VERSION 5.8 ;
BUSBITCHARS "[]" ;
DIVIDERCHAR "/" ;
UNITS
    DATABASE MICRONS 1000 ;
END UNITS

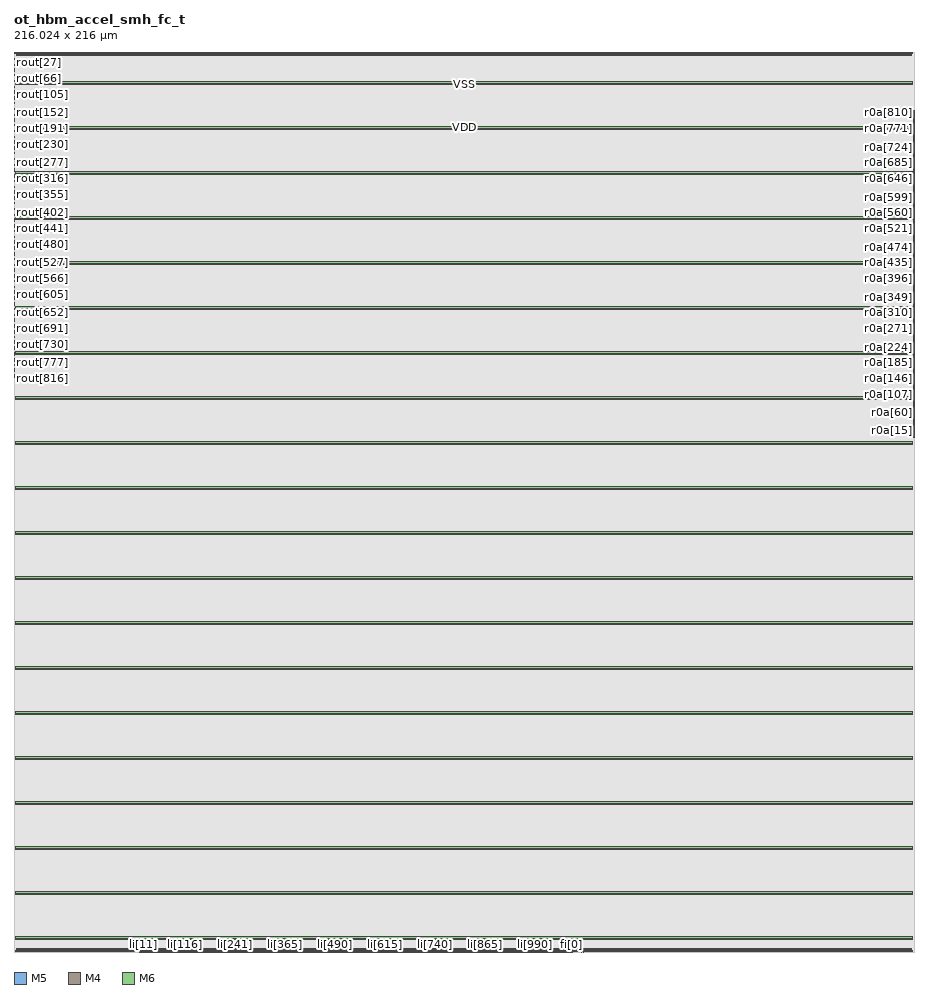
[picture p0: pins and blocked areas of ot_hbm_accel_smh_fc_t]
MACRO ot_hbm_accel_smh_fc_t
  FOREIGN ot_hbm_accel_smh_fc_t 0 0 ;
  CLASS BLOCK ;
  SIZE 216.024 BY 216 ;
  PIN clk
    DIRECTION INPUT ;
    USE SIGNAL ;
    PORT
      LAYER M5 ;
        RECT  136.128 0 136.152 0.192 ;
    END
  END clk
  PIN fi[0]
    DIRECTION INPUT ;
    USE SIGNAL ;
    PORT
      LAYER M5 ;
        RECT  133.872 0 133.896 0.192 ;
    END
  END fi[0]
  PIN fi[1]
    DIRECTION INPUT ;
    USE SIGNAL ;
    PORT
      LAYER M5 ;
        RECT  133.968 0 133.992 0.192 ;
    END
  END fi[1]
  PIN fi[2]
    DIRECTION INPUT ;
    USE SIGNAL ;
    PORT
      LAYER M5 ;
        RECT  134.064 0 134.088 0.192 ;
    END
  END fi[2]
  PIN li[0]
    DIRECTION INPUT ;
    USE SIGNAL ;
    PORT
      LAYER M5 ;
        RECT  30 0 30.024 0.192 ;
    END
  END li[0]
  PIN li[1000]
    DIRECTION INPUT ;
    USE SIGNAL ;
    PORT
      LAYER M5 ;
        RECT  126 0 126.024 0.192 ;
    END
  END li[1000]
  PIN li[1001]
    DIRECTION INPUT ;
    USE SIGNAL ;
    PORT
      LAYER M5 ;
        RECT  126.096 0 126.12 0.192 ;
    END
  END li[1001]
  PIN li[1002]
    DIRECTION INPUT ;
    USE SIGNAL ;
    PORT
      LAYER M5 ;
        RECT  126.192 0 126.216 0.192 ;
    END
  END li[1002]
  PIN li[1003]
    DIRECTION INPUT ;
    USE SIGNAL ;
    PORT
      LAYER M5 ;
        RECT  126.288 0 126.312 0.192 ;
    END
  END li[1003]
  PIN li[1004]
    DIRECTION INPUT ;
    USE SIGNAL ;
    PORT
      LAYER M5 ;
        RECT  126.384 0 126.408 0.192 ;
    END
  END li[1004]
  PIN li[1005]
    DIRECTION INPUT ;
    USE SIGNAL ;
    PORT
      LAYER M5 ;
        RECT  126.48 0 126.504 0.192 ;
    END
  END li[1005]
  PIN li[1006]
    DIRECTION INPUT ;
    USE SIGNAL ;
    PORT
      LAYER M5 ;
        RECT  126.576 0 126.6 0.192 ;
    END
  END li[1006]
  PIN li[1007]
    DIRECTION INPUT ;
    USE SIGNAL ;
    PORT
      LAYER M5 ;
        RECT  126.672 0 126.696 0.192 ;
    END
  END li[1007]
  PIN li[1008]
    DIRECTION INPUT ;
    USE SIGNAL ;
    PORT
      LAYER M5 ;
        RECT  126.768 0 126.792 0.192 ;
    END
  END li[1008]
  PIN li[1009]
    DIRECTION INPUT ;
    USE SIGNAL ;
    PORT
      LAYER M5 ;
        RECT  126.864 0 126.888 0.192 ;
    END
  END li[1009]
  PIN li[100]
    DIRECTION INPUT ;
    USE SIGNAL ;
    PORT
      LAYER M5 ;
        RECT  39.6 0 39.624 0.192 ;
    END
  END li[100]
  PIN li[1010]
    DIRECTION INPUT ;
    USE SIGNAL ;
    PORT
      LAYER M5 ;
        RECT  126.96 0 126.984 0.192 ;
    END
  END li[1010]
  PIN li[1011]
    DIRECTION INPUT ;
    USE SIGNAL ;
    PORT
      LAYER M5 ;
        RECT  127.056 0 127.08 0.192 ;
    END
  END li[1011]
  PIN li[1012]
    DIRECTION INPUT ;
    USE SIGNAL ;
    PORT
      LAYER M5 ;
        RECT  127.152 0 127.176 0.192 ;
    END
  END li[1012]
  PIN li[1013]
    DIRECTION INPUT ;
    USE SIGNAL ;
    PORT
      LAYER M5 ;
        RECT  127.248 0 127.272 0.192 ;
    END
  END li[1013]
  PIN li[1014]
    DIRECTION INPUT ;
    USE SIGNAL ;
    PORT
      LAYER M5 ;
        RECT  127.344 0 127.368 0.192 ;
    END
  END li[1014]
  PIN li[1015]
    DIRECTION INPUT ;
    USE SIGNAL ;
    PORT
      LAYER M5 ;
        RECT  127.44 0 127.464 0.192 ;
    END
  END li[1015]
  PIN li[1016]
    DIRECTION INPUT ;
    USE SIGNAL ;
    PORT
      LAYER M5 ;
        RECT  127.536 0 127.56 0.192 ;
    END
  END li[1016]
  PIN li[1017]
    DIRECTION INPUT ;
    USE SIGNAL ;
    PORT
      LAYER M5 ;
        RECT  127.632 0 127.656 0.192 ;
    END
  END li[1017]
  PIN li[1018]
    DIRECTION INPUT ;
    USE SIGNAL ;
    PORT
      LAYER M5 ;
        RECT  127.728 0 127.752 0.192 ;
    END
  END li[1018]
  PIN li[1019]
    DIRECTION INPUT ;
    USE SIGNAL ;
    PORT
      LAYER M5 ;
        RECT  127.824 0 127.848 0.192 ;
    END
  END li[1019]
  PIN li[101]
    DIRECTION INPUT ;
    USE SIGNAL ;
    PORT
      LAYER M5 ;
        RECT  39.696 0 39.72 0.192 ;
    END
  END li[101]
  PIN li[1020]
    DIRECTION INPUT ;
    USE SIGNAL ;
    PORT
      LAYER M5 ;
        RECT  127.92 0 127.944 0.192 ;
    END
  END li[1020]
  PIN li[1021]
    DIRECTION INPUT ;
    USE SIGNAL ;
    PORT
      LAYER M5 ;
        RECT  128.016 0 128.04 0.192 ;
    END
  END li[1021]
  PIN li[1022]
    DIRECTION INPUT ;
    USE SIGNAL ;
    PORT
      LAYER M5 ;
        RECT  128.112 0 128.136 0.192 ;
    END
  END li[1022]
  PIN li[1023]
    DIRECTION INPUT ;
    USE SIGNAL ;
    PORT
      LAYER M5 ;
        RECT  128.208 0 128.232 0.192 ;
    END
  END li[1023]
  PIN li[1024]
    DIRECTION INPUT ;
    USE SIGNAL ;
    PORT
      LAYER M5 ;
        RECT  128.304 0 128.328 0.192 ;
    END
  END li[1024]
  PIN li[1025]
    DIRECTION INPUT ;
    USE SIGNAL ;
    PORT
      LAYER M5 ;
        RECT  128.4 0 128.424 0.192 ;
    END
  END li[1025]
  PIN li[1026]
    DIRECTION INPUT ;
    USE SIGNAL ;
    PORT
      LAYER M5 ;
        RECT  128.496 0 128.52 0.192 ;
    END
  END li[1026]
  PIN li[1027]
    DIRECTION INPUT ;
    USE SIGNAL ;
    PORT
      LAYER M5 ;
        RECT  128.592 0 128.616 0.192 ;
    END
  END li[1027]
  PIN li[1028]
    DIRECTION INPUT ;
    USE SIGNAL ;
    PORT
      LAYER M5 ;
        RECT  128.688 0 128.712 0.192 ;
    END
  END li[1028]
  PIN li[1029]
    DIRECTION INPUT ;
    USE SIGNAL ;
    PORT
      LAYER M5 ;
        RECT  128.784 0 128.808 0.192 ;
    END
  END li[1029]
  PIN li[102]
    DIRECTION INPUT ;
    USE SIGNAL ;
    PORT
      LAYER M5 ;
        RECT  39.792 0 39.816 0.192 ;
    END
  END li[102]
  PIN li[1030]
    DIRECTION INPUT ;
    USE SIGNAL ;
    PORT
      LAYER M5 ;
        RECT  128.88 0 128.904 0.192 ;
    END
  END li[1030]
  PIN li[1031]
    DIRECTION INPUT ;
    USE SIGNAL ;
    PORT
      LAYER M5 ;
        RECT  128.976 0 129 0.192 ;
    END
  END li[1031]
  PIN li[1032]
    DIRECTION INPUT ;
    USE SIGNAL ;
    PORT
      LAYER M5 ;
        RECT  129.072 0 129.096 0.192 ;
    END
  END li[1032]
  PIN li[1033]
    DIRECTION INPUT ;
    USE SIGNAL ;
    PORT
      LAYER M5 ;
        RECT  129.168 0 129.192 0.192 ;
    END
  END li[1033]
  PIN li[1034]
    DIRECTION INPUT ;
    USE SIGNAL ;
    PORT
      LAYER M5 ;
        RECT  129.264 0 129.288 0.192 ;
    END
  END li[1034]
  PIN li[1035]
    DIRECTION INPUT ;
    USE SIGNAL ;
    PORT
      LAYER M5 ;
        RECT  129.36 0 129.384 0.192 ;
    END
  END li[1035]
  PIN li[1036]
    DIRECTION INPUT ;
    USE SIGNAL ;
    PORT
      LAYER M5 ;
        RECT  129.456 0 129.48 0.192 ;
    END
  END li[1036]
  PIN li[1037]
    DIRECTION INPUT ;
    USE SIGNAL ;
    PORT
      LAYER M5 ;
        RECT  129.552 0 129.576 0.192 ;
    END
  END li[1037]
  PIN li[1038]
    DIRECTION INPUT ;
    USE SIGNAL ;
    PORT
      LAYER M5 ;
        RECT  129.648 0 129.672 0.192 ;
    END
  END li[1038]
  PIN li[1039]
    DIRECTION INPUT ;
    USE SIGNAL ;
    PORT
      LAYER M5 ;
        RECT  129.744 0 129.768 0.192 ;
    END
  END li[1039]
  PIN li[103]
    DIRECTION INPUT ;
    USE SIGNAL ;
    PORT
      LAYER M5 ;
        RECT  39.888 0 39.912 0.192 ;
    END
  END li[103]
  PIN li[1040]
    DIRECTION INPUT ;
    USE SIGNAL ;
    PORT
      LAYER M5 ;
        RECT  129.84 0 129.864 0.192 ;
    END
  END li[1040]
  PIN li[1041]
    DIRECTION INPUT ;
    USE SIGNAL ;
    PORT
      LAYER M5 ;
        RECT  129.936 0 129.96 0.192 ;
    END
  END li[1041]
  PIN li[1042]
    DIRECTION INPUT ;
    USE SIGNAL ;
    PORT
      LAYER M5 ;
        RECT  130.032 0 130.056 0.192 ;
    END
  END li[1042]
  PIN li[1043]
    DIRECTION INPUT ;
    USE SIGNAL ;
    PORT
      LAYER M5 ;
        RECT  130.128 0 130.152 0.192 ;
    END
  END li[1043]
  PIN li[1044]
    DIRECTION INPUT ;
    USE SIGNAL ;
    PORT
      LAYER M5 ;
        RECT  130.224 0 130.248 0.192 ;
    END
  END li[1044]
  PIN li[1045]
    DIRECTION INPUT ;
    USE SIGNAL ;
    PORT
      LAYER M5 ;
        RECT  130.32 0 130.344 0.192 ;
    END
  END li[1045]
  PIN li[1046]
    DIRECTION INPUT ;
    USE SIGNAL ;
    PORT
      LAYER M5 ;
        RECT  130.416 0 130.44 0.192 ;
    END
  END li[1046]
  PIN li[1047]
    DIRECTION INPUT ;
    USE SIGNAL ;
    PORT
      LAYER M5 ;
        RECT  130.512 0 130.536 0.192 ;
    END
  END li[1047]
  PIN li[1048]
    DIRECTION INPUT ;
    USE SIGNAL ;
    PORT
      LAYER M5 ;
        RECT  130.608 0 130.632 0.192 ;
    END
  END li[1048]
  PIN li[1049]
    DIRECTION INPUT ;
    USE SIGNAL ;
    PORT
      LAYER M5 ;
        RECT  130.704 0 130.728 0.192 ;
    END
  END li[1049]
  PIN li[104]
    DIRECTION INPUT ;
    USE SIGNAL ;
    PORT
      LAYER M5 ;
        RECT  39.984 0 40.008 0.192 ;
    END
  END li[104]
  PIN li[1050]
    DIRECTION INPUT ;
    USE SIGNAL ;
    PORT
      LAYER M5 ;
        RECT  130.8 0 130.824 0.192 ;
    END
  END li[1050]
  PIN li[1051]
    DIRECTION INPUT ;
    USE SIGNAL ;
    PORT
      LAYER M5 ;
        RECT  130.896 0 130.92 0.192 ;
    END
  END li[1051]
  PIN li[1052]
    DIRECTION INPUT ;
    USE SIGNAL ;
    PORT
      LAYER M5 ;
        RECT  130.992 0 131.016 0.192 ;
    END
  END li[1052]
  PIN li[1053]
    DIRECTION INPUT ;
    USE SIGNAL ;
    PORT
      LAYER M5 ;
        RECT  131.088 0 131.112 0.192 ;
    END
  END li[1053]
  PIN li[1054]
    DIRECTION INPUT ;
    USE SIGNAL ;
    PORT
      LAYER M5 ;
        RECT  131.184 0 131.208 0.192 ;
    END
  END li[1054]
  PIN li[1055]
    DIRECTION INPUT ;
    USE SIGNAL ;
    PORT
      LAYER M5 ;
        RECT  131.28 0 131.304 0.192 ;
    END
  END li[1055]
  PIN li[1056]
    DIRECTION INPUT ;
    USE SIGNAL ;
    PORT
      LAYER M5 ;
        RECT  131.376 0 131.4 0.192 ;
    END
  END li[1056]
  PIN li[1057]
    DIRECTION INPUT ;
    USE SIGNAL ;
    PORT
      LAYER M5 ;
        RECT  131.472 0 131.496 0.192 ;
    END
  END li[1057]
  PIN li[1058]
    DIRECTION INPUT ;
    USE SIGNAL ;
    PORT
      LAYER M5 ;
        RECT  131.568 0 131.592 0.192 ;
    END
  END li[1058]
  PIN li[1059]
    DIRECTION INPUT ;
    USE SIGNAL ;
    PORT
      LAYER M5 ;
        RECT  131.664 0 131.688 0.192 ;
    END
  END li[1059]
  PIN li[105]
    DIRECTION INPUT ;
    USE SIGNAL ;
    PORT
      LAYER M5 ;
        RECT  40.08 0 40.104 0.192 ;
    END
  END li[105]
  PIN li[1060]
    DIRECTION INPUT ;
    USE SIGNAL ;
    PORT
      LAYER M5 ;
        RECT  131.76 0 131.784 0.192 ;
    END
  END li[1060]
  PIN li[1061]
    DIRECTION INPUT ;
    USE SIGNAL ;
    PORT
      LAYER M5 ;
        RECT  131.856 0 131.88 0.192 ;
    END
  END li[1061]
  PIN li[1062]
    DIRECTION INPUT ;
    USE SIGNAL ;
    PORT
      LAYER M5 ;
        RECT  131.952 0 131.976 0.192 ;
    END
  END li[1062]
  PIN li[1063]
    DIRECTION INPUT ;
    USE SIGNAL ;
    PORT
      LAYER M5 ;
        RECT  132.048 0 132.072 0.192 ;
    END
  END li[1063]
  PIN li[1064]
    DIRECTION INPUT ;
    USE SIGNAL ;
    PORT
      LAYER M5 ;
        RECT  132.144 0 132.168 0.192 ;
    END
  END li[1064]
  PIN li[1065]
    DIRECTION INPUT ;
    USE SIGNAL ;
    PORT
      LAYER M5 ;
        RECT  132.24 0 132.264 0.192 ;
    END
  END li[1065]
  PIN li[1066]
    DIRECTION INPUT ;
    USE SIGNAL ;
    PORT
      LAYER M5 ;
        RECT  132.336 0 132.36 0.192 ;
    END
  END li[1066]
  PIN li[1067]
    DIRECTION INPUT ;
    USE SIGNAL ;
    PORT
      LAYER M5 ;
        RECT  132.432 0 132.456 0.192 ;
    END
  END li[1067]
  PIN li[1068]
    DIRECTION INPUT ;
    USE SIGNAL ;
    PORT
      LAYER M5 ;
        RECT  132.528 0 132.552 0.192 ;
    END
  END li[1068]
  PIN li[1069]
    DIRECTION INPUT ;
    USE SIGNAL ;
    PORT
      LAYER M5 ;
        RECT  132.624 0 132.648 0.192 ;
    END
  END li[1069]
  PIN li[106]
    DIRECTION INPUT ;
    USE SIGNAL ;
    PORT
      LAYER M5 ;
        RECT  40.176 0 40.2 0.192 ;
    END
  END li[106]
  PIN li[1070]
    DIRECTION INPUT ;
    USE SIGNAL ;
    PORT
      LAYER M5 ;
        RECT  132.72 0 132.744 0.192 ;
    END
  END li[1070]
  PIN li[1071]
    DIRECTION INPUT ;
    USE SIGNAL ;
    PORT
      LAYER M5 ;
        RECT  132.816 0 132.84 0.192 ;
    END
  END li[1071]
  PIN li[1072]
    DIRECTION INPUT ;
    USE SIGNAL ;
    PORT
      LAYER M5 ;
        RECT  132.912 0 132.936 0.192 ;
    END
  END li[1072]
  PIN li[1073]
    DIRECTION INPUT ;
    USE SIGNAL ;
    PORT
      LAYER M5 ;
        RECT  133.008 0 133.032 0.192 ;
    END
  END li[1073]
  PIN li[1074]
    DIRECTION INPUT ;
    USE SIGNAL ;
    PORT
      LAYER M5 ;
        RECT  133.104 0 133.128 0.192 ;
    END
  END li[1074]
  PIN li[1075]
    DIRECTION INPUT ;
    USE SIGNAL ;
    PORT
      LAYER M5 ;
        RECT  133.2 0 133.224 0.192 ;
    END
  END li[1075]
  PIN li[1076]
    DIRECTION INPUT ;
    USE SIGNAL ;
    PORT
      LAYER M5 ;
        RECT  133.296 0 133.32 0.192 ;
    END
  END li[1076]
  PIN li[1077]
    DIRECTION INPUT ;
    USE SIGNAL ;
    PORT
      LAYER M5 ;
        RECT  133.392 0 133.416 0.192 ;
    END
  END li[1077]
  PIN li[1078]
    DIRECTION INPUT ;
    USE SIGNAL ;
    PORT
      LAYER M5 ;
        RECT  133.488 0 133.512 0.192 ;
    END
  END li[1078]
  PIN li[1079]
    DIRECTION INPUT ;
    USE SIGNAL ;
    PORT
      LAYER M5 ;
        RECT  133.584 0 133.608 0.192 ;
    END
  END li[1079]
  PIN li[107]
    DIRECTION INPUT ;
    USE SIGNAL ;
    PORT
      LAYER M5 ;
        RECT  40.272 0 40.296 0.192 ;
    END
  END li[107]
  PIN li[1080]
    DIRECTION INPUT ;
    USE SIGNAL ;
    PORT
      LAYER M5 ;
        RECT  133.68 0 133.704 0.192 ;
    END
  END li[1080]
  PIN li[1081]
    DIRECTION INPUT ;
    USE SIGNAL ;
    PORT
      LAYER M5 ;
        RECT  133.776 0 133.8 0.192 ;
    END
  END li[1081]
  PIN li[108]
    DIRECTION INPUT ;
    USE SIGNAL ;
    PORT
      LAYER M5 ;
        RECT  40.368 0 40.392 0.192 ;
    END
  END li[108]
  PIN li[109]
    DIRECTION INPUT ;
    USE SIGNAL ;
    PORT
      LAYER M5 ;
        RECT  40.464 0 40.488 0.192 ;
    END
  END li[109]
  PIN li[10]
    DIRECTION INPUT ;
    USE SIGNAL ;
    PORT
      LAYER M5 ;
        RECT  30.96 0 30.984 0.192 ;
    END
  END li[10]
  PIN li[110]
    DIRECTION INPUT ;
    USE SIGNAL ;
    PORT
      LAYER M5 ;
        RECT  40.56 0 40.584 0.192 ;
    END
  END li[110]
  PIN li[111]
    DIRECTION INPUT ;
    USE SIGNAL ;
    PORT
      LAYER M5 ;
        RECT  40.656 0 40.68 0.192 ;
    END
  END li[111]
  PIN li[112]
    DIRECTION INPUT ;
    USE SIGNAL ;
    PORT
      LAYER M5 ;
        RECT  40.752 0 40.776 0.192 ;
    END
  END li[112]
  PIN li[113]
    DIRECTION INPUT ;
    USE SIGNAL ;
    PORT
      LAYER M5 ;
        RECT  40.848 0 40.872 0.192 ;
    END
  END li[113]
  PIN li[114]
    DIRECTION INPUT ;
    USE SIGNAL ;
    PORT
      LAYER M5 ;
        RECT  40.944 0 40.968 0.192 ;
    END
  END li[114]
  PIN li[115]
    DIRECTION INPUT ;
    USE SIGNAL ;
    PORT
      LAYER M5 ;
        RECT  41.04 0 41.064 0.192 ;
    END
  END li[115]
  PIN li[116]
    DIRECTION INPUT ;
    USE SIGNAL ;
    PORT
      LAYER M5 ;
        RECT  41.136 0 41.16 0.192 ;
    END
  END li[116]
  PIN li[117]
    DIRECTION INPUT ;
    USE SIGNAL ;
    PORT
      LAYER M5 ;
        RECT  41.232 0 41.256 0.192 ;
    END
  END li[117]
  PIN li[118]
    DIRECTION INPUT ;
    USE SIGNAL ;
    PORT
      LAYER M5 ;
        RECT  41.328 0 41.352 0.192 ;
    END
  END li[118]
  PIN li[119]
    DIRECTION INPUT ;
    USE SIGNAL ;
    PORT
      LAYER M5 ;
        RECT  41.424 0 41.448 0.192 ;
    END
  END li[119]
  PIN li[11]
    DIRECTION INPUT ;
    USE SIGNAL ;
    PORT
      LAYER M5 ;
        RECT  31.056 0 31.08 0.192 ;
    END
  END li[11]
  PIN li[120]
    DIRECTION INPUT ;
    USE SIGNAL ;
    PORT
      LAYER M5 ;
        RECT  41.52 0 41.544 0.192 ;
    END
  END li[120]
  PIN li[121]
    DIRECTION INPUT ;
    USE SIGNAL ;
    PORT
      LAYER M5 ;
        RECT  41.616 0 41.64 0.192 ;
    END
  END li[121]
  PIN li[122]
    DIRECTION INPUT ;
    USE SIGNAL ;
    PORT
      LAYER M5 ;
        RECT  41.712 0 41.736 0.192 ;
    END
  END li[122]
  PIN li[123]
    DIRECTION INPUT ;
    USE SIGNAL ;
    PORT
      LAYER M5 ;
        RECT  41.808 0 41.832 0.192 ;
    END
  END li[123]
  PIN li[124]
    DIRECTION INPUT ;
    USE SIGNAL ;
    PORT
      LAYER M5 ;
        RECT  41.904 0 41.928 0.192 ;
    END
  END li[124]
  PIN li[125]
    DIRECTION INPUT ;
    USE SIGNAL ;
    PORT
      LAYER M5 ;
        RECT  42 0 42.024 0.192 ;
    END
  END li[125]
  PIN li[126]
    DIRECTION INPUT ;
    USE SIGNAL ;
    PORT
      LAYER M5 ;
        RECT  42.096 0 42.12 0.192 ;
    END
  END li[126]
  PIN li[127]
    DIRECTION INPUT ;
    USE SIGNAL ;
    PORT
      LAYER M5 ;
        RECT  42.192 0 42.216 0.192 ;
    END
  END li[127]
  PIN li[128]
    DIRECTION INPUT ;
    USE SIGNAL ;
    PORT
      LAYER M5 ;
        RECT  42.288 0 42.312 0.192 ;
    END
  END li[128]
  PIN li[129]
    DIRECTION INPUT ;
    USE SIGNAL ;
    PORT
      LAYER M5 ;
        RECT  42.384 0 42.408 0.192 ;
    END
  END li[129]
  PIN li[12]
    DIRECTION INPUT ;
    USE SIGNAL ;
    PORT
      LAYER M5 ;
        RECT  31.152 0 31.176 0.192 ;
    END
  END li[12]
  PIN li[130]
    DIRECTION INPUT ;
    USE SIGNAL ;
    PORT
      LAYER M5 ;
        RECT  42.48 0 42.504 0.192 ;
    END
  END li[130]
  PIN li[131]
    DIRECTION INPUT ;
    USE SIGNAL ;
    PORT
      LAYER M5 ;
        RECT  42.576 0 42.6 0.192 ;
    END
  END li[131]
  PIN li[132]
    DIRECTION INPUT ;
    USE SIGNAL ;
    PORT
      LAYER M5 ;
        RECT  42.672 0 42.696 0.192 ;
    END
  END li[132]
  PIN li[133]
    DIRECTION INPUT ;
    USE SIGNAL ;
    PORT
      LAYER M5 ;
        RECT  42.768 0 42.792 0.192 ;
    END
  END li[133]
  PIN li[134]
    DIRECTION INPUT ;
    USE SIGNAL ;
    PORT
      LAYER M5 ;
        RECT  42.864 0 42.888 0.192 ;
    END
  END li[134]
  PIN li[135]
    DIRECTION INPUT ;
    USE SIGNAL ;
    PORT
      LAYER M5 ;
        RECT  42.96 0 42.984 0.192 ;
    END
  END li[135]
  PIN li[136]
    DIRECTION INPUT ;
    USE SIGNAL ;
    PORT
      LAYER M5 ;
        RECT  43.056 0 43.08 0.192 ;
    END
  END li[136]
  PIN li[137]
    DIRECTION INPUT ;
    USE SIGNAL ;
    PORT
      LAYER M5 ;
        RECT  43.152 0 43.176 0.192 ;
    END
  END li[137]
  PIN li[138]
    DIRECTION INPUT ;
    USE SIGNAL ;
    PORT
      LAYER M5 ;
        RECT  43.248 0 43.272 0.192 ;
    END
  END li[138]
  PIN li[139]
    DIRECTION INPUT ;
    USE SIGNAL ;
    PORT
      LAYER M5 ;
        RECT  43.344 0 43.368 0.192 ;
    END
  END li[139]
  PIN li[13]
    DIRECTION INPUT ;
    USE SIGNAL ;
    PORT
      LAYER M5 ;
        RECT  31.248 0 31.272 0.192 ;
    END
  END li[13]
  PIN li[140]
    DIRECTION INPUT ;
    USE SIGNAL ;
    PORT
      LAYER M5 ;
        RECT  43.44 0 43.464 0.192 ;
    END
  END li[140]
  PIN li[141]
    DIRECTION INPUT ;
    USE SIGNAL ;
    PORT
      LAYER M5 ;
        RECT  43.536 0 43.56 0.192 ;
    END
  END li[141]
  PIN li[142]
    DIRECTION INPUT ;
    USE SIGNAL ;
    PORT
      LAYER M5 ;
        RECT  43.632 0 43.656 0.192 ;
    END
  END li[142]
  PIN li[143]
    DIRECTION INPUT ;
    USE SIGNAL ;
    PORT
      LAYER M5 ;
        RECT  43.728 0 43.752 0.192 ;
    END
  END li[143]
  PIN li[144]
    DIRECTION INPUT ;
    USE SIGNAL ;
    PORT
      LAYER M5 ;
        RECT  43.824 0 43.848 0.192 ;
    END
  END li[144]
  PIN li[145]
    DIRECTION INPUT ;
    USE SIGNAL ;
    PORT
      LAYER M5 ;
        RECT  43.92 0 43.944 0.192 ;
    END
  END li[145]
  PIN li[146]
    DIRECTION INPUT ;
    USE SIGNAL ;
    PORT
      LAYER M5 ;
        RECT  44.016 0 44.04 0.192 ;
    END
  END li[146]
  PIN li[147]
    DIRECTION INPUT ;
    USE SIGNAL ;
    PORT
      LAYER M5 ;
        RECT  44.112 0 44.136 0.192 ;
    END
  END li[147]
  PIN li[148]
    DIRECTION INPUT ;
    USE SIGNAL ;
    PORT
      LAYER M5 ;
        RECT  44.208 0 44.232 0.192 ;
    END
  END li[148]
  PIN li[149]
    DIRECTION INPUT ;
    USE SIGNAL ;
    PORT
      LAYER M5 ;
        RECT  44.304 0 44.328 0.192 ;
    END
  END li[149]
  PIN li[14]
    DIRECTION INPUT ;
    USE SIGNAL ;
    PORT
      LAYER M5 ;
        RECT  31.344 0 31.368 0.192 ;
    END
  END li[14]
  PIN li[150]
    DIRECTION INPUT ;
    USE SIGNAL ;
    PORT
      LAYER M5 ;
        RECT  44.4 0 44.424 0.192 ;
    END
  END li[150]
  PIN li[151]
    DIRECTION INPUT ;
    USE SIGNAL ;
    PORT
      LAYER M5 ;
        RECT  44.496 0 44.52 0.192 ;
    END
  END li[151]
  PIN li[152]
    DIRECTION INPUT ;
    USE SIGNAL ;
    PORT
      LAYER M5 ;
        RECT  44.592 0 44.616 0.192 ;
    END
  END li[152]
  PIN li[153]
    DIRECTION INPUT ;
    USE SIGNAL ;
    PORT
      LAYER M5 ;
        RECT  44.688 0 44.712 0.192 ;
    END
  END li[153]
  PIN li[154]
    DIRECTION INPUT ;
    USE SIGNAL ;
    PORT
      LAYER M5 ;
        RECT  44.784 0 44.808 0.192 ;
    END
  END li[154]
  PIN li[155]
    DIRECTION INPUT ;
    USE SIGNAL ;
    PORT
      LAYER M5 ;
        RECT  44.88 0 44.904 0.192 ;
    END
  END li[155]
  PIN li[156]
    DIRECTION INPUT ;
    USE SIGNAL ;
    PORT
      LAYER M5 ;
        RECT  44.976 0 45 0.192 ;
    END
  END li[156]
  PIN li[157]
    DIRECTION INPUT ;
    USE SIGNAL ;
    PORT
      LAYER M5 ;
        RECT  45.072 0 45.096 0.192 ;
    END
  END li[157]
  PIN li[158]
    DIRECTION INPUT ;
    USE SIGNAL ;
    PORT
      LAYER M5 ;
        RECT  45.168 0 45.192 0.192 ;
    END
  END li[158]
  PIN li[159]
    DIRECTION INPUT ;
    USE SIGNAL ;
    PORT
      LAYER M5 ;
        RECT  45.264 0 45.288 0.192 ;
    END
  END li[159]
  PIN li[15]
    DIRECTION INPUT ;
    USE SIGNAL ;
    PORT
      LAYER M5 ;
        RECT  31.44 0 31.464 0.192 ;
    END
  END li[15]
  PIN li[160]
    DIRECTION INPUT ;
    USE SIGNAL ;
    PORT
      LAYER M5 ;
        RECT  45.36 0 45.384 0.192 ;
    END
  END li[160]
  PIN li[161]
    DIRECTION INPUT ;
    USE SIGNAL ;
    PORT
      LAYER M5 ;
        RECT  45.456 0 45.48 0.192 ;
    END
  END li[161]
  PIN li[162]
    DIRECTION INPUT ;
    USE SIGNAL ;
    PORT
      LAYER M5 ;
        RECT  45.552 0 45.576 0.192 ;
    END
  END li[162]
  PIN li[163]
    DIRECTION INPUT ;
    USE SIGNAL ;
    PORT
      LAYER M5 ;
        RECT  45.648 0 45.672 0.192 ;
    END
  END li[163]
  PIN li[164]
    DIRECTION INPUT ;
    USE SIGNAL ;
    PORT
      LAYER M5 ;
        RECT  45.744 0 45.768 0.192 ;
    END
  END li[164]
  PIN li[165]
    DIRECTION INPUT ;
    USE SIGNAL ;
    PORT
      LAYER M5 ;
        RECT  45.84 0 45.864 0.192 ;
    END
  END li[165]
  PIN li[166]
    DIRECTION INPUT ;
    USE SIGNAL ;
    PORT
      LAYER M5 ;
        RECT  45.936 0 45.96 0.192 ;
    END
  END li[166]
  PIN li[167]
    DIRECTION INPUT ;
    USE SIGNAL ;
    PORT
      LAYER M5 ;
        RECT  46.032 0 46.056 0.192 ;
    END
  END li[167]
  PIN li[168]
    DIRECTION INPUT ;
    USE SIGNAL ;
    PORT
      LAYER M5 ;
        RECT  46.128 0 46.152 0.192 ;
    END
  END li[168]
  PIN li[169]
    DIRECTION INPUT ;
    USE SIGNAL ;
    PORT
      LAYER M5 ;
        RECT  46.224 0 46.248 0.192 ;
    END
  END li[169]
  PIN li[16]
    DIRECTION INPUT ;
    USE SIGNAL ;
    PORT
      LAYER M5 ;
        RECT  31.536 0 31.56 0.192 ;
    END
  END li[16]
  PIN li[170]
    DIRECTION INPUT ;
    USE SIGNAL ;
    PORT
      LAYER M5 ;
        RECT  46.32 0 46.344 0.192 ;
    END
  END li[170]
  PIN li[171]
    DIRECTION INPUT ;
    USE SIGNAL ;
    PORT
      LAYER M5 ;
        RECT  46.416 0 46.44 0.192 ;
    END
  END li[171]
  PIN li[172]
    DIRECTION INPUT ;
    USE SIGNAL ;
    PORT
      LAYER M5 ;
        RECT  46.512 0 46.536 0.192 ;
    END
  END li[172]
  PIN li[173]
    DIRECTION INPUT ;
    USE SIGNAL ;
    PORT
      LAYER M5 ;
        RECT  46.608 0 46.632 0.192 ;
    END
  END li[173]
  PIN li[174]
    DIRECTION INPUT ;
    USE SIGNAL ;
    PORT
      LAYER M5 ;
        RECT  46.704 0 46.728 0.192 ;
    END
  END li[174]
  PIN li[175]
    DIRECTION INPUT ;
    USE SIGNAL ;
    PORT
      LAYER M5 ;
        RECT  46.8 0 46.824 0.192 ;
    END
  END li[175]
  PIN li[176]
    DIRECTION INPUT ;
    USE SIGNAL ;
    PORT
      LAYER M5 ;
        RECT  46.896 0 46.92 0.192 ;
    END
  END li[176]
  PIN li[177]
    DIRECTION INPUT ;
    USE SIGNAL ;
    PORT
      LAYER M5 ;
        RECT  46.992 0 47.016 0.192 ;
    END
  END li[177]
  PIN li[178]
    DIRECTION INPUT ;
    USE SIGNAL ;
    PORT
      LAYER M5 ;
        RECT  47.088 0 47.112 0.192 ;
    END
  END li[178]
  PIN li[179]
    DIRECTION INPUT ;
    USE SIGNAL ;
    PORT
      LAYER M5 ;
        RECT  47.184 0 47.208 0.192 ;
    END
  END li[179]
  PIN li[17]
    DIRECTION INPUT ;
    USE SIGNAL ;
    PORT
      LAYER M5 ;
        RECT  31.632 0 31.656 0.192 ;
    END
  END li[17]
  PIN li[180]
    DIRECTION INPUT ;
    USE SIGNAL ;
    PORT
      LAYER M5 ;
        RECT  47.28 0 47.304 0.192 ;
    END
  END li[180]
  PIN li[181]
    DIRECTION INPUT ;
    USE SIGNAL ;
    PORT
      LAYER M5 ;
        RECT  47.376 0 47.4 0.192 ;
    END
  END li[181]
  PIN li[182]
    DIRECTION INPUT ;
    USE SIGNAL ;
    PORT
      LAYER M5 ;
        RECT  47.472 0 47.496 0.192 ;
    END
  END li[182]
  PIN li[183]
    DIRECTION INPUT ;
    USE SIGNAL ;
    PORT
      LAYER M5 ;
        RECT  47.568 0 47.592 0.192 ;
    END
  END li[183]
  PIN li[184]
    DIRECTION INPUT ;
    USE SIGNAL ;
    PORT
      LAYER M5 ;
        RECT  47.664 0 47.688 0.192 ;
    END
  END li[184]
  PIN li[185]
    DIRECTION INPUT ;
    USE SIGNAL ;
    PORT
      LAYER M5 ;
        RECT  47.76 0 47.784 0.192 ;
    END
  END li[185]
  PIN li[186]
    DIRECTION INPUT ;
    USE SIGNAL ;
    PORT
      LAYER M5 ;
        RECT  47.856 0 47.88 0.192 ;
    END
  END li[186]
  PIN li[187]
    DIRECTION INPUT ;
    USE SIGNAL ;
    PORT
      LAYER M5 ;
        RECT  47.952 0 47.976 0.192 ;
    END
  END li[187]
  PIN li[188]
    DIRECTION INPUT ;
    USE SIGNAL ;
    PORT
      LAYER M5 ;
        RECT  48.048 0 48.072 0.192 ;
    END
  END li[188]
  PIN li[189]
    DIRECTION INPUT ;
    USE SIGNAL ;
    PORT
      LAYER M5 ;
        RECT  48.144 0 48.168 0.192 ;
    END
  END li[189]
  PIN li[18]
    DIRECTION INPUT ;
    USE SIGNAL ;
    PORT
      LAYER M5 ;
        RECT  31.728 0 31.752 0.192 ;
    END
  END li[18]
  PIN li[190]
    DIRECTION INPUT ;
    USE SIGNAL ;
    PORT
      LAYER M5 ;
        RECT  48.24 0 48.264 0.192 ;
    END
  END li[190]
  PIN li[191]
    DIRECTION INPUT ;
    USE SIGNAL ;
    PORT
      LAYER M5 ;
        RECT  48.336 0 48.36 0.192 ;
    END
  END li[191]
  PIN li[192]
    DIRECTION INPUT ;
    USE SIGNAL ;
    PORT
      LAYER M5 ;
        RECT  48.432 0 48.456 0.192 ;
    END
  END li[192]
  PIN li[193]
    DIRECTION INPUT ;
    USE SIGNAL ;
    PORT
      LAYER M5 ;
        RECT  48.528 0 48.552 0.192 ;
    END
  END li[193]
  PIN li[194]
    DIRECTION INPUT ;
    USE SIGNAL ;
    PORT
      LAYER M5 ;
        RECT  48.624 0 48.648 0.192 ;
    END
  END li[194]
  PIN li[195]
    DIRECTION INPUT ;
    USE SIGNAL ;
    PORT
      LAYER M5 ;
        RECT  48.72 0 48.744 0.192 ;
    END
  END li[195]
  PIN li[196]
    DIRECTION INPUT ;
    USE SIGNAL ;
    PORT
      LAYER M5 ;
        RECT  48.816 0 48.84 0.192 ;
    END
  END li[196]
  PIN li[197]
    DIRECTION INPUT ;
    USE SIGNAL ;
    PORT
      LAYER M5 ;
        RECT  48.912 0 48.936 0.192 ;
    END
  END li[197]
  PIN li[198]
    DIRECTION INPUT ;
    USE SIGNAL ;
    PORT
      LAYER M5 ;
        RECT  49.008 0 49.032 0.192 ;
    END
  END li[198]
  PIN li[199]
    DIRECTION INPUT ;
    USE SIGNAL ;
    PORT
      LAYER M5 ;
        RECT  49.104 0 49.128 0.192 ;
    END
  END li[199]
  PIN li[19]
    DIRECTION INPUT ;
    USE SIGNAL ;
    PORT
      LAYER M5 ;
        RECT  31.824 0 31.848 0.192 ;
    END
  END li[19]
  PIN li[1]
    DIRECTION INPUT ;
    USE SIGNAL ;
    PORT
      LAYER M5 ;
        RECT  30.096 0 30.12 0.192 ;
    END
  END li[1]
  PIN li[200]
    DIRECTION INPUT ;
    USE SIGNAL ;
    PORT
      LAYER M5 ;
        RECT  49.2 0 49.224 0.192 ;
    END
  END li[200]
  PIN li[201]
    DIRECTION INPUT ;
    USE SIGNAL ;
    PORT
      LAYER M5 ;
        RECT  49.296 0 49.32 0.192 ;
    END
  END li[201]
  PIN li[202]
    DIRECTION INPUT ;
    USE SIGNAL ;
    PORT
      LAYER M5 ;
        RECT  49.392 0 49.416 0.192 ;
    END
  END li[202]
  PIN li[203]
    DIRECTION INPUT ;
    USE SIGNAL ;
    PORT
      LAYER M5 ;
        RECT  49.488 0 49.512 0.192 ;
    END
  END li[203]
  PIN li[204]
    DIRECTION INPUT ;
    USE SIGNAL ;
    PORT
      LAYER M5 ;
        RECT  49.584 0 49.608 0.192 ;
    END
  END li[204]
  PIN li[205]
    DIRECTION INPUT ;
    USE SIGNAL ;
    PORT
      LAYER M5 ;
        RECT  49.68 0 49.704 0.192 ;
    END
  END li[205]
  PIN li[206]
    DIRECTION INPUT ;
    USE SIGNAL ;
    PORT
      LAYER M5 ;
        RECT  49.776 0 49.8 0.192 ;
    END
  END li[206]
  PIN li[207]
    DIRECTION INPUT ;
    USE SIGNAL ;
    PORT
      LAYER M5 ;
        RECT  49.872 0 49.896 0.192 ;
    END
  END li[207]
  PIN li[208]
    DIRECTION INPUT ;
    USE SIGNAL ;
    PORT
      LAYER M5 ;
        RECT  49.968 0 49.992 0.192 ;
    END
  END li[208]
  PIN li[209]
    DIRECTION INPUT ;
    USE SIGNAL ;
    PORT
      LAYER M5 ;
        RECT  50.064 0 50.088 0.192 ;
    END
  END li[209]
  PIN li[20]
    DIRECTION INPUT ;
    USE SIGNAL ;
    PORT
      LAYER M5 ;
        RECT  31.92 0 31.944 0.192 ;
    END
  END li[20]
  PIN li[210]
    DIRECTION INPUT ;
    USE SIGNAL ;
    PORT
      LAYER M5 ;
        RECT  50.16 0 50.184 0.192 ;
    END
  END li[210]
  PIN li[211]
    DIRECTION INPUT ;
    USE SIGNAL ;
    PORT
      LAYER M5 ;
        RECT  50.256 0 50.28 0.192 ;
    END
  END li[211]
  PIN li[212]
    DIRECTION INPUT ;
    USE SIGNAL ;
    PORT
      LAYER M5 ;
        RECT  50.352 0 50.376 0.192 ;
    END
  END li[212]
  PIN li[213]
    DIRECTION INPUT ;
    USE SIGNAL ;
    PORT
      LAYER M5 ;
        RECT  50.448 0 50.472 0.192 ;
    END
  END li[213]
  PIN li[214]
    DIRECTION INPUT ;
    USE SIGNAL ;
    PORT
      LAYER M5 ;
        RECT  50.544 0 50.568 0.192 ;
    END
  END li[214]
  PIN li[215]
    DIRECTION INPUT ;
    USE SIGNAL ;
    PORT
      LAYER M5 ;
        RECT  50.64 0 50.664 0.192 ;
    END
  END li[215]
  PIN li[216]
    DIRECTION INPUT ;
    USE SIGNAL ;
    PORT
      LAYER M5 ;
        RECT  50.736 0 50.76 0.192 ;
    END
  END li[216]
  PIN li[217]
    DIRECTION INPUT ;
    USE SIGNAL ;
    PORT
      LAYER M5 ;
        RECT  50.832 0 50.856 0.192 ;
    END
  END li[217]
  PIN li[218]
    DIRECTION INPUT ;
    USE SIGNAL ;
    PORT
      LAYER M5 ;
        RECT  50.928 0 50.952 0.192 ;
    END
  END li[218]
  PIN li[219]
    DIRECTION INPUT ;
    USE SIGNAL ;
    PORT
      LAYER M5 ;
        RECT  51.024 0 51.048 0.192 ;
    END
  END li[219]
  PIN li[21]
    DIRECTION INPUT ;
    USE SIGNAL ;
    PORT
      LAYER M5 ;
        RECT  32.016 0 32.04 0.192 ;
    END
  END li[21]
  PIN li[220]
    DIRECTION INPUT ;
    USE SIGNAL ;
    PORT
      LAYER M5 ;
        RECT  51.12 0 51.144 0.192 ;
    END
  END li[220]
  PIN li[221]
    DIRECTION INPUT ;
    USE SIGNAL ;
    PORT
      LAYER M5 ;
        RECT  51.216 0 51.24 0.192 ;
    END
  END li[221]
  PIN li[222]
    DIRECTION INPUT ;
    USE SIGNAL ;
    PORT
      LAYER M5 ;
        RECT  51.312 0 51.336 0.192 ;
    END
  END li[222]
  PIN li[223]
    DIRECTION INPUT ;
    USE SIGNAL ;
    PORT
      LAYER M5 ;
        RECT  51.408 0 51.432 0.192 ;
    END
  END li[223]
  PIN li[224]
    DIRECTION INPUT ;
    USE SIGNAL ;
    PORT
      LAYER M5 ;
        RECT  51.504 0 51.528 0.192 ;
    END
  END li[224]
  PIN li[225]
    DIRECTION INPUT ;
    USE SIGNAL ;
    PORT
      LAYER M5 ;
        RECT  51.6 0 51.624 0.192 ;
    END
  END li[225]
  PIN li[226]
    DIRECTION INPUT ;
    USE SIGNAL ;
    PORT
      LAYER M5 ;
        RECT  51.696 0 51.72 0.192 ;
    END
  END li[226]
  PIN li[227]
    DIRECTION INPUT ;
    USE SIGNAL ;
    PORT
      LAYER M5 ;
        RECT  51.792 0 51.816 0.192 ;
    END
  END li[227]
  PIN li[228]
    DIRECTION INPUT ;
    USE SIGNAL ;
    PORT
      LAYER M5 ;
        RECT  51.888 0 51.912 0.192 ;
    END
  END li[228]
  PIN li[229]
    DIRECTION INPUT ;
    USE SIGNAL ;
    PORT
      LAYER M5 ;
        RECT  51.984 0 52.008 0.192 ;
    END
  END li[229]
  PIN li[22]
    DIRECTION INPUT ;
    USE SIGNAL ;
    PORT
      LAYER M5 ;
        RECT  32.112 0 32.136 0.192 ;
    END
  END li[22]
  PIN li[230]
    DIRECTION INPUT ;
    USE SIGNAL ;
    PORT
      LAYER M5 ;
        RECT  52.08 0 52.104 0.192 ;
    END
  END li[230]
  PIN li[231]
    DIRECTION INPUT ;
    USE SIGNAL ;
    PORT
      LAYER M5 ;
        RECT  52.176 0 52.2 0.192 ;
    END
  END li[231]
  PIN li[232]
    DIRECTION INPUT ;
    USE SIGNAL ;
    PORT
      LAYER M5 ;
        RECT  52.272 0 52.296 0.192 ;
    END
  END li[232]
  PIN li[233]
    DIRECTION INPUT ;
    USE SIGNAL ;
    PORT
      LAYER M5 ;
        RECT  52.368 0 52.392 0.192 ;
    END
  END li[233]
  PIN li[234]
    DIRECTION INPUT ;
    USE SIGNAL ;
    PORT
      LAYER M5 ;
        RECT  52.464 0 52.488 0.192 ;
    END
  END li[234]
  PIN li[235]
    DIRECTION INPUT ;
    USE SIGNAL ;
    PORT
      LAYER M5 ;
        RECT  52.56 0 52.584 0.192 ;
    END
  END li[235]
  PIN li[236]
    DIRECTION INPUT ;
    USE SIGNAL ;
    PORT
      LAYER M5 ;
        RECT  52.656 0 52.68 0.192 ;
    END
  END li[236]
  PIN li[237]
    DIRECTION INPUT ;
    USE SIGNAL ;
    PORT
      LAYER M5 ;
        RECT  52.752 0 52.776 0.192 ;
    END
  END li[237]
  PIN li[238]
    DIRECTION INPUT ;
    USE SIGNAL ;
    PORT
      LAYER M5 ;
        RECT  52.848 0 52.872 0.192 ;
    END
  END li[238]
  PIN li[239]
    DIRECTION INPUT ;
    USE SIGNAL ;
    PORT
      LAYER M5 ;
        RECT  52.944 0 52.968 0.192 ;
    END
  END li[239]
  PIN li[23]
    DIRECTION INPUT ;
    USE SIGNAL ;
    PORT
      LAYER M5 ;
        RECT  32.208 0 32.232 0.192 ;
    END
  END li[23]
  PIN li[240]
    DIRECTION INPUT ;
    USE SIGNAL ;
    PORT
      LAYER M5 ;
        RECT  53.04 0 53.064 0.192 ;
    END
  END li[240]
  PIN li[241]
    DIRECTION INPUT ;
    USE SIGNAL ;
    PORT
      LAYER M5 ;
        RECT  53.136 0 53.16 0.192 ;
    END
  END li[241]
  PIN li[242]
    DIRECTION INPUT ;
    USE SIGNAL ;
    PORT
      LAYER M5 ;
        RECT  53.232 0 53.256 0.192 ;
    END
  END li[242]
  PIN li[243]
    DIRECTION INPUT ;
    USE SIGNAL ;
    PORT
      LAYER M5 ;
        RECT  53.328 0 53.352 0.192 ;
    END
  END li[243]
  PIN li[244]
    DIRECTION INPUT ;
    USE SIGNAL ;
    PORT
      LAYER M5 ;
        RECT  53.424 0 53.448 0.192 ;
    END
  END li[244]
  PIN li[245]
    DIRECTION INPUT ;
    USE SIGNAL ;
    PORT
      LAYER M5 ;
        RECT  53.52 0 53.544 0.192 ;
    END
  END li[245]
  PIN li[246]
    DIRECTION INPUT ;
    USE SIGNAL ;
    PORT
      LAYER M5 ;
        RECT  53.616 0 53.64 0.192 ;
    END
  END li[246]
  PIN li[247]
    DIRECTION INPUT ;
    USE SIGNAL ;
    PORT
      LAYER M5 ;
        RECT  53.712 0 53.736 0.192 ;
    END
  END li[247]
  PIN li[248]
    DIRECTION INPUT ;
    USE SIGNAL ;
    PORT
      LAYER M5 ;
        RECT  53.808 0 53.832 0.192 ;
    END
  END li[248]
  PIN li[249]
    DIRECTION INPUT ;
    USE SIGNAL ;
    PORT
      LAYER M5 ;
        RECT  53.904 0 53.928 0.192 ;
    END
  END li[249]
  PIN li[24]
    DIRECTION INPUT ;
    USE SIGNAL ;
    PORT
      LAYER M5 ;
        RECT  32.304 0 32.328 0.192 ;
    END
  END li[24]
  PIN li[250]
    DIRECTION INPUT ;
    USE SIGNAL ;
    PORT
      LAYER M5 ;
        RECT  54 0 54.024 0.192 ;
    END
  END li[250]
  PIN li[251]
    DIRECTION INPUT ;
    USE SIGNAL ;
    PORT
      LAYER M5 ;
        RECT  54.096 0 54.12 0.192 ;
    END
  END li[251]
  PIN li[252]
    DIRECTION INPUT ;
    USE SIGNAL ;
    PORT
      LAYER M5 ;
        RECT  54.192 0 54.216 0.192 ;
    END
  END li[252]
  PIN li[253]
    DIRECTION INPUT ;
    USE SIGNAL ;
    PORT
      LAYER M5 ;
        RECT  54.288 0 54.312 0.192 ;
    END
  END li[253]
  PIN li[254]
    DIRECTION INPUT ;
    USE SIGNAL ;
    PORT
      LAYER M5 ;
        RECT  54.384 0 54.408 0.192 ;
    END
  END li[254]
  PIN li[255]
    DIRECTION INPUT ;
    USE SIGNAL ;
    PORT
      LAYER M5 ;
        RECT  54.48 0 54.504 0.192 ;
    END
  END li[255]
  PIN li[256]
    DIRECTION INPUT ;
    USE SIGNAL ;
    PORT
      LAYER M5 ;
        RECT  54.576 0 54.6 0.192 ;
    END
  END li[256]
  PIN li[257]
    DIRECTION INPUT ;
    USE SIGNAL ;
    PORT
      LAYER M5 ;
        RECT  54.672 0 54.696 0.192 ;
    END
  END li[257]
  PIN li[258]
    DIRECTION INPUT ;
    USE SIGNAL ;
    PORT
      LAYER M5 ;
        RECT  54.768 0 54.792 0.192 ;
    END
  END li[258]
  PIN li[259]
    DIRECTION INPUT ;
    USE SIGNAL ;
    PORT
      LAYER M5 ;
        RECT  54.864 0 54.888 0.192 ;
    END
  END li[259]
  PIN li[25]
    DIRECTION INPUT ;
    USE SIGNAL ;
    PORT
      LAYER M5 ;
        RECT  32.4 0 32.424 0.192 ;
    END
  END li[25]
  PIN li[260]
    DIRECTION INPUT ;
    USE SIGNAL ;
    PORT
      LAYER M5 ;
        RECT  54.96 0 54.984 0.192 ;
    END
  END li[260]
  PIN li[261]
    DIRECTION INPUT ;
    USE SIGNAL ;
    PORT
      LAYER M5 ;
        RECT  55.056 0 55.08 0.192 ;
    END
  END li[261]
  PIN li[262]
    DIRECTION INPUT ;
    USE SIGNAL ;
    PORT
      LAYER M5 ;
        RECT  55.152 0 55.176 0.192 ;
    END
  END li[262]
  PIN li[263]
    DIRECTION INPUT ;
    USE SIGNAL ;
    PORT
      LAYER M5 ;
        RECT  55.248 0 55.272 0.192 ;
    END
  END li[263]
  PIN li[264]
    DIRECTION INPUT ;
    USE SIGNAL ;
    PORT
      LAYER M5 ;
        RECT  55.344 0 55.368 0.192 ;
    END
  END li[264]
  PIN li[265]
    DIRECTION INPUT ;
    USE SIGNAL ;
    PORT
      LAYER M5 ;
        RECT  55.44 0 55.464 0.192 ;
    END
  END li[265]
  PIN li[266]
    DIRECTION INPUT ;
    USE SIGNAL ;
    PORT
      LAYER M5 ;
        RECT  55.536 0 55.56 0.192 ;
    END
  END li[266]
  PIN li[267]
    DIRECTION INPUT ;
    USE SIGNAL ;
    PORT
      LAYER M5 ;
        RECT  55.632 0 55.656 0.192 ;
    END
  END li[267]
  PIN li[268]
    DIRECTION INPUT ;
    USE SIGNAL ;
    PORT
      LAYER M5 ;
        RECT  55.728 0 55.752 0.192 ;
    END
  END li[268]
  PIN li[269]
    DIRECTION INPUT ;
    USE SIGNAL ;
    PORT
      LAYER M5 ;
        RECT  55.824 0 55.848 0.192 ;
    END
  END li[269]
  PIN li[26]
    DIRECTION INPUT ;
    USE SIGNAL ;
    PORT
      LAYER M5 ;
        RECT  32.496 0 32.52 0.192 ;
    END
  END li[26]
  PIN li[270]
    DIRECTION INPUT ;
    USE SIGNAL ;
    PORT
      LAYER M5 ;
        RECT  55.92 0 55.944 0.192 ;
    END
  END li[270]
  PIN li[271]
    DIRECTION INPUT ;
    USE SIGNAL ;
    PORT
      LAYER M5 ;
        RECT  56.016 0 56.04 0.192 ;
    END
  END li[271]
  PIN li[272]
    DIRECTION INPUT ;
    USE SIGNAL ;
    PORT
      LAYER M5 ;
        RECT  56.112 0 56.136 0.192 ;
    END
  END li[272]
  PIN li[273]
    DIRECTION INPUT ;
    USE SIGNAL ;
    PORT
      LAYER M5 ;
        RECT  56.208 0 56.232 0.192 ;
    END
  END li[273]
  PIN li[274]
    DIRECTION INPUT ;
    USE SIGNAL ;
    PORT
      LAYER M5 ;
        RECT  56.304 0 56.328 0.192 ;
    END
  END li[274]
  PIN li[275]
    DIRECTION INPUT ;
    USE SIGNAL ;
    PORT
      LAYER M5 ;
        RECT  56.4 0 56.424 0.192 ;
    END
  END li[275]
  PIN li[276]
    DIRECTION INPUT ;
    USE SIGNAL ;
    PORT
      LAYER M5 ;
        RECT  56.496 0 56.52 0.192 ;
    END
  END li[276]
  PIN li[277]
    DIRECTION INPUT ;
    USE SIGNAL ;
    PORT
      LAYER M5 ;
        RECT  56.592 0 56.616 0.192 ;
    END
  END li[277]
  PIN li[278]
    DIRECTION INPUT ;
    USE SIGNAL ;
    PORT
      LAYER M5 ;
        RECT  56.688 0 56.712 0.192 ;
    END
  END li[278]
  PIN li[279]
    DIRECTION INPUT ;
    USE SIGNAL ;
    PORT
      LAYER M5 ;
        RECT  56.784 0 56.808 0.192 ;
    END
  END li[279]
  PIN li[27]
    DIRECTION INPUT ;
    USE SIGNAL ;
    PORT
      LAYER M5 ;
        RECT  32.592 0 32.616 0.192 ;
    END
  END li[27]
  PIN li[280]
    DIRECTION INPUT ;
    USE SIGNAL ;
    PORT
      LAYER M5 ;
        RECT  56.88 0 56.904 0.192 ;
    END
  END li[280]
  PIN li[281]
    DIRECTION INPUT ;
    USE SIGNAL ;
    PORT
      LAYER M5 ;
        RECT  56.976 0 57 0.192 ;
    END
  END li[281]
  PIN li[282]
    DIRECTION INPUT ;
    USE SIGNAL ;
    PORT
      LAYER M5 ;
        RECT  57.072 0 57.096 0.192 ;
    END
  END li[282]
  PIN li[283]
    DIRECTION INPUT ;
    USE SIGNAL ;
    PORT
      LAYER M5 ;
        RECT  57.168 0 57.192 0.192 ;
    END
  END li[283]
  PIN li[284]
    DIRECTION INPUT ;
    USE SIGNAL ;
    PORT
      LAYER M5 ;
        RECT  57.264 0 57.288 0.192 ;
    END
  END li[284]
  PIN li[285]
    DIRECTION INPUT ;
    USE SIGNAL ;
    PORT
      LAYER M5 ;
        RECT  57.36 0 57.384 0.192 ;
    END
  END li[285]
  PIN li[286]
    DIRECTION INPUT ;
    USE SIGNAL ;
    PORT
      LAYER M5 ;
        RECT  57.456 0 57.48 0.192 ;
    END
  END li[286]
  PIN li[287]
    DIRECTION INPUT ;
    USE SIGNAL ;
    PORT
      LAYER M5 ;
        RECT  57.552 0 57.576 0.192 ;
    END
  END li[287]
  PIN li[288]
    DIRECTION INPUT ;
    USE SIGNAL ;
    PORT
      LAYER M5 ;
        RECT  57.648 0 57.672 0.192 ;
    END
  END li[288]
  PIN li[289]
    DIRECTION INPUT ;
    USE SIGNAL ;
    PORT
      LAYER M5 ;
        RECT  57.744 0 57.768 0.192 ;
    END
  END li[289]
  PIN li[28]
    DIRECTION INPUT ;
    USE SIGNAL ;
    PORT
      LAYER M5 ;
        RECT  32.688 0 32.712 0.192 ;
    END
  END li[28]
  PIN li[290]
    DIRECTION INPUT ;
    USE SIGNAL ;
    PORT
      LAYER M5 ;
        RECT  57.84 0 57.864 0.192 ;
    END
  END li[290]
  PIN li[291]
    DIRECTION INPUT ;
    USE SIGNAL ;
    PORT
      LAYER M5 ;
        RECT  57.936 0 57.96 0.192 ;
    END
  END li[291]
  PIN li[292]
    DIRECTION INPUT ;
    USE SIGNAL ;
    PORT
      LAYER M5 ;
        RECT  58.032 0 58.056 0.192 ;
    END
  END li[292]
  PIN li[293]
    DIRECTION INPUT ;
    USE SIGNAL ;
    PORT
      LAYER M5 ;
        RECT  58.128 0 58.152 0.192 ;
    END
  END li[293]
  PIN li[294]
    DIRECTION INPUT ;
    USE SIGNAL ;
    PORT
      LAYER M5 ;
        RECT  58.224 0 58.248 0.192 ;
    END
  END li[294]
  PIN li[295]
    DIRECTION INPUT ;
    USE SIGNAL ;
    PORT
      LAYER M5 ;
        RECT  58.32 0 58.344 0.192 ;
    END
  END li[295]
  PIN li[296]
    DIRECTION INPUT ;
    USE SIGNAL ;
    PORT
      LAYER M5 ;
        RECT  58.416 0 58.44 0.192 ;
    END
  END li[296]
  PIN li[297]
    DIRECTION INPUT ;
    USE SIGNAL ;
    PORT
      LAYER M5 ;
        RECT  58.512 0 58.536 0.192 ;
    END
  END li[297]
  PIN li[298]
    DIRECTION INPUT ;
    USE SIGNAL ;
    PORT
      LAYER M5 ;
        RECT  58.608 0 58.632 0.192 ;
    END
  END li[298]
  PIN li[299]
    DIRECTION INPUT ;
    USE SIGNAL ;
    PORT
      LAYER M5 ;
        RECT  58.704 0 58.728 0.192 ;
    END
  END li[299]
  PIN li[29]
    DIRECTION INPUT ;
    USE SIGNAL ;
    PORT
      LAYER M5 ;
        RECT  32.784 0 32.808 0.192 ;
    END
  END li[29]
  PIN li[2]
    DIRECTION INPUT ;
    USE SIGNAL ;
    PORT
      LAYER M5 ;
        RECT  30.192 0 30.216 0.192 ;
    END
  END li[2]
  PIN li[300]
    DIRECTION INPUT ;
    USE SIGNAL ;
    PORT
      LAYER M5 ;
        RECT  58.8 0 58.824 0.192 ;
    END
  END li[300]
  PIN li[301]
    DIRECTION INPUT ;
    USE SIGNAL ;
    PORT
      LAYER M5 ;
        RECT  58.896 0 58.92 0.192 ;
    END
  END li[301]
  PIN li[302]
    DIRECTION INPUT ;
    USE SIGNAL ;
    PORT
      LAYER M5 ;
        RECT  58.992 0 59.016 0.192 ;
    END
  END li[302]
  PIN li[303]
    DIRECTION INPUT ;
    USE SIGNAL ;
    PORT
      LAYER M5 ;
        RECT  59.088 0 59.112 0.192 ;
    END
  END li[303]
  PIN li[304]
    DIRECTION INPUT ;
    USE SIGNAL ;
    PORT
      LAYER M5 ;
        RECT  59.184 0 59.208 0.192 ;
    END
  END li[304]
  PIN li[305]
    DIRECTION INPUT ;
    USE SIGNAL ;
    PORT
      LAYER M5 ;
        RECT  59.28 0 59.304 0.192 ;
    END
  END li[305]
  PIN li[306]
    DIRECTION INPUT ;
    USE SIGNAL ;
    PORT
      LAYER M5 ;
        RECT  59.376 0 59.4 0.192 ;
    END
  END li[306]
  PIN li[307]
    DIRECTION INPUT ;
    USE SIGNAL ;
    PORT
      LAYER M5 ;
        RECT  59.472 0 59.496 0.192 ;
    END
  END li[307]
  PIN li[308]
    DIRECTION INPUT ;
    USE SIGNAL ;
    PORT
      LAYER M5 ;
        RECT  59.568 0 59.592 0.192 ;
    END
  END li[308]
  PIN li[309]
    DIRECTION INPUT ;
    USE SIGNAL ;
    PORT
      LAYER M5 ;
        RECT  59.664 0 59.688 0.192 ;
    END
  END li[309]
  PIN li[30]
    DIRECTION INPUT ;
    USE SIGNAL ;
    PORT
      LAYER M5 ;
        RECT  32.88 0 32.904 0.192 ;
    END
  END li[30]
  PIN li[310]
    DIRECTION INPUT ;
    USE SIGNAL ;
    PORT
      LAYER M5 ;
        RECT  59.76 0 59.784 0.192 ;
    END
  END li[310]
  PIN li[311]
    DIRECTION INPUT ;
    USE SIGNAL ;
    PORT
      LAYER M5 ;
        RECT  59.856 0 59.88 0.192 ;
    END
  END li[311]
  PIN li[312]
    DIRECTION INPUT ;
    USE SIGNAL ;
    PORT
      LAYER M5 ;
        RECT  59.952 0 59.976 0.192 ;
    END
  END li[312]
  PIN li[313]
    DIRECTION INPUT ;
    USE SIGNAL ;
    PORT
      LAYER M5 ;
        RECT  60.048 0 60.072 0.192 ;
    END
  END li[313]
  PIN li[314]
    DIRECTION INPUT ;
    USE SIGNAL ;
    PORT
      LAYER M5 ;
        RECT  60.144 0 60.168 0.192 ;
    END
  END li[314]
  PIN li[315]
    DIRECTION INPUT ;
    USE SIGNAL ;
    PORT
      LAYER M5 ;
        RECT  60.24 0 60.264 0.192 ;
    END
  END li[315]
  PIN li[316]
    DIRECTION INPUT ;
    USE SIGNAL ;
    PORT
      LAYER M5 ;
        RECT  60.336 0 60.36 0.192 ;
    END
  END li[316]
  PIN li[317]
    DIRECTION INPUT ;
    USE SIGNAL ;
    PORT
      LAYER M5 ;
        RECT  60.432 0 60.456 0.192 ;
    END
  END li[317]
  PIN li[318]
    DIRECTION INPUT ;
    USE SIGNAL ;
    PORT
      LAYER M5 ;
        RECT  60.528 0 60.552 0.192 ;
    END
  END li[318]
  PIN li[319]
    DIRECTION INPUT ;
    USE SIGNAL ;
    PORT
      LAYER M5 ;
        RECT  60.624 0 60.648 0.192 ;
    END
  END li[319]
  PIN li[31]
    DIRECTION INPUT ;
    USE SIGNAL ;
    PORT
      LAYER M5 ;
        RECT  32.976 0 33 0.192 ;
    END
  END li[31]
  PIN li[320]
    DIRECTION INPUT ;
    USE SIGNAL ;
    PORT
      LAYER M5 ;
        RECT  60.72 0 60.744 0.192 ;
    END
  END li[320]
  PIN li[321]
    DIRECTION INPUT ;
    USE SIGNAL ;
    PORT
      LAYER M5 ;
        RECT  60.816 0 60.84 0.192 ;
    END
  END li[321]
  PIN li[322]
    DIRECTION INPUT ;
    USE SIGNAL ;
    PORT
      LAYER M5 ;
        RECT  60.912 0 60.936 0.192 ;
    END
  END li[322]
  PIN li[323]
    DIRECTION INPUT ;
    USE SIGNAL ;
    PORT
      LAYER M5 ;
        RECT  61.008 0 61.032 0.192 ;
    END
  END li[323]
  PIN li[324]
    DIRECTION INPUT ;
    USE SIGNAL ;
    PORT
      LAYER M5 ;
        RECT  61.104 0 61.128 0.192 ;
    END
  END li[324]
  PIN li[325]
    DIRECTION INPUT ;
    USE SIGNAL ;
    PORT
      LAYER M5 ;
        RECT  61.2 0 61.224 0.192 ;
    END
  END li[325]
  PIN li[326]
    DIRECTION INPUT ;
    USE SIGNAL ;
    PORT
      LAYER M5 ;
        RECT  61.296 0 61.32 0.192 ;
    END
  END li[326]
  PIN li[327]
    DIRECTION INPUT ;
    USE SIGNAL ;
    PORT
      LAYER M5 ;
        RECT  61.392 0 61.416 0.192 ;
    END
  END li[327]
  PIN li[328]
    DIRECTION INPUT ;
    USE SIGNAL ;
    PORT
      LAYER M5 ;
        RECT  61.488 0 61.512 0.192 ;
    END
  END li[328]
  PIN li[329]
    DIRECTION INPUT ;
    USE SIGNAL ;
    PORT
      LAYER M5 ;
        RECT  61.584 0 61.608 0.192 ;
    END
  END li[329]
  PIN li[32]
    DIRECTION INPUT ;
    USE SIGNAL ;
    PORT
      LAYER M5 ;
        RECT  33.072 0 33.096 0.192 ;
    END
  END li[32]
  PIN li[330]
    DIRECTION INPUT ;
    USE SIGNAL ;
    PORT
      LAYER M5 ;
        RECT  61.68 0 61.704 0.192 ;
    END
  END li[330]
  PIN li[331]
    DIRECTION INPUT ;
    USE SIGNAL ;
    PORT
      LAYER M5 ;
        RECT  61.776 0 61.8 0.192 ;
    END
  END li[331]
  PIN li[332]
    DIRECTION INPUT ;
    USE SIGNAL ;
    PORT
      LAYER M5 ;
        RECT  61.872 0 61.896 0.192 ;
    END
  END li[332]
  PIN li[333]
    DIRECTION INPUT ;
    USE SIGNAL ;
    PORT
      LAYER M5 ;
        RECT  61.968 0 61.992 0.192 ;
    END
  END li[333]
  PIN li[334]
    DIRECTION INPUT ;
    USE SIGNAL ;
    PORT
      LAYER M5 ;
        RECT  62.064 0 62.088 0.192 ;
    END
  END li[334]
  PIN li[335]
    DIRECTION INPUT ;
    USE SIGNAL ;
    PORT
      LAYER M5 ;
        RECT  62.16 0 62.184 0.192 ;
    END
  END li[335]
  PIN li[336]
    DIRECTION INPUT ;
    USE SIGNAL ;
    PORT
      LAYER M5 ;
        RECT  62.256 0 62.28 0.192 ;
    END
  END li[336]
  PIN li[337]
    DIRECTION INPUT ;
    USE SIGNAL ;
    PORT
      LAYER M5 ;
        RECT  62.352 0 62.376 0.192 ;
    END
  END li[337]
  PIN li[338]
    DIRECTION INPUT ;
    USE SIGNAL ;
    PORT
      LAYER M5 ;
        RECT  62.448 0 62.472 0.192 ;
    END
  END li[338]
  PIN li[339]
    DIRECTION INPUT ;
    USE SIGNAL ;
    PORT
      LAYER M5 ;
        RECT  62.544 0 62.568 0.192 ;
    END
  END li[339]
  PIN li[33]
    DIRECTION INPUT ;
    USE SIGNAL ;
    PORT
      LAYER M5 ;
        RECT  33.168 0 33.192 0.192 ;
    END
  END li[33]
  PIN li[340]
    DIRECTION INPUT ;
    USE SIGNAL ;
    PORT
      LAYER M5 ;
        RECT  62.64 0 62.664 0.192 ;
    END
  END li[340]
  PIN li[341]
    DIRECTION INPUT ;
    USE SIGNAL ;
    PORT
      LAYER M5 ;
        RECT  62.736 0 62.76 0.192 ;
    END
  END li[341]
  PIN li[342]
    DIRECTION INPUT ;
    USE SIGNAL ;
    PORT
      LAYER M5 ;
        RECT  62.832 0 62.856 0.192 ;
    END
  END li[342]
  PIN li[343]
    DIRECTION INPUT ;
    USE SIGNAL ;
    PORT
      LAYER M5 ;
        RECT  62.928 0 62.952 0.192 ;
    END
  END li[343]
  PIN li[344]
    DIRECTION INPUT ;
    USE SIGNAL ;
    PORT
      LAYER M5 ;
        RECT  63.024 0 63.048 0.192 ;
    END
  END li[344]
  PIN li[345]
    DIRECTION INPUT ;
    USE SIGNAL ;
    PORT
      LAYER M5 ;
        RECT  63.12 0 63.144 0.192 ;
    END
  END li[345]
  PIN li[346]
    DIRECTION INPUT ;
    USE SIGNAL ;
    PORT
      LAYER M5 ;
        RECT  63.216 0 63.24 0.192 ;
    END
  END li[346]
  PIN li[347]
    DIRECTION INPUT ;
    USE SIGNAL ;
    PORT
      LAYER M5 ;
        RECT  63.312 0 63.336 0.192 ;
    END
  END li[347]
  PIN li[348]
    DIRECTION INPUT ;
    USE SIGNAL ;
    PORT
      LAYER M5 ;
        RECT  63.408 0 63.432 0.192 ;
    END
  END li[348]
  PIN li[349]
    DIRECTION INPUT ;
    USE SIGNAL ;
    PORT
      LAYER M5 ;
        RECT  63.504 0 63.528 0.192 ;
    END
  END li[349]
  PIN li[34]
    DIRECTION INPUT ;
    USE SIGNAL ;
    PORT
      LAYER M5 ;
        RECT  33.264 0 33.288 0.192 ;
    END
  END li[34]
  PIN li[350]
    DIRECTION INPUT ;
    USE SIGNAL ;
    PORT
      LAYER M5 ;
        RECT  63.6 0 63.624 0.192 ;
    END
  END li[350]
  PIN li[351]
    DIRECTION INPUT ;
    USE SIGNAL ;
    PORT
      LAYER M5 ;
        RECT  63.696 0 63.72 0.192 ;
    END
  END li[351]
  PIN li[352]
    DIRECTION INPUT ;
    USE SIGNAL ;
    PORT
      LAYER M5 ;
        RECT  63.792 0 63.816 0.192 ;
    END
  END li[352]
  PIN li[353]
    DIRECTION INPUT ;
    USE SIGNAL ;
    PORT
      LAYER M5 ;
        RECT  63.888 0 63.912 0.192 ;
    END
  END li[353]
  PIN li[354]
    DIRECTION INPUT ;
    USE SIGNAL ;
    PORT
      LAYER M5 ;
        RECT  63.984 0 64.008 0.192 ;
    END
  END li[354]
  PIN li[355]
    DIRECTION INPUT ;
    USE SIGNAL ;
    PORT
      LAYER M5 ;
        RECT  64.08 0 64.104 0.192 ;
    END
  END li[355]
  PIN li[356]
    DIRECTION INPUT ;
    USE SIGNAL ;
    PORT
      LAYER M5 ;
        RECT  64.176 0 64.2 0.192 ;
    END
  END li[356]
  PIN li[357]
    DIRECTION INPUT ;
    USE SIGNAL ;
    PORT
      LAYER M5 ;
        RECT  64.272 0 64.296 0.192 ;
    END
  END li[357]
  PIN li[358]
    DIRECTION INPUT ;
    USE SIGNAL ;
    PORT
      LAYER M5 ;
        RECT  64.368 0 64.392 0.192 ;
    END
  END li[358]
  PIN li[359]
    DIRECTION INPUT ;
    USE SIGNAL ;
    PORT
      LAYER M5 ;
        RECT  64.464 0 64.488 0.192 ;
    END
  END li[359]
  PIN li[35]
    DIRECTION INPUT ;
    USE SIGNAL ;
    PORT
      LAYER M5 ;
        RECT  33.36 0 33.384 0.192 ;
    END
  END li[35]
  PIN li[360]
    DIRECTION INPUT ;
    USE SIGNAL ;
    PORT
      LAYER M5 ;
        RECT  64.56 0 64.584 0.192 ;
    END
  END li[360]
  PIN li[361]
    DIRECTION INPUT ;
    USE SIGNAL ;
    PORT
      LAYER M5 ;
        RECT  64.656 0 64.68 0.192 ;
    END
  END li[361]
  PIN li[362]
    DIRECTION INPUT ;
    USE SIGNAL ;
    PORT
      LAYER M5 ;
        RECT  64.752 0 64.776 0.192 ;
    END
  END li[362]
  PIN li[363]
    DIRECTION INPUT ;
    USE SIGNAL ;
    PORT
      LAYER M5 ;
        RECT  64.848 0 64.872 0.192 ;
    END
  END li[363]
  PIN li[364]
    DIRECTION INPUT ;
    USE SIGNAL ;
    PORT
      LAYER M5 ;
        RECT  64.944 0 64.968 0.192 ;
    END
  END li[364]
  PIN li[365]
    DIRECTION INPUT ;
    USE SIGNAL ;
    PORT
      LAYER M5 ;
        RECT  65.04 0 65.064 0.192 ;
    END
  END li[365]
  PIN li[366]
    DIRECTION INPUT ;
    USE SIGNAL ;
    PORT
      LAYER M5 ;
        RECT  65.136 0 65.16 0.192 ;
    END
  END li[366]
  PIN li[367]
    DIRECTION INPUT ;
    USE SIGNAL ;
    PORT
      LAYER M5 ;
        RECT  65.232 0 65.256 0.192 ;
    END
  END li[367]
  PIN li[368]
    DIRECTION INPUT ;
    USE SIGNAL ;
    PORT
      LAYER M5 ;
        RECT  65.328 0 65.352 0.192 ;
    END
  END li[368]
  PIN li[369]
    DIRECTION INPUT ;
    USE SIGNAL ;
    PORT
      LAYER M5 ;
        RECT  65.424 0 65.448 0.192 ;
    END
  END li[369]
  PIN li[36]
    DIRECTION INPUT ;
    USE SIGNAL ;
    PORT
      LAYER M5 ;
        RECT  33.456 0 33.48 0.192 ;
    END
  END li[36]
  PIN li[370]
    DIRECTION INPUT ;
    USE SIGNAL ;
    PORT
      LAYER M5 ;
        RECT  65.52 0 65.544 0.192 ;
    END
  END li[370]
  PIN li[371]
    DIRECTION INPUT ;
    USE SIGNAL ;
    PORT
      LAYER M5 ;
        RECT  65.616 0 65.64 0.192 ;
    END
  END li[371]
  PIN li[372]
    DIRECTION INPUT ;
    USE SIGNAL ;
    PORT
      LAYER M5 ;
        RECT  65.712 0 65.736 0.192 ;
    END
  END li[372]
  PIN li[373]
    DIRECTION INPUT ;
    USE SIGNAL ;
    PORT
      LAYER M5 ;
        RECT  65.808 0 65.832 0.192 ;
    END
  END li[373]
  PIN li[374]
    DIRECTION INPUT ;
    USE SIGNAL ;
    PORT
      LAYER M5 ;
        RECT  65.904 0 65.928 0.192 ;
    END
  END li[374]
  PIN li[375]
    DIRECTION INPUT ;
    USE SIGNAL ;
    PORT
      LAYER M5 ;
        RECT  66 0 66.024 0.192 ;
    END
  END li[375]
  PIN li[376]
    DIRECTION INPUT ;
    USE SIGNAL ;
    PORT
      LAYER M5 ;
        RECT  66.096 0 66.12 0.192 ;
    END
  END li[376]
  PIN li[377]
    DIRECTION INPUT ;
    USE SIGNAL ;
    PORT
      LAYER M5 ;
        RECT  66.192 0 66.216 0.192 ;
    END
  END li[377]
  PIN li[378]
    DIRECTION INPUT ;
    USE SIGNAL ;
    PORT
      LAYER M5 ;
        RECT  66.288 0 66.312 0.192 ;
    END
  END li[378]
  PIN li[379]
    DIRECTION INPUT ;
    USE SIGNAL ;
    PORT
      LAYER M5 ;
        RECT  66.384 0 66.408 0.192 ;
    END
  END li[379]
  PIN li[37]
    DIRECTION INPUT ;
    USE SIGNAL ;
    PORT
      LAYER M5 ;
        RECT  33.552 0 33.576 0.192 ;
    END
  END li[37]
  PIN li[380]
    DIRECTION INPUT ;
    USE SIGNAL ;
    PORT
      LAYER M5 ;
        RECT  66.48 0 66.504 0.192 ;
    END
  END li[380]
  PIN li[381]
    DIRECTION INPUT ;
    USE SIGNAL ;
    PORT
      LAYER M5 ;
        RECT  66.576 0 66.6 0.192 ;
    END
  END li[381]
  PIN li[382]
    DIRECTION INPUT ;
    USE SIGNAL ;
    PORT
      LAYER M5 ;
        RECT  66.672 0 66.696 0.192 ;
    END
  END li[382]
  PIN li[383]
    DIRECTION INPUT ;
    USE SIGNAL ;
    PORT
      LAYER M5 ;
        RECT  66.768 0 66.792 0.192 ;
    END
  END li[383]
  PIN li[384]
    DIRECTION INPUT ;
    USE SIGNAL ;
    PORT
      LAYER M5 ;
        RECT  66.864 0 66.888 0.192 ;
    END
  END li[384]
  PIN li[385]
    DIRECTION INPUT ;
    USE SIGNAL ;
    PORT
      LAYER M5 ;
        RECT  66.96 0 66.984 0.192 ;
    END
  END li[385]
  PIN li[386]
    DIRECTION INPUT ;
    USE SIGNAL ;
    PORT
      LAYER M5 ;
        RECT  67.056 0 67.08 0.192 ;
    END
  END li[386]
  PIN li[387]
    DIRECTION INPUT ;
    USE SIGNAL ;
    PORT
      LAYER M5 ;
        RECT  67.152 0 67.176 0.192 ;
    END
  END li[387]
  PIN li[388]
    DIRECTION INPUT ;
    USE SIGNAL ;
    PORT
      LAYER M5 ;
        RECT  67.248 0 67.272 0.192 ;
    END
  END li[388]
  PIN li[389]
    DIRECTION INPUT ;
    USE SIGNAL ;
    PORT
      LAYER M5 ;
        RECT  67.344 0 67.368 0.192 ;
    END
  END li[389]
  PIN li[38]
    DIRECTION INPUT ;
    USE SIGNAL ;
    PORT
      LAYER M5 ;
        RECT  33.648 0 33.672 0.192 ;
    END
  END li[38]
  PIN li[390]
    DIRECTION INPUT ;
    USE SIGNAL ;
    PORT
      LAYER M5 ;
        RECT  67.44 0 67.464 0.192 ;
    END
  END li[390]
  PIN li[391]
    DIRECTION INPUT ;
    USE SIGNAL ;
    PORT
      LAYER M5 ;
        RECT  67.536 0 67.56 0.192 ;
    END
  END li[391]
  PIN li[392]
    DIRECTION INPUT ;
    USE SIGNAL ;
    PORT
      LAYER M5 ;
        RECT  67.632 0 67.656 0.192 ;
    END
  END li[392]
  PIN li[393]
    DIRECTION INPUT ;
    USE SIGNAL ;
    PORT
      LAYER M5 ;
        RECT  67.728 0 67.752 0.192 ;
    END
  END li[393]
  PIN li[394]
    DIRECTION INPUT ;
    USE SIGNAL ;
    PORT
      LAYER M5 ;
        RECT  67.824 0 67.848 0.192 ;
    END
  END li[394]
  PIN li[395]
    DIRECTION INPUT ;
    USE SIGNAL ;
    PORT
      LAYER M5 ;
        RECT  67.92 0 67.944 0.192 ;
    END
  END li[395]
  PIN li[396]
    DIRECTION INPUT ;
    USE SIGNAL ;
    PORT
      LAYER M5 ;
        RECT  68.016 0 68.04 0.192 ;
    END
  END li[396]
  PIN li[397]
    DIRECTION INPUT ;
    USE SIGNAL ;
    PORT
      LAYER M5 ;
        RECT  68.112 0 68.136 0.192 ;
    END
  END li[397]
  PIN li[398]
    DIRECTION INPUT ;
    USE SIGNAL ;
    PORT
      LAYER M5 ;
        RECT  68.208 0 68.232 0.192 ;
    END
  END li[398]
  PIN li[399]
    DIRECTION INPUT ;
    USE SIGNAL ;
    PORT
      LAYER M5 ;
        RECT  68.304 0 68.328 0.192 ;
    END
  END li[399]
  PIN li[39]
    DIRECTION INPUT ;
    USE SIGNAL ;
    PORT
      LAYER M5 ;
        RECT  33.744 0 33.768 0.192 ;
    END
  END li[39]
  PIN li[3]
    DIRECTION INPUT ;
    USE SIGNAL ;
    PORT
      LAYER M5 ;
        RECT  30.288 0 30.312 0.192 ;
    END
  END li[3]
  PIN li[400]
    DIRECTION INPUT ;
    USE SIGNAL ;
    PORT
      LAYER M5 ;
        RECT  68.4 0 68.424 0.192 ;
    END
  END li[400]
  PIN li[401]
    DIRECTION INPUT ;
    USE SIGNAL ;
    PORT
      LAYER M5 ;
        RECT  68.496 0 68.52 0.192 ;
    END
  END li[401]
  PIN li[402]
    DIRECTION INPUT ;
    USE SIGNAL ;
    PORT
      LAYER M5 ;
        RECT  68.592 0 68.616 0.192 ;
    END
  END li[402]
  PIN li[403]
    DIRECTION INPUT ;
    USE SIGNAL ;
    PORT
      LAYER M5 ;
        RECT  68.688 0 68.712 0.192 ;
    END
  END li[403]
  PIN li[404]
    DIRECTION INPUT ;
    USE SIGNAL ;
    PORT
      LAYER M5 ;
        RECT  68.784 0 68.808 0.192 ;
    END
  END li[404]
  PIN li[405]
    DIRECTION INPUT ;
    USE SIGNAL ;
    PORT
      LAYER M5 ;
        RECT  68.88 0 68.904 0.192 ;
    END
  END li[405]
  PIN li[406]
    DIRECTION INPUT ;
    USE SIGNAL ;
    PORT
      LAYER M5 ;
        RECT  68.976 0 69 0.192 ;
    END
  END li[406]
  PIN li[407]
    DIRECTION INPUT ;
    USE SIGNAL ;
    PORT
      LAYER M5 ;
        RECT  69.072 0 69.096 0.192 ;
    END
  END li[407]
  PIN li[408]
    DIRECTION INPUT ;
    USE SIGNAL ;
    PORT
      LAYER M5 ;
        RECT  69.168 0 69.192 0.192 ;
    END
  END li[408]
  PIN li[409]
    DIRECTION INPUT ;
    USE SIGNAL ;
    PORT
      LAYER M5 ;
        RECT  69.264 0 69.288 0.192 ;
    END
  END li[409]
  PIN li[40]
    DIRECTION INPUT ;
    USE SIGNAL ;
    PORT
      LAYER M5 ;
        RECT  33.84 0 33.864 0.192 ;
    END
  END li[40]
  PIN li[410]
    DIRECTION INPUT ;
    USE SIGNAL ;
    PORT
      LAYER M5 ;
        RECT  69.36 0 69.384 0.192 ;
    END
  END li[410]
  PIN li[411]
    DIRECTION INPUT ;
    USE SIGNAL ;
    PORT
      LAYER M5 ;
        RECT  69.456 0 69.48 0.192 ;
    END
  END li[411]
  PIN li[412]
    DIRECTION INPUT ;
    USE SIGNAL ;
    PORT
      LAYER M5 ;
        RECT  69.552 0 69.576 0.192 ;
    END
  END li[412]
  PIN li[413]
    DIRECTION INPUT ;
    USE SIGNAL ;
    PORT
      LAYER M5 ;
        RECT  69.648 0 69.672 0.192 ;
    END
  END li[413]
  PIN li[414]
    DIRECTION INPUT ;
    USE SIGNAL ;
    PORT
      LAYER M5 ;
        RECT  69.744 0 69.768 0.192 ;
    END
  END li[414]
  PIN li[415]
    DIRECTION INPUT ;
    USE SIGNAL ;
    PORT
      LAYER M5 ;
        RECT  69.84 0 69.864 0.192 ;
    END
  END li[415]
  PIN li[416]
    DIRECTION INPUT ;
    USE SIGNAL ;
    PORT
      LAYER M5 ;
        RECT  69.936 0 69.96 0.192 ;
    END
  END li[416]
  PIN li[417]
    DIRECTION INPUT ;
    USE SIGNAL ;
    PORT
      LAYER M5 ;
        RECT  70.032 0 70.056 0.192 ;
    END
  END li[417]
  PIN li[418]
    DIRECTION INPUT ;
    USE SIGNAL ;
    PORT
      LAYER M5 ;
        RECT  70.128 0 70.152 0.192 ;
    END
  END li[418]
  PIN li[419]
    DIRECTION INPUT ;
    USE SIGNAL ;
    PORT
      LAYER M5 ;
        RECT  70.224 0 70.248 0.192 ;
    END
  END li[419]
  PIN li[41]
    DIRECTION INPUT ;
    USE SIGNAL ;
    PORT
      LAYER M5 ;
        RECT  33.936 0 33.96 0.192 ;
    END
  END li[41]
  PIN li[420]
    DIRECTION INPUT ;
    USE SIGNAL ;
    PORT
      LAYER M5 ;
        RECT  70.32 0 70.344 0.192 ;
    END
  END li[420]
  PIN li[421]
    DIRECTION INPUT ;
    USE SIGNAL ;
    PORT
      LAYER M5 ;
        RECT  70.416 0 70.44 0.192 ;
    END
  END li[421]
  PIN li[422]
    DIRECTION INPUT ;
    USE SIGNAL ;
    PORT
      LAYER M5 ;
        RECT  70.512 0 70.536 0.192 ;
    END
  END li[422]
  PIN li[423]
    DIRECTION INPUT ;
    USE SIGNAL ;
    PORT
      LAYER M5 ;
        RECT  70.608 0 70.632 0.192 ;
    END
  END li[423]
  PIN li[424]
    DIRECTION INPUT ;
    USE SIGNAL ;
    PORT
      LAYER M5 ;
        RECT  70.704 0 70.728 0.192 ;
    END
  END li[424]
  PIN li[425]
    DIRECTION INPUT ;
    USE SIGNAL ;
    PORT
      LAYER M5 ;
        RECT  70.8 0 70.824 0.192 ;
    END
  END li[425]
  PIN li[426]
    DIRECTION INPUT ;
    USE SIGNAL ;
    PORT
      LAYER M5 ;
        RECT  70.896 0 70.92 0.192 ;
    END
  END li[426]
  PIN li[427]
    DIRECTION INPUT ;
    USE SIGNAL ;
    PORT
      LAYER M5 ;
        RECT  70.992 0 71.016 0.192 ;
    END
  END li[427]
  PIN li[428]
    DIRECTION INPUT ;
    USE SIGNAL ;
    PORT
      LAYER M5 ;
        RECT  71.088 0 71.112 0.192 ;
    END
  END li[428]
  PIN li[429]
    DIRECTION INPUT ;
    USE SIGNAL ;
    PORT
      LAYER M5 ;
        RECT  71.184 0 71.208 0.192 ;
    END
  END li[429]
  PIN li[42]
    DIRECTION INPUT ;
    USE SIGNAL ;
    PORT
      LAYER M5 ;
        RECT  34.032 0 34.056 0.192 ;
    END
  END li[42]
  PIN li[430]
    DIRECTION INPUT ;
    USE SIGNAL ;
    PORT
      LAYER M5 ;
        RECT  71.28 0 71.304 0.192 ;
    END
  END li[430]
  PIN li[431]
    DIRECTION INPUT ;
    USE SIGNAL ;
    PORT
      LAYER M5 ;
        RECT  71.376 0 71.4 0.192 ;
    END
  END li[431]
  PIN li[432]
    DIRECTION INPUT ;
    USE SIGNAL ;
    PORT
      LAYER M5 ;
        RECT  71.472 0 71.496 0.192 ;
    END
  END li[432]
  PIN li[433]
    DIRECTION INPUT ;
    USE SIGNAL ;
    PORT
      LAYER M5 ;
        RECT  71.568 0 71.592 0.192 ;
    END
  END li[433]
  PIN li[434]
    DIRECTION INPUT ;
    USE SIGNAL ;
    PORT
      LAYER M5 ;
        RECT  71.664 0 71.688 0.192 ;
    END
  END li[434]
  PIN li[435]
    DIRECTION INPUT ;
    USE SIGNAL ;
    PORT
      LAYER M5 ;
        RECT  71.76 0 71.784 0.192 ;
    END
  END li[435]
  PIN li[436]
    DIRECTION INPUT ;
    USE SIGNAL ;
    PORT
      LAYER M5 ;
        RECT  71.856 0 71.88 0.192 ;
    END
  END li[436]
  PIN li[437]
    DIRECTION INPUT ;
    USE SIGNAL ;
    PORT
      LAYER M5 ;
        RECT  71.952 0 71.976 0.192 ;
    END
  END li[437]
  PIN li[438]
    DIRECTION INPUT ;
    USE SIGNAL ;
    PORT
      LAYER M5 ;
        RECT  72.048 0 72.072 0.192 ;
    END
  END li[438]
  PIN li[439]
    DIRECTION INPUT ;
    USE SIGNAL ;
    PORT
      LAYER M5 ;
        RECT  72.144 0 72.168 0.192 ;
    END
  END li[439]
  PIN li[43]
    DIRECTION INPUT ;
    USE SIGNAL ;
    PORT
      LAYER M5 ;
        RECT  34.128 0 34.152 0.192 ;
    END
  END li[43]
  PIN li[440]
    DIRECTION INPUT ;
    USE SIGNAL ;
    PORT
      LAYER M5 ;
        RECT  72.24 0 72.264 0.192 ;
    END
  END li[440]
  PIN li[441]
    DIRECTION INPUT ;
    USE SIGNAL ;
    PORT
      LAYER M5 ;
        RECT  72.336 0 72.36 0.192 ;
    END
  END li[441]
  PIN li[442]
    DIRECTION INPUT ;
    USE SIGNAL ;
    PORT
      LAYER M5 ;
        RECT  72.432 0 72.456 0.192 ;
    END
  END li[442]
  PIN li[443]
    DIRECTION INPUT ;
    USE SIGNAL ;
    PORT
      LAYER M5 ;
        RECT  72.528 0 72.552 0.192 ;
    END
  END li[443]
  PIN li[444]
    DIRECTION INPUT ;
    USE SIGNAL ;
    PORT
      LAYER M5 ;
        RECT  72.624 0 72.648 0.192 ;
    END
  END li[444]
  PIN li[445]
    DIRECTION INPUT ;
    USE SIGNAL ;
    PORT
      LAYER M5 ;
        RECT  72.72 0 72.744 0.192 ;
    END
  END li[445]
  PIN li[446]
    DIRECTION INPUT ;
    USE SIGNAL ;
    PORT
      LAYER M5 ;
        RECT  72.816 0 72.84 0.192 ;
    END
  END li[446]
  PIN li[447]
    DIRECTION INPUT ;
    USE SIGNAL ;
    PORT
      LAYER M5 ;
        RECT  72.912 0 72.936 0.192 ;
    END
  END li[447]
  PIN li[448]
    DIRECTION INPUT ;
    USE SIGNAL ;
    PORT
      LAYER M5 ;
        RECT  73.008 0 73.032 0.192 ;
    END
  END li[448]
  PIN li[449]
    DIRECTION INPUT ;
    USE SIGNAL ;
    PORT
      LAYER M5 ;
        RECT  73.104 0 73.128 0.192 ;
    END
  END li[449]
  PIN li[44]
    DIRECTION INPUT ;
    USE SIGNAL ;
    PORT
      LAYER M5 ;
        RECT  34.224 0 34.248 0.192 ;
    END
  END li[44]
  PIN li[450]
    DIRECTION INPUT ;
    USE SIGNAL ;
    PORT
      LAYER M5 ;
        RECT  73.2 0 73.224 0.192 ;
    END
  END li[450]
  PIN li[451]
    DIRECTION INPUT ;
    USE SIGNAL ;
    PORT
      LAYER M5 ;
        RECT  73.296 0 73.32 0.192 ;
    END
  END li[451]
  PIN li[452]
    DIRECTION INPUT ;
    USE SIGNAL ;
    PORT
      LAYER M5 ;
        RECT  73.392 0 73.416 0.192 ;
    END
  END li[452]
  PIN li[453]
    DIRECTION INPUT ;
    USE SIGNAL ;
    PORT
      LAYER M5 ;
        RECT  73.488 0 73.512 0.192 ;
    END
  END li[453]
  PIN li[454]
    DIRECTION INPUT ;
    USE SIGNAL ;
    PORT
      LAYER M5 ;
        RECT  73.584 0 73.608 0.192 ;
    END
  END li[454]
  PIN li[455]
    DIRECTION INPUT ;
    USE SIGNAL ;
    PORT
      LAYER M5 ;
        RECT  73.68 0 73.704 0.192 ;
    END
  END li[455]
  PIN li[456]
    DIRECTION INPUT ;
    USE SIGNAL ;
    PORT
      LAYER M5 ;
        RECT  73.776 0 73.8 0.192 ;
    END
  END li[456]
  PIN li[457]
    DIRECTION INPUT ;
    USE SIGNAL ;
    PORT
      LAYER M5 ;
        RECT  73.872 0 73.896 0.192 ;
    END
  END li[457]
  PIN li[458]
    DIRECTION INPUT ;
    USE SIGNAL ;
    PORT
      LAYER M5 ;
        RECT  73.968 0 73.992 0.192 ;
    END
  END li[458]
  PIN li[459]
    DIRECTION INPUT ;
    USE SIGNAL ;
    PORT
      LAYER M5 ;
        RECT  74.064 0 74.088 0.192 ;
    END
  END li[459]
  PIN li[45]
    DIRECTION INPUT ;
    USE SIGNAL ;
    PORT
      LAYER M5 ;
        RECT  34.32 0 34.344 0.192 ;
    END
  END li[45]
  PIN li[460]
    DIRECTION INPUT ;
    USE SIGNAL ;
    PORT
      LAYER M5 ;
        RECT  74.16 0 74.184 0.192 ;
    END
  END li[460]
  PIN li[461]
    DIRECTION INPUT ;
    USE SIGNAL ;
    PORT
      LAYER M5 ;
        RECT  74.256 0 74.28 0.192 ;
    END
  END li[461]
  PIN li[462]
    DIRECTION INPUT ;
    USE SIGNAL ;
    PORT
      LAYER M5 ;
        RECT  74.352 0 74.376 0.192 ;
    END
  END li[462]
  PIN li[463]
    DIRECTION INPUT ;
    USE SIGNAL ;
    PORT
      LAYER M5 ;
        RECT  74.448 0 74.472 0.192 ;
    END
  END li[463]
  PIN li[464]
    DIRECTION INPUT ;
    USE SIGNAL ;
    PORT
      LAYER M5 ;
        RECT  74.544 0 74.568 0.192 ;
    END
  END li[464]
  PIN li[465]
    DIRECTION INPUT ;
    USE SIGNAL ;
    PORT
      LAYER M5 ;
        RECT  74.64 0 74.664 0.192 ;
    END
  END li[465]
  PIN li[466]
    DIRECTION INPUT ;
    USE SIGNAL ;
    PORT
      LAYER M5 ;
        RECT  74.736 0 74.76 0.192 ;
    END
  END li[466]
  PIN li[467]
    DIRECTION INPUT ;
    USE SIGNAL ;
    PORT
      LAYER M5 ;
        RECT  74.832 0 74.856 0.192 ;
    END
  END li[467]
  PIN li[468]
    DIRECTION INPUT ;
    USE SIGNAL ;
    PORT
      LAYER M5 ;
        RECT  74.928 0 74.952 0.192 ;
    END
  END li[468]
  PIN li[469]
    DIRECTION INPUT ;
    USE SIGNAL ;
    PORT
      LAYER M5 ;
        RECT  75.024 0 75.048 0.192 ;
    END
  END li[469]
  PIN li[46]
    DIRECTION INPUT ;
    USE SIGNAL ;
    PORT
      LAYER M5 ;
        RECT  34.416 0 34.44 0.192 ;
    END
  END li[46]
  PIN li[470]
    DIRECTION INPUT ;
    USE SIGNAL ;
    PORT
      LAYER M5 ;
        RECT  75.12 0 75.144 0.192 ;
    END
  END li[470]
  PIN li[471]
    DIRECTION INPUT ;
    USE SIGNAL ;
    PORT
      LAYER M5 ;
        RECT  75.216 0 75.24 0.192 ;
    END
  END li[471]
  PIN li[472]
    DIRECTION INPUT ;
    USE SIGNAL ;
    PORT
      LAYER M5 ;
        RECT  75.312 0 75.336 0.192 ;
    END
  END li[472]
  PIN li[473]
    DIRECTION INPUT ;
    USE SIGNAL ;
    PORT
      LAYER M5 ;
        RECT  75.408 0 75.432 0.192 ;
    END
  END li[473]
  PIN li[474]
    DIRECTION INPUT ;
    USE SIGNAL ;
    PORT
      LAYER M5 ;
        RECT  75.504 0 75.528 0.192 ;
    END
  END li[474]
  PIN li[475]
    DIRECTION INPUT ;
    USE SIGNAL ;
    PORT
      LAYER M5 ;
        RECT  75.6 0 75.624 0.192 ;
    END
  END li[475]
  PIN li[476]
    DIRECTION INPUT ;
    USE SIGNAL ;
    PORT
      LAYER M5 ;
        RECT  75.696 0 75.72 0.192 ;
    END
  END li[476]
  PIN li[477]
    DIRECTION INPUT ;
    USE SIGNAL ;
    PORT
      LAYER M5 ;
        RECT  75.792 0 75.816 0.192 ;
    END
  END li[477]
  PIN li[478]
    DIRECTION INPUT ;
    USE SIGNAL ;
    PORT
      LAYER M5 ;
        RECT  75.888 0 75.912 0.192 ;
    END
  END li[478]
  PIN li[479]
    DIRECTION INPUT ;
    USE SIGNAL ;
    PORT
      LAYER M5 ;
        RECT  75.984 0 76.008 0.192 ;
    END
  END li[479]
  PIN li[47]
    DIRECTION INPUT ;
    USE SIGNAL ;
    PORT
      LAYER M5 ;
        RECT  34.512 0 34.536 0.192 ;
    END
  END li[47]
  PIN li[480]
    DIRECTION INPUT ;
    USE SIGNAL ;
    PORT
      LAYER M5 ;
        RECT  76.08 0 76.104 0.192 ;
    END
  END li[480]
  PIN li[481]
    DIRECTION INPUT ;
    USE SIGNAL ;
    PORT
      LAYER M5 ;
        RECT  76.176 0 76.2 0.192 ;
    END
  END li[481]
  PIN li[482]
    DIRECTION INPUT ;
    USE SIGNAL ;
    PORT
      LAYER M5 ;
        RECT  76.272 0 76.296 0.192 ;
    END
  END li[482]
  PIN li[483]
    DIRECTION INPUT ;
    USE SIGNAL ;
    PORT
      LAYER M5 ;
        RECT  76.368 0 76.392 0.192 ;
    END
  END li[483]
  PIN li[484]
    DIRECTION INPUT ;
    USE SIGNAL ;
    PORT
      LAYER M5 ;
        RECT  76.464 0 76.488 0.192 ;
    END
  END li[484]
  PIN li[485]
    DIRECTION INPUT ;
    USE SIGNAL ;
    PORT
      LAYER M5 ;
        RECT  76.56 0 76.584 0.192 ;
    END
  END li[485]
  PIN li[486]
    DIRECTION INPUT ;
    USE SIGNAL ;
    PORT
      LAYER M5 ;
        RECT  76.656 0 76.68 0.192 ;
    END
  END li[486]
  PIN li[487]
    DIRECTION INPUT ;
    USE SIGNAL ;
    PORT
      LAYER M5 ;
        RECT  76.752 0 76.776 0.192 ;
    END
  END li[487]
  PIN li[488]
    DIRECTION INPUT ;
    USE SIGNAL ;
    PORT
      LAYER M5 ;
        RECT  76.848 0 76.872 0.192 ;
    END
  END li[488]
  PIN li[489]
    DIRECTION INPUT ;
    USE SIGNAL ;
    PORT
      LAYER M5 ;
        RECT  76.944 0 76.968 0.192 ;
    END
  END li[489]
  PIN li[48]
    DIRECTION INPUT ;
    USE SIGNAL ;
    PORT
      LAYER M5 ;
        RECT  34.608 0 34.632 0.192 ;
    END
  END li[48]
  PIN li[490]
    DIRECTION INPUT ;
    USE SIGNAL ;
    PORT
      LAYER M5 ;
        RECT  77.04 0 77.064 0.192 ;
    END
  END li[490]
  PIN li[491]
    DIRECTION INPUT ;
    USE SIGNAL ;
    PORT
      LAYER M5 ;
        RECT  77.136 0 77.16 0.192 ;
    END
  END li[491]
  PIN li[492]
    DIRECTION INPUT ;
    USE SIGNAL ;
    PORT
      LAYER M5 ;
        RECT  77.232 0 77.256 0.192 ;
    END
  END li[492]
  PIN li[493]
    DIRECTION INPUT ;
    USE SIGNAL ;
    PORT
      LAYER M5 ;
        RECT  77.328 0 77.352 0.192 ;
    END
  END li[493]
  PIN li[494]
    DIRECTION INPUT ;
    USE SIGNAL ;
    PORT
      LAYER M5 ;
        RECT  77.424 0 77.448 0.192 ;
    END
  END li[494]
  PIN li[495]
    DIRECTION INPUT ;
    USE SIGNAL ;
    PORT
      LAYER M5 ;
        RECT  77.52 0 77.544 0.192 ;
    END
  END li[495]
  PIN li[496]
    DIRECTION INPUT ;
    USE SIGNAL ;
    PORT
      LAYER M5 ;
        RECT  77.616 0 77.64 0.192 ;
    END
  END li[496]
  PIN li[497]
    DIRECTION INPUT ;
    USE SIGNAL ;
    PORT
      LAYER M5 ;
        RECT  77.712 0 77.736 0.192 ;
    END
  END li[497]
  PIN li[498]
    DIRECTION INPUT ;
    USE SIGNAL ;
    PORT
      LAYER M5 ;
        RECT  77.808 0 77.832 0.192 ;
    END
  END li[498]
  PIN li[499]
    DIRECTION INPUT ;
    USE SIGNAL ;
    PORT
      LAYER M5 ;
        RECT  77.904 0 77.928 0.192 ;
    END
  END li[499]
  PIN li[49]
    DIRECTION INPUT ;
    USE SIGNAL ;
    PORT
      LAYER M5 ;
        RECT  34.704 0 34.728 0.192 ;
    END
  END li[49]
  PIN li[4]
    DIRECTION INPUT ;
    USE SIGNAL ;
    PORT
      LAYER M5 ;
        RECT  30.384 0 30.408 0.192 ;
    END
  END li[4]
  PIN li[500]
    DIRECTION INPUT ;
    USE SIGNAL ;
    PORT
      LAYER M5 ;
        RECT  78 0 78.024 0.192 ;
    END
  END li[500]
  PIN li[501]
    DIRECTION INPUT ;
    USE SIGNAL ;
    PORT
      LAYER M5 ;
        RECT  78.096 0 78.12 0.192 ;
    END
  END li[501]
  PIN li[502]
    DIRECTION INPUT ;
    USE SIGNAL ;
    PORT
      LAYER M5 ;
        RECT  78.192 0 78.216 0.192 ;
    END
  END li[502]
  PIN li[503]
    DIRECTION INPUT ;
    USE SIGNAL ;
    PORT
      LAYER M5 ;
        RECT  78.288 0 78.312 0.192 ;
    END
  END li[503]
  PIN li[504]
    DIRECTION INPUT ;
    USE SIGNAL ;
    PORT
      LAYER M5 ;
        RECT  78.384 0 78.408 0.192 ;
    END
  END li[504]
  PIN li[505]
    DIRECTION INPUT ;
    USE SIGNAL ;
    PORT
      LAYER M5 ;
        RECT  78.48 0 78.504 0.192 ;
    END
  END li[505]
  PIN li[506]
    DIRECTION INPUT ;
    USE SIGNAL ;
    PORT
      LAYER M5 ;
        RECT  78.576 0 78.6 0.192 ;
    END
  END li[506]
  PIN li[507]
    DIRECTION INPUT ;
    USE SIGNAL ;
    PORT
      LAYER M5 ;
        RECT  78.672 0 78.696 0.192 ;
    END
  END li[507]
  PIN li[508]
    DIRECTION INPUT ;
    USE SIGNAL ;
    PORT
      LAYER M5 ;
        RECT  78.768 0 78.792 0.192 ;
    END
  END li[508]
  PIN li[509]
    DIRECTION INPUT ;
    USE SIGNAL ;
    PORT
      LAYER M5 ;
        RECT  78.864 0 78.888 0.192 ;
    END
  END li[509]
  PIN li[50]
    DIRECTION INPUT ;
    USE SIGNAL ;
    PORT
      LAYER M5 ;
        RECT  34.8 0 34.824 0.192 ;
    END
  END li[50]
  PIN li[510]
    DIRECTION INPUT ;
    USE SIGNAL ;
    PORT
      LAYER M5 ;
        RECT  78.96 0 78.984 0.192 ;
    END
  END li[510]
  PIN li[511]
    DIRECTION INPUT ;
    USE SIGNAL ;
    PORT
      LAYER M5 ;
        RECT  79.056 0 79.08 0.192 ;
    END
  END li[511]
  PIN li[512]
    DIRECTION INPUT ;
    USE SIGNAL ;
    PORT
      LAYER M5 ;
        RECT  79.152 0 79.176 0.192 ;
    END
  END li[512]
  PIN li[513]
    DIRECTION INPUT ;
    USE SIGNAL ;
    PORT
      LAYER M5 ;
        RECT  79.248 0 79.272 0.192 ;
    END
  END li[513]
  PIN li[514]
    DIRECTION INPUT ;
    USE SIGNAL ;
    PORT
      LAYER M5 ;
        RECT  79.344 0 79.368 0.192 ;
    END
  END li[514]
  PIN li[515]
    DIRECTION INPUT ;
    USE SIGNAL ;
    PORT
      LAYER M5 ;
        RECT  79.44 0 79.464 0.192 ;
    END
  END li[515]
  PIN li[516]
    DIRECTION INPUT ;
    USE SIGNAL ;
    PORT
      LAYER M5 ;
        RECT  79.536 0 79.56 0.192 ;
    END
  END li[516]
  PIN li[517]
    DIRECTION INPUT ;
    USE SIGNAL ;
    PORT
      LAYER M5 ;
        RECT  79.632 0 79.656 0.192 ;
    END
  END li[517]
  PIN li[518]
    DIRECTION INPUT ;
    USE SIGNAL ;
    PORT
      LAYER M5 ;
        RECT  79.728 0 79.752 0.192 ;
    END
  END li[518]
  PIN li[519]
    DIRECTION INPUT ;
    USE SIGNAL ;
    PORT
      LAYER M5 ;
        RECT  79.824 0 79.848 0.192 ;
    END
  END li[519]
  PIN li[51]
    DIRECTION INPUT ;
    USE SIGNAL ;
    PORT
      LAYER M5 ;
        RECT  34.896 0 34.92 0.192 ;
    END
  END li[51]
  PIN li[520]
    DIRECTION INPUT ;
    USE SIGNAL ;
    PORT
      LAYER M5 ;
        RECT  79.92 0 79.944 0.192 ;
    END
  END li[520]
  PIN li[521]
    DIRECTION INPUT ;
    USE SIGNAL ;
    PORT
      LAYER M5 ;
        RECT  80.016 0 80.04 0.192 ;
    END
  END li[521]
  PIN li[522]
    DIRECTION INPUT ;
    USE SIGNAL ;
    PORT
      LAYER M5 ;
        RECT  80.112 0 80.136 0.192 ;
    END
  END li[522]
  PIN li[523]
    DIRECTION INPUT ;
    USE SIGNAL ;
    PORT
      LAYER M5 ;
        RECT  80.208 0 80.232 0.192 ;
    END
  END li[523]
  PIN li[524]
    DIRECTION INPUT ;
    USE SIGNAL ;
    PORT
      LAYER M5 ;
        RECT  80.304 0 80.328 0.192 ;
    END
  END li[524]
  PIN li[525]
    DIRECTION INPUT ;
    USE SIGNAL ;
    PORT
      LAYER M5 ;
        RECT  80.4 0 80.424 0.192 ;
    END
  END li[525]
  PIN li[526]
    DIRECTION INPUT ;
    USE SIGNAL ;
    PORT
      LAYER M5 ;
        RECT  80.496 0 80.52 0.192 ;
    END
  END li[526]
  PIN li[527]
    DIRECTION INPUT ;
    USE SIGNAL ;
    PORT
      LAYER M5 ;
        RECT  80.592 0 80.616 0.192 ;
    END
  END li[527]
  PIN li[528]
    DIRECTION INPUT ;
    USE SIGNAL ;
    PORT
      LAYER M5 ;
        RECT  80.688 0 80.712 0.192 ;
    END
  END li[528]
  PIN li[529]
    DIRECTION INPUT ;
    USE SIGNAL ;
    PORT
      LAYER M5 ;
        RECT  80.784 0 80.808 0.192 ;
    END
  END li[529]
  PIN li[52]
    DIRECTION INPUT ;
    USE SIGNAL ;
    PORT
      LAYER M5 ;
        RECT  34.992 0 35.016 0.192 ;
    END
  END li[52]
  PIN li[530]
    DIRECTION INPUT ;
    USE SIGNAL ;
    PORT
      LAYER M5 ;
        RECT  80.88 0 80.904 0.192 ;
    END
  END li[530]
  PIN li[531]
    DIRECTION INPUT ;
    USE SIGNAL ;
    PORT
      LAYER M5 ;
        RECT  80.976 0 81 0.192 ;
    END
  END li[531]
  PIN li[532]
    DIRECTION INPUT ;
    USE SIGNAL ;
    PORT
      LAYER M5 ;
        RECT  81.072 0 81.096 0.192 ;
    END
  END li[532]
  PIN li[533]
    DIRECTION INPUT ;
    USE SIGNAL ;
    PORT
      LAYER M5 ;
        RECT  81.168 0 81.192 0.192 ;
    END
  END li[533]
  PIN li[534]
    DIRECTION INPUT ;
    USE SIGNAL ;
    PORT
      LAYER M5 ;
        RECT  81.264 0 81.288 0.192 ;
    END
  END li[534]
  PIN li[535]
    DIRECTION INPUT ;
    USE SIGNAL ;
    PORT
      LAYER M5 ;
        RECT  81.36 0 81.384 0.192 ;
    END
  END li[535]
  PIN li[536]
    DIRECTION INPUT ;
    USE SIGNAL ;
    PORT
      LAYER M5 ;
        RECT  81.456 0 81.48 0.192 ;
    END
  END li[536]
  PIN li[537]
    DIRECTION INPUT ;
    USE SIGNAL ;
    PORT
      LAYER M5 ;
        RECT  81.552 0 81.576 0.192 ;
    END
  END li[537]
  PIN li[538]
    DIRECTION INPUT ;
    USE SIGNAL ;
    PORT
      LAYER M5 ;
        RECT  81.648 0 81.672 0.192 ;
    END
  END li[538]
  PIN li[539]
    DIRECTION INPUT ;
    USE SIGNAL ;
    PORT
      LAYER M5 ;
        RECT  81.744 0 81.768 0.192 ;
    END
  END li[539]
  PIN li[53]
    DIRECTION INPUT ;
    USE SIGNAL ;
    PORT
      LAYER M5 ;
        RECT  35.088 0 35.112 0.192 ;
    END
  END li[53]
  PIN li[540]
    DIRECTION INPUT ;
    USE SIGNAL ;
    PORT
      LAYER M5 ;
        RECT  81.84 0 81.864 0.192 ;
    END
  END li[540]
  PIN li[541]
    DIRECTION INPUT ;
    USE SIGNAL ;
    PORT
      LAYER M5 ;
        RECT  81.936 0 81.96 0.192 ;
    END
  END li[541]
  PIN li[542]
    DIRECTION INPUT ;
    USE SIGNAL ;
    PORT
      LAYER M5 ;
        RECT  82.032 0 82.056 0.192 ;
    END
  END li[542]
  PIN li[543]
    DIRECTION INPUT ;
    USE SIGNAL ;
    PORT
      LAYER M5 ;
        RECT  82.128 0 82.152 0.192 ;
    END
  END li[543]
  PIN li[544]
    DIRECTION INPUT ;
    USE SIGNAL ;
    PORT
      LAYER M5 ;
        RECT  82.224 0 82.248 0.192 ;
    END
  END li[544]
  PIN li[545]
    DIRECTION INPUT ;
    USE SIGNAL ;
    PORT
      LAYER M5 ;
        RECT  82.32 0 82.344 0.192 ;
    END
  END li[545]
  PIN li[546]
    DIRECTION INPUT ;
    USE SIGNAL ;
    PORT
      LAYER M5 ;
        RECT  82.416 0 82.44 0.192 ;
    END
  END li[546]
  PIN li[547]
    DIRECTION INPUT ;
    USE SIGNAL ;
    PORT
      LAYER M5 ;
        RECT  82.512 0 82.536 0.192 ;
    END
  END li[547]
  PIN li[548]
    DIRECTION INPUT ;
    USE SIGNAL ;
    PORT
      LAYER M5 ;
        RECT  82.608 0 82.632 0.192 ;
    END
  END li[548]
  PIN li[549]
    DIRECTION INPUT ;
    USE SIGNAL ;
    PORT
      LAYER M5 ;
        RECT  82.704 0 82.728 0.192 ;
    END
  END li[549]
  PIN li[54]
    DIRECTION INPUT ;
    USE SIGNAL ;
    PORT
      LAYER M5 ;
        RECT  35.184 0 35.208 0.192 ;
    END
  END li[54]
  PIN li[550]
    DIRECTION INPUT ;
    USE SIGNAL ;
    PORT
      LAYER M5 ;
        RECT  82.8 0 82.824 0.192 ;
    END
  END li[550]
  PIN li[551]
    DIRECTION INPUT ;
    USE SIGNAL ;
    PORT
      LAYER M5 ;
        RECT  82.896 0 82.92 0.192 ;
    END
  END li[551]
  PIN li[552]
    DIRECTION INPUT ;
    USE SIGNAL ;
    PORT
      LAYER M5 ;
        RECT  82.992 0 83.016 0.192 ;
    END
  END li[552]
  PIN li[553]
    DIRECTION INPUT ;
    USE SIGNAL ;
    PORT
      LAYER M5 ;
        RECT  83.088 0 83.112 0.192 ;
    END
  END li[553]
  PIN li[554]
    DIRECTION INPUT ;
    USE SIGNAL ;
    PORT
      LAYER M5 ;
        RECT  83.184 0 83.208 0.192 ;
    END
  END li[554]
  PIN li[555]
    DIRECTION INPUT ;
    USE SIGNAL ;
    PORT
      LAYER M5 ;
        RECT  83.28 0 83.304 0.192 ;
    END
  END li[555]
  PIN li[556]
    DIRECTION INPUT ;
    USE SIGNAL ;
    PORT
      LAYER M5 ;
        RECT  83.376 0 83.4 0.192 ;
    END
  END li[556]
  PIN li[557]
    DIRECTION INPUT ;
    USE SIGNAL ;
    PORT
      LAYER M5 ;
        RECT  83.472 0 83.496 0.192 ;
    END
  END li[557]
  PIN li[558]
    DIRECTION INPUT ;
    USE SIGNAL ;
    PORT
      LAYER M5 ;
        RECT  83.568 0 83.592 0.192 ;
    END
  END li[558]
  PIN li[559]
    DIRECTION INPUT ;
    USE SIGNAL ;
    PORT
      LAYER M5 ;
        RECT  83.664 0 83.688 0.192 ;
    END
  END li[559]
  PIN li[55]
    DIRECTION INPUT ;
    USE SIGNAL ;
    PORT
      LAYER M5 ;
        RECT  35.28 0 35.304 0.192 ;
    END
  END li[55]
  PIN li[560]
    DIRECTION INPUT ;
    USE SIGNAL ;
    PORT
      LAYER M5 ;
        RECT  83.76 0 83.784 0.192 ;
    END
  END li[560]
  PIN li[561]
    DIRECTION INPUT ;
    USE SIGNAL ;
    PORT
      LAYER M5 ;
        RECT  83.856 0 83.88 0.192 ;
    END
  END li[561]
  PIN li[562]
    DIRECTION INPUT ;
    USE SIGNAL ;
    PORT
      LAYER M5 ;
        RECT  83.952 0 83.976 0.192 ;
    END
  END li[562]
  PIN li[563]
    DIRECTION INPUT ;
    USE SIGNAL ;
    PORT
      LAYER M5 ;
        RECT  84.048 0 84.072 0.192 ;
    END
  END li[563]
  PIN li[564]
    DIRECTION INPUT ;
    USE SIGNAL ;
    PORT
      LAYER M5 ;
        RECT  84.144 0 84.168 0.192 ;
    END
  END li[564]
  PIN li[565]
    DIRECTION INPUT ;
    USE SIGNAL ;
    PORT
      LAYER M5 ;
        RECT  84.24 0 84.264 0.192 ;
    END
  END li[565]
  PIN li[566]
    DIRECTION INPUT ;
    USE SIGNAL ;
    PORT
      LAYER M5 ;
        RECT  84.336 0 84.36 0.192 ;
    END
  END li[566]
  PIN li[567]
    DIRECTION INPUT ;
    USE SIGNAL ;
    PORT
      LAYER M5 ;
        RECT  84.432 0 84.456 0.192 ;
    END
  END li[567]
  PIN li[568]
    DIRECTION INPUT ;
    USE SIGNAL ;
    PORT
      LAYER M5 ;
        RECT  84.528 0 84.552 0.192 ;
    END
  END li[568]
  PIN li[569]
    DIRECTION INPUT ;
    USE SIGNAL ;
    PORT
      LAYER M5 ;
        RECT  84.624 0 84.648 0.192 ;
    END
  END li[569]
  PIN li[56]
    DIRECTION INPUT ;
    USE SIGNAL ;
    PORT
      LAYER M5 ;
        RECT  35.376 0 35.4 0.192 ;
    END
  END li[56]
  PIN li[570]
    DIRECTION INPUT ;
    USE SIGNAL ;
    PORT
      LAYER M5 ;
        RECT  84.72 0 84.744 0.192 ;
    END
  END li[570]
  PIN li[571]
    DIRECTION INPUT ;
    USE SIGNAL ;
    PORT
      LAYER M5 ;
        RECT  84.816 0 84.84 0.192 ;
    END
  END li[571]
  PIN li[572]
    DIRECTION INPUT ;
    USE SIGNAL ;
    PORT
      LAYER M5 ;
        RECT  84.912 0 84.936 0.192 ;
    END
  END li[572]
  PIN li[573]
    DIRECTION INPUT ;
    USE SIGNAL ;
    PORT
      LAYER M5 ;
        RECT  85.008 0 85.032 0.192 ;
    END
  END li[573]
  PIN li[574]
    DIRECTION INPUT ;
    USE SIGNAL ;
    PORT
      LAYER M5 ;
        RECT  85.104 0 85.128 0.192 ;
    END
  END li[574]
  PIN li[575]
    DIRECTION INPUT ;
    USE SIGNAL ;
    PORT
      LAYER M5 ;
        RECT  85.2 0 85.224 0.192 ;
    END
  END li[575]
  PIN li[576]
    DIRECTION INPUT ;
    USE SIGNAL ;
    PORT
      LAYER M5 ;
        RECT  85.296 0 85.32 0.192 ;
    END
  END li[576]
  PIN li[577]
    DIRECTION INPUT ;
    USE SIGNAL ;
    PORT
      LAYER M5 ;
        RECT  85.392 0 85.416 0.192 ;
    END
  END li[577]
  PIN li[578]
    DIRECTION INPUT ;
    USE SIGNAL ;
    PORT
      LAYER M5 ;
        RECT  85.488 0 85.512 0.192 ;
    END
  END li[578]
  PIN li[579]
    DIRECTION INPUT ;
    USE SIGNAL ;
    PORT
      LAYER M5 ;
        RECT  85.584 0 85.608 0.192 ;
    END
  END li[579]
  PIN li[57]
    DIRECTION INPUT ;
    USE SIGNAL ;
    PORT
      LAYER M5 ;
        RECT  35.472 0 35.496 0.192 ;
    END
  END li[57]
  PIN li[580]
    DIRECTION INPUT ;
    USE SIGNAL ;
    PORT
      LAYER M5 ;
        RECT  85.68 0 85.704 0.192 ;
    END
  END li[580]
  PIN li[581]
    DIRECTION INPUT ;
    USE SIGNAL ;
    PORT
      LAYER M5 ;
        RECT  85.776 0 85.8 0.192 ;
    END
  END li[581]
  PIN li[582]
    DIRECTION INPUT ;
    USE SIGNAL ;
    PORT
      LAYER M5 ;
        RECT  85.872 0 85.896 0.192 ;
    END
  END li[582]
  PIN li[583]
    DIRECTION INPUT ;
    USE SIGNAL ;
    PORT
      LAYER M5 ;
        RECT  85.968 0 85.992 0.192 ;
    END
  END li[583]
  PIN li[584]
    DIRECTION INPUT ;
    USE SIGNAL ;
    PORT
      LAYER M5 ;
        RECT  86.064 0 86.088 0.192 ;
    END
  END li[584]
  PIN li[585]
    DIRECTION INPUT ;
    USE SIGNAL ;
    PORT
      LAYER M5 ;
        RECT  86.16 0 86.184 0.192 ;
    END
  END li[585]
  PIN li[586]
    DIRECTION INPUT ;
    USE SIGNAL ;
    PORT
      LAYER M5 ;
        RECT  86.256 0 86.28 0.192 ;
    END
  END li[586]
  PIN li[587]
    DIRECTION INPUT ;
    USE SIGNAL ;
    PORT
      LAYER M5 ;
        RECT  86.352 0 86.376 0.192 ;
    END
  END li[587]
  PIN li[588]
    DIRECTION INPUT ;
    USE SIGNAL ;
    PORT
      LAYER M5 ;
        RECT  86.448 0 86.472 0.192 ;
    END
  END li[588]
  PIN li[589]
    DIRECTION INPUT ;
    USE SIGNAL ;
    PORT
      LAYER M5 ;
        RECT  86.544 0 86.568 0.192 ;
    END
  END li[589]
  PIN li[58]
    DIRECTION INPUT ;
    USE SIGNAL ;
    PORT
      LAYER M5 ;
        RECT  35.568 0 35.592 0.192 ;
    END
  END li[58]
  PIN li[590]
    DIRECTION INPUT ;
    USE SIGNAL ;
    PORT
      LAYER M5 ;
        RECT  86.64 0 86.664 0.192 ;
    END
  END li[590]
  PIN li[591]
    DIRECTION INPUT ;
    USE SIGNAL ;
    PORT
      LAYER M5 ;
        RECT  86.736 0 86.76 0.192 ;
    END
  END li[591]
  PIN li[592]
    DIRECTION INPUT ;
    USE SIGNAL ;
    PORT
      LAYER M5 ;
        RECT  86.832 0 86.856 0.192 ;
    END
  END li[592]
  PIN li[593]
    DIRECTION INPUT ;
    USE SIGNAL ;
    PORT
      LAYER M5 ;
        RECT  86.928 0 86.952 0.192 ;
    END
  END li[593]
  PIN li[594]
    DIRECTION INPUT ;
    USE SIGNAL ;
    PORT
      LAYER M5 ;
        RECT  87.024 0 87.048 0.192 ;
    END
  END li[594]
  PIN li[595]
    DIRECTION INPUT ;
    USE SIGNAL ;
    PORT
      LAYER M5 ;
        RECT  87.12 0 87.144 0.192 ;
    END
  END li[595]
  PIN li[596]
    DIRECTION INPUT ;
    USE SIGNAL ;
    PORT
      LAYER M5 ;
        RECT  87.216 0 87.24 0.192 ;
    END
  END li[596]
  PIN li[597]
    DIRECTION INPUT ;
    USE SIGNAL ;
    PORT
      LAYER M5 ;
        RECT  87.312 0 87.336 0.192 ;
    END
  END li[597]
  PIN li[598]
    DIRECTION INPUT ;
    USE SIGNAL ;
    PORT
      LAYER M5 ;
        RECT  87.408 0 87.432 0.192 ;
    END
  END li[598]
  PIN li[599]
    DIRECTION INPUT ;
    USE SIGNAL ;
    PORT
      LAYER M5 ;
        RECT  87.504 0 87.528 0.192 ;
    END
  END li[599]
  PIN li[59]
    DIRECTION INPUT ;
    USE SIGNAL ;
    PORT
      LAYER M5 ;
        RECT  35.664 0 35.688 0.192 ;
    END
  END li[59]
  PIN li[5]
    DIRECTION INPUT ;
    USE SIGNAL ;
    PORT
      LAYER M5 ;
        RECT  30.48 0 30.504 0.192 ;
    END
  END li[5]
  PIN li[600]
    DIRECTION INPUT ;
    USE SIGNAL ;
    PORT
      LAYER M5 ;
        RECT  87.6 0 87.624 0.192 ;
    END
  END li[600]
  PIN li[601]
    DIRECTION INPUT ;
    USE SIGNAL ;
    PORT
      LAYER M5 ;
        RECT  87.696 0 87.72 0.192 ;
    END
  END li[601]
  PIN li[602]
    DIRECTION INPUT ;
    USE SIGNAL ;
    PORT
      LAYER M5 ;
        RECT  87.792 0 87.816 0.192 ;
    END
  END li[602]
  PIN li[603]
    DIRECTION INPUT ;
    USE SIGNAL ;
    PORT
      LAYER M5 ;
        RECT  87.888 0 87.912 0.192 ;
    END
  END li[603]
  PIN li[604]
    DIRECTION INPUT ;
    USE SIGNAL ;
    PORT
      LAYER M5 ;
        RECT  87.984 0 88.008 0.192 ;
    END
  END li[604]
  PIN li[605]
    DIRECTION INPUT ;
    USE SIGNAL ;
    PORT
      LAYER M5 ;
        RECT  88.08 0 88.104 0.192 ;
    END
  END li[605]
  PIN li[606]
    DIRECTION INPUT ;
    USE SIGNAL ;
    PORT
      LAYER M5 ;
        RECT  88.176 0 88.2 0.192 ;
    END
  END li[606]
  PIN li[607]
    DIRECTION INPUT ;
    USE SIGNAL ;
    PORT
      LAYER M5 ;
        RECT  88.272 0 88.296 0.192 ;
    END
  END li[607]
  PIN li[608]
    DIRECTION INPUT ;
    USE SIGNAL ;
    PORT
      LAYER M5 ;
        RECT  88.368 0 88.392 0.192 ;
    END
  END li[608]
  PIN li[609]
    DIRECTION INPUT ;
    USE SIGNAL ;
    PORT
      LAYER M5 ;
        RECT  88.464 0 88.488 0.192 ;
    END
  END li[609]
  PIN li[60]
    DIRECTION INPUT ;
    USE SIGNAL ;
    PORT
      LAYER M5 ;
        RECT  35.76 0 35.784 0.192 ;
    END
  END li[60]
  PIN li[610]
    DIRECTION INPUT ;
    USE SIGNAL ;
    PORT
      LAYER M5 ;
        RECT  88.56 0 88.584 0.192 ;
    END
  END li[610]
  PIN li[611]
    DIRECTION INPUT ;
    USE SIGNAL ;
    PORT
      LAYER M5 ;
        RECT  88.656 0 88.68 0.192 ;
    END
  END li[611]
  PIN li[612]
    DIRECTION INPUT ;
    USE SIGNAL ;
    PORT
      LAYER M5 ;
        RECT  88.752 0 88.776 0.192 ;
    END
  END li[612]
  PIN li[613]
    DIRECTION INPUT ;
    USE SIGNAL ;
    PORT
      LAYER M5 ;
        RECT  88.848 0 88.872 0.192 ;
    END
  END li[613]
  PIN li[614]
    DIRECTION INPUT ;
    USE SIGNAL ;
    PORT
      LAYER M5 ;
        RECT  88.944 0 88.968 0.192 ;
    END
  END li[614]
  PIN li[615]
    DIRECTION INPUT ;
    USE SIGNAL ;
    PORT
      LAYER M5 ;
        RECT  89.04 0 89.064 0.192 ;
    END
  END li[615]
  PIN li[616]
    DIRECTION INPUT ;
    USE SIGNAL ;
    PORT
      LAYER M5 ;
        RECT  89.136 0 89.16 0.192 ;
    END
  END li[616]
  PIN li[617]
    DIRECTION INPUT ;
    USE SIGNAL ;
    PORT
      LAYER M5 ;
        RECT  89.232 0 89.256 0.192 ;
    END
  END li[617]
  PIN li[618]
    DIRECTION INPUT ;
    USE SIGNAL ;
    PORT
      LAYER M5 ;
        RECT  89.328 0 89.352 0.192 ;
    END
  END li[618]
  PIN li[619]
    DIRECTION INPUT ;
    USE SIGNAL ;
    PORT
      LAYER M5 ;
        RECT  89.424 0 89.448 0.192 ;
    END
  END li[619]
  PIN li[61]
    DIRECTION INPUT ;
    USE SIGNAL ;
    PORT
      LAYER M5 ;
        RECT  35.856 0 35.88 0.192 ;
    END
  END li[61]
  PIN li[620]
    DIRECTION INPUT ;
    USE SIGNAL ;
    PORT
      LAYER M5 ;
        RECT  89.52 0 89.544 0.192 ;
    END
  END li[620]
  PIN li[621]
    DIRECTION INPUT ;
    USE SIGNAL ;
    PORT
      LAYER M5 ;
        RECT  89.616 0 89.64 0.192 ;
    END
  END li[621]
  PIN li[622]
    DIRECTION INPUT ;
    USE SIGNAL ;
    PORT
      LAYER M5 ;
        RECT  89.712 0 89.736 0.192 ;
    END
  END li[622]
  PIN li[623]
    DIRECTION INPUT ;
    USE SIGNAL ;
    PORT
      LAYER M5 ;
        RECT  89.808 0 89.832 0.192 ;
    END
  END li[623]
  PIN li[624]
    DIRECTION INPUT ;
    USE SIGNAL ;
    PORT
      LAYER M5 ;
        RECT  89.904 0 89.928 0.192 ;
    END
  END li[624]
  PIN li[625]
    DIRECTION INPUT ;
    USE SIGNAL ;
    PORT
      LAYER M5 ;
        RECT  90 0 90.024 0.192 ;
    END
  END li[625]
  PIN li[626]
    DIRECTION INPUT ;
    USE SIGNAL ;
    PORT
      LAYER M5 ;
        RECT  90.096 0 90.12 0.192 ;
    END
  END li[626]
  PIN li[627]
    DIRECTION INPUT ;
    USE SIGNAL ;
    PORT
      LAYER M5 ;
        RECT  90.192 0 90.216 0.192 ;
    END
  END li[627]
  PIN li[628]
    DIRECTION INPUT ;
    USE SIGNAL ;
    PORT
      LAYER M5 ;
        RECT  90.288 0 90.312 0.192 ;
    END
  END li[628]
  PIN li[629]
    DIRECTION INPUT ;
    USE SIGNAL ;
    PORT
      LAYER M5 ;
        RECT  90.384 0 90.408 0.192 ;
    END
  END li[629]
  PIN li[62]
    DIRECTION INPUT ;
    USE SIGNAL ;
    PORT
      LAYER M5 ;
        RECT  35.952 0 35.976 0.192 ;
    END
  END li[62]
  PIN li[630]
    DIRECTION INPUT ;
    USE SIGNAL ;
    PORT
      LAYER M5 ;
        RECT  90.48 0 90.504 0.192 ;
    END
  END li[630]
  PIN li[631]
    DIRECTION INPUT ;
    USE SIGNAL ;
    PORT
      LAYER M5 ;
        RECT  90.576 0 90.6 0.192 ;
    END
  END li[631]
  PIN li[632]
    DIRECTION INPUT ;
    USE SIGNAL ;
    PORT
      LAYER M5 ;
        RECT  90.672 0 90.696 0.192 ;
    END
  END li[632]
  PIN li[633]
    DIRECTION INPUT ;
    USE SIGNAL ;
    PORT
      LAYER M5 ;
        RECT  90.768 0 90.792 0.192 ;
    END
  END li[633]
  PIN li[634]
    DIRECTION INPUT ;
    USE SIGNAL ;
    PORT
      LAYER M5 ;
        RECT  90.864 0 90.888 0.192 ;
    END
  END li[634]
  PIN li[635]
    DIRECTION INPUT ;
    USE SIGNAL ;
    PORT
      LAYER M5 ;
        RECT  90.96 0 90.984 0.192 ;
    END
  END li[635]
  PIN li[636]
    DIRECTION INPUT ;
    USE SIGNAL ;
    PORT
      LAYER M5 ;
        RECT  91.056 0 91.08 0.192 ;
    END
  END li[636]
  PIN li[637]
    DIRECTION INPUT ;
    USE SIGNAL ;
    PORT
      LAYER M5 ;
        RECT  91.152 0 91.176 0.192 ;
    END
  END li[637]
  PIN li[638]
    DIRECTION INPUT ;
    USE SIGNAL ;
    PORT
      LAYER M5 ;
        RECT  91.248 0 91.272 0.192 ;
    END
  END li[638]
  PIN li[639]
    DIRECTION INPUT ;
    USE SIGNAL ;
    PORT
      LAYER M5 ;
        RECT  91.344 0 91.368 0.192 ;
    END
  END li[639]
  PIN li[63]
    DIRECTION INPUT ;
    USE SIGNAL ;
    PORT
      LAYER M5 ;
        RECT  36.048 0 36.072 0.192 ;
    END
  END li[63]
  PIN li[640]
    DIRECTION INPUT ;
    USE SIGNAL ;
    PORT
      LAYER M5 ;
        RECT  91.44 0 91.464 0.192 ;
    END
  END li[640]
  PIN li[641]
    DIRECTION INPUT ;
    USE SIGNAL ;
    PORT
      LAYER M5 ;
        RECT  91.536 0 91.56 0.192 ;
    END
  END li[641]
  PIN li[642]
    DIRECTION INPUT ;
    USE SIGNAL ;
    PORT
      LAYER M5 ;
        RECT  91.632 0 91.656 0.192 ;
    END
  END li[642]
  PIN li[643]
    DIRECTION INPUT ;
    USE SIGNAL ;
    PORT
      LAYER M5 ;
        RECT  91.728 0 91.752 0.192 ;
    END
  END li[643]
  PIN li[644]
    DIRECTION INPUT ;
    USE SIGNAL ;
    PORT
      LAYER M5 ;
        RECT  91.824 0 91.848 0.192 ;
    END
  END li[644]
  PIN li[645]
    DIRECTION INPUT ;
    USE SIGNAL ;
    PORT
      LAYER M5 ;
        RECT  91.92 0 91.944 0.192 ;
    END
  END li[645]
  PIN li[646]
    DIRECTION INPUT ;
    USE SIGNAL ;
    PORT
      LAYER M5 ;
        RECT  92.016 0 92.04 0.192 ;
    END
  END li[646]
  PIN li[647]
    DIRECTION INPUT ;
    USE SIGNAL ;
    PORT
      LAYER M5 ;
        RECT  92.112 0 92.136 0.192 ;
    END
  END li[647]
  PIN li[648]
    DIRECTION INPUT ;
    USE SIGNAL ;
    PORT
      LAYER M5 ;
        RECT  92.208 0 92.232 0.192 ;
    END
  END li[648]
  PIN li[649]
    DIRECTION INPUT ;
    USE SIGNAL ;
    PORT
      LAYER M5 ;
        RECT  92.304 0 92.328 0.192 ;
    END
  END li[649]
  PIN li[64]
    DIRECTION INPUT ;
    USE SIGNAL ;
    PORT
      LAYER M5 ;
        RECT  36.144 0 36.168 0.192 ;
    END
  END li[64]
  PIN li[650]
    DIRECTION INPUT ;
    USE SIGNAL ;
    PORT
      LAYER M5 ;
        RECT  92.4 0 92.424 0.192 ;
    END
  END li[650]
  PIN li[651]
    DIRECTION INPUT ;
    USE SIGNAL ;
    PORT
      LAYER M5 ;
        RECT  92.496 0 92.52 0.192 ;
    END
  END li[651]
  PIN li[652]
    DIRECTION INPUT ;
    USE SIGNAL ;
    PORT
      LAYER M5 ;
        RECT  92.592 0 92.616 0.192 ;
    END
  END li[652]
  PIN li[653]
    DIRECTION INPUT ;
    USE SIGNAL ;
    PORT
      LAYER M5 ;
        RECT  92.688 0 92.712 0.192 ;
    END
  END li[653]
  PIN li[654]
    DIRECTION INPUT ;
    USE SIGNAL ;
    PORT
      LAYER M5 ;
        RECT  92.784 0 92.808 0.192 ;
    END
  END li[654]
  PIN li[655]
    DIRECTION INPUT ;
    USE SIGNAL ;
    PORT
      LAYER M5 ;
        RECT  92.88 0 92.904 0.192 ;
    END
  END li[655]
  PIN li[656]
    DIRECTION INPUT ;
    USE SIGNAL ;
    PORT
      LAYER M5 ;
        RECT  92.976 0 93 0.192 ;
    END
  END li[656]
  PIN li[657]
    DIRECTION INPUT ;
    USE SIGNAL ;
    PORT
      LAYER M5 ;
        RECT  93.072 0 93.096 0.192 ;
    END
  END li[657]
  PIN li[658]
    DIRECTION INPUT ;
    USE SIGNAL ;
    PORT
      LAYER M5 ;
        RECT  93.168 0 93.192 0.192 ;
    END
  END li[658]
  PIN li[659]
    DIRECTION INPUT ;
    USE SIGNAL ;
    PORT
      LAYER M5 ;
        RECT  93.264 0 93.288 0.192 ;
    END
  END li[659]
  PIN li[65]
    DIRECTION INPUT ;
    USE SIGNAL ;
    PORT
      LAYER M5 ;
        RECT  36.24 0 36.264 0.192 ;
    END
  END li[65]
  PIN li[660]
    DIRECTION INPUT ;
    USE SIGNAL ;
    PORT
      LAYER M5 ;
        RECT  93.36 0 93.384 0.192 ;
    END
  END li[660]
  PIN li[661]
    DIRECTION INPUT ;
    USE SIGNAL ;
    PORT
      LAYER M5 ;
        RECT  93.456 0 93.48 0.192 ;
    END
  END li[661]
  PIN li[662]
    DIRECTION INPUT ;
    USE SIGNAL ;
    PORT
      LAYER M5 ;
        RECT  93.552 0 93.576 0.192 ;
    END
  END li[662]
  PIN li[663]
    DIRECTION INPUT ;
    USE SIGNAL ;
    PORT
      LAYER M5 ;
        RECT  93.648 0 93.672 0.192 ;
    END
  END li[663]
  PIN li[664]
    DIRECTION INPUT ;
    USE SIGNAL ;
    PORT
      LAYER M5 ;
        RECT  93.744 0 93.768 0.192 ;
    END
  END li[664]
  PIN li[665]
    DIRECTION INPUT ;
    USE SIGNAL ;
    PORT
      LAYER M5 ;
        RECT  93.84 0 93.864 0.192 ;
    END
  END li[665]
  PIN li[666]
    DIRECTION INPUT ;
    USE SIGNAL ;
    PORT
      LAYER M5 ;
        RECT  93.936 0 93.96 0.192 ;
    END
  END li[666]
  PIN li[667]
    DIRECTION INPUT ;
    USE SIGNAL ;
    PORT
      LAYER M5 ;
        RECT  94.032 0 94.056 0.192 ;
    END
  END li[667]
  PIN li[668]
    DIRECTION INPUT ;
    USE SIGNAL ;
    PORT
      LAYER M5 ;
        RECT  94.128 0 94.152 0.192 ;
    END
  END li[668]
  PIN li[669]
    DIRECTION INPUT ;
    USE SIGNAL ;
    PORT
      LAYER M5 ;
        RECT  94.224 0 94.248 0.192 ;
    END
  END li[669]
  PIN li[66]
    DIRECTION INPUT ;
    USE SIGNAL ;
    PORT
      LAYER M5 ;
        RECT  36.336 0 36.36 0.192 ;
    END
  END li[66]
  PIN li[670]
    DIRECTION INPUT ;
    USE SIGNAL ;
    PORT
      LAYER M5 ;
        RECT  94.32 0 94.344 0.192 ;
    END
  END li[670]
  PIN li[671]
    DIRECTION INPUT ;
    USE SIGNAL ;
    PORT
      LAYER M5 ;
        RECT  94.416 0 94.44 0.192 ;
    END
  END li[671]
  PIN li[672]
    DIRECTION INPUT ;
    USE SIGNAL ;
    PORT
      LAYER M5 ;
        RECT  94.512 0 94.536 0.192 ;
    END
  END li[672]
  PIN li[673]
    DIRECTION INPUT ;
    USE SIGNAL ;
    PORT
      LAYER M5 ;
        RECT  94.608 0 94.632 0.192 ;
    END
  END li[673]
  PIN li[674]
    DIRECTION INPUT ;
    USE SIGNAL ;
    PORT
      LAYER M5 ;
        RECT  94.704 0 94.728 0.192 ;
    END
  END li[674]
  PIN li[675]
    DIRECTION INPUT ;
    USE SIGNAL ;
    PORT
      LAYER M5 ;
        RECT  94.8 0 94.824 0.192 ;
    END
  END li[675]
  PIN li[676]
    DIRECTION INPUT ;
    USE SIGNAL ;
    PORT
      LAYER M5 ;
        RECT  94.896 0 94.92 0.192 ;
    END
  END li[676]
  PIN li[677]
    DIRECTION INPUT ;
    USE SIGNAL ;
    PORT
      LAYER M5 ;
        RECT  94.992 0 95.016 0.192 ;
    END
  END li[677]
  PIN li[678]
    DIRECTION INPUT ;
    USE SIGNAL ;
    PORT
      LAYER M5 ;
        RECT  95.088 0 95.112 0.192 ;
    END
  END li[678]
  PIN li[679]
    DIRECTION INPUT ;
    USE SIGNAL ;
    PORT
      LAYER M5 ;
        RECT  95.184 0 95.208 0.192 ;
    END
  END li[679]
  PIN li[67]
    DIRECTION INPUT ;
    USE SIGNAL ;
    PORT
      LAYER M5 ;
        RECT  36.432 0 36.456 0.192 ;
    END
  END li[67]
  PIN li[680]
    DIRECTION INPUT ;
    USE SIGNAL ;
    PORT
      LAYER M5 ;
        RECT  95.28 0 95.304 0.192 ;
    END
  END li[680]
  PIN li[681]
    DIRECTION INPUT ;
    USE SIGNAL ;
    PORT
      LAYER M5 ;
        RECT  95.376 0 95.4 0.192 ;
    END
  END li[681]
  PIN li[682]
    DIRECTION INPUT ;
    USE SIGNAL ;
    PORT
      LAYER M5 ;
        RECT  95.472 0 95.496 0.192 ;
    END
  END li[682]
  PIN li[683]
    DIRECTION INPUT ;
    USE SIGNAL ;
    PORT
      LAYER M5 ;
        RECT  95.568 0 95.592 0.192 ;
    END
  END li[683]
  PIN li[684]
    DIRECTION INPUT ;
    USE SIGNAL ;
    PORT
      LAYER M5 ;
        RECT  95.664 0 95.688 0.192 ;
    END
  END li[684]
  PIN li[685]
    DIRECTION INPUT ;
    USE SIGNAL ;
    PORT
      LAYER M5 ;
        RECT  95.76 0 95.784 0.192 ;
    END
  END li[685]
  PIN li[686]
    DIRECTION INPUT ;
    USE SIGNAL ;
    PORT
      LAYER M5 ;
        RECT  95.856 0 95.88 0.192 ;
    END
  END li[686]
  PIN li[687]
    DIRECTION INPUT ;
    USE SIGNAL ;
    PORT
      LAYER M5 ;
        RECT  95.952 0 95.976 0.192 ;
    END
  END li[687]
  PIN li[688]
    DIRECTION INPUT ;
    USE SIGNAL ;
    PORT
      LAYER M5 ;
        RECT  96.048 0 96.072 0.192 ;
    END
  END li[688]
  PIN li[689]
    DIRECTION INPUT ;
    USE SIGNAL ;
    PORT
      LAYER M5 ;
        RECT  96.144 0 96.168 0.192 ;
    END
  END li[689]
  PIN li[68]
    DIRECTION INPUT ;
    USE SIGNAL ;
    PORT
      LAYER M5 ;
        RECT  36.528 0 36.552 0.192 ;
    END
  END li[68]
  PIN li[690]
    DIRECTION INPUT ;
    USE SIGNAL ;
    PORT
      LAYER M5 ;
        RECT  96.24 0 96.264 0.192 ;
    END
  END li[690]
  PIN li[691]
    DIRECTION INPUT ;
    USE SIGNAL ;
    PORT
      LAYER M5 ;
        RECT  96.336 0 96.36 0.192 ;
    END
  END li[691]
  PIN li[692]
    DIRECTION INPUT ;
    USE SIGNAL ;
    PORT
      LAYER M5 ;
        RECT  96.432 0 96.456 0.192 ;
    END
  END li[692]
  PIN li[693]
    DIRECTION INPUT ;
    USE SIGNAL ;
    PORT
      LAYER M5 ;
        RECT  96.528 0 96.552 0.192 ;
    END
  END li[693]
  PIN li[694]
    DIRECTION INPUT ;
    USE SIGNAL ;
    PORT
      LAYER M5 ;
        RECT  96.624 0 96.648 0.192 ;
    END
  END li[694]
  PIN li[695]
    DIRECTION INPUT ;
    USE SIGNAL ;
    PORT
      LAYER M5 ;
        RECT  96.72 0 96.744 0.192 ;
    END
  END li[695]
  PIN li[696]
    DIRECTION INPUT ;
    USE SIGNAL ;
    PORT
      LAYER M5 ;
        RECT  96.816 0 96.84 0.192 ;
    END
  END li[696]
  PIN li[697]
    DIRECTION INPUT ;
    USE SIGNAL ;
    PORT
      LAYER M5 ;
        RECT  96.912 0 96.936 0.192 ;
    END
  END li[697]
  PIN li[698]
    DIRECTION INPUT ;
    USE SIGNAL ;
    PORT
      LAYER M5 ;
        RECT  97.008 0 97.032 0.192 ;
    END
  END li[698]
  PIN li[699]
    DIRECTION INPUT ;
    USE SIGNAL ;
    PORT
      LAYER M5 ;
        RECT  97.104 0 97.128 0.192 ;
    END
  END li[699]
  PIN li[69]
    DIRECTION INPUT ;
    USE SIGNAL ;
    PORT
      LAYER M5 ;
        RECT  36.624 0 36.648 0.192 ;
    END
  END li[69]
  PIN li[6]
    DIRECTION INPUT ;
    USE SIGNAL ;
    PORT
      LAYER M5 ;
        RECT  30.576 0 30.6 0.192 ;
    END
  END li[6]
  PIN li[700]
    DIRECTION INPUT ;
    USE SIGNAL ;
    PORT
      LAYER M5 ;
        RECT  97.2 0 97.224 0.192 ;
    END
  END li[700]
  PIN li[701]
    DIRECTION INPUT ;
    USE SIGNAL ;
    PORT
      LAYER M5 ;
        RECT  97.296 0 97.32 0.192 ;
    END
  END li[701]
  PIN li[702]
    DIRECTION INPUT ;
    USE SIGNAL ;
    PORT
      LAYER M5 ;
        RECT  97.392 0 97.416 0.192 ;
    END
  END li[702]
  PIN li[703]
    DIRECTION INPUT ;
    USE SIGNAL ;
    PORT
      LAYER M5 ;
        RECT  97.488 0 97.512 0.192 ;
    END
  END li[703]
  PIN li[704]
    DIRECTION INPUT ;
    USE SIGNAL ;
    PORT
      LAYER M5 ;
        RECT  97.584 0 97.608 0.192 ;
    END
  END li[704]
  PIN li[705]
    DIRECTION INPUT ;
    USE SIGNAL ;
    PORT
      LAYER M5 ;
        RECT  97.68 0 97.704 0.192 ;
    END
  END li[705]
  PIN li[706]
    DIRECTION INPUT ;
    USE SIGNAL ;
    PORT
      LAYER M5 ;
        RECT  97.776 0 97.8 0.192 ;
    END
  END li[706]
  PIN li[707]
    DIRECTION INPUT ;
    USE SIGNAL ;
    PORT
      LAYER M5 ;
        RECT  97.872 0 97.896 0.192 ;
    END
  END li[707]
  PIN li[708]
    DIRECTION INPUT ;
    USE SIGNAL ;
    PORT
      LAYER M5 ;
        RECT  97.968 0 97.992 0.192 ;
    END
  END li[708]
  PIN li[709]
    DIRECTION INPUT ;
    USE SIGNAL ;
    PORT
      LAYER M5 ;
        RECT  98.064 0 98.088 0.192 ;
    END
  END li[709]
  PIN li[70]
    DIRECTION INPUT ;
    USE SIGNAL ;
    PORT
      LAYER M5 ;
        RECT  36.72 0 36.744 0.192 ;
    END
  END li[70]
  PIN li[710]
    DIRECTION INPUT ;
    USE SIGNAL ;
    PORT
      LAYER M5 ;
        RECT  98.16 0 98.184 0.192 ;
    END
  END li[710]
  PIN li[711]
    DIRECTION INPUT ;
    USE SIGNAL ;
    PORT
      LAYER M5 ;
        RECT  98.256 0 98.28 0.192 ;
    END
  END li[711]
  PIN li[712]
    DIRECTION INPUT ;
    USE SIGNAL ;
    PORT
      LAYER M5 ;
        RECT  98.352 0 98.376 0.192 ;
    END
  END li[712]
  PIN li[713]
    DIRECTION INPUT ;
    USE SIGNAL ;
    PORT
      LAYER M5 ;
        RECT  98.448 0 98.472 0.192 ;
    END
  END li[713]
  PIN li[714]
    DIRECTION INPUT ;
    USE SIGNAL ;
    PORT
      LAYER M5 ;
        RECT  98.544 0 98.568 0.192 ;
    END
  END li[714]
  PIN li[715]
    DIRECTION INPUT ;
    USE SIGNAL ;
    PORT
      LAYER M5 ;
        RECT  98.64 0 98.664 0.192 ;
    END
  END li[715]
  PIN li[716]
    DIRECTION INPUT ;
    USE SIGNAL ;
    PORT
      LAYER M5 ;
        RECT  98.736 0 98.76 0.192 ;
    END
  END li[716]
  PIN li[717]
    DIRECTION INPUT ;
    USE SIGNAL ;
    PORT
      LAYER M5 ;
        RECT  98.832 0 98.856 0.192 ;
    END
  END li[717]
  PIN li[718]
    DIRECTION INPUT ;
    USE SIGNAL ;
    PORT
      LAYER M5 ;
        RECT  98.928 0 98.952 0.192 ;
    END
  END li[718]
  PIN li[719]
    DIRECTION INPUT ;
    USE SIGNAL ;
    PORT
      LAYER M5 ;
        RECT  99.024 0 99.048 0.192 ;
    END
  END li[719]
  PIN li[71]
    DIRECTION INPUT ;
    USE SIGNAL ;
    PORT
      LAYER M5 ;
        RECT  36.816 0 36.84 0.192 ;
    END
  END li[71]
  PIN li[720]
    DIRECTION INPUT ;
    USE SIGNAL ;
    PORT
      LAYER M5 ;
        RECT  99.12 0 99.144 0.192 ;
    END
  END li[720]
  PIN li[721]
    DIRECTION INPUT ;
    USE SIGNAL ;
    PORT
      LAYER M5 ;
        RECT  99.216 0 99.24 0.192 ;
    END
  END li[721]
  PIN li[722]
    DIRECTION INPUT ;
    USE SIGNAL ;
    PORT
      LAYER M5 ;
        RECT  99.312 0 99.336 0.192 ;
    END
  END li[722]
  PIN li[723]
    DIRECTION INPUT ;
    USE SIGNAL ;
    PORT
      LAYER M5 ;
        RECT  99.408 0 99.432 0.192 ;
    END
  END li[723]
  PIN li[724]
    DIRECTION INPUT ;
    USE SIGNAL ;
    PORT
      LAYER M5 ;
        RECT  99.504 0 99.528 0.192 ;
    END
  END li[724]
  PIN li[725]
    DIRECTION INPUT ;
    USE SIGNAL ;
    PORT
      LAYER M5 ;
        RECT  99.6 0 99.624 0.192 ;
    END
  END li[725]
  PIN li[726]
    DIRECTION INPUT ;
    USE SIGNAL ;
    PORT
      LAYER M5 ;
        RECT  99.696 0 99.72 0.192 ;
    END
  END li[726]
  PIN li[727]
    DIRECTION INPUT ;
    USE SIGNAL ;
    PORT
      LAYER M5 ;
        RECT  99.792 0 99.816 0.192 ;
    END
  END li[727]
  PIN li[728]
    DIRECTION INPUT ;
    USE SIGNAL ;
    PORT
      LAYER M5 ;
        RECT  99.888 0 99.912 0.192 ;
    END
  END li[728]
  PIN li[729]
    DIRECTION INPUT ;
    USE SIGNAL ;
    PORT
      LAYER M5 ;
        RECT  99.984 0 100.008 0.192 ;
    END
  END li[729]
  PIN li[72]
    DIRECTION INPUT ;
    USE SIGNAL ;
    PORT
      LAYER M5 ;
        RECT  36.912 0 36.936 0.192 ;
    END
  END li[72]
  PIN li[730]
    DIRECTION INPUT ;
    USE SIGNAL ;
    PORT
      LAYER M5 ;
        RECT  100.08 0 100.104 0.192 ;
    END
  END li[730]
  PIN li[731]
    DIRECTION INPUT ;
    USE SIGNAL ;
    PORT
      LAYER M5 ;
        RECT  100.176 0 100.2 0.192 ;
    END
  END li[731]
  PIN li[732]
    DIRECTION INPUT ;
    USE SIGNAL ;
    PORT
      LAYER M5 ;
        RECT  100.272 0 100.296 0.192 ;
    END
  END li[732]
  PIN li[733]
    DIRECTION INPUT ;
    USE SIGNAL ;
    PORT
      LAYER M5 ;
        RECT  100.368 0 100.392 0.192 ;
    END
  END li[733]
  PIN li[734]
    DIRECTION INPUT ;
    USE SIGNAL ;
    PORT
      LAYER M5 ;
        RECT  100.464 0 100.488 0.192 ;
    END
  END li[734]
  PIN li[735]
    DIRECTION INPUT ;
    USE SIGNAL ;
    PORT
      LAYER M5 ;
        RECT  100.56 0 100.584 0.192 ;
    END
  END li[735]
  PIN li[736]
    DIRECTION INPUT ;
    USE SIGNAL ;
    PORT
      LAYER M5 ;
        RECT  100.656 0 100.68 0.192 ;
    END
  END li[736]
  PIN li[737]
    DIRECTION INPUT ;
    USE SIGNAL ;
    PORT
      LAYER M5 ;
        RECT  100.752 0 100.776 0.192 ;
    END
  END li[737]
  PIN li[738]
    DIRECTION INPUT ;
    USE SIGNAL ;
    PORT
      LAYER M5 ;
        RECT  100.848 0 100.872 0.192 ;
    END
  END li[738]
  PIN li[739]
    DIRECTION INPUT ;
    USE SIGNAL ;
    PORT
      LAYER M5 ;
        RECT  100.944 0 100.968 0.192 ;
    END
  END li[739]
  PIN li[73]
    DIRECTION INPUT ;
    USE SIGNAL ;
    PORT
      LAYER M5 ;
        RECT  37.008 0 37.032 0.192 ;
    END
  END li[73]
  PIN li[740]
    DIRECTION INPUT ;
    USE SIGNAL ;
    PORT
      LAYER M5 ;
        RECT  101.04 0 101.064 0.192 ;
    END
  END li[740]
  PIN li[741]
    DIRECTION INPUT ;
    USE SIGNAL ;
    PORT
      LAYER M5 ;
        RECT  101.136 0 101.16 0.192 ;
    END
  END li[741]
  PIN li[742]
    DIRECTION INPUT ;
    USE SIGNAL ;
    PORT
      LAYER M5 ;
        RECT  101.232 0 101.256 0.192 ;
    END
  END li[742]
  PIN li[743]
    DIRECTION INPUT ;
    USE SIGNAL ;
    PORT
      LAYER M5 ;
        RECT  101.328 0 101.352 0.192 ;
    END
  END li[743]
  PIN li[744]
    DIRECTION INPUT ;
    USE SIGNAL ;
    PORT
      LAYER M5 ;
        RECT  101.424 0 101.448 0.192 ;
    END
  END li[744]
  PIN li[745]
    DIRECTION INPUT ;
    USE SIGNAL ;
    PORT
      LAYER M5 ;
        RECT  101.52 0 101.544 0.192 ;
    END
  END li[745]
  PIN li[746]
    DIRECTION INPUT ;
    USE SIGNAL ;
    PORT
      LAYER M5 ;
        RECT  101.616 0 101.64 0.192 ;
    END
  END li[746]
  PIN li[747]
    DIRECTION INPUT ;
    USE SIGNAL ;
    PORT
      LAYER M5 ;
        RECT  101.712 0 101.736 0.192 ;
    END
  END li[747]
  PIN li[748]
    DIRECTION INPUT ;
    USE SIGNAL ;
    PORT
      LAYER M5 ;
        RECT  101.808 0 101.832 0.192 ;
    END
  END li[748]
  PIN li[749]
    DIRECTION INPUT ;
    USE SIGNAL ;
    PORT
      LAYER M5 ;
        RECT  101.904 0 101.928 0.192 ;
    END
  END li[749]
  PIN li[74]
    DIRECTION INPUT ;
    USE SIGNAL ;
    PORT
      LAYER M5 ;
        RECT  37.104 0 37.128 0.192 ;
    END
  END li[74]
  PIN li[750]
    DIRECTION INPUT ;
    USE SIGNAL ;
    PORT
      LAYER M5 ;
        RECT  102 0 102.024 0.192 ;
    END
  END li[750]
  PIN li[751]
    DIRECTION INPUT ;
    USE SIGNAL ;
    PORT
      LAYER M5 ;
        RECT  102.096 0 102.12 0.192 ;
    END
  END li[751]
  PIN li[752]
    DIRECTION INPUT ;
    USE SIGNAL ;
    PORT
      LAYER M5 ;
        RECT  102.192 0 102.216 0.192 ;
    END
  END li[752]
  PIN li[753]
    DIRECTION INPUT ;
    USE SIGNAL ;
    PORT
      LAYER M5 ;
        RECT  102.288 0 102.312 0.192 ;
    END
  END li[753]
  PIN li[754]
    DIRECTION INPUT ;
    USE SIGNAL ;
    PORT
      LAYER M5 ;
        RECT  102.384 0 102.408 0.192 ;
    END
  END li[754]
  PIN li[755]
    DIRECTION INPUT ;
    USE SIGNAL ;
    PORT
      LAYER M5 ;
        RECT  102.48 0 102.504 0.192 ;
    END
  END li[755]
  PIN li[756]
    DIRECTION INPUT ;
    USE SIGNAL ;
    PORT
      LAYER M5 ;
        RECT  102.576 0 102.6 0.192 ;
    END
  END li[756]
  PIN li[757]
    DIRECTION INPUT ;
    USE SIGNAL ;
    PORT
      LAYER M5 ;
        RECT  102.672 0 102.696 0.192 ;
    END
  END li[757]
  PIN li[758]
    DIRECTION INPUT ;
    USE SIGNAL ;
    PORT
      LAYER M5 ;
        RECT  102.768 0 102.792 0.192 ;
    END
  END li[758]
  PIN li[759]
    DIRECTION INPUT ;
    USE SIGNAL ;
    PORT
      LAYER M5 ;
        RECT  102.864 0 102.888 0.192 ;
    END
  END li[759]
  PIN li[75]
    DIRECTION INPUT ;
    USE SIGNAL ;
    PORT
      LAYER M5 ;
        RECT  37.2 0 37.224 0.192 ;
    END
  END li[75]
  PIN li[760]
    DIRECTION INPUT ;
    USE SIGNAL ;
    PORT
      LAYER M5 ;
        RECT  102.96 0 102.984 0.192 ;
    END
  END li[760]
  PIN li[761]
    DIRECTION INPUT ;
    USE SIGNAL ;
    PORT
      LAYER M5 ;
        RECT  103.056 0 103.08 0.192 ;
    END
  END li[761]
  PIN li[762]
    DIRECTION INPUT ;
    USE SIGNAL ;
    PORT
      LAYER M5 ;
        RECT  103.152 0 103.176 0.192 ;
    END
  END li[762]
  PIN li[763]
    DIRECTION INPUT ;
    USE SIGNAL ;
    PORT
      LAYER M5 ;
        RECT  103.248 0 103.272 0.192 ;
    END
  END li[763]
  PIN li[764]
    DIRECTION INPUT ;
    USE SIGNAL ;
    PORT
      LAYER M5 ;
        RECT  103.344 0 103.368 0.192 ;
    END
  END li[764]
  PIN li[765]
    DIRECTION INPUT ;
    USE SIGNAL ;
    PORT
      LAYER M5 ;
        RECT  103.44 0 103.464 0.192 ;
    END
  END li[765]
  PIN li[766]
    DIRECTION INPUT ;
    USE SIGNAL ;
    PORT
      LAYER M5 ;
        RECT  103.536 0 103.56 0.192 ;
    END
  END li[766]
  PIN li[767]
    DIRECTION INPUT ;
    USE SIGNAL ;
    PORT
      LAYER M5 ;
        RECT  103.632 0 103.656 0.192 ;
    END
  END li[767]
  PIN li[768]
    DIRECTION INPUT ;
    USE SIGNAL ;
    PORT
      LAYER M5 ;
        RECT  103.728 0 103.752 0.192 ;
    END
  END li[768]
  PIN li[769]
    DIRECTION INPUT ;
    USE SIGNAL ;
    PORT
      LAYER M5 ;
        RECT  103.824 0 103.848 0.192 ;
    END
  END li[769]
  PIN li[76]
    DIRECTION INPUT ;
    USE SIGNAL ;
    PORT
      LAYER M5 ;
        RECT  37.296 0 37.32 0.192 ;
    END
  END li[76]
  PIN li[770]
    DIRECTION INPUT ;
    USE SIGNAL ;
    PORT
      LAYER M5 ;
        RECT  103.92 0 103.944 0.192 ;
    END
  END li[770]
  PIN li[771]
    DIRECTION INPUT ;
    USE SIGNAL ;
    PORT
      LAYER M5 ;
        RECT  104.016 0 104.04 0.192 ;
    END
  END li[771]
  PIN li[772]
    DIRECTION INPUT ;
    USE SIGNAL ;
    PORT
      LAYER M5 ;
        RECT  104.112 0 104.136 0.192 ;
    END
  END li[772]
  PIN li[773]
    DIRECTION INPUT ;
    USE SIGNAL ;
    PORT
      LAYER M5 ;
        RECT  104.208 0 104.232 0.192 ;
    END
  END li[773]
  PIN li[774]
    DIRECTION INPUT ;
    USE SIGNAL ;
    PORT
      LAYER M5 ;
        RECT  104.304 0 104.328 0.192 ;
    END
  END li[774]
  PIN li[775]
    DIRECTION INPUT ;
    USE SIGNAL ;
    PORT
      LAYER M5 ;
        RECT  104.4 0 104.424 0.192 ;
    END
  END li[775]
  PIN li[776]
    DIRECTION INPUT ;
    USE SIGNAL ;
    PORT
      LAYER M5 ;
        RECT  104.496 0 104.52 0.192 ;
    END
  END li[776]
  PIN li[777]
    DIRECTION INPUT ;
    USE SIGNAL ;
    PORT
      LAYER M5 ;
        RECT  104.592 0 104.616 0.192 ;
    END
  END li[777]
  PIN li[778]
    DIRECTION INPUT ;
    USE SIGNAL ;
    PORT
      LAYER M5 ;
        RECT  104.688 0 104.712 0.192 ;
    END
  END li[778]
  PIN li[779]
    DIRECTION INPUT ;
    USE SIGNAL ;
    PORT
      LAYER M5 ;
        RECT  104.784 0 104.808 0.192 ;
    END
  END li[779]
  PIN li[77]
    DIRECTION INPUT ;
    USE SIGNAL ;
    PORT
      LAYER M5 ;
        RECT  37.392 0 37.416 0.192 ;
    END
  END li[77]
  PIN li[780]
    DIRECTION INPUT ;
    USE SIGNAL ;
    PORT
      LAYER M5 ;
        RECT  104.88 0 104.904 0.192 ;
    END
  END li[780]
  PIN li[781]
    DIRECTION INPUT ;
    USE SIGNAL ;
    PORT
      LAYER M5 ;
        RECT  104.976 0 105 0.192 ;
    END
  END li[781]
  PIN li[782]
    DIRECTION INPUT ;
    USE SIGNAL ;
    PORT
      LAYER M5 ;
        RECT  105.072 0 105.096 0.192 ;
    END
  END li[782]
  PIN li[783]
    DIRECTION INPUT ;
    USE SIGNAL ;
    PORT
      LAYER M5 ;
        RECT  105.168 0 105.192 0.192 ;
    END
  END li[783]
  PIN li[784]
    DIRECTION INPUT ;
    USE SIGNAL ;
    PORT
      LAYER M5 ;
        RECT  105.264 0 105.288 0.192 ;
    END
  END li[784]
  PIN li[785]
    DIRECTION INPUT ;
    USE SIGNAL ;
    PORT
      LAYER M5 ;
        RECT  105.36 0 105.384 0.192 ;
    END
  END li[785]
  PIN li[786]
    DIRECTION INPUT ;
    USE SIGNAL ;
    PORT
      LAYER M5 ;
        RECT  105.456 0 105.48 0.192 ;
    END
  END li[786]
  PIN li[787]
    DIRECTION INPUT ;
    USE SIGNAL ;
    PORT
      LAYER M5 ;
        RECT  105.552 0 105.576 0.192 ;
    END
  END li[787]
  PIN li[788]
    DIRECTION INPUT ;
    USE SIGNAL ;
    PORT
      LAYER M5 ;
        RECT  105.648 0 105.672 0.192 ;
    END
  END li[788]
  PIN li[789]
    DIRECTION INPUT ;
    USE SIGNAL ;
    PORT
      LAYER M5 ;
        RECT  105.744 0 105.768 0.192 ;
    END
  END li[789]
  PIN li[78]
    DIRECTION INPUT ;
    USE SIGNAL ;
    PORT
      LAYER M5 ;
        RECT  37.488 0 37.512 0.192 ;
    END
  END li[78]
  PIN li[790]
    DIRECTION INPUT ;
    USE SIGNAL ;
    PORT
      LAYER M5 ;
        RECT  105.84 0 105.864 0.192 ;
    END
  END li[790]
  PIN li[791]
    DIRECTION INPUT ;
    USE SIGNAL ;
    PORT
      LAYER M5 ;
        RECT  105.936 0 105.96 0.192 ;
    END
  END li[791]
  PIN li[792]
    DIRECTION INPUT ;
    USE SIGNAL ;
    PORT
      LAYER M5 ;
        RECT  106.032 0 106.056 0.192 ;
    END
  END li[792]
  PIN li[793]
    DIRECTION INPUT ;
    USE SIGNAL ;
    PORT
      LAYER M5 ;
        RECT  106.128 0 106.152 0.192 ;
    END
  END li[793]
  PIN li[794]
    DIRECTION INPUT ;
    USE SIGNAL ;
    PORT
      LAYER M5 ;
        RECT  106.224 0 106.248 0.192 ;
    END
  END li[794]
  PIN li[795]
    DIRECTION INPUT ;
    USE SIGNAL ;
    PORT
      LAYER M5 ;
        RECT  106.32 0 106.344 0.192 ;
    END
  END li[795]
  PIN li[796]
    DIRECTION INPUT ;
    USE SIGNAL ;
    PORT
      LAYER M5 ;
        RECT  106.416 0 106.44 0.192 ;
    END
  END li[796]
  PIN li[797]
    DIRECTION INPUT ;
    USE SIGNAL ;
    PORT
      LAYER M5 ;
        RECT  106.512 0 106.536 0.192 ;
    END
  END li[797]
  PIN li[798]
    DIRECTION INPUT ;
    USE SIGNAL ;
    PORT
      LAYER M5 ;
        RECT  106.608 0 106.632 0.192 ;
    END
  END li[798]
  PIN li[799]
    DIRECTION INPUT ;
    USE SIGNAL ;
    PORT
      LAYER M5 ;
        RECT  106.704 0 106.728 0.192 ;
    END
  END li[799]
  PIN li[79]
    DIRECTION INPUT ;
    USE SIGNAL ;
    PORT
      LAYER M5 ;
        RECT  37.584 0 37.608 0.192 ;
    END
  END li[79]
  PIN li[7]
    DIRECTION INPUT ;
    USE SIGNAL ;
    PORT
      LAYER M5 ;
        RECT  30.672 0 30.696 0.192 ;
    END
  END li[7]
  PIN li[800]
    DIRECTION INPUT ;
    USE SIGNAL ;
    PORT
      LAYER M5 ;
        RECT  106.8 0 106.824 0.192 ;
    END
  END li[800]
  PIN li[801]
    DIRECTION INPUT ;
    USE SIGNAL ;
    PORT
      LAYER M5 ;
        RECT  106.896 0 106.92 0.192 ;
    END
  END li[801]
  PIN li[802]
    DIRECTION INPUT ;
    USE SIGNAL ;
    PORT
      LAYER M5 ;
        RECT  106.992 0 107.016 0.192 ;
    END
  END li[802]
  PIN li[803]
    DIRECTION INPUT ;
    USE SIGNAL ;
    PORT
      LAYER M5 ;
        RECT  107.088 0 107.112 0.192 ;
    END
  END li[803]
  PIN li[804]
    DIRECTION INPUT ;
    USE SIGNAL ;
    PORT
      LAYER M5 ;
        RECT  107.184 0 107.208 0.192 ;
    END
  END li[804]
  PIN li[805]
    DIRECTION INPUT ;
    USE SIGNAL ;
    PORT
      LAYER M5 ;
        RECT  107.28 0 107.304 0.192 ;
    END
  END li[805]
  PIN li[806]
    DIRECTION INPUT ;
    USE SIGNAL ;
    PORT
      LAYER M5 ;
        RECT  107.376 0 107.4 0.192 ;
    END
  END li[806]
  PIN li[807]
    DIRECTION INPUT ;
    USE SIGNAL ;
    PORT
      LAYER M5 ;
        RECT  107.472 0 107.496 0.192 ;
    END
  END li[807]
  PIN li[808]
    DIRECTION INPUT ;
    USE SIGNAL ;
    PORT
      LAYER M5 ;
        RECT  107.568 0 107.592 0.192 ;
    END
  END li[808]
  PIN li[809]
    DIRECTION INPUT ;
    USE SIGNAL ;
    PORT
      LAYER M5 ;
        RECT  107.664 0 107.688 0.192 ;
    END
  END li[809]
  PIN li[80]
    DIRECTION INPUT ;
    USE SIGNAL ;
    PORT
      LAYER M5 ;
        RECT  37.68 0 37.704 0.192 ;
    END
  END li[80]
  PIN li[810]
    DIRECTION INPUT ;
    USE SIGNAL ;
    PORT
      LAYER M5 ;
        RECT  107.76 0 107.784 0.192 ;
    END
  END li[810]
  PIN li[811]
    DIRECTION INPUT ;
    USE SIGNAL ;
    PORT
      LAYER M5 ;
        RECT  107.856 0 107.88 0.192 ;
    END
  END li[811]
  PIN li[812]
    DIRECTION INPUT ;
    USE SIGNAL ;
    PORT
      LAYER M5 ;
        RECT  107.952 0 107.976 0.192 ;
    END
  END li[812]
  PIN li[813]
    DIRECTION INPUT ;
    USE SIGNAL ;
    PORT
      LAYER M5 ;
        RECT  108.048 0 108.072 0.192 ;
    END
  END li[813]
  PIN li[814]
    DIRECTION INPUT ;
    USE SIGNAL ;
    PORT
      LAYER M5 ;
        RECT  108.144 0 108.168 0.192 ;
    END
  END li[814]
  PIN li[815]
    DIRECTION INPUT ;
    USE SIGNAL ;
    PORT
      LAYER M5 ;
        RECT  108.24 0 108.264 0.192 ;
    END
  END li[815]
  PIN li[816]
    DIRECTION INPUT ;
    USE SIGNAL ;
    PORT
      LAYER M5 ;
        RECT  108.336 0 108.36 0.192 ;
    END
  END li[816]
  PIN li[817]
    DIRECTION INPUT ;
    USE SIGNAL ;
    PORT
      LAYER M5 ;
        RECT  108.432 0 108.456 0.192 ;
    END
  END li[817]
  PIN li[818]
    DIRECTION INPUT ;
    USE SIGNAL ;
    PORT
      LAYER M5 ;
        RECT  108.528 0 108.552 0.192 ;
    END
  END li[818]
  PIN li[819]
    DIRECTION INPUT ;
    USE SIGNAL ;
    PORT
      LAYER M5 ;
        RECT  108.624 0 108.648 0.192 ;
    END
  END li[819]
  PIN li[81]
    DIRECTION INPUT ;
    USE SIGNAL ;
    PORT
      LAYER M5 ;
        RECT  37.776 0 37.8 0.192 ;
    END
  END li[81]
  PIN li[820]
    DIRECTION INPUT ;
    USE SIGNAL ;
    PORT
      LAYER M5 ;
        RECT  108.72 0 108.744 0.192 ;
    END
  END li[820]
  PIN li[821]
    DIRECTION INPUT ;
    USE SIGNAL ;
    PORT
      LAYER M5 ;
        RECT  108.816 0 108.84 0.192 ;
    END
  END li[821]
  PIN li[822]
    DIRECTION INPUT ;
    USE SIGNAL ;
    PORT
      LAYER M5 ;
        RECT  108.912 0 108.936 0.192 ;
    END
  END li[822]
  PIN li[823]
    DIRECTION INPUT ;
    USE SIGNAL ;
    PORT
      LAYER M5 ;
        RECT  109.008 0 109.032 0.192 ;
    END
  END li[823]
  PIN li[824]
    DIRECTION INPUT ;
    USE SIGNAL ;
    PORT
      LAYER M5 ;
        RECT  109.104 0 109.128 0.192 ;
    END
  END li[824]
  PIN li[825]
    DIRECTION INPUT ;
    USE SIGNAL ;
    PORT
      LAYER M5 ;
        RECT  109.2 0 109.224 0.192 ;
    END
  END li[825]
  PIN li[826]
    DIRECTION INPUT ;
    USE SIGNAL ;
    PORT
      LAYER M5 ;
        RECT  109.296 0 109.32 0.192 ;
    END
  END li[826]
  PIN li[827]
    DIRECTION INPUT ;
    USE SIGNAL ;
    PORT
      LAYER M5 ;
        RECT  109.392 0 109.416 0.192 ;
    END
  END li[827]
  PIN li[828]
    DIRECTION INPUT ;
    USE SIGNAL ;
    PORT
      LAYER M5 ;
        RECT  109.488 0 109.512 0.192 ;
    END
  END li[828]
  PIN li[829]
    DIRECTION INPUT ;
    USE SIGNAL ;
    PORT
      LAYER M5 ;
        RECT  109.584 0 109.608 0.192 ;
    END
  END li[829]
  PIN li[82]
    DIRECTION INPUT ;
    USE SIGNAL ;
    PORT
      LAYER M5 ;
        RECT  37.872 0 37.896 0.192 ;
    END
  END li[82]
  PIN li[830]
    DIRECTION INPUT ;
    USE SIGNAL ;
    PORT
      LAYER M5 ;
        RECT  109.68 0 109.704 0.192 ;
    END
  END li[830]
  PIN li[831]
    DIRECTION INPUT ;
    USE SIGNAL ;
    PORT
      LAYER M5 ;
        RECT  109.776 0 109.8 0.192 ;
    END
  END li[831]
  PIN li[832]
    DIRECTION INPUT ;
    USE SIGNAL ;
    PORT
      LAYER M5 ;
        RECT  109.872 0 109.896 0.192 ;
    END
  END li[832]
  PIN li[833]
    DIRECTION INPUT ;
    USE SIGNAL ;
    PORT
      LAYER M5 ;
        RECT  109.968 0 109.992 0.192 ;
    END
  END li[833]
  PIN li[834]
    DIRECTION INPUT ;
    USE SIGNAL ;
    PORT
      LAYER M5 ;
        RECT  110.064 0 110.088 0.192 ;
    END
  END li[834]
  PIN li[835]
    DIRECTION INPUT ;
    USE SIGNAL ;
    PORT
      LAYER M5 ;
        RECT  110.16 0 110.184 0.192 ;
    END
  END li[835]
  PIN li[836]
    DIRECTION INPUT ;
    USE SIGNAL ;
    PORT
      LAYER M5 ;
        RECT  110.256 0 110.28 0.192 ;
    END
  END li[836]
  PIN li[837]
    DIRECTION INPUT ;
    USE SIGNAL ;
    PORT
      LAYER M5 ;
        RECT  110.352 0 110.376 0.192 ;
    END
  END li[837]
  PIN li[838]
    DIRECTION INPUT ;
    USE SIGNAL ;
    PORT
      LAYER M5 ;
        RECT  110.448 0 110.472 0.192 ;
    END
  END li[838]
  PIN li[839]
    DIRECTION INPUT ;
    USE SIGNAL ;
    PORT
      LAYER M5 ;
        RECT  110.544 0 110.568 0.192 ;
    END
  END li[839]
  PIN li[83]
    DIRECTION INPUT ;
    USE SIGNAL ;
    PORT
      LAYER M5 ;
        RECT  37.968 0 37.992 0.192 ;
    END
  END li[83]
  PIN li[840]
    DIRECTION INPUT ;
    USE SIGNAL ;
    PORT
      LAYER M5 ;
        RECT  110.64 0 110.664 0.192 ;
    END
  END li[840]
  PIN li[841]
    DIRECTION INPUT ;
    USE SIGNAL ;
    PORT
      LAYER M5 ;
        RECT  110.736 0 110.76 0.192 ;
    END
  END li[841]
  PIN li[842]
    DIRECTION INPUT ;
    USE SIGNAL ;
    PORT
      LAYER M5 ;
        RECT  110.832 0 110.856 0.192 ;
    END
  END li[842]
  PIN li[843]
    DIRECTION INPUT ;
    USE SIGNAL ;
    PORT
      LAYER M5 ;
        RECT  110.928 0 110.952 0.192 ;
    END
  END li[843]
  PIN li[844]
    DIRECTION INPUT ;
    USE SIGNAL ;
    PORT
      LAYER M5 ;
        RECT  111.024 0 111.048 0.192 ;
    END
  END li[844]
  PIN li[845]
    DIRECTION INPUT ;
    USE SIGNAL ;
    PORT
      LAYER M5 ;
        RECT  111.12 0 111.144 0.192 ;
    END
  END li[845]
  PIN li[846]
    DIRECTION INPUT ;
    USE SIGNAL ;
    PORT
      LAYER M5 ;
        RECT  111.216 0 111.24 0.192 ;
    END
  END li[846]
  PIN li[847]
    DIRECTION INPUT ;
    USE SIGNAL ;
    PORT
      LAYER M5 ;
        RECT  111.312 0 111.336 0.192 ;
    END
  END li[847]
  PIN li[848]
    DIRECTION INPUT ;
    USE SIGNAL ;
    PORT
      LAYER M5 ;
        RECT  111.408 0 111.432 0.192 ;
    END
  END li[848]
  PIN li[849]
    DIRECTION INPUT ;
    USE SIGNAL ;
    PORT
      LAYER M5 ;
        RECT  111.504 0 111.528 0.192 ;
    END
  END li[849]
  PIN li[84]
    DIRECTION INPUT ;
    USE SIGNAL ;
    PORT
      LAYER M5 ;
        RECT  38.064 0 38.088 0.192 ;
    END
  END li[84]
  PIN li[850]
    DIRECTION INPUT ;
    USE SIGNAL ;
    PORT
      LAYER M5 ;
        RECT  111.6 0 111.624 0.192 ;
    END
  END li[850]
  PIN li[851]
    DIRECTION INPUT ;
    USE SIGNAL ;
    PORT
      LAYER M5 ;
        RECT  111.696 0 111.72 0.192 ;
    END
  END li[851]
  PIN li[852]
    DIRECTION INPUT ;
    USE SIGNAL ;
    PORT
      LAYER M5 ;
        RECT  111.792 0 111.816 0.192 ;
    END
  END li[852]
  PIN li[853]
    DIRECTION INPUT ;
    USE SIGNAL ;
    PORT
      LAYER M5 ;
        RECT  111.888 0 111.912 0.192 ;
    END
  END li[853]
  PIN li[854]
    DIRECTION INPUT ;
    USE SIGNAL ;
    PORT
      LAYER M5 ;
        RECT  111.984 0 112.008 0.192 ;
    END
  END li[854]
  PIN li[855]
    DIRECTION INPUT ;
    USE SIGNAL ;
    PORT
      LAYER M5 ;
        RECT  112.08 0 112.104 0.192 ;
    END
  END li[855]
  PIN li[856]
    DIRECTION INPUT ;
    USE SIGNAL ;
    PORT
      LAYER M5 ;
        RECT  112.176 0 112.2 0.192 ;
    END
  END li[856]
  PIN li[857]
    DIRECTION INPUT ;
    USE SIGNAL ;
    PORT
      LAYER M5 ;
        RECT  112.272 0 112.296 0.192 ;
    END
  END li[857]
  PIN li[858]
    DIRECTION INPUT ;
    USE SIGNAL ;
    PORT
      LAYER M5 ;
        RECT  112.368 0 112.392 0.192 ;
    END
  END li[858]
  PIN li[859]
    DIRECTION INPUT ;
    USE SIGNAL ;
    PORT
      LAYER M5 ;
        RECT  112.464 0 112.488 0.192 ;
    END
  END li[859]
  PIN li[85]
    DIRECTION INPUT ;
    USE SIGNAL ;
    PORT
      LAYER M5 ;
        RECT  38.16 0 38.184 0.192 ;
    END
  END li[85]
  PIN li[860]
    DIRECTION INPUT ;
    USE SIGNAL ;
    PORT
      LAYER M5 ;
        RECT  112.56 0 112.584 0.192 ;
    END
  END li[860]
  PIN li[861]
    DIRECTION INPUT ;
    USE SIGNAL ;
    PORT
      LAYER M5 ;
        RECT  112.656 0 112.68 0.192 ;
    END
  END li[861]
  PIN li[862]
    DIRECTION INPUT ;
    USE SIGNAL ;
    PORT
      LAYER M5 ;
        RECT  112.752 0 112.776 0.192 ;
    END
  END li[862]
  PIN li[863]
    DIRECTION INPUT ;
    USE SIGNAL ;
    PORT
      LAYER M5 ;
        RECT  112.848 0 112.872 0.192 ;
    END
  END li[863]
  PIN li[864]
    DIRECTION INPUT ;
    USE SIGNAL ;
    PORT
      LAYER M5 ;
        RECT  112.944 0 112.968 0.192 ;
    END
  END li[864]
  PIN li[865]
    DIRECTION INPUT ;
    USE SIGNAL ;
    PORT
      LAYER M5 ;
        RECT  113.04 0 113.064 0.192 ;
    END
  END li[865]
  PIN li[866]
    DIRECTION INPUT ;
    USE SIGNAL ;
    PORT
      LAYER M5 ;
        RECT  113.136 0 113.16 0.192 ;
    END
  END li[866]
  PIN li[867]
    DIRECTION INPUT ;
    USE SIGNAL ;
    PORT
      LAYER M5 ;
        RECT  113.232 0 113.256 0.192 ;
    END
  END li[867]
  PIN li[868]
    DIRECTION INPUT ;
    USE SIGNAL ;
    PORT
      LAYER M5 ;
        RECT  113.328 0 113.352 0.192 ;
    END
  END li[868]
  PIN li[869]
    DIRECTION INPUT ;
    USE SIGNAL ;
    PORT
      LAYER M5 ;
        RECT  113.424 0 113.448 0.192 ;
    END
  END li[869]
  PIN li[86]
    DIRECTION INPUT ;
    USE SIGNAL ;
    PORT
      LAYER M5 ;
        RECT  38.256 0 38.28 0.192 ;
    END
  END li[86]
  PIN li[870]
    DIRECTION INPUT ;
    USE SIGNAL ;
    PORT
      LAYER M5 ;
        RECT  113.52 0 113.544 0.192 ;
    END
  END li[870]
  PIN li[871]
    DIRECTION INPUT ;
    USE SIGNAL ;
    PORT
      LAYER M5 ;
        RECT  113.616 0 113.64 0.192 ;
    END
  END li[871]
  PIN li[872]
    DIRECTION INPUT ;
    USE SIGNAL ;
    PORT
      LAYER M5 ;
        RECT  113.712 0 113.736 0.192 ;
    END
  END li[872]
  PIN li[873]
    DIRECTION INPUT ;
    USE SIGNAL ;
    PORT
      LAYER M5 ;
        RECT  113.808 0 113.832 0.192 ;
    END
  END li[873]
  PIN li[874]
    DIRECTION INPUT ;
    USE SIGNAL ;
    PORT
      LAYER M5 ;
        RECT  113.904 0 113.928 0.192 ;
    END
  END li[874]
  PIN li[875]
    DIRECTION INPUT ;
    USE SIGNAL ;
    PORT
      LAYER M5 ;
        RECT  114 0 114.024 0.192 ;
    END
  END li[875]
  PIN li[876]
    DIRECTION INPUT ;
    USE SIGNAL ;
    PORT
      LAYER M5 ;
        RECT  114.096 0 114.12 0.192 ;
    END
  END li[876]
  PIN li[877]
    DIRECTION INPUT ;
    USE SIGNAL ;
    PORT
      LAYER M5 ;
        RECT  114.192 0 114.216 0.192 ;
    END
  END li[877]
  PIN li[878]
    DIRECTION INPUT ;
    USE SIGNAL ;
    PORT
      LAYER M5 ;
        RECT  114.288 0 114.312 0.192 ;
    END
  END li[878]
  PIN li[879]
    DIRECTION INPUT ;
    USE SIGNAL ;
    PORT
      LAYER M5 ;
        RECT  114.384 0 114.408 0.192 ;
    END
  END li[879]
  PIN li[87]
    DIRECTION INPUT ;
    USE SIGNAL ;
    PORT
      LAYER M5 ;
        RECT  38.352 0 38.376 0.192 ;
    END
  END li[87]
  PIN li[880]
    DIRECTION INPUT ;
    USE SIGNAL ;
    PORT
      LAYER M5 ;
        RECT  114.48 0 114.504 0.192 ;
    END
  END li[880]
  PIN li[881]
    DIRECTION INPUT ;
    USE SIGNAL ;
    PORT
      LAYER M5 ;
        RECT  114.576 0 114.6 0.192 ;
    END
  END li[881]
  PIN li[882]
    DIRECTION INPUT ;
    USE SIGNAL ;
    PORT
      LAYER M5 ;
        RECT  114.672 0 114.696 0.192 ;
    END
  END li[882]
  PIN li[883]
    DIRECTION INPUT ;
    USE SIGNAL ;
    PORT
      LAYER M5 ;
        RECT  114.768 0 114.792 0.192 ;
    END
  END li[883]
  PIN li[884]
    DIRECTION INPUT ;
    USE SIGNAL ;
    PORT
      LAYER M5 ;
        RECT  114.864 0 114.888 0.192 ;
    END
  END li[884]
  PIN li[885]
    DIRECTION INPUT ;
    USE SIGNAL ;
    PORT
      LAYER M5 ;
        RECT  114.96 0 114.984 0.192 ;
    END
  END li[885]
  PIN li[886]
    DIRECTION INPUT ;
    USE SIGNAL ;
    PORT
      LAYER M5 ;
        RECT  115.056 0 115.08 0.192 ;
    END
  END li[886]
  PIN li[887]
    DIRECTION INPUT ;
    USE SIGNAL ;
    PORT
      LAYER M5 ;
        RECT  115.152 0 115.176 0.192 ;
    END
  END li[887]
  PIN li[888]
    DIRECTION INPUT ;
    USE SIGNAL ;
    PORT
      LAYER M5 ;
        RECT  115.248 0 115.272 0.192 ;
    END
  END li[888]
  PIN li[889]
    DIRECTION INPUT ;
    USE SIGNAL ;
    PORT
      LAYER M5 ;
        RECT  115.344 0 115.368 0.192 ;
    END
  END li[889]
  PIN li[88]
    DIRECTION INPUT ;
    USE SIGNAL ;
    PORT
      LAYER M5 ;
        RECT  38.448 0 38.472 0.192 ;
    END
  END li[88]
  PIN li[890]
    DIRECTION INPUT ;
    USE SIGNAL ;
    PORT
      LAYER M5 ;
        RECT  115.44 0 115.464 0.192 ;
    END
  END li[890]
  PIN li[891]
    DIRECTION INPUT ;
    USE SIGNAL ;
    PORT
      LAYER M5 ;
        RECT  115.536 0 115.56 0.192 ;
    END
  END li[891]
  PIN li[892]
    DIRECTION INPUT ;
    USE SIGNAL ;
    PORT
      LAYER M5 ;
        RECT  115.632 0 115.656 0.192 ;
    END
  END li[892]
  PIN li[893]
    DIRECTION INPUT ;
    USE SIGNAL ;
    PORT
      LAYER M5 ;
        RECT  115.728 0 115.752 0.192 ;
    END
  END li[893]
  PIN li[894]
    DIRECTION INPUT ;
    USE SIGNAL ;
    PORT
      LAYER M5 ;
        RECT  115.824 0 115.848 0.192 ;
    END
  END li[894]
  PIN li[895]
    DIRECTION INPUT ;
    USE SIGNAL ;
    PORT
      LAYER M5 ;
        RECT  115.92 0 115.944 0.192 ;
    END
  END li[895]
  PIN li[896]
    DIRECTION INPUT ;
    USE SIGNAL ;
    PORT
      LAYER M5 ;
        RECT  116.016 0 116.04 0.192 ;
    END
  END li[896]
  PIN li[897]
    DIRECTION INPUT ;
    USE SIGNAL ;
    PORT
      LAYER M5 ;
        RECT  116.112 0 116.136 0.192 ;
    END
  END li[897]
  PIN li[898]
    DIRECTION INPUT ;
    USE SIGNAL ;
    PORT
      LAYER M5 ;
        RECT  116.208 0 116.232 0.192 ;
    END
  END li[898]
  PIN li[899]
    DIRECTION INPUT ;
    USE SIGNAL ;
    PORT
      LAYER M5 ;
        RECT  116.304 0 116.328 0.192 ;
    END
  END li[899]
  PIN li[89]
    DIRECTION INPUT ;
    USE SIGNAL ;
    PORT
      LAYER M5 ;
        RECT  38.544 0 38.568 0.192 ;
    END
  END li[89]
  PIN li[8]
    DIRECTION INPUT ;
    USE SIGNAL ;
    PORT
      LAYER M5 ;
        RECT  30.768 0 30.792 0.192 ;
    END
  END li[8]
  PIN li[900]
    DIRECTION INPUT ;
    USE SIGNAL ;
    PORT
      LAYER M5 ;
        RECT  116.4 0 116.424 0.192 ;
    END
  END li[900]
  PIN li[901]
    DIRECTION INPUT ;
    USE SIGNAL ;
    PORT
      LAYER M5 ;
        RECT  116.496 0 116.52 0.192 ;
    END
  END li[901]
  PIN li[902]
    DIRECTION INPUT ;
    USE SIGNAL ;
    PORT
      LAYER M5 ;
        RECT  116.592 0 116.616 0.192 ;
    END
  END li[902]
  PIN li[903]
    DIRECTION INPUT ;
    USE SIGNAL ;
    PORT
      LAYER M5 ;
        RECT  116.688 0 116.712 0.192 ;
    END
  END li[903]
  PIN li[904]
    DIRECTION INPUT ;
    USE SIGNAL ;
    PORT
      LAYER M5 ;
        RECT  116.784 0 116.808 0.192 ;
    END
  END li[904]
  PIN li[905]
    DIRECTION INPUT ;
    USE SIGNAL ;
    PORT
      LAYER M5 ;
        RECT  116.88 0 116.904 0.192 ;
    END
  END li[905]
  PIN li[906]
    DIRECTION INPUT ;
    USE SIGNAL ;
    PORT
      LAYER M5 ;
        RECT  116.976 0 117 0.192 ;
    END
  END li[906]
  PIN li[907]
    DIRECTION INPUT ;
    USE SIGNAL ;
    PORT
      LAYER M5 ;
        RECT  117.072 0 117.096 0.192 ;
    END
  END li[907]
  PIN li[908]
    DIRECTION INPUT ;
    USE SIGNAL ;
    PORT
      LAYER M5 ;
        RECT  117.168 0 117.192 0.192 ;
    END
  END li[908]
  PIN li[909]
    DIRECTION INPUT ;
    USE SIGNAL ;
    PORT
      LAYER M5 ;
        RECT  117.264 0 117.288 0.192 ;
    END
  END li[909]
  PIN li[90]
    DIRECTION INPUT ;
    USE SIGNAL ;
    PORT
      LAYER M5 ;
        RECT  38.64 0 38.664 0.192 ;
    END
  END li[90]
  PIN li[910]
    DIRECTION INPUT ;
    USE SIGNAL ;
    PORT
      LAYER M5 ;
        RECT  117.36 0 117.384 0.192 ;
    END
  END li[910]
  PIN li[911]
    DIRECTION INPUT ;
    USE SIGNAL ;
    PORT
      LAYER M5 ;
        RECT  117.456 0 117.48 0.192 ;
    END
  END li[911]
  PIN li[912]
    DIRECTION INPUT ;
    USE SIGNAL ;
    PORT
      LAYER M5 ;
        RECT  117.552 0 117.576 0.192 ;
    END
  END li[912]
  PIN li[913]
    DIRECTION INPUT ;
    USE SIGNAL ;
    PORT
      LAYER M5 ;
        RECT  117.648 0 117.672 0.192 ;
    END
  END li[913]
  PIN li[914]
    DIRECTION INPUT ;
    USE SIGNAL ;
    PORT
      LAYER M5 ;
        RECT  117.744 0 117.768 0.192 ;
    END
  END li[914]
  PIN li[915]
    DIRECTION INPUT ;
    USE SIGNAL ;
    PORT
      LAYER M5 ;
        RECT  117.84 0 117.864 0.192 ;
    END
  END li[915]
  PIN li[916]
    DIRECTION INPUT ;
    USE SIGNAL ;
    PORT
      LAYER M5 ;
        RECT  117.936 0 117.96 0.192 ;
    END
  END li[916]
  PIN li[917]
    DIRECTION INPUT ;
    USE SIGNAL ;
    PORT
      LAYER M5 ;
        RECT  118.032 0 118.056 0.192 ;
    END
  END li[917]
  PIN li[918]
    DIRECTION INPUT ;
    USE SIGNAL ;
    PORT
      LAYER M5 ;
        RECT  118.128 0 118.152 0.192 ;
    END
  END li[918]
  PIN li[919]
    DIRECTION INPUT ;
    USE SIGNAL ;
    PORT
      LAYER M5 ;
        RECT  118.224 0 118.248 0.192 ;
    END
  END li[919]
  PIN li[91]
    DIRECTION INPUT ;
    USE SIGNAL ;
    PORT
      LAYER M5 ;
        RECT  38.736 0 38.76 0.192 ;
    END
  END li[91]
  PIN li[920]
    DIRECTION INPUT ;
    USE SIGNAL ;
    PORT
      LAYER M5 ;
        RECT  118.32 0 118.344 0.192 ;
    END
  END li[920]
  PIN li[921]
    DIRECTION INPUT ;
    USE SIGNAL ;
    PORT
      LAYER M5 ;
        RECT  118.416 0 118.44 0.192 ;
    END
  END li[921]
  PIN li[922]
    DIRECTION INPUT ;
    USE SIGNAL ;
    PORT
      LAYER M5 ;
        RECT  118.512 0 118.536 0.192 ;
    END
  END li[922]
  PIN li[923]
    DIRECTION INPUT ;
    USE SIGNAL ;
    PORT
      LAYER M5 ;
        RECT  118.608 0 118.632 0.192 ;
    END
  END li[923]
  PIN li[924]
    DIRECTION INPUT ;
    USE SIGNAL ;
    PORT
      LAYER M5 ;
        RECT  118.704 0 118.728 0.192 ;
    END
  END li[924]
  PIN li[925]
    DIRECTION INPUT ;
    USE SIGNAL ;
    PORT
      LAYER M5 ;
        RECT  118.8 0 118.824 0.192 ;
    END
  END li[925]
  PIN li[926]
    DIRECTION INPUT ;
    USE SIGNAL ;
    PORT
      LAYER M5 ;
        RECT  118.896 0 118.92 0.192 ;
    END
  END li[926]
  PIN li[927]
    DIRECTION INPUT ;
    USE SIGNAL ;
    PORT
      LAYER M5 ;
        RECT  118.992 0 119.016 0.192 ;
    END
  END li[927]
  PIN li[928]
    DIRECTION INPUT ;
    USE SIGNAL ;
    PORT
      LAYER M5 ;
        RECT  119.088 0 119.112 0.192 ;
    END
  END li[928]
  PIN li[929]
    DIRECTION INPUT ;
    USE SIGNAL ;
    PORT
      LAYER M5 ;
        RECT  119.184 0 119.208 0.192 ;
    END
  END li[929]
  PIN li[92]
    DIRECTION INPUT ;
    USE SIGNAL ;
    PORT
      LAYER M5 ;
        RECT  38.832 0 38.856 0.192 ;
    END
  END li[92]
  PIN li[930]
    DIRECTION INPUT ;
    USE SIGNAL ;
    PORT
      LAYER M5 ;
        RECT  119.28 0 119.304 0.192 ;
    END
  END li[930]
  PIN li[931]
    DIRECTION INPUT ;
    USE SIGNAL ;
    PORT
      LAYER M5 ;
        RECT  119.376 0 119.4 0.192 ;
    END
  END li[931]
  PIN li[932]
    DIRECTION INPUT ;
    USE SIGNAL ;
    PORT
      LAYER M5 ;
        RECT  119.472 0 119.496 0.192 ;
    END
  END li[932]
  PIN li[933]
    DIRECTION INPUT ;
    USE SIGNAL ;
    PORT
      LAYER M5 ;
        RECT  119.568 0 119.592 0.192 ;
    END
  END li[933]
  PIN li[934]
    DIRECTION INPUT ;
    USE SIGNAL ;
    PORT
      LAYER M5 ;
        RECT  119.664 0 119.688 0.192 ;
    END
  END li[934]
  PIN li[935]
    DIRECTION INPUT ;
    USE SIGNAL ;
    PORT
      LAYER M5 ;
        RECT  119.76 0 119.784 0.192 ;
    END
  END li[935]
  PIN li[936]
    DIRECTION INPUT ;
    USE SIGNAL ;
    PORT
      LAYER M5 ;
        RECT  119.856 0 119.88 0.192 ;
    END
  END li[936]
  PIN li[937]
    DIRECTION INPUT ;
    USE SIGNAL ;
    PORT
      LAYER M5 ;
        RECT  119.952 0 119.976 0.192 ;
    END
  END li[937]
  PIN li[938]
    DIRECTION INPUT ;
    USE SIGNAL ;
    PORT
      LAYER M5 ;
        RECT  120.048 0 120.072 0.192 ;
    END
  END li[938]
  PIN li[939]
    DIRECTION INPUT ;
    USE SIGNAL ;
    PORT
      LAYER M5 ;
        RECT  120.144 0 120.168 0.192 ;
    END
  END li[939]
  PIN li[93]
    DIRECTION INPUT ;
    USE SIGNAL ;
    PORT
      LAYER M5 ;
        RECT  38.928 0 38.952 0.192 ;
    END
  END li[93]
  PIN li[940]
    DIRECTION INPUT ;
    USE SIGNAL ;
    PORT
      LAYER M5 ;
        RECT  120.24 0 120.264 0.192 ;
    END
  END li[940]
  PIN li[941]
    DIRECTION INPUT ;
    USE SIGNAL ;
    PORT
      LAYER M5 ;
        RECT  120.336 0 120.36 0.192 ;
    END
  END li[941]
  PIN li[942]
    DIRECTION INPUT ;
    USE SIGNAL ;
    PORT
      LAYER M5 ;
        RECT  120.432 0 120.456 0.192 ;
    END
  END li[942]
  PIN li[943]
    DIRECTION INPUT ;
    USE SIGNAL ;
    PORT
      LAYER M5 ;
        RECT  120.528 0 120.552 0.192 ;
    END
  END li[943]
  PIN li[944]
    DIRECTION INPUT ;
    USE SIGNAL ;
    PORT
      LAYER M5 ;
        RECT  120.624 0 120.648 0.192 ;
    END
  END li[944]
  PIN li[945]
    DIRECTION INPUT ;
    USE SIGNAL ;
    PORT
      LAYER M5 ;
        RECT  120.72 0 120.744 0.192 ;
    END
  END li[945]
  PIN li[946]
    DIRECTION INPUT ;
    USE SIGNAL ;
    PORT
      LAYER M5 ;
        RECT  120.816 0 120.84 0.192 ;
    END
  END li[946]
  PIN li[947]
    DIRECTION INPUT ;
    USE SIGNAL ;
    PORT
      LAYER M5 ;
        RECT  120.912 0 120.936 0.192 ;
    END
  END li[947]
  PIN li[948]
    DIRECTION INPUT ;
    USE SIGNAL ;
    PORT
      LAYER M5 ;
        RECT  121.008 0 121.032 0.192 ;
    END
  END li[948]
  PIN li[949]
    DIRECTION INPUT ;
    USE SIGNAL ;
    PORT
      LAYER M5 ;
        RECT  121.104 0 121.128 0.192 ;
    END
  END li[949]
  PIN li[94]
    DIRECTION INPUT ;
    USE SIGNAL ;
    PORT
      LAYER M5 ;
        RECT  39.024 0 39.048 0.192 ;
    END
  END li[94]
  PIN li[950]
    DIRECTION INPUT ;
    USE SIGNAL ;
    PORT
      LAYER M5 ;
        RECT  121.2 0 121.224 0.192 ;
    END
  END li[950]
  PIN li[951]
    DIRECTION INPUT ;
    USE SIGNAL ;
    PORT
      LAYER M5 ;
        RECT  121.296 0 121.32 0.192 ;
    END
  END li[951]
  PIN li[952]
    DIRECTION INPUT ;
    USE SIGNAL ;
    PORT
      LAYER M5 ;
        RECT  121.392 0 121.416 0.192 ;
    END
  END li[952]
  PIN li[953]
    DIRECTION INPUT ;
    USE SIGNAL ;
    PORT
      LAYER M5 ;
        RECT  121.488 0 121.512 0.192 ;
    END
  END li[953]
  PIN li[954]
    DIRECTION INPUT ;
    USE SIGNAL ;
    PORT
      LAYER M5 ;
        RECT  121.584 0 121.608 0.192 ;
    END
  END li[954]
  PIN li[955]
    DIRECTION INPUT ;
    USE SIGNAL ;
    PORT
      LAYER M5 ;
        RECT  121.68 0 121.704 0.192 ;
    END
  END li[955]
  PIN li[956]
    DIRECTION INPUT ;
    USE SIGNAL ;
    PORT
      LAYER M5 ;
        RECT  121.776 0 121.8 0.192 ;
    END
  END li[956]
  PIN li[957]
    DIRECTION INPUT ;
    USE SIGNAL ;
    PORT
      LAYER M5 ;
        RECT  121.872 0 121.896 0.192 ;
    END
  END li[957]
  PIN li[958]
    DIRECTION INPUT ;
    USE SIGNAL ;
    PORT
      LAYER M5 ;
        RECT  121.968 0 121.992 0.192 ;
    END
  END li[958]
  PIN li[959]
    DIRECTION INPUT ;
    USE SIGNAL ;
    PORT
      LAYER M5 ;
        RECT  122.064 0 122.088 0.192 ;
    END
  END li[959]
  PIN li[95]
    DIRECTION INPUT ;
    USE SIGNAL ;
    PORT
      LAYER M5 ;
        RECT  39.12 0 39.144 0.192 ;
    END
  END li[95]
  PIN li[960]
    DIRECTION INPUT ;
    USE SIGNAL ;
    PORT
      LAYER M5 ;
        RECT  122.16 0 122.184 0.192 ;
    END
  END li[960]
  PIN li[961]
    DIRECTION INPUT ;
    USE SIGNAL ;
    PORT
      LAYER M5 ;
        RECT  122.256 0 122.28 0.192 ;
    END
  END li[961]
  PIN li[962]
    DIRECTION INPUT ;
    USE SIGNAL ;
    PORT
      LAYER M5 ;
        RECT  122.352 0 122.376 0.192 ;
    END
  END li[962]
  PIN li[963]
    DIRECTION INPUT ;
    USE SIGNAL ;
    PORT
      LAYER M5 ;
        RECT  122.448 0 122.472 0.192 ;
    END
  END li[963]
  PIN li[964]
    DIRECTION INPUT ;
    USE SIGNAL ;
    PORT
      LAYER M5 ;
        RECT  122.544 0 122.568 0.192 ;
    END
  END li[964]
  PIN li[965]
    DIRECTION INPUT ;
    USE SIGNAL ;
    PORT
      LAYER M5 ;
        RECT  122.64 0 122.664 0.192 ;
    END
  END li[965]
  PIN li[966]
    DIRECTION INPUT ;
    USE SIGNAL ;
    PORT
      LAYER M5 ;
        RECT  122.736 0 122.76 0.192 ;
    END
  END li[966]
  PIN li[967]
    DIRECTION INPUT ;
    USE SIGNAL ;
    PORT
      LAYER M5 ;
        RECT  122.832 0 122.856 0.192 ;
    END
  END li[967]
  PIN li[968]
    DIRECTION INPUT ;
    USE SIGNAL ;
    PORT
      LAYER M5 ;
        RECT  122.928 0 122.952 0.192 ;
    END
  END li[968]
  PIN li[969]
    DIRECTION INPUT ;
    USE SIGNAL ;
    PORT
      LAYER M5 ;
        RECT  123.024 0 123.048 0.192 ;
    END
  END li[969]
  PIN li[96]
    DIRECTION INPUT ;
    USE SIGNAL ;
    PORT
      LAYER M5 ;
        RECT  39.216 0 39.24 0.192 ;
    END
  END li[96]
  PIN li[970]
    DIRECTION INPUT ;
    USE SIGNAL ;
    PORT
      LAYER M5 ;
        RECT  123.12 0 123.144 0.192 ;
    END
  END li[970]
  PIN li[971]
    DIRECTION INPUT ;
    USE SIGNAL ;
    PORT
      LAYER M5 ;
        RECT  123.216 0 123.24 0.192 ;
    END
  END li[971]
  PIN li[972]
    DIRECTION INPUT ;
    USE SIGNAL ;
    PORT
      LAYER M5 ;
        RECT  123.312 0 123.336 0.192 ;
    END
  END li[972]
  PIN li[973]
    DIRECTION INPUT ;
    USE SIGNAL ;
    PORT
      LAYER M5 ;
        RECT  123.408 0 123.432 0.192 ;
    END
  END li[973]
  PIN li[974]
    DIRECTION INPUT ;
    USE SIGNAL ;
    PORT
      LAYER M5 ;
        RECT  123.504 0 123.528 0.192 ;
    END
  END li[974]
  PIN li[975]
    DIRECTION INPUT ;
    USE SIGNAL ;
    PORT
      LAYER M5 ;
        RECT  123.6 0 123.624 0.192 ;
    END
  END li[975]
  PIN li[976]
    DIRECTION INPUT ;
    USE SIGNAL ;
    PORT
      LAYER M5 ;
        RECT  123.696 0 123.72 0.192 ;
    END
  END li[976]
  PIN li[977]
    DIRECTION INPUT ;
    USE SIGNAL ;
    PORT
      LAYER M5 ;
        RECT  123.792 0 123.816 0.192 ;
    END
  END li[977]
  PIN li[978]
    DIRECTION INPUT ;
    USE SIGNAL ;
    PORT
      LAYER M5 ;
        RECT  123.888 0 123.912 0.192 ;
    END
  END li[978]
  PIN li[979]
    DIRECTION INPUT ;
    USE SIGNAL ;
    PORT
      LAYER M5 ;
        RECT  123.984 0 124.008 0.192 ;
    END
  END li[979]
  PIN li[97]
    DIRECTION INPUT ;
    USE SIGNAL ;
    PORT
      LAYER M5 ;
        RECT  39.312 0 39.336 0.192 ;
    END
  END li[97]
  PIN li[980]
    DIRECTION INPUT ;
    USE SIGNAL ;
    PORT
      LAYER M5 ;
        RECT  124.08 0 124.104 0.192 ;
    END
  END li[980]
  PIN li[981]
    DIRECTION INPUT ;
    USE SIGNAL ;
    PORT
      LAYER M5 ;
        RECT  124.176 0 124.2 0.192 ;
    END
  END li[981]
  PIN li[982]
    DIRECTION INPUT ;
    USE SIGNAL ;
    PORT
      LAYER M5 ;
        RECT  124.272 0 124.296 0.192 ;
    END
  END li[982]
  PIN li[983]
    DIRECTION INPUT ;
    USE SIGNAL ;
    PORT
      LAYER M5 ;
        RECT  124.368 0 124.392 0.192 ;
    END
  END li[983]
  PIN li[984]
    DIRECTION INPUT ;
    USE SIGNAL ;
    PORT
      LAYER M5 ;
        RECT  124.464 0 124.488 0.192 ;
    END
  END li[984]
  PIN li[985]
    DIRECTION INPUT ;
    USE SIGNAL ;
    PORT
      LAYER M5 ;
        RECT  124.56 0 124.584 0.192 ;
    END
  END li[985]
  PIN li[986]
    DIRECTION INPUT ;
    USE SIGNAL ;
    PORT
      LAYER M5 ;
        RECT  124.656 0 124.68 0.192 ;
    END
  END li[986]
  PIN li[987]
    DIRECTION INPUT ;
    USE SIGNAL ;
    PORT
      LAYER M5 ;
        RECT  124.752 0 124.776 0.192 ;
    END
  END li[987]
  PIN li[988]
    DIRECTION INPUT ;
    USE SIGNAL ;
    PORT
      LAYER M5 ;
        RECT  124.848 0 124.872 0.192 ;
    END
  END li[988]
  PIN li[989]
    DIRECTION INPUT ;
    USE SIGNAL ;
    PORT
      LAYER M5 ;
        RECT  124.944 0 124.968 0.192 ;
    END
  END li[989]
  PIN li[98]
    DIRECTION INPUT ;
    USE SIGNAL ;
    PORT
      LAYER M5 ;
        RECT  39.408 0 39.432 0.192 ;
    END
  END li[98]
  PIN li[990]
    DIRECTION INPUT ;
    USE SIGNAL ;
    PORT
      LAYER M5 ;
        RECT  125.04 0 125.064 0.192 ;
    END
  END li[990]
  PIN li[991]
    DIRECTION INPUT ;
    USE SIGNAL ;
    PORT
      LAYER M5 ;
        RECT  125.136 0 125.16 0.192 ;
    END
  END li[991]
  PIN li[992]
    DIRECTION INPUT ;
    USE SIGNAL ;
    PORT
      LAYER M5 ;
        RECT  125.232 0 125.256 0.192 ;
    END
  END li[992]
  PIN li[993]
    DIRECTION INPUT ;
    USE SIGNAL ;
    PORT
      LAYER M5 ;
        RECT  125.328 0 125.352 0.192 ;
    END
  END li[993]
  PIN li[994]
    DIRECTION INPUT ;
    USE SIGNAL ;
    PORT
      LAYER M5 ;
        RECT  125.424 0 125.448 0.192 ;
    END
  END li[994]
  PIN li[995]
    DIRECTION INPUT ;
    USE SIGNAL ;
    PORT
      LAYER M5 ;
        RECT  125.52 0 125.544 0.192 ;
    END
  END li[995]
  PIN li[996]
    DIRECTION INPUT ;
    USE SIGNAL ;
    PORT
      LAYER M5 ;
        RECT  125.616 0 125.64 0.192 ;
    END
  END li[996]
  PIN li[997]
    DIRECTION INPUT ;
    USE SIGNAL ;
    PORT
      LAYER M5 ;
        RECT  125.712 0 125.736 0.192 ;
    END
  END li[997]
  PIN li[998]
    DIRECTION INPUT ;
    USE SIGNAL ;
    PORT
      LAYER M5 ;
        RECT  125.808 0 125.832 0.192 ;
    END
  END li[998]
  PIN li[999]
    DIRECTION INPUT ;
    USE SIGNAL ;
    PORT
      LAYER M5 ;
        RECT  125.904 0 125.928 0.192 ;
    END
  END li[999]
  PIN li[99]
    DIRECTION INPUT ;
    USE SIGNAL ;
    PORT
      LAYER M5 ;
        RECT  39.504 0 39.528 0.192 ;
    END
  END li[99]
  PIN li[9]
    DIRECTION INPUT ;
    USE SIGNAL ;
    PORT
      LAYER M5 ;
        RECT  30.864 0 30.888 0.192 ;
    END
  END li[9]
  PIN r0a[0]
    DIRECTION OUTPUT ;
    USE SIGNAL ;
    PORT
      LAYER M4 ;
        RECT  215.832 123.6 216.024 123.624 ;
    END
  END r0a[0]
  PIN r0a[100]
    DIRECTION OUTPUT ;
    USE SIGNAL ;
    PORT
      LAYER M4 ;
        RECT  215.832 133.2 216.024 133.224 ;
    END
  END r0a[100]
  PIN r0a[101]
    DIRECTION OUTPUT ;
    USE SIGNAL ;
    PORT
      LAYER M4 ;
        RECT  215.832 133.296 216.024 133.32 ;
    END
  END r0a[101]
  PIN r0a[102]
    DIRECTION OUTPUT ;
    USE SIGNAL ;
    PORT
      LAYER M4 ;
        RECT  215.832 133.392 216.024 133.416 ;
    END
  END r0a[102]
  PIN r0a[103]
    DIRECTION OUTPUT ;
    USE SIGNAL ;
    PORT
      LAYER M4 ;
        RECT  215.832 133.488 216.024 133.512 ;
    END
  END r0a[103]
  PIN r0a[104]
    DIRECTION OUTPUT ;
    USE SIGNAL ;
    PORT
      LAYER M4 ;
        RECT  215.832 133.584 216.024 133.608 ;
    END
  END r0a[104]
  PIN r0a[105]
    DIRECTION OUTPUT ;
    USE SIGNAL ;
    PORT
      LAYER M4 ;
        RECT  215.832 133.68 216.024 133.704 ;
    END
  END r0a[105]
  PIN r0a[106]
    DIRECTION OUTPUT ;
    USE SIGNAL ;
    PORT
      LAYER M4 ;
        RECT  215.832 133.776 216.024 133.8 ;
    END
  END r0a[106]
  PIN r0a[107]
    DIRECTION OUTPUT ;
    USE SIGNAL ;
    PORT
      LAYER M4 ;
        RECT  215.832 133.872 216.024 133.896 ;
    END
  END r0a[107]
  PIN r0a[108]
    DIRECTION OUTPUT ;
    USE SIGNAL ;
    PORT
      LAYER M4 ;
        RECT  215.832 133.968 216.024 133.992 ;
    END
  END r0a[108]
  PIN r0a[109]
    DIRECTION OUTPUT ;
    USE SIGNAL ;
    PORT
      LAYER M4 ;
        RECT  215.832 134.064 216.024 134.088 ;
    END
  END r0a[109]
  PIN r0a[10]
    DIRECTION OUTPUT ;
    USE SIGNAL ;
    PORT
      LAYER M4 ;
        RECT  215.832 124.56 216.024 124.584 ;
    END
  END r0a[10]
  PIN r0a[110]
    DIRECTION OUTPUT ;
    USE SIGNAL ;
    PORT
      LAYER M4 ;
        RECT  215.832 134.16 216.024 134.184 ;
    END
  END r0a[110]
  PIN r0a[111]
    DIRECTION OUTPUT ;
    USE SIGNAL ;
    PORT
      LAYER M4 ;
        RECT  215.832 134.256 216.024 134.28 ;
    END
  END r0a[111]
  PIN r0a[112]
    DIRECTION OUTPUT ;
    USE SIGNAL ;
    PORT
      LAYER M4 ;
        RECT  215.832 134.352 216.024 134.376 ;
    END
  END r0a[112]
  PIN r0a[113]
    DIRECTION OUTPUT ;
    USE SIGNAL ;
    PORT
      LAYER M4 ;
        RECT  215.832 134.448 216.024 134.472 ;
    END
  END r0a[113]
  PIN r0a[114]
    DIRECTION OUTPUT ;
    USE SIGNAL ;
    PORT
      LAYER M4 ;
        RECT  215.832 134.544 216.024 134.568 ;
    END
  END r0a[114]
  PIN r0a[115]
    DIRECTION OUTPUT ;
    USE SIGNAL ;
    PORT
      LAYER M4 ;
        RECT  215.832 134.64 216.024 134.664 ;
    END
  END r0a[115]
  PIN r0a[116]
    DIRECTION OUTPUT ;
    USE SIGNAL ;
    PORT
      LAYER M4 ;
        RECT  215.832 134.736 216.024 134.76 ;
    END
  END r0a[116]
  PIN r0a[117]
    DIRECTION OUTPUT ;
    USE SIGNAL ;
    PORT
      LAYER M4 ;
        RECT  215.832 134.832 216.024 134.856 ;
    END
  END r0a[117]
  PIN r0a[118]
    DIRECTION OUTPUT ;
    USE SIGNAL ;
    PORT
      LAYER M4 ;
        RECT  215.832 134.928 216.024 134.952 ;
    END
  END r0a[118]
  PIN r0a[119]
    DIRECTION OUTPUT ;
    USE SIGNAL ;
    PORT
      LAYER M4 ;
        RECT  215.832 135.024 216.024 135.048 ;
    END
  END r0a[119]
  PIN r0a[11]
    DIRECTION OUTPUT ;
    USE SIGNAL ;
    PORT
      LAYER M4 ;
        RECT  215.832 124.656 216.024 124.68 ;
    END
  END r0a[11]
  PIN r0a[120]
    DIRECTION OUTPUT ;
    USE SIGNAL ;
    PORT
      LAYER M4 ;
        RECT  215.832 135.12 216.024 135.144 ;
    END
  END r0a[120]
  PIN r0a[121]
    DIRECTION OUTPUT ;
    USE SIGNAL ;
    PORT
      LAYER M4 ;
        RECT  215.832 135.216 216.024 135.24 ;
    END
  END r0a[121]
  PIN r0a[122]
    DIRECTION OUTPUT ;
    USE SIGNAL ;
    PORT
      LAYER M4 ;
        RECT  215.832 135.312 216.024 135.336 ;
    END
  END r0a[122]
  PIN r0a[123]
    DIRECTION OUTPUT ;
    USE SIGNAL ;
    PORT
      LAYER M4 ;
        RECT  215.832 135.408 216.024 135.432 ;
    END
  END r0a[123]
  PIN r0a[124]
    DIRECTION OUTPUT ;
    USE SIGNAL ;
    PORT
      LAYER M4 ;
        RECT  215.832 135.504 216.024 135.528 ;
    END
  END r0a[124]
  PIN r0a[125]
    DIRECTION OUTPUT ;
    USE SIGNAL ;
    PORT
      LAYER M4 ;
        RECT  215.832 135.6 216.024 135.624 ;
    END
  END r0a[125]
  PIN r0a[126]
    DIRECTION OUTPUT ;
    USE SIGNAL ;
    PORT
      LAYER M4 ;
        RECT  215.832 135.696 216.024 135.72 ;
    END
  END r0a[126]
  PIN r0a[127]
    DIRECTION OUTPUT ;
    USE SIGNAL ;
    PORT
      LAYER M4 ;
        RECT  215.832 135.792 216.024 135.816 ;
    END
  END r0a[127]
  PIN r0a[128]
    DIRECTION OUTPUT ;
    USE SIGNAL ;
    PORT
      LAYER M4 ;
        RECT  215.832 135.888 216.024 135.912 ;
    END
  END r0a[128]
  PIN r0a[129]
    DIRECTION OUTPUT ;
    USE SIGNAL ;
    PORT
      LAYER M4 ;
        RECT  215.832 135.984 216.024 136.008 ;
    END
  END r0a[129]
  PIN r0a[12]
    DIRECTION OUTPUT ;
    USE SIGNAL ;
    PORT
      LAYER M4 ;
        RECT  215.832 124.752 216.024 124.776 ;
    END
  END r0a[12]
  PIN r0a[130]
    DIRECTION OUTPUT ;
    USE SIGNAL ;
    PORT
      LAYER M4 ;
        RECT  215.832 136.08 216.024 136.104 ;
    END
  END r0a[130]
  PIN r0a[131]
    DIRECTION OUTPUT ;
    USE SIGNAL ;
    PORT
      LAYER M4 ;
        RECT  215.832 136.176 216.024 136.2 ;
    END
  END r0a[131]
  PIN r0a[132]
    DIRECTION OUTPUT ;
    USE SIGNAL ;
    PORT
      LAYER M4 ;
        RECT  215.832 136.272 216.024 136.296 ;
    END
  END r0a[132]
  PIN r0a[133]
    DIRECTION OUTPUT ;
    USE SIGNAL ;
    PORT
      LAYER M4 ;
        RECT  215.832 136.368 216.024 136.392 ;
    END
  END r0a[133]
  PIN r0a[134]
    DIRECTION OUTPUT ;
    USE SIGNAL ;
    PORT
      LAYER M4 ;
        RECT  215.832 136.464 216.024 136.488 ;
    END
  END r0a[134]
  PIN r0a[135]
    DIRECTION OUTPUT ;
    USE SIGNAL ;
    PORT
      LAYER M4 ;
        RECT  215.832 136.56 216.024 136.584 ;
    END
  END r0a[135]
  PIN r0a[136]
    DIRECTION OUTPUT ;
    USE SIGNAL ;
    PORT
      LAYER M4 ;
        RECT  215.832 136.656 216.024 136.68 ;
    END
  END r0a[136]
  PIN r0a[137]
    DIRECTION OUTPUT ;
    USE SIGNAL ;
    PORT
      LAYER M4 ;
        RECT  215.832 136.752 216.024 136.776 ;
    END
  END r0a[137]
  PIN r0a[138]
    DIRECTION OUTPUT ;
    USE SIGNAL ;
    PORT
      LAYER M4 ;
        RECT  215.832 136.848 216.024 136.872 ;
    END
  END r0a[138]
  PIN r0a[139]
    DIRECTION OUTPUT ;
    USE SIGNAL ;
    PORT
      LAYER M4 ;
        RECT  215.832 136.944 216.024 136.968 ;
    END
  END r0a[139]
  PIN r0a[13]
    DIRECTION OUTPUT ;
    USE SIGNAL ;
    PORT
      LAYER M4 ;
        RECT  215.832 124.848 216.024 124.872 ;
    END
  END r0a[13]
  PIN r0a[140]
    DIRECTION OUTPUT ;
    USE SIGNAL ;
    PORT
      LAYER M4 ;
        RECT  215.832 137.04 216.024 137.064 ;
    END
  END r0a[140]
  PIN r0a[141]
    DIRECTION OUTPUT ;
    USE SIGNAL ;
    PORT
      LAYER M4 ;
        RECT  215.832 137.136 216.024 137.16 ;
    END
  END r0a[141]
  PIN r0a[142]
    DIRECTION OUTPUT ;
    USE SIGNAL ;
    PORT
      LAYER M4 ;
        RECT  215.832 137.232 216.024 137.256 ;
    END
  END r0a[142]
  PIN r0a[143]
    DIRECTION OUTPUT ;
    USE SIGNAL ;
    PORT
      LAYER M4 ;
        RECT  215.832 137.328 216.024 137.352 ;
    END
  END r0a[143]
  PIN r0a[144]
    DIRECTION OUTPUT ;
    USE SIGNAL ;
    PORT
      LAYER M4 ;
        RECT  215.832 137.424 216.024 137.448 ;
    END
  END r0a[144]
  PIN r0a[145]
    DIRECTION OUTPUT ;
    USE SIGNAL ;
    PORT
      LAYER M4 ;
        RECT  215.832 137.52 216.024 137.544 ;
    END
  END r0a[145]
  PIN r0a[146]
    DIRECTION OUTPUT ;
    USE SIGNAL ;
    PORT
      LAYER M4 ;
        RECT  215.832 137.616 216.024 137.64 ;
    END
  END r0a[146]
  PIN r0a[147]
    DIRECTION OUTPUT ;
    USE SIGNAL ;
    PORT
      LAYER M4 ;
        RECT  215.832 137.712 216.024 137.736 ;
    END
  END r0a[147]
  PIN r0a[148]
    DIRECTION OUTPUT ;
    USE SIGNAL ;
    PORT
      LAYER M4 ;
        RECT  215.832 137.808 216.024 137.832 ;
    END
  END r0a[148]
  PIN r0a[149]
    DIRECTION OUTPUT ;
    USE SIGNAL ;
    PORT
      LAYER M4 ;
        RECT  215.832 137.904 216.024 137.928 ;
    END
  END r0a[149]
  PIN r0a[14]
    DIRECTION OUTPUT ;
    USE SIGNAL ;
    PORT
      LAYER M4 ;
        RECT  215.832 124.944 216.024 124.968 ;
    END
  END r0a[14]
  PIN r0a[150]
    DIRECTION OUTPUT ;
    USE SIGNAL ;
    PORT
      LAYER M4 ;
        RECT  215.832 138 216.024 138.024 ;
    END
  END r0a[150]
  PIN r0a[151]
    DIRECTION OUTPUT ;
    USE SIGNAL ;
    PORT
      LAYER M4 ;
        RECT  215.832 138.096 216.024 138.12 ;
    END
  END r0a[151]
  PIN r0a[152]
    DIRECTION OUTPUT ;
    USE SIGNAL ;
    PORT
      LAYER M4 ;
        RECT  215.832 138.192 216.024 138.216 ;
    END
  END r0a[152]
  PIN r0a[153]
    DIRECTION OUTPUT ;
    USE SIGNAL ;
    PORT
      LAYER M4 ;
        RECT  215.832 138.288 216.024 138.312 ;
    END
  END r0a[153]
  PIN r0a[154]
    DIRECTION OUTPUT ;
    USE SIGNAL ;
    PORT
      LAYER M4 ;
        RECT  215.832 138.384 216.024 138.408 ;
    END
  END r0a[154]
  PIN r0a[155]
    DIRECTION OUTPUT ;
    USE SIGNAL ;
    PORT
      LAYER M4 ;
        RECT  215.832 138.48 216.024 138.504 ;
    END
  END r0a[155]
  PIN r0a[156]
    DIRECTION OUTPUT ;
    USE SIGNAL ;
    PORT
      LAYER M4 ;
        RECT  215.832 138.576 216.024 138.6 ;
    END
  END r0a[156]
  PIN r0a[157]
    DIRECTION OUTPUT ;
    USE SIGNAL ;
    PORT
      LAYER M4 ;
        RECT  215.832 138.672 216.024 138.696 ;
    END
  END r0a[157]
  PIN r0a[158]
    DIRECTION OUTPUT ;
    USE SIGNAL ;
    PORT
      LAYER M4 ;
        RECT  215.832 138.768 216.024 138.792 ;
    END
  END r0a[158]
  PIN r0a[159]
    DIRECTION OUTPUT ;
    USE SIGNAL ;
    PORT
      LAYER M4 ;
        RECT  215.832 138.864 216.024 138.888 ;
    END
  END r0a[159]
  PIN r0a[15]
    DIRECTION OUTPUT ;
    USE SIGNAL ;
    PORT
      LAYER M4 ;
        RECT  215.832 125.04 216.024 125.064 ;
    END
  END r0a[15]
  PIN r0a[160]
    DIRECTION OUTPUT ;
    USE SIGNAL ;
    PORT
      LAYER M4 ;
        RECT  215.832 138.96 216.024 138.984 ;
    END
  END r0a[160]
  PIN r0a[161]
    DIRECTION OUTPUT ;
    USE SIGNAL ;
    PORT
      LAYER M4 ;
        RECT  215.832 139.056 216.024 139.08 ;
    END
  END r0a[161]
  PIN r0a[162]
    DIRECTION OUTPUT ;
    USE SIGNAL ;
    PORT
      LAYER M4 ;
        RECT  215.832 139.152 216.024 139.176 ;
    END
  END r0a[162]
  PIN r0a[163]
    DIRECTION OUTPUT ;
    USE SIGNAL ;
    PORT
      LAYER M4 ;
        RECT  215.832 139.248 216.024 139.272 ;
    END
  END r0a[163]
  PIN r0a[164]
    DIRECTION OUTPUT ;
    USE SIGNAL ;
    PORT
      LAYER M4 ;
        RECT  215.832 139.344 216.024 139.368 ;
    END
  END r0a[164]
  PIN r0a[165]
    DIRECTION OUTPUT ;
    USE SIGNAL ;
    PORT
      LAYER M4 ;
        RECT  215.832 139.44 216.024 139.464 ;
    END
  END r0a[165]
  PIN r0a[166]
    DIRECTION OUTPUT ;
    USE SIGNAL ;
    PORT
      LAYER M4 ;
        RECT  215.832 139.536 216.024 139.56 ;
    END
  END r0a[166]
  PIN r0a[167]
    DIRECTION OUTPUT ;
    USE SIGNAL ;
    PORT
      LAYER M4 ;
        RECT  215.832 139.632 216.024 139.656 ;
    END
  END r0a[167]
  PIN r0a[168]
    DIRECTION OUTPUT ;
    USE SIGNAL ;
    PORT
      LAYER M4 ;
        RECT  215.832 139.728 216.024 139.752 ;
    END
  END r0a[168]
  PIN r0a[169]
    DIRECTION OUTPUT ;
    USE SIGNAL ;
    PORT
      LAYER M4 ;
        RECT  215.832 139.824 216.024 139.848 ;
    END
  END r0a[169]
  PIN r0a[16]
    DIRECTION OUTPUT ;
    USE SIGNAL ;
    PORT
      LAYER M4 ;
        RECT  215.832 125.136 216.024 125.16 ;
    END
  END r0a[16]
  PIN r0a[170]
    DIRECTION OUTPUT ;
    USE SIGNAL ;
    PORT
      LAYER M4 ;
        RECT  215.832 139.92 216.024 139.944 ;
    END
  END r0a[170]
  PIN r0a[171]
    DIRECTION OUTPUT ;
    USE SIGNAL ;
    PORT
      LAYER M4 ;
        RECT  215.832 140.016 216.024 140.04 ;
    END
  END r0a[171]
  PIN r0a[172]
    DIRECTION OUTPUT ;
    USE SIGNAL ;
    PORT
      LAYER M4 ;
        RECT  215.832 140.112 216.024 140.136 ;
    END
  END r0a[172]
  PIN r0a[173]
    DIRECTION OUTPUT ;
    USE SIGNAL ;
    PORT
      LAYER M4 ;
        RECT  215.832 140.208 216.024 140.232 ;
    END
  END r0a[173]
  PIN r0a[174]
    DIRECTION OUTPUT ;
    USE SIGNAL ;
    PORT
      LAYER M4 ;
        RECT  215.832 140.304 216.024 140.328 ;
    END
  END r0a[174]
  PIN r0a[175]
    DIRECTION OUTPUT ;
    USE SIGNAL ;
    PORT
      LAYER M4 ;
        RECT  215.832 140.4 216.024 140.424 ;
    END
  END r0a[175]
  PIN r0a[176]
    DIRECTION OUTPUT ;
    USE SIGNAL ;
    PORT
      LAYER M4 ;
        RECT  215.832 140.496 216.024 140.52 ;
    END
  END r0a[176]
  PIN r0a[177]
    DIRECTION OUTPUT ;
    USE SIGNAL ;
    PORT
      LAYER M4 ;
        RECT  215.832 140.592 216.024 140.616 ;
    END
  END r0a[177]
  PIN r0a[178]
    DIRECTION OUTPUT ;
    USE SIGNAL ;
    PORT
      LAYER M4 ;
        RECT  215.832 140.688 216.024 140.712 ;
    END
  END r0a[178]
  PIN r0a[179]
    DIRECTION OUTPUT ;
    USE SIGNAL ;
    PORT
      LAYER M4 ;
        RECT  215.832 140.784 216.024 140.808 ;
    END
  END r0a[179]
  PIN r0a[17]
    DIRECTION OUTPUT ;
    USE SIGNAL ;
    PORT
      LAYER M4 ;
        RECT  215.832 125.232 216.024 125.256 ;
    END
  END r0a[17]
  PIN r0a[180]
    DIRECTION OUTPUT ;
    USE SIGNAL ;
    PORT
      LAYER M4 ;
        RECT  215.832 140.88 216.024 140.904 ;
    END
  END r0a[180]
  PIN r0a[181]
    DIRECTION OUTPUT ;
    USE SIGNAL ;
    PORT
      LAYER M4 ;
        RECT  215.832 140.976 216.024 141 ;
    END
  END r0a[181]
  PIN r0a[182]
    DIRECTION OUTPUT ;
    USE SIGNAL ;
    PORT
      LAYER M4 ;
        RECT  215.832 141.072 216.024 141.096 ;
    END
  END r0a[182]
  PIN r0a[183]
    DIRECTION OUTPUT ;
    USE SIGNAL ;
    PORT
      LAYER M4 ;
        RECT  215.832 141.168 216.024 141.192 ;
    END
  END r0a[183]
  PIN r0a[184]
    DIRECTION OUTPUT ;
    USE SIGNAL ;
    PORT
      LAYER M4 ;
        RECT  215.832 141.264 216.024 141.288 ;
    END
  END r0a[184]
  PIN r0a[185]
    DIRECTION OUTPUT ;
    USE SIGNAL ;
    PORT
      LAYER M4 ;
        RECT  215.832 141.36 216.024 141.384 ;
    END
  END r0a[185]
  PIN r0a[186]
    DIRECTION OUTPUT ;
    USE SIGNAL ;
    PORT
      LAYER M4 ;
        RECT  215.832 141.456 216.024 141.48 ;
    END
  END r0a[186]
  PIN r0a[187]
    DIRECTION OUTPUT ;
    USE SIGNAL ;
    PORT
      LAYER M4 ;
        RECT  215.832 141.552 216.024 141.576 ;
    END
  END r0a[187]
  PIN r0a[188]
    DIRECTION OUTPUT ;
    USE SIGNAL ;
    PORT
      LAYER M4 ;
        RECT  215.832 141.648 216.024 141.672 ;
    END
  END r0a[188]
  PIN r0a[189]
    DIRECTION OUTPUT ;
    USE SIGNAL ;
    PORT
      LAYER M4 ;
        RECT  215.832 141.744 216.024 141.768 ;
    END
  END r0a[189]
  PIN r0a[18]
    DIRECTION OUTPUT ;
    USE SIGNAL ;
    PORT
      LAYER M4 ;
        RECT  215.832 125.328 216.024 125.352 ;
    END
  END r0a[18]
  PIN r0a[190]
    DIRECTION OUTPUT ;
    USE SIGNAL ;
    PORT
      LAYER M4 ;
        RECT  215.832 141.84 216.024 141.864 ;
    END
  END r0a[190]
  PIN r0a[191]
    DIRECTION OUTPUT ;
    USE SIGNAL ;
    PORT
      LAYER M4 ;
        RECT  215.832 141.936 216.024 141.96 ;
    END
  END r0a[191]
  PIN r0a[192]
    DIRECTION OUTPUT ;
    USE SIGNAL ;
    PORT
      LAYER M4 ;
        RECT  215.832 142.032 216.024 142.056 ;
    END
  END r0a[192]
  PIN r0a[193]
    DIRECTION OUTPUT ;
    USE SIGNAL ;
    PORT
      LAYER M4 ;
        RECT  215.832 142.128 216.024 142.152 ;
    END
  END r0a[193]
  PIN r0a[194]
    DIRECTION OUTPUT ;
    USE SIGNAL ;
    PORT
      LAYER M4 ;
        RECT  215.832 142.224 216.024 142.248 ;
    END
  END r0a[194]
  PIN r0a[195]
    DIRECTION OUTPUT ;
    USE SIGNAL ;
    PORT
      LAYER M4 ;
        RECT  215.832 142.32 216.024 142.344 ;
    END
  END r0a[195]
  PIN r0a[196]
    DIRECTION OUTPUT ;
    USE SIGNAL ;
    PORT
      LAYER M4 ;
        RECT  215.832 142.416 216.024 142.44 ;
    END
  END r0a[196]
  PIN r0a[197]
    DIRECTION OUTPUT ;
    USE SIGNAL ;
    PORT
      LAYER M4 ;
        RECT  215.832 142.512 216.024 142.536 ;
    END
  END r0a[197]
  PIN r0a[198]
    DIRECTION OUTPUT ;
    USE SIGNAL ;
    PORT
      LAYER M4 ;
        RECT  215.832 142.608 216.024 142.632 ;
    END
  END r0a[198]
  PIN r0a[199]
    DIRECTION OUTPUT ;
    USE SIGNAL ;
    PORT
      LAYER M4 ;
        RECT  215.832 142.704 216.024 142.728 ;
    END
  END r0a[199]
  PIN r0a[19]
    DIRECTION OUTPUT ;
    USE SIGNAL ;
    PORT
      LAYER M4 ;
        RECT  215.832 125.424 216.024 125.448 ;
    END
  END r0a[19]
  PIN r0a[1]
    DIRECTION OUTPUT ;
    USE SIGNAL ;
    PORT
      LAYER M4 ;
        RECT  215.832 123.696 216.024 123.72 ;
    END
  END r0a[1]
  PIN r0a[200]
    DIRECTION OUTPUT ;
    USE SIGNAL ;
    PORT
      LAYER M4 ;
        RECT  215.832 142.8 216.024 142.824 ;
    END
  END r0a[200]
  PIN r0a[201]
    DIRECTION OUTPUT ;
    USE SIGNAL ;
    PORT
      LAYER M4 ;
        RECT  215.832 142.896 216.024 142.92 ;
    END
  END r0a[201]
  PIN r0a[202]
    DIRECTION OUTPUT ;
    USE SIGNAL ;
    PORT
      LAYER M4 ;
        RECT  215.832 142.992 216.024 143.016 ;
    END
  END r0a[202]
  PIN r0a[203]
    DIRECTION OUTPUT ;
    USE SIGNAL ;
    PORT
      LAYER M4 ;
        RECT  215.832 143.088 216.024 143.112 ;
    END
  END r0a[203]
  PIN r0a[204]
    DIRECTION OUTPUT ;
    USE SIGNAL ;
    PORT
      LAYER M4 ;
        RECT  215.832 143.184 216.024 143.208 ;
    END
  END r0a[204]
  PIN r0a[205]
    DIRECTION OUTPUT ;
    USE SIGNAL ;
    PORT
      LAYER M4 ;
        RECT  215.832 143.28 216.024 143.304 ;
    END
  END r0a[205]
  PIN r0a[206]
    DIRECTION OUTPUT ;
    USE SIGNAL ;
    PORT
      LAYER M4 ;
        RECT  215.832 143.376 216.024 143.4 ;
    END
  END r0a[206]
  PIN r0a[207]
    DIRECTION OUTPUT ;
    USE SIGNAL ;
    PORT
      LAYER M4 ;
        RECT  215.832 143.472 216.024 143.496 ;
    END
  END r0a[207]
  PIN r0a[208]
    DIRECTION OUTPUT ;
    USE SIGNAL ;
    PORT
      LAYER M4 ;
        RECT  215.832 143.568 216.024 143.592 ;
    END
  END r0a[208]
  PIN r0a[209]
    DIRECTION OUTPUT ;
    USE SIGNAL ;
    PORT
      LAYER M4 ;
        RECT  215.832 143.664 216.024 143.688 ;
    END
  END r0a[209]
  PIN r0a[20]
    DIRECTION OUTPUT ;
    USE SIGNAL ;
    PORT
      LAYER M4 ;
        RECT  215.832 125.52 216.024 125.544 ;
    END
  END r0a[20]
  PIN r0a[210]
    DIRECTION OUTPUT ;
    USE SIGNAL ;
    PORT
      LAYER M4 ;
        RECT  215.832 143.76 216.024 143.784 ;
    END
  END r0a[210]
  PIN r0a[211]
    DIRECTION OUTPUT ;
    USE SIGNAL ;
    PORT
      LAYER M4 ;
        RECT  215.832 143.856 216.024 143.88 ;
    END
  END r0a[211]
  PIN r0a[212]
    DIRECTION OUTPUT ;
    USE SIGNAL ;
    PORT
      LAYER M4 ;
        RECT  215.832 143.952 216.024 143.976 ;
    END
  END r0a[212]
  PIN r0a[213]
    DIRECTION OUTPUT ;
    USE SIGNAL ;
    PORT
      LAYER M4 ;
        RECT  215.832 144.048 216.024 144.072 ;
    END
  END r0a[213]
  PIN r0a[214]
    DIRECTION OUTPUT ;
    USE SIGNAL ;
    PORT
      LAYER M4 ;
        RECT  215.832 144.144 216.024 144.168 ;
    END
  END r0a[214]
  PIN r0a[215]
    DIRECTION OUTPUT ;
    USE SIGNAL ;
    PORT
      LAYER M4 ;
        RECT  215.832 144.24 216.024 144.264 ;
    END
  END r0a[215]
  PIN r0a[216]
    DIRECTION OUTPUT ;
    USE SIGNAL ;
    PORT
      LAYER M4 ;
        RECT  215.832 144.336 216.024 144.36 ;
    END
  END r0a[216]
  PIN r0a[217]
    DIRECTION OUTPUT ;
    USE SIGNAL ;
    PORT
      LAYER M4 ;
        RECT  215.832 144.432 216.024 144.456 ;
    END
  END r0a[217]
  PIN r0a[218]
    DIRECTION OUTPUT ;
    USE SIGNAL ;
    PORT
      LAYER M4 ;
        RECT  215.832 144.528 216.024 144.552 ;
    END
  END r0a[218]
  PIN r0a[219]
    DIRECTION OUTPUT ;
    USE SIGNAL ;
    PORT
      LAYER M4 ;
        RECT  215.832 144.624 216.024 144.648 ;
    END
  END r0a[219]
  PIN r0a[21]
    DIRECTION OUTPUT ;
    USE SIGNAL ;
    PORT
      LAYER M4 ;
        RECT  215.832 125.616 216.024 125.64 ;
    END
  END r0a[21]
  PIN r0a[220]
    DIRECTION OUTPUT ;
    USE SIGNAL ;
    PORT
      LAYER M4 ;
        RECT  215.832 144.72 216.024 144.744 ;
    END
  END r0a[220]
  PIN r0a[221]
    DIRECTION OUTPUT ;
    USE SIGNAL ;
    PORT
      LAYER M4 ;
        RECT  215.832 144.816 216.024 144.84 ;
    END
  END r0a[221]
  PIN r0a[222]
    DIRECTION OUTPUT ;
    USE SIGNAL ;
    PORT
      LAYER M4 ;
        RECT  215.832 144.912 216.024 144.936 ;
    END
  END r0a[222]
  PIN r0a[223]
    DIRECTION OUTPUT ;
    USE SIGNAL ;
    PORT
      LAYER M4 ;
        RECT  215.832 145.008 216.024 145.032 ;
    END
  END r0a[223]
  PIN r0a[224]
    DIRECTION OUTPUT ;
    USE SIGNAL ;
    PORT
      LAYER M4 ;
        RECT  215.832 145.104 216.024 145.128 ;
    END
  END r0a[224]
  PIN r0a[225]
    DIRECTION OUTPUT ;
    USE SIGNAL ;
    PORT
      LAYER M4 ;
        RECT  215.832 145.2 216.024 145.224 ;
    END
  END r0a[225]
  PIN r0a[226]
    DIRECTION OUTPUT ;
    USE SIGNAL ;
    PORT
      LAYER M4 ;
        RECT  215.832 145.296 216.024 145.32 ;
    END
  END r0a[226]
  PIN r0a[227]
    DIRECTION OUTPUT ;
    USE SIGNAL ;
    PORT
      LAYER M4 ;
        RECT  215.832 145.392 216.024 145.416 ;
    END
  END r0a[227]
  PIN r0a[228]
    DIRECTION OUTPUT ;
    USE SIGNAL ;
    PORT
      LAYER M4 ;
        RECT  215.832 145.488 216.024 145.512 ;
    END
  END r0a[228]
  PIN r0a[229]
    DIRECTION OUTPUT ;
    USE SIGNAL ;
    PORT
      LAYER M4 ;
        RECT  215.832 145.584 216.024 145.608 ;
    END
  END r0a[229]
  PIN r0a[22]
    DIRECTION OUTPUT ;
    USE SIGNAL ;
    PORT
      LAYER M4 ;
        RECT  215.832 125.712 216.024 125.736 ;
    END
  END r0a[22]
  PIN r0a[230]
    DIRECTION OUTPUT ;
    USE SIGNAL ;
    PORT
      LAYER M4 ;
        RECT  215.832 145.68 216.024 145.704 ;
    END
  END r0a[230]
  PIN r0a[231]
    DIRECTION OUTPUT ;
    USE SIGNAL ;
    PORT
      LAYER M4 ;
        RECT  215.832 145.776 216.024 145.8 ;
    END
  END r0a[231]
  PIN r0a[232]
    DIRECTION OUTPUT ;
    USE SIGNAL ;
    PORT
      LAYER M4 ;
        RECT  215.832 145.872 216.024 145.896 ;
    END
  END r0a[232]
  PIN r0a[233]
    DIRECTION OUTPUT ;
    USE SIGNAL ;
    PORT
      LAYER M4 ;
        RECT  215.832 145.968 216.024 145.992 ;
    END
  END r0a[233]
  PIN r0a[234]
    DIRECTION OUTPUT ;
    USE SIGNAL ;
    PORT
      LAYER M4 ;
        RECT  215.832 146.064 216.024 146.088 ;
    END
  END r0a[234]
  PIN r0a[235]
    DIRECTION OUTPUT ;
    USE SIGNAL ;
    PORT
      LAYER M4 ;
        RECT  215.832 146.16 216.024 146.184 ;
    END
  END r0a[235]
  PIN r0a[236]
    DIRECTION OUTPUT ;
    USE SIGNAL ;
    PORT
      LAYER M4 ;
        RECT  215.832 146.256 216.024 146.28 ;
    END
  END r0a[236]
  PIN r0a[237]
    DIRECTION OUTPUT ;
    USE SIGNAL ;
    PORT
      LAYER M4 ;
        RECT  215.832 146.352 216.024 146.376 ;
    END
  END r0a[237]
  PIN r0a[238]
    DIRECTION OUTPUT ;
    USE SIGNAL ;
    PORT
      LAYER M4 ;
        RECT  215.832 146.448 216.024 146.472 ;
    END
  END r0a[238]
  PIN r0a[239]
    DIRECTION OUTPUT ;
    USE SIGNAL ;
    PORT
      LAYER M4 ;
        RECT  215.832 146.544 216.024 146.568 ;
    END
  END r0a[239]
  PIN r0a[23]
    DIRECTION OUTPUT ;
    USE SIGNAL ;
    PORT
      LAYER M4 ;
        RECT  215.832 125.808 216.024 125.832 ;
    END
  END r0a[23]
  PIN r0a[240]
    DIRECTION OUTPUT ;
    USE SIGNAL ;
    PORT
      LAYER M4 ;
        RECT  215.832 146.64 216.024 146.664 ;
    END
  END r0a[240]
  PIN r0a[241]
    DIRECTION OUTPUT ;
    USE SIGNAL ;
    PORT
      LAYER M4 ;
        RECT  215.832 146.736 216.024 146.76 ;
    END
  END r0a[241]
  PIN r0a[242]
    DIRECTION OUTPUT ;
    USE SIGNAL ;
    PORT
      LAYER M4 ;
        RECT  215.832 146.832 216.024 146.856 ;
    END
  END r0a[242]
  PIN r0a[243]
    DIRECTION OUTPUT ;
    USE SIGNAL ;
    PORT
      LAYER M4 ;
        RECT  215.832 146.928 216.024 146.952 ;
    END
  END r0a[243]
  PIN r0a[244]
    DIRECTION OUTPUT ;
    USE SIGNAL ;
    PORT
      LAYER M4 ;
        RECT  215.832 147.024 216.024 147.048 ;
    END
  END r0a[244]
  PIN r0a[245]
    DIRECTION OUTPUT ;
    USE SIGNAL ;
    PORT
      LAYER M4 ;
        RECT  215.832 147.12 216.024 147.144 ;
    END
  END r0a[245]
  PIN r0a[246]
    DIRECTION OUTPUT ;
    USE SIGNAL ;
    PORT
      LAYER M4 ;
        RECT  215.832 147.216 216.024 147.24 ;
    END
  END r0a[246]
  PIN r0a[247]
    DIRECTION OUTPUT ;
    USE SIGNAL ;
    PORT
      LAYER M4 ;
        RECT  215.832 147.312 216.024 147.336 ;
    END
  END r0a[247]
  PIN r0a[248]
    DIRECTION OUTPUT ;
    USE SIGNAL ;
    PORT
      LAYER M4 ;
        RECT  215.832 147.408 216.024 147.432 ;
    END
  END r0a[248]
  PIN r0a[249]
    DIRECTION OUTPUT ;
    USE SIGNAL ;
    PORT
      LAYER M4 ;
        RECT  215.832 147.504 216.024 147.528 ;
    END
  END r0a[249]
  PIN r0a[24]
    DIRECTION OUTPUT ;
    USE SIGNAL ;
    PORT
      LAYER M4 ;
        RECT  215.832 125.904 216.024 125.928 ;
    END
  END r0a[24]
  PIN r0a[250]
    DIRECTION OUTPUT ;
    USE SIGNAL ;
    PORT
      LAYER M4 ;
        RECT  215.832 147.6 216.024 147.624 ;
    END
  END r0a[250]
  PIN r0a[251]
    DIRECTION OUTPUT ;
    USE SIGNAL ;
    PORT
      LAYER M4 ;
        RECT  215.832 147.696 216.024 147.72 ;
    END
  END r0a[251]
  PIN r0a[252]
    DIRECTION OUTPUT ;
    USE SIGNAL ;
    PORT
      LAYER M4 ;
        RECT  215.832 147.792 216.024 147.816 ;
    END
  END r0a[252]
  PIN r0a[253]
    DIRECTION OUTPUT ;
    USE SIGNAL ;
    PORT
      LAYER M4 ;
        RECT  215.832 147.888 216.024 147.912 ;
    END
  END r0a[253]
  PIN r0a[254]
    DIRECTION OUTPUT ;
    USE SIGNAL ;
    PORT
      LAYER M4 ;
        RECT  215.832 147.984 216.024 148.008 ;
    END
  END r0a[254]
  PIN r0a[255]
    DIRECTION OUTPUT ;
    USE SIGNAL ;
    PORT
      LAYER M4 ;
        RECT  215.832 148.08 216.024 148.104 ;
    END
  END r0a[255]
  PIN r0a[256]
    DIRECTION OUTPUT ;
    USE SIGNAL ;
    PORT
      LAYER M4 ;
        RECT  215.832 148.176 216.024 148.2 ;
    END
  END r0a[256]
  PIN r0a[257]
    DIRECTION OUTPUT ;
    USE SIGNAL ;
    PORT
      LAYER M4 ;
        RECT  215.832 148.272 216.024 148.296 ;
    END
  END r0a[257]
  PIN r0a[258]
    DIRECTION OUTPUT ;
    USE SIGNAL ;
    PORT
      LAYER M4 ;
        RECT  215.832 148.368 216.024 148.392 ;
    END
  END r0a[258]
  PIN r0a[259]
    DIRECTION OUTPUT ;
    USE SIGNAL ;
    PORT
      LAYER M4 ;
        RECT  215.832 148.464 216.024 148.488 ;
    END
  END r0a[259]
  PIN r0a[25]
    DIRECTION OUTPUT ;
    USE SIGNAL ;
    PORT
      LAYER M4 ;
        RECT  215.832 126 216.024 126.024 ;
    END
  END r0a[25]
  PIN r0a[260]
    DIRECTION OUTPUT ;
    USE SIGNAL ;
    PORT
      LAYER M4 ;
        RECT  215.832 148.56 216.024 148.584 ;
    END
  END r0a[260]
  PIN r0a[261]
    DIRECTION OUTPUT ;
    USE SIGNAL ;
    PORT
      LAYER M4 ;
        RECT  215.832 148.656 216.024 148.68 ;
    END
  END r0a[261]
  PIN r0a[262]
    DIRECTION OUTPUT ;
    USE SIGNAL ;
    PORT
      LAYER M4 ;
        RECT  215.832 148.752 216.024 148.776 ;
    END
  END r0a[262]
  PIN r0a[263]
    DIRECTION OUTPUT ;
    USE SIGNAL ;
    PORT
      LAYER M4 ;
        RECT  215.832 148.848 216.024 148.872 ;
    END
  END r0a[263]
  PIN r0a[264]
    DIRECTION OUTPUT ;
    USE SIGNAL ;
    PORT
      LAYER M4 ;
        RECT  215.832 148.944 216.024 148.968 ;
    END
  END r0a[264]
  PIN r0a[265]
    DIRECTION OUTPUT ;
    USE SIGNAL ;
    PORT
      LAYER M4 ;
        RECT  215.832 149.04 216.024 149.064 ;
    END
  END r0a[265]
  PIN r0a[266]
    DIRECTION OUTPUT ;
    USE SIGNAL ;
    PORT
      LAYER M4 ;
        RECT  215.832 149.136 216.024 149.16 ;
    END
  END r0a[266]
  PIN r0a[267]
    DIRECTION OUTPUT ;
    USE SIGNAL ;
    PORT
      LAYER M4 ;
        RECT  215.832 149.232 216.024 149.256 ;
    END
  END r0a[267]
  PIN r0a[268]
    DIRECTION OUTPUT ;
    USE SIGNAL ;
    PORT
      LAYER M4 ;
        RECT  215.832 149.328 216.024 149.352 ;
    END
  END r0a[268]
  PIN r0a[269]
    DIRECTION OUTPUT ;
    USE SIGNAL ;
    PORT
      LAYER M4 ;
        RECT  215.832 149.424 216.024 149.448 ;
    END
  END r0a[269]
  PIN r0a[26]
    DIRECTION OUTPUT ;
    USE SIGNAL ;
    PORT
      LAYER M4 ;
        RECT  215.832 126.096 216.024 126.12 ;
    END
  END r0a[26]
  PIN r0a[270]
    DIRECTION OUTPUT ;
    USE SIGNAL ;
    PORT
      LAYER M4 ;
        RECT  215.832 149.52 216.024 149.544 ;
    END
  END r0a[270]
  PIN r0a[271]
    DIRECTION OUTPUT ;
    USE SIGNAL ;
    PORT
      LAYER M4 ;
        RECT  215.832 149.616 216.024 149.64 ;
    END
  END r0a[271]
  PIN r0a[272]
    DIRECTION OUTPUT ;
    USE SIGNAL ;
    PORT
      LAYER M4 ;
        RECT  215.832 149.712 216.024 149.736 ;
    END
  END r0a[272]
  PIN r0a[273]
    DIRECTION OUTPUT ;
    USE SIGNAL ;
    PORT
      LAYER M4 ;
        RECT  215.832 149.808 216.024 149.832 ;
    END
  END r0a[273]
  PIN r0a[274]
    DIRECTION OUTPUT ;
    USE SIGNAL ;
    PORT
      LAYER M4 ;
        RECT  215.832 149.904 216.024 149.928 ;
    END
  END r0a[274]
  PIN r0a[275]
    DIRECTION OUTPUT ;
    USE SIGNAL ;
    PORT
      LAYER M4 ;
        RECT  215.832 150 216.024 150.024 ;
    END
  END r0a[275]
  PIN r0a[276]
    DIRECTION OUTPUT ;
    USE SIGNAL ;
    PORT
      LAYER M4 ;
        RECT  215.832 150.096 216.024 150.12 ;
    END
  END r0a[276]
  PIN r0a[277]
    DIRECTION OUTPUT ;
    USE SIGNAL ;
    PORT
      LAYER M4 ;
        RECT  215.832 150.192 216.024 150.216 ;
    END
  END r0a[277]
  PIN r0a[278]
    DIRECTION OUTPUT ;
    USE SIGNAL ;
    PORT
      LAYER M4 ;
        RECT  215.832 150.288 216.024 150.312 ;
    END
  END r0a[278]
  PIN r0a[279]
    DIRECTION OUTPUT ;
    USE SIGNAL ;
    PORT
      LAYER M4 ;
        RECT  215.832 150.384 216.024 150.408 ;
    END
  END r0a[279]
  PIN r0a[27]
    DIRECTION OUTPUT ;
    USE SIGNAL ;
    PORT
      LAYER M4 ;
        RECT  215.832 126.192 216.024 126.216 ;
    END
  END r0a[27]
  PIN r0a[280]
    DIRECTION OUTPUT ;
    USE SIGNAL ;
    PORT
      LAYER M4 ;
        RECT  215.832 150.48 216.024 150.504 ;
    END
  END r0a[280]
  PIN r0a[281]
    DIRECTION OUTPUT ;
    USE SIGNAL ;
    PORT
      LAYER M4 ;
        RECT  215.832 150.576 216.024 150.6 ;
    END
  END r0a[281]
  PIN r0a[282]
    DIRECTION OUTPUT ;
    USE SIGNAL ;
    PORT
      LAYER M4 ;
        RECT  215.832 150.672 216.024 150.696 ;
    END
  END r0a[282]
  PIN r0a[283]
    DIRECTION OUTPUT ;
    USE SIGNAL ;
    PORT
      LAYER M4 ;
        RECT  215.832 150.768 216.024 150.792 ;
    END
  END r0a[283]
  PIN r0a[284]
    DIRECTION OUTPUT ;
    USE SIGNAL ;
    PORT
      LAYER M4 ;
        RECT  215.832 150.864 216.024 150.888 ;
    END
  END r0a[284]
  PIN r0a[285]
    DIRECTION OUTPUT ;
    USE SIGNAL ;
    PORT
      LAYER M4 ;
        RECT  215.832 150.96 216.024 150.984 ;
    END
  END r0a[285]
  PIN r0a[286]
    DIRECTION OUTPUT ;
    USE SIGNAL ;
    PORT
      LAYER M4 ;
        RECT  215.832 151.056 216.024 151.08 ;
    END
  END r0a[286]
  PIN r0a[287]
    DIRECTION OUTPUT ;
    USE SIGNAL ;
    PORT
      LAYER M4 ;
        RECT  215.832 151.152 216.024 151.176 ;
    END
  END r0a[287]
  PIN r0a[288]
    DIRECTION OUTPUT ;
    USE SIGNAL ;
    PORT
      LAYER M4 ;
        RECT  215.832 151.248 216.024 151.272 ;
    END
  END r0a[288]
  PIN r0a[289]
    DIRECTION OUTPUT ;
    USE SIGNAL ;
    PORT
      LAYER M4 ;
        RECT  215.832 151.344 216.024 151.368 ;
    END
  END r0a[289]
  PIN r0a[28]
    DIRECTION OUTPUT ;
    USE SIGNAL ;
    PORT
      LAYER M4 ;
        RECT  215.832 126.288 216.024 126.312 ;
    END
  END r0a[28]
  PIN r0a[290]
    DIRECTION OUTPUT ;
    USE SIGNAL ;
    PORT
      LAYER M4 ;
        RECT  215.832 151.44 216.024 151.464 ;
    END
  END r0a[290]
  PIN r0a[291]
    DIRECTION OUTPUT ;
    USE SIGNAL ;
    PORT
      LAYER M4 ;
        RECT  215.832 151.536 216.024 151.56 ;
    END
  END r0a[291]
  PIN r0a[292]
    DIRECTION OUTPUT ;
    USE SIGNAL ;
    PORT
      LAYER M4 ;
        RECT  215.832 151.632 216.024 151.656 ;
    END
  END r0a[292]
  PIN r0a[293]
    DIRECTION OUTPUT ;
    USE SIGNAL ;
    PORT
      LAYER M4 ;
        RECT  215.832 151.728 216.024 151.752 ;
    END
  END r0a[293]
  PIN r0a[294]
    DIRECTION OUTPUT ;
    USE SIGNAL ;
    PORT
      LAYER M4 ;
        RECT  215.832 151.824 216.024 151.848 ;
    END
  END r0a[294]
  PIN r0a[295]
    DIRECTION OUTPUT ;
    USE SIGNAL ;
    PORT
      LAYER M4 ;
        RECT  215.832 151.92 216.024 151.944 ;
    END
  END r0a[295]
  PIN r0a[296]
    DIRECTION OUTPUT ;
    USE SIGNAL ;
    PORT
      LAYER M4 ;
        RECT  215.832 152.016 216.024 152.04 ;
    END
  END r0a[296]
  PIN r0a[297]
    DIRECTION OUTPUT ;
    USE SIGNAL ;
    PORT
      LAYER M4 ;
        RECT  215.832 152.112 216.024 152.136 ;
    END
  END r0a[297]
  PIN r0a[298]
    DIRECTION OUTPUT ;
    USE SIGNAL ;
    PORT
      LAYER M4 ;
        RECT  215.832 152.208 216.024 152.232 ;
    END
  END r0a[298]
  PIN r0a[299]
    DIRECTION OUTPUT ;
    USE SIGNAL ;
    PORT
      LAYER M4 ;
        RECT  215.832 152.304 216.024 152.328 ;
    END
  END r0a[299]
  PIN r0a[29]
    DIRECTION OUTPUT ;
    USE SIGNAL ;
    PORT
      LAYER M4 ;
        RECT  215.832 126.384 216.024 126.408 ;
    END
  END r0a[29]
  PIN r0a[2]
    DIRECTION OUTPUT ;
    USE SIGNAL ;
    PORT
      LAYER M4 ;
        RECT  215.832 123.792 216.024 123.816 ;
    END
  END r0a[2]
  PIN r0a[300]
    DIRECTION OUTPUT ;
    USE SIGNAL ;
    PORT
      LAYER M4 ;
        RECT  215.832 152.4 216.024 152.424 ;
    END
  END r0a[300]
  PIN r0a[301]
    DIRECTION OUTPUT ;
    USE SIGNAL ;
    PORT
      LAYER M4 ;
        RECT  215.832 152.496 216.024 152.52 ;
    END
  END r0a[301]
  PIN r0a[302]
    DIRECTION OUTPUT ;
    USE SIGNAL ;
    PORT
      LAYER M4 ;
        RECT  215.832 152.592 216.024 152.616 ;
    END
  END r0a[302]
  PIN r0a[303]
    DIRECTION OUTPUT ;
    USE SIGNAL ;
    PORT
      LAYER M4 ;
        RECT  215.832 152.688 216.024 152.712 ;
    END
  END r0a[303]
  PIN r0a[304]
    DIRECTION OUTPUT ;
    USE SIGNAL ;
    PORT
      LAYER M4 ;
        RECT  215.832 152.784 216.024 152.808 ;
    END
  END r0a[304]
  PIN r0a[305]
    DIRECTION OUTPUT ;
    USE SIGNAL ;
    PORT
      LAYER M4 ;
        RECT  215.832 152.88 216.024 152.904 ;
    END
  END r0a[305]
  PIN r0a[306]
    DIRECTION OUTPUT ;
    USE SIGNAL ;
    PORT
      LAYER M4 ;
        RECT  215.832 152.976 216.024 153 ;
    END
  END r0a[306]
  PIN r0a[307]
    DIRECTION OUTPUT ;
    USE SIGNAL ;
    PORT
      LAYER M4 ;
        RECT  215.832 153.072 216.024 153.096 ;
    END
  END r0a[307]
  PIN r0a[308]
    DIRECTION OUTPUT ;
    USE SIGNAL ;
    PORT
      LAYER M4 ;
        RECT  215.832 153.168 216.024 153.192 ;
    END
  END r0a[308]
  PIN r0a[309]
    DIRECTION OUTPUT ;
    USE SIGNAL ;
    PORT
      LAYER M4 ;
        RECT  215.832 153.264 216.024 153.288 ;
    END
  END r0a[309]
  PIN r0a[30]
    DIRECTION OUTPUT ;
    USE SIGNAL ;
    PORT
      LAYER M4 ;
        RECT  215.832 126.48 216.024 126.504 ;
    END
  END r0a[30]
  PIN r0a[310]
    DIRECTION OUTPUT ;
    USE SIGNAL ;
    PORT
      LAYER M4 ;
        RECT  215.832 153.36 216.024 153.384 ;
    END
  END r0a[310]
  PIN r0a[311]
    DIRECTION OUTPUT ;
    USE SIGNAL ;
    PORT
      LAYER M4 ;
        RECT  215.832 153.456 216.024 153.48 ;
    END
  END r0a[311]
  PIN r0a[312]
    DIRECTION OUTPUT ;
    USE SIGNAL ;
    PORT
      LAYER M4 ;
        RECT  215.832 153.552 216.024 153.576 ;
    END
  END r0a[312]
  PIN r0a[313]
    DIRECTION OUTPUT ;
    USE SIGNAL ;
    PORT
      LAYER M4 ;
        RECT  215.832 153.648 216.024 153.672 ;
    END
  END r0a[313]
  PIN r0a[314]
    DIRECTION OUTPUT ;
    USE SIGNAL ;
    PORT
      LAYER M4 ;
        RECT  215.832 153.744 216.024 153.768 ;
    END
  END r0a[314]
  PIN r0a[315]
    DIRECTION OUTPUT ;
    USE SIGNAL ;
    PORT
      LAYER M4 ;
        RECT  215.832 153.84 216.024 153.864 ;
    END
  END r0a[315]
  PIN r0a[316]
    DIRECTION OUTPUT ;
    USE SIGNAL ;
    PORT
      LAYER M4 ;
        RECT  215.832 153.936 216.024 153.96 ;
    END
  END r0a[316]
  PIN r0a[317]
    DIRECTION OUTPUT ;
    USE SIGNAL ;
    PORT
      LAYER M4 ;
        RECT  215.832 154.032 216.024 154.056 ;
    END
  END r0a[317]
  PIN r0a[318]
    DIRECTION OUTPUT ;
    USE SIGNAL ;
    PORT
      LAYER M4 ;
        RECT  215.832 154.128 216.024 154.152 ;
    END
  END r0a[318]
  PIN r0a[319]
    DIRECTION OUTPUT ;
    USE SIGNAL ;
    PORT
      LAYER M4 ;
        RECT  215.832 154.224 216.024 154.248 ;
    END
  END r0a[319]
  PIN r0a[31]
    DIRECTION OUTPUT ;
    USE SIGNAL ;
    PORT
      LAYER M4 ;
        RECT  215.832 126.576 216.024 126.6 ;
    END
  END r0a[31]
  PIN r0a[320]
    DIRECTION OUTPUT ;
    USE SIGNAL ;
    PORT
      LAYER M4 ;
        RECT  215.832 154.32 216.024 154.344 ;
    END
  END r0a[320]
  PIN r0a[321]
    DIRECTION OUTPUT ;
    USE SIGNAL ;
    PORT
      LAYER M4 ;
        RECT  215.832 154.416 216.024 154.44 ;
    END
  END r0a[321]
  PIN r0a[322]
    DIRECTION OUTPUT ;
    USE SIGNAL ;
    PORT
      LAYER M4 ;
        RECT  215.832 154.512 216.024 154.536 ;
    END
  END r0a[322]
  PIN r0a[323]
    DIRECTION OUTPUT ;
    USE SIGNAL ;
    PORT
      LAYER M4 ;
        RECT  215.832 154.608 216.024 154.632 ;
    END
  END r0a[323]
  PIN r0a[324]
    DIRECTION OUTPUT ;
    USE SIGNAL ;
    PORT
      LAYER M4 ;
        RECT  215.832 154.704 216.024 154.728 ;
    END
  END r0a[324]
  PIN r0a[325]
    DIRECTION OUTPUT ;
    USE SIGNAL ;
    PORT
      LAYER M4 ;
        RECT  215.832 154.8 216.024 154.824 ;
    END
  END r0a[325]
  PIN r0a[326]
    DIRECTION OUTPUT ;
    USE SIGNAL ;
    PORT
      LAYER M4 ;
        RECT  215.832 154.896 216.024 154.92 ;
    END
  END r0a[326]
  PIN r0a[327]
    DIRECTION OUTPUT ;
    USE SIGNAL ;
    PORT
      LAYER M4 ;
        RECT  215.832 154.992 216.024 155.016 ;
    END
  END r0a[327]
  PIN r0a[328]
    DIRECTION OUTPUT ;
    USE SIGNAL ;
    PORT
      LAYER M4 ;
        RECT  215.832 155.088 216.024 155.112 ;
    END
  END r0a[328]
  PIN r0a[329]
    DIRECTION OUTPUT ;
    USE SIGNAL ;
    PORT
      LAYER M4 ;
        RECT  215.832 155.184 216.024 155.208 ;
    END
  END r0a[329]
  PIN r0a[32]
    DIRECTION OUTPUT ;
    USE SIGNAL ;
    PORT
      LAYER M4 ;
        RECT  215.832 126.672 216.024 126.696 ;
    END
  END r0a[32]
  PIN r0a[330]
    DIRECTION OUTPUT ;
    USE SIGNAL ;
    PORT
      LAYER M4 ;
        RECT  215.832 155.28 216.024 155.304 ;
    END
  END r0a[330]
  PIN r0a[331]
    DIRECTION OUTPUT ;
    USE SIGNAL ;
    PORT
      LAYER M4 ;
        RECT  215.832 155.376 216.024 155.4 ;
    END
  END r0a[331]
  PIN r0a[332]
    DIRECTION OUTPUT ;
    USE SIGNAL ;
    PORT
      LAYER M4 ;
        RECT  215.832 155.472 216.024 155.496 ;
    END
  END r0a[332]
  PIN r0a[333]
    DIRECTION OUTPUT ;
    USE SIGNAL ;
    PORT
      LAYER M4 ;
        RECT  215.832 155.568 216.024 155.592 ;
    END
  END r0a[333]
  PIN r0a[334]
    DIRECTION OUTPUT ;
    USE SIGNAL ;
    PORT
      LAYER M4 ;
        RECT  215.832 155.664 216.024 155.688 ;
    END
  END r0a[334]
  PIN r0a[335]
    DIRECTION OUTPUT ;
    USE SIGNAL ;
    PORT
      LAYER M4 ;
        RECT  215.832 155.76 216.024 155.784 ;
    END
  END r0a[335]
  PIN r0a[336]
    DIRECTION OUTPUT ;
    USE SIGNAL ;
    PORT
      LAYER M4 ;
        RECT  215.832 155.856 216.024 155.88 ;
    END
  END r0a[336]
  PIN r0a[337]
    DIRECTION OUTPUT ;
    USE SIGNAL ;
    PORT
      LAYER M4 ;
        RECT  215.832 155.952 216.024 155.976 ;
    END
  END r0a[337]
  PIN r0a[338]
    DIRECTION OUTPUT ;
    USE SIGNAL ;
    PORT
      LAYER M4 ;
        RECT  215.832 156.048 216.024 156.072 ;
    END
  END r0a[338]
  PIN r0a[339]
    DIRECTION OUTPUT ;
    USE SIGNAL ;
    PORT
      LAYER M4 ;
        RECT  215.832 156.144 216.024 156.168 ;
    END
  END r0a[339]
  PIN r0a[33]
    DIRECTION OUTPUT ;
    USE SIGNAL ;
    PORT
      LAYER M4 ;
        RECT  215.832 126.768 216.024 126.792 ;
    END
  END r0a[33]
  PIN r0a[340]
    DIRECTION OUTPUT ;
    USE SIGNAL ;
    PORT
      LAYER M4 ;
        RECT  215.832 156.24 216.024 156.264 ;
    END
  END r0a[340]
  PIN r0a[341]
    DIRECTION OUTPUT ;
    USE SIGNAL ;
    PORT
      LAYER M4 ;
        RECT  215.832 156.336 216.024 156.36 ;
    END
  END r0a[341]
  PIN r0a[342]
    DIRECTION OUTPUT ;
    USE SIGNAL ;
    PORT
      LAYER M4 ;
        RECT  215.832 156.432 216.024 156.456 ;
    END
  END r0a[342]
  PIN r0a[343]
    DIRECTION OUTPUT ;
    USE SIGNAL ;
    PORT
      LAYER M4 ;
        RECT  215.832 156.528 216.024 156.552 ;
    END
  END r0a[343]
  PIN r0a[344]
    DIRECTION OUTPUT ;
    USE SIGNAL ;
    PORT
      LAYER M4 ;
        RECT  215.832 156.624 216.024 156.648 ;
    END
  END r0a[344]
  PIN r0a[345]
    DIRECTION OUTPUT ;
    USE SIGNAL ;
    PORT
      LAYER M4 ;
        RECT  215.832 156.72 216.024 156.744 ;
    END
  END r0a[345]
  PIN r0a[346]
    DIRECTION OUTPUT ;
    USE SIGNAL ;
    PORT
      LAYER M4 ;
        RECT  215.832 156.816 216.024 156.84 ;
    END
  END r0a[346]
  PIN r0a[347]
    DIRECTION OUTPUT ;
    USE SIGNAL ;
    PORT
      LAYER M4 ;
        RECT  215.832 156.912 216.024 156.936 ;
    END
  END r0a[347]
  PIN r0a[348]
    DIRECTION OUTPUT ;
    USE SIGNAL ;
    PORT
      LAYER M4 ;
        RECT  215.832 157.008 216.024 157.032 ;
    END
  END r0a[348]
  PIN r0a[349]
    DIRECTION OUTPUT ;
    USE SIGNAL ;
    PORT
      LAYER M4 ;
        RECT  215.832 157.104 216.024 157.128 ;
    END
  END r0a[349]
  PIN r0a[34]
    DIRECTION OUTPUT ;
    USE SIGNAL ;
    PORT
      LAYER M4 ;
        RECT  215.832 126.864 216.024 126.888 ;
    END
  END r0a[34]
  PIN r0a[350]
    DIRECTION OUTPUT ;
    USE SIGNAL ;
    PORT
      LAYER M4 ;
        RECT  215.832 157.2 216.024 157.224 ;
    END
  END r0a[350]
  PIN r0a[351]
    DIRECTION OUTPUT ;
    USE SIGNAL ;
    PORT
      LAYER M4 ;
        RECT  215.832 157.296 216.024 157.32 ;
    END
  END r0a[351]
  PIN r0a[352]
    DIRECTION OUTPUT ;
    USE SIGNAL ;
    PORT
      LAYER M4 ;
        RECT  215.832 157.392 216.024 157.416 ;
    END
  END r0a[352]
  PIN r0a[353]
    DIRECTION OUTPUT ;
    USE SIGNAL ;
    PORT
      LAYER M4 ;
        RECT  215.832 157.488 216.024 157.512 ;
    END
  END r0a[353]
  PIN r0a[354]
    DIRECTION OUTPUT ;
    USE SIGNAL ;
    PORT
      LAYER M4 ;
        RECT  215.832 157.584 216.024 157.608 ;
    END
  END r0a[354]
  PIN r0a[355]
    DIRECTION OUTPUT ;
    USE SIGNAL ;
    PORT
      LAYER M4 ;
        RECT  215.832 157.68 216.024 157.704 ;
    END
  END r0a[355]
  PIN r0a[356]
    DIRECTION OUTPUT ;
    USE SIGNAL ;
    PORT
      LAYER M4 ;
        RECT  215.832 157.776 216.024 157.8 ;
    END
  END r0a[356]
  PIN r0a[357]
    DIRECTION OUTPUT ;
    USE SIGNAL ;
    PORT
      LAYER M4 ;
        RECT  215.832 157.872 216.024 157.896 ;
    END
  END r0a[357]
  PIN r0a[358]
    DIRECTION OUTPUT ;
    USE SIGNAL ;
    PORT
      LAYER M4 ;
        RECT  215.832 157.968 216.024 157.992 ;
    END
  END r0a[358]
  PIN r0a[359]
    DIRECTION OUTPUT ;
    USE SIGNAL ;
    PORT
      LAYER M4 ;
        RECT  215.832 158.064 216.024 158.088 ;
    END
  END r0a[359]
  PIN r0a[35]
    DIRECTION OUTPUT ;
    USE SIGNAL ;
    PORT
      LAYER M4 ;
        RECT  215.832 126.96 216.024 126.984 ;
    END
  END r0a[35]
  PIN r0a[360]
    DIRECTION OUTPUT ;
    USE SIGNAL ;
    PORT
      LAYER M4 ;
        RECT  215.832 158.16 216.024 158.184 ;
    END
  END r0a[360]
  PIN r0a[361]
    DIRECTION OUTPUT ;
    USE SIGNAL ;
    PORT
      LAYER M4 ;
        RECT  215.832 158.256 216.024 158.28 ;
    END
  END r0a[361]
  PIN r0a[362]
    DIRECTION OUTPUT ;
    USE SIGNAL ;
    PORT
      LAYER M4 ;
        RECT  215.832 158.352 216.024 158.376 ;
    END
  END r0a[362]
  PIN r0a[363]
    DIRECTION OUTPUT ;
    USE SIGNAL ;
    PORT
      LAYER M4 ;
        RECT  215.832 158.448 216.024 158.472 ;
    END
  END r0a[363]
  PIN r0a[364]
    DIRECTION OUTPUT ;
    USE SIGNAL ;
    PORT
      LAYER M4 ;
        RECT  215.832 158.544 216.024 158.568 ;
    END
  END r0a[364]
  PIN r0a[365]
    DIRECTION OUTPUT ;
    USE SIGNAL ;
    PORT
      LAYER M4 ;
        RECT  215.832 158.64 216.024 158.664 ;
    END
  END r0a[365]
  PIN r0a[366]
    DIRECTION OUTPUT ;
    USE SIGNAL ;
    PORT
      LAYER M4 ;
        RECT  215.832 158.736 216.024 158.76 ;
    END
  END r0a[366]
  PIN r0a[367]
    DIRECTION OUTPUT ;
    USE SIGNAL ;
    PORT
      LAYER M4 ;
        RECT  215.832 158.832 216.024 158.856 ;
    END
  END r0a[367]
  PIN r0a[368]
    DIRECTION OUTPUT ;
    USE SIGNAL ;
    PORT
      LAYER M4 ;
        RECT  215.832 158.928 216.024 158.952 ;
    END
  END r0a[368]
  PIN r0a[369]
    DIRECTION OUTPUT ;
    USE SIGNAL ;
    PORT
      LAYER M4 ;
        RECT  215.832 159.024 216.024 159.048 ;
    END
  END r0a[369]
  PIN r0a[36]
    DIRECTION OUTPUT ;
    USE SIGNAL ;
    PORT
      LAYER M4 ;
        RECT  215.832 127.056 216.024 127.08 ;
    END
  END r0a[36]
  PIN r0a[370]
    DIRECTION OUTPUT ;
    USE SIGNAL ;
    PORT
      LAYER M4 ;
        RECT  215.832 159.12 216.024 159.144 ;
    END
  END r0a[370]
  PIN r0a[371]
    DIRECTION OUTPUT ;
    USE SIGNAL ;
    PORT
      LAYER M4 ;
        RECT  215.832 159.216 216.024 159.24 ;
    END
  END r0a[371]
  PIN r0a[372]
    DIRECTION OUTPUT ;
    USE SIGNAL ;
    PORT
      LAYER M4 ;
        RECT  215.832 159.312 216.024 159.336 ;
    END
  END r0a[372]
  PIN r0a[373]
    DIRECTION OUTPUT ;
    USE SIGNAL ;
    PORT
      LAYER M4 ;
        RECT  215.832 159.408 216.024 159.432 ;
    END
  END r0a[373]
  PIN r0a[374]
    DIRECTION OUTPUT ;
    USE SIGNAL ;
    PORT
      LAYER M4 ;
        RECT  215.832 159.504 216.024 159.528 ;
    END
  END r0a[374]
  PIN r0a[375]
    DIRECTION OUTPUT ;
    USE SIGNAL ;
    PORT
      LAYER M4 ;
        RECT  215.832 159.6 216.024 159.624 ;
    END
  END r0a[375]
  PIN r0a[376]
    DIRECTION OUTPUT ;
    USE SIGNAL ;
    PORT
      LAYER M4 ;
        RECT  215.832 159.696 216.024 159.72 ;
    END
  END r0a[376]
  PIN r0a[377]
    DIRECTION OUTPUT ;
    USE SIGNAL ;
    PORT
      LAYER M4 ;
        RECT  215.832 159.792 216.024 159.816 ;
    END
  END r0a[377]
  PIN r0a[378]
    DIRECTION OUTPUT ;
    USE SIGNAL ;
    PORT
      LAYER M4 ;
        RECT  215.832 159.888 216.024 159.912 ;
    END
  END r0a[378]
  PIN r0a[379]
    DIRECTION OUTPUT ;
    USE SIGNAL ;
    PORT
      LAYER M4 ;
        RECT  215.832 159.984 216.024 160.008 ;
    END
  END r0a[379]
  PIN r0a[37]
    DIRECTION OUTPUT ;
    USE SIGNAL ;
    PORT
      LAYER M4 ;
        RECT  215.832 127.152 216.024 127.176 ;
    END
  END r0a[37]
  PIN r0a[380]
    DIRECTION OUTPUT ;
    USE SIGNAL ;
    PORT
      LAYER M4 ;
        RECT  215.832 160.08 216.024 160.104 ;
    END
  END r0a[380]
  PIN r0a[381]
    DIRECTION OUTPUT ;
    USE SIGNAL ;
    PORT
      LAYER M4 ;
        RECT  215.832 160.176 216.024 160.2 ;
    END
  END r0a[381]
  PIN r0a[382]
    DIRECTION OUTPUT ;
    USE SIGNAL ;
    PORT
      LAYER M4 ;
        RECT  215.832 160.272 216.024 160.296 ;
    END
  END r0a[382]
  PIN r0a[383]
    DIRECTION OUTPUT ;
    USE SIGNAL ;
    PORT
      LAYER M4 ;
        RECT  215.832 160.368 216.024 160.392 ;
    END
  END r0a[383]
  PIN r0a[384]
    DIRECTION OUTPUT ;
    USE SIGNAL ;
    PORT
      LAYER M4 ;
        RECT  215.832 160.464 216.024 160.488 ;
    END
  END r0a[384]
  PIN r0a[385]
    DIRECTION OUTPUT ;
    USE SIGNAL ;
    PORT
      LAYER M4 ;
        RECT  215.832 160.56 216.024 160.584 ;
    END
  END r0a[385]
  PIN r0a[386]
    DIRECTION OUTPUT ;
    USE SIGNAL ;
    PORT
      LAYER M4 ;
        RECT  215.832 160.656 216.024 160.68 ;
    END
  END r0a[386]
  PIN r0a[387]
    DIRECTION OUTPUT ;
    USE SIGNAL ;
    PORT
      LAYER M4 ;
        RECT  215.832 160.752 216.024 160.776 ;
    END
  END r0a[387]
  PIN r0a[388]
    DIRECTION OUTPUT ;
    USE SIGNAL ;
    PORT
      LAYER M4 ;
        RECT  215.832 160.848 216.024 160.872 ;
    END
  END r0a[388]
  PIN r0a[389]
    DIRECTION OUTPUT ;
    USE SIGNAL ;
    PORT
      LAYER M4 ;
        RECT  215.832 160.944 216.024 160.968 ;
    END
  END r0a[389]
  PIN r0a[38]
    DIRECTION OUTPUT ;
    USE SIGNAL ;
    PORT
      LAYER M4 ;
        RECT  215.832 127.248 216.024 127.272 ;
    END
  END r0a[38]
  PIN r0a[390]
    DIRECTION OUTPUT ;
    USE SIGNAL ;
    PORT
      LAYER M4 ;
        RECT  215.832 161.04 216.024 161.064 ;
    END
  END r0a[390]
  PIN r0a[391]
    DIRECTION OUTPUT ;
    USE SIGNAL ;
    PORT
      LAYER M4 ;
        RECT  215.832 161.136 216.024 161.16 ;
    END
  END r0a[391]
  PIN r0a[392]
    DIRECTION OUTPUT ;
    USE SIGNAL ;
    PORT
      LAYER M4 ;
        RECT  215.832 161.232 216.024 161.256 ;
    END
  END r0a[392]
  PIN r0a[393]
    DIRECTION OUTPUT ;
    USE SIGNAL ;
    PORT
      LAYER M4 ;
        RECT  215.832 161.328 216.024 161.352 ;
    END
  END r0a[393]
  PIN r0a[394]
    DIRECTION OUTPUT ;
    USE SIGNAL ;
    PORT
      LAYER M4 ;
        RECT  215.832 161.424 216.024 161.448 ;
    END
  END r0a[394]
  PIN r0a[395]
    DIRECTION OUTPUT ;
    USE SIGNAL ;
    PORT
      LAYER M4 ;
        RECT  215.832 161.52 216.024 161.544 ;
    END
  END r0a[395]
  PIN r0a[396]
    DIRECTION OUTPUT ;
    USE SIGNAL ;
    PORT
      LAYER M4 ;
        RECT  215.832 161.616 216.024 161.64 ;
    END
  END r0a[396]
  PIN r0a[397]
    DIRECTION OUTPUT ;
    USE SIGNAL ;
    PORT
      LAYER M4 ;
        RECT  215.832 161.712 216.024 161.736 ;
    END
  END r0a[397]
  PIN r0a[398]
    DIRECTION OUTPUT ;
    USE SIGNAL ;
    PORT
      LAYER M4 ;
        RECT  215.832 161.808 216.024 161.832 ;
    END
  END r0a[398]
  PIN r0a[399]
    DIRECTION OUTPUT ;
    USE SIGNAL ;
    PORT
      LAYER M4 ;
        RECT  215.832 161.904 216.024 161.928 ;
    END
  END r0a[399]
  PIN r0a[39]
    DIRECTION OUTPUT ;
    USE SIGNAL ;
    PORT
      LAYER M4 ;
        RECT  215.832 127.344 216.024 127.368 ;
    END
  END r0a[39]
  PIN r0a[3]
    DIRECTION OUTPUT ;
    USE SIGNAL ;
    PORT
      LAYER M4 ;
        RECT  215.832 123.888 216.024 123.912 ;
    END
  END r0a[3]
  PIN r0a[400]
    DIRECTION OUTPUT ;
    USE SIGNAL ;
    PORT
      LAYER M4 ;
        RECT  215.832 162 216.024 162.024 ;
    END
  END r0a[400]
  PIN r0a[401]
    DIRECTION OUTPUT ;
    USE SIGNAL ;
    PORT
      LAYER M4 ;
        RECT  215.832 162.096 216.024 162.12 ;
    END
  END r0a[401]
  PIN r0a[402]
    DIRECTION OUTPUT ;
    USE SIGNAL ;
    PORT
      LAYER M4 ;
        RECT  215.832 162.192 216.024 162.216 ;
    END
  END r0a[402]
  PIN r0a[403]
    DIRECTION OUTPUT ;
    USE SIGNAL ;
    PORT
      LAYER M4 ;
        RECT  215.832 162.288 216.024 162.312 ;
    END
  END r0a[403]
  PIN r0a[404]
    DIRECTION OUTPUT ;
    USE SIGNAL ;
    PORT
      LAYER M4 ;
        RECT  215.832 162.384 216.024 162.408 ;
    END
  END r0a[404]
  PIN r0a[405]
    DIRECTION OUTPUT ;
    USE SIGNAL ;
    PORT
      LAYER M4 ;
        RECT  215.832 162.48 216.024 162.504 ;
    END
  END r0a[405]
  PIN r0a[406]
    DIRECTION OUTPUT ;
    USE SIGNAL ;
    PORT
      LAYER M4 ;
        RECT  215.832 162.576 216.024 162.6 ;
    END
  END r0a[406]
  PIN r0a[407]
    DIRECTION OUTPUT ;
    USE SIGNAL ;
    PORT
      LAYER M4 ;
        RECT  215.832 162.672 216.024 162.696 ;
    END
  END r0a[407]
  PIN r0a[408]
    DIRECTION OUTPUT ;
    USE SIGNAL ;
    PORT
      LAYER M4 ;
        RECT  215.832 162.768 216.024 162.792 ;
    END
  END r0a[408]
  PIN r0a[409]
    DIRECTION OUTPUT ;
    USE SIGNAL ;
    PORT
      LAYER M4 ;
        RECT  215.832 162.864 216.024 162.888 ;
    END
  END r0a[409]
  PIN r0a[40]
    DIRECTION OUTPUT ;
    USE SIGNAL ;
    PORT
      LAYER M4 ;
        RECT  215.832 127.44 216.024 127.464 ;
    END
  END r0a[40]
  PIN r0a[410]
    DIRECTION OUTPUT ;
    USE SIGNAL ;
    PORT
      LAYER M4 ;
        RECT  215.832 162.96 216.024 162.984 ;
    END
  END r0a[410]
  PIN r0a[411]
    DIRECTION OUTPUT ;
    USE SIGNAL ;
    PORT
      LAYER M4 ;
        RECT  215.832 163.056 216.024 163.08 ;
    END
  END r0a[411]
  PIN r0a[412]
    DIRECTION OUTPUT ;
    USE SIGNAL ;
    PORT
      LAYER M4 ;
        RECT  215.832 163.152 216.024 163.176 ;
    END
  END r0a[412]
  PIN r0a[413]
    DIRECTION OUTPUT ;
    USE SIGNAL ;
    PORT
      LAYER M4 ;
        RECT  215.832 163.248 216.024 163.272 ;
    END
  END r0a[413]
  PIN r0a[414]
    DIRECTION OUTPUT ;
    USE SIGNAL ;
    PORT
      LAYER M4 ;
        RECT  215.832 163.344 216.024 163.368 ;
    END
  END r0a[414]
  PIN r0a[415]
    DIRECTION OUTPUT ;
    USE SIGNAL ;
    PORT
      LAYER M4 ;
        RECT  215.832 163.44 216.024 163.464 ;
    END
  END r0a[415]
  PIN r0a[416]
    DIRECTION OUTPUT ;
    USE SIGNAL ;
    PORT
      LAYER M4 ;
        RECT  215.832 163.536 216.024 163.56 ;
    END
  END r0a[416]
  PIN r0a[417]
    DIRECTION OUTPUT ;
    USE SIGNAL ;
    PORT
      LAYER M4 ;
        RECT  215.832 163.632 216.024 163.656 ;
    END
  END r0a[417]
  PIN r0a[418]
    DIRECTION OUTPUT ;
    USE SIGNAL ;
    PORT
      LAYER M4 ;
        RECT  215.832 163.728 216.024 163.752 ;
    END
  END r0a[418]
  PIN r0a[419]
    DIRECTION OUTPUT ;
    USE SIGNAL ;
    PORT
      LAYER M4 ;
        RECT  215.832 163.824 216.024 163.848 ;
    END
  END r0a[419]
  PIN r0a[41]
    DIRECTION OUTPUT ;
    USE SIGNAL ;
    PORT
      LAYER M4 ;
        RECT  215.832 127.536 216.024 127.56 ;
    END
  END r0a[41]
  PIN r0a[420]
    DIRECTION OUTPUT ;
    USE SIGNAL ;
    PORT
      LAYER M4 ;
        RECT  215.832 163.92 216.024 163.944 ;
    END
  END r0a[420]
  PIN r0a[421]
    DIRECTION OUTPUT ;
    USE SIGNAL ;
    PORT
      LAYER M4 ;
        RECT  215.832 164.016 216.024 164.04 ;
    END
  END r0a[421]
  PIN r0a[422]
    DIRECTION OUTPUT ;
    USE SIGNAL ;
    PORT
      LAYER M4 ;
        RECT  215.832 164.112 216.024 164.136 ;
    END
  END r0a[422]
  PIN r0a[423]
    DIRECTION OUTPUT ;
    USE SIGNAL ;
    PORT
      LAYER M4 ;
        RECT  215.832 164.208 216.024 164.232 ;
    END
  END r0a[423]
  PIN r0a[424]
    DIRECTION OUTPUT ;
    USE SIGNAL ;
    PORT
      LAYER M4 ;
        RECT  215.832 164.304 216.024 164.328 ;
    END
  END r0a[424]
  PIN r0a[425]
    DIRECTION OUTPUT ;
    USE SIGNAL ;
    PORT
      LAYER M4 ;
        RECT  215.832 164.4 216.024 164.424 ;
    END
  END r0a[425]
  PIN r0a[426]
    DIRECTION OUTPUT ;
    USE SIGNAL ;
    PORT
      LAYER M4 ;
        RECT  215.832 164.496 216.024 164.52 ;
    END
  END r0a[426]
  PIN r0a[427]
    DIRECTION OUTPUT ;
    USE SIGNAL ;
    PORT
      LAYER M4 ;
        RECT  215.832 164.592 216.024 164.616 ;
    END
  END r0a[427]
  PIN r0a[428]
    DIRECTION OUTPUT ;
    USE SIGNAL ;
    PORT
      LAYER M4 ;
        RECT  215.832 164.688 216.024 164.712 ;
    END
  END r0a[428]
  PIN r0a[429]
    DIRECTION OUTPUT ;
    USE SIGNAL ;
    PORT
      LAYER M4 ;
        RECT  215.832 164.784 216.024 164.808 ;
    END
  END r0a[429]
  PIN r0a[42]
    DIRECTION OUTPUT ;
    USE SIGNAL ;
    PORT
      LAYER M4 ;
        RECT  215.832 127.632 216.024 127.656 ;
    END
  END r0a[42]
  PIN r0a[430]
    DIRECTION OUTPUT ;
    USE SIGNAL ;
    PORT
      LAYER M4 ;
        RECT  215.832 164.88 216.024 164.904 ;
    END
  END r0a[430]
  PIN r0a[431]
    DIRECTION OUTPUT ;
    USE SIGNAL ;
    PORT
      LAYER M4 ;
        RECT  215.832 164.976 216.024 165 ;
    END
  END r0a[431]
  PIN r0a[432]
    DIRECTION OUTPUT ;
    USE SIGNAL ;
    PORT
      LAYER M4 ;
        RECT  215.832 165.072 216.024 165.096 ;
    END
  END r0a[432]
  PIN r0a[433]
    DIRECTION OUTPUT ;
    USE SIGNAL ;
    PORT
      LAYER M4 ;
        RECT  215.832 165.168 216.024 165.192 ;
    END
  END r0a[433]
  PIN r0a[434]
    DIRECTION OUTPUT ;
    USE SIGNAL ;
    PORT
      LAYER M4 ;
        RECT  215.832 165.264 216.024 165.288 ;
    END
  END r0a[434]
  PIN r0a[435]
    DIRECTION OUTPUT ;
    USE SIGNAL ;
    PORT
      LAYER M4 ;
        RECT  215.832 165.36 216.024 165.384 ;
    END
  END r0a[435]
  PIN r0a[436]
    DIRECTION OUTPUT ;
    USE SIGNAL ;
    PORT
      LAYER M4 ;
        RECT  215.832 165.456 216.024 165.48 ;
    END
  END r0a[436]
  PIN r0a[437]
    DIRECTION OUTPUT ;
    USE SIGNAL ;
    PORT
      LAYER M4 ;
        RECT  215.832 165.552 216.024 165.576 ;
    END
  END r0a[437]
  PIN r0a[438]
    DIRECTION OUTPUT ;
    USE SIGNAL ;
    PORT
      LAYER M4 ;
        RECT  215.832 165.648 216.024 165.672 ;
    END
  END r0a[438]
  PIN r0a[439]
    DIRECTION OUTPUT ;
    USE SIGNAL ;
    PORT
      LAYER M4 ;
        RECT  215.832 165.744 216.024 165.768 ;
    END
  END r0a[439]
  PIN r0a[43]
    DIRECTION OUTPUT ;
    USE SIGNAL ;
    PORT
      LAYER M4 ;
        RECT  215.832 127.728 216.024 127.752 ;
    END
  END r0a[43]
  PIN r0a[440]
    DIRECTION OUTPUT ;
    USE SIGNAL ;
    PORT
      LAYER M4 ;
        RECT  215.832 165.84 216.024 165.864 ;
    END
  END r0a[440]
  PIN r0a[441]
    DIRECTION OUTPUT ;
    USE SIGNAL ;
    PORT
      LAYER M4 ;
        RECT  215.832 165.936 216.024 165.96 ;
    END
  END r0a[441]
  PIN r0a[442]
    DIRECTION OUTPUT ;
    USE SIGNAL ;
    PORT
      LAYER M4 ;
        RECT  215.832 166.032 216.024 166.056 ;
    END
  END r0a[442]
  PIN r0a[443]
    DIRECTION OUTPUT ;
    USE SIGNAL ;
    PORT
      LAYER M4 ;
        RECT  215.832 166.128 216.024 166.152 ;
    END
  END r0a[443]
  PIN r0a[444]
    DIRECTION OUTPUT ;
    USE SIGNAL ;
    PORT
      LAYER M4 ;
        RECT  215.832 166.224 216.024 166.248 ;
    END
  END r0a[444]
  PIN r0a[445]
    DIRECTION OUTPUT ;
    USE SIGNAL ;
    PORT
      LAYER M4 ;
        RECT  215.832 166.32 216.024 166.344 ;
    END
  END r0a[445]
  PIN r0a[446]
    DIRECTION OUTPUT ;
    USE SIGNAL ;
    PORT
      LAYER M4 ;
        RECT  215.832 166.416 216.024 166.44 ;
    END
  END r0a[446]
  PIN r0a[447]
    DIRECTION OUTPUT ;
    USE SIGNAL ;
    PORT
      LAYER M4 ;
        RECT  215.832 166.512 216.024 166.536 ;
    END
  END r0a[447]
  PIN r0a[448]
    DIRECTION OUTPUT ;
    USE SIGNAL ;
    PORT
      LAYER M4 ;
        RECT  215.832 166.608 216.024 166.632 ;
    END
  END r0a[448]
  PIN r0a[449]
    DIRECTION OUTPUT ;
    USE SIGNAL ;
    PORT
      LAYER M4 ;
        RECT  215.832 166.704 216.024 166.728 ;
    END
  END r0a[449]
  PIN r0a[44]
    DIRECTION OUTPUT ;
    USE SIGNAL ;
    PORT
      LAYER M4 ;
        RECT  215.832 127.824 216.024 127.848 ;
    END
  END r0a[44]
  PIN r0a[450]
    DIRECTION OUTPUT ;
    USE SIGNAL ;
    PORT
      LAYER M4 ;
        RECT  215.832 166.8 216.024 166.824 ;
    END
  END r0a[450]
  PIN r0a[451]
    DIRECTION OUTPUT ;
    USE SIGNAL ;
    PORT
      LAYER M4 ;
        RECT  215.832 166.896 216.024 166.92 ;
    END
  END r0a[451]
  PIN r0a[452]
    DIRECTION OUTPUT ;
    USE SIGNAL ;
    PORT
      LAYER M4 ;
        RECT  215.832 166.992 216.024 167.016 ;
    END
  END r0a[452]
  PIN r0a[453]
    DIRECTION OUTPUT ;
    USE SIGNAL ;
    PORT
      LAYER M4 ;
        RECT  215.832 167.088 216.024 167.112 ;
    END
  END r0a[453]
  PIN r0a[454]
    DIRECTION OUTPUT ;
    USE SIGNAL ;
    PORT
      LAYER M4 ;
        RECT  215.832 167.184 216.024 167.208 ;
    END
  END r0a[454]
  PIN r0a[455]
    DIRECTION OUTPUT ;
    USE SIGNAL ;
    PORT
      LAYER M4 ;
        RECT  215.832 167.28 216.024 167.304 ;
    END
  END r0a[455]
  PIN r0a[456]
    DIRECTION OUTPUT ;
    USE SIGNAL ;
    PORT
      LAYER M4 ;
        RECT  215.832 167.376 216.024 167.4 ;
    END
  END r0a[456]
  PIN r0a[457]
    DIRECTION OUTPUT ;
    USE SIGNAL ;
    PORT
      LAYER M4 ;
        RECT  215.832 167.472 216.024 167.496 ;
    END
  END r0a[457]
  PIN r0a[458]
    DIRECTION OUTPUT ;
    USE SIGNAL ;
    PORT
      LAYER M4 ;
        RECT  215.832 167.568 216.024 167.592 ;
    END
  END r0a[458]
  PIN r0a[459]
    DIRECTION OUTPUT ;
    USE SIGNAL ;
    PORT
      LAYER M4 ;
        RECT  215.832 167.664 216.024 167.688 ;
    END
  END r0a[459]
  PIN r0a[45]
    DIRECTION OUTPUT ;
    USE SIGNAL ;
    PORT
      LAYER M4 ;
        RECT  215.832 127.92 216.024 127.944 ;
    END
  END r0a[45]
  PIN r0a[460]
    DIRECTION OUTPUT ;
    USE SIGNAL ;
    PORT
      LAYER M4 ;
        RECT  215.832 167.76 216.024 167.784 ;
    END
  END r0a[460]
  PIN r0a[461]
    DIRECTION OUTPUT ;
    USE SIGNAL ;
    PORT
      LAYER M4 ;
        RECT  215.832 167.856 216.024 167.88 ;
    END
  END r0a[461]
  PIN r0a[462]
    DIRECTION OUTPUT ;
    USE SIGNAL ;
    PORT
      LAYER M4 ;
        RECT  215.832 167.952 216.024 167.976 ;
    END
  END r0a[462]
  PIN r0a[463]
    DIRECTION OUTPUT ;
    USE SIGNAL ;
    PORT
      LAYER M4 ;
        RECT  215.832 168.048 216.024 168.072 ;
    END
  END r0a[463]
  PIN r0a[464]
    DIRECTION OUTPUT ;
    USE SIGNAL ;
    PORT
      LAYER M4 ;
        RECT  215.832 168.144 216.024 168.168 ;
    END
  END r0a[464]
  PIN r0a[465]
    DIRECTION OUTPUT ;
    USE SIGNAL ;
    PORT
      LAYER M4 ;
        RECT  215.832 168.24 216.024 168.264 ;
    END
  END r0a[465]
  PIN r0a[466]
    DIRECTION OUTPUT ;
    USE SIGNAL ;
    PORT
      LAYER M4 ;
        RECT  215.832 168.336 216.024 168.36 ;
    END
  END r0a[466]
  PIN r0a[467]
    DIRECTION OUTPUT ;
    USE SIGNAL ;
    PORT
      LAYER M4 ;
        RECT  215.832 168.432 216.024 168.456 ;
    END
  END r0a[467]
  PIN r0a[468]
    DIRECTION OUTPUT ;
    USE SIGNAL ;
    PORT
      LAYER M4 ;
        RECT  215.832 168.528 216.024 168.552 ;
    END
  END r0a[468]
  PIN r0a[469]
    DIRECTION OUTPUT ;
    USE SIGNAL ;
    PORT
      LAYER M4 ;
        RECT  215.832 168.624 216.024 168.648 ;
    END
  END r0a[469]
  PIN r0a[46]
    DIRECTION OUTPUT ;
    USE SIGNAL ;
    PORT
      LAYER M4 ;
        RECT  215.832 128.016 216.024 128.04 ;
    END
  END r0a[46]
  PIN r0a[470]
    DIRECTION OUTPUT ;
    USE SIGNAL ;
    PORT
      LAYER M4 ;
        RECT  215.832 168.72 216.024 168.744 ;
    END
  END r0a[470]
  PIN r0a[471]
    DIRECTION OUTPUT ;
    USE SIGNAL ;
    PORT
      LAYER M4 ;
        RECT  215.832 168.816 216.024 168.84 ;
    END
  END r0a[471]
  PIN r0a[472]
    DIRECTION OUTPUT ;
    USE SIGNAL ;
    PORT
      LAYER M4 ;
        RECT  215.832 168.912 216.024 168.936 ;
    END
  END r0a[472]
  PIN r0a[473]
    DIRECTION OUTPUT ;
    USE SIGNAL ;
    PORT
      LAYER M4 ;
        RECT  215.832 169.008 216.024 169.032 ;
    END
  END r0a[473]
  PIN r0a[474]
    DIRECTION OUTPUT ;
    USE SIGNAL ;
    PORT
      LAYER M4 ;
        RECT  215.832 169.104 216.024 169.128 ;
    END
  END r0a[474]
  PIN r0a[475]
    DIRECTION OUTPUT ;
    USE SIGNAL ;
    PORT
      LAYER M4 ;
        RECT  215.832 169.2 216.024 169.224 ;
    END
  END r0a[475]
  PIN r0a[476]
    DIRECTION OUTPUT ;
    USE SIGNAL ;
    PORT
      LAYER M4 ;
        RECT  215.832 169.296 216.024 169.32 ;
    END
  END r0a[476]
  PIN r0a[477]
    DIRECTION OUTPUT ;
    USE SIGNAL ;
    PORT
      LAYER M4 ;
        RECT  215.832 169.392 216.024 169.416 ;
    END
  END r0a[477]
  PIN r0a[478]
    DIRECTION OUTPUT ;
    USE SIGNAL ;
    PORT
      LAYER M4 ;
        RECT  215.832 169.488 216.024 169.512 ;
    END
  END r0a[478]
  PIN r0a[479]
    DIRECTION OUTPUT ;
    USE SIGNAL ;
    PORT
      LAYER M4 ;
        RECT  215.832 169.584 216.024 169.608 ;
    END
  END r0a[479]
  PIN r0a[47]
    DIRECTION OUTPUT ;
    USE SIGNAL ;
    PORT
      LAYER M4 ;
        RECT  215.832 128.112 216.024 128.136 ;
    END
  END r0a[47]
  PIN r0a[480]
    DIRECTION OUTPUT ;
    USE SIGNAL ;
    PORT
      LAYER M4 ;
        RECT  215.832 169.68 216.024 169.704 ;
    END
  END r0a[480]
  PIN r0a[481]
    DIRECTION OUTPUT ;
    USE SIGNAL ;
    PORT
      LAYER M4 ;
        RECT  215.832 169.776 216.024 169.8 ;
    END
  END r0a[481]
  PIN r0a[482]
    DIRECTION OUTPUT ;
    USE SIGNAL ;
    PORT
      LAYER M4 ;
        RECT  215.832 169.872 216.024 169.896 ;
    END
  END r0a[482]
  PIN r0a[483]
    DIRECTION OUTPUT ;
    USE SIGNAL ;
    PORT
      LAYER M4 ;
        RECT  215.832 169.968 216.024 169.992 ;
    END
  END r0a[483]
  PIN r0a[484]
    DIRECTION OUTPUT ;
    USE SIGNAL ;
    PORT
      LAYER M4 ;
        RECT  215.832 170.064 216.024 170.088 ;
    END
  END r0a[484]
  PIN r0a[485]
    DIRECTION OUTPUT ;
    USE SIGNAL ;
    PORT
      LAYER M4 ;
        RECT  215.832 170.16 216.024 170.184 ;
    END
  END r0a[485]
  PIN r0a[486]
    DIRECTION OUTPUT ;
    USE SIGNAL ;
    PORT
      LAYER M4 ;
        RECT  215.832 170.256 216.024 170.28 ;
    END
  END r0a[486]
  PIN r0a[487]
    DIRECTION OUTPUT ;
    USE SIGNAL ;
    PORT
      LAYER M4 ;
        RECT  215.832 170.352 216.024 170.376 ;
    END
  END r0a[487]
  PIN r0a[488]
    DIRECTION OUTPUT ;
    USE SIGNAL ;
    PORT
      LAYER M4 ;
        RECT  215.832 170.448 216.024 170.472 ;
    END
  END r0a[488]
  PIN r0a[489]
    DIRECTION OUTPUT ;
    USE SIGNAL ;
    PORT
      LAYER M4 ;
        RECT  215.832 170.544 216.024 170.568 ;
    END
  END r0a[489]
  PIN r0a[48]
    DIRECTION OUTPUT ;
    USE SIGNAL ;
    PORT
      LAYER M4 ;
        RECT  215.832 128.208 216.024 128.232 ;
    END
  END r0a[48]
  PIN r0a[490]
    DIRECTION OUTPUT ;
    USE SIGNAL ;
    PORT
      LAYER M4 ;
        RECT  215.832 170.64 216.024 170.664 ;
    END
  END r0a[490]
  PIN r0a[491]
    DIRECTION OUTPUT ;
    USE SIGNAL ;
    PORT
      LAYER M4 ;
        RECT  215.832 170.736 216.024 170.76 ;
    END
  END r0a[491]
  PIN r0a[492]
    DIRECTION OUTPUT ;
    USE SIGNAL ;
    PORT
      LAYER M4 ;
        RECT  215.832 170.832 216.024 170.856 ;
    END
  END r0a[492]
  PIN r0a[493]
    DIRECTION OUTPUT ;
    USE SIGNAL ;
    PORT
      LAYER M4 ;
        RECT  215.832 170.928 216.024 170.952 ;
    END
  END r0a[493]
  PIN r0a[494]
    DIRECTION OUTPUT ;
    USE SIGNAL ;
    PORT
      LAYER M4 ;
        RECT  215.832 171.024 216.024 171.048 ;
    END
  END r0a[494]
  PIN r0a[495]
    DIRECTION OUTPUT ;
    USE SIGNAL ;
    PORT
      LAYER M4 ;
        RECT  215.832 171.12 216.024 171.144 ;
    END
  END r0a[495]
  PIN r0a[496]
    DIRECTION OUTPUT ;
    USE SIGNAL ;
    PORT
      LAYER M4 ;
        RECT  215.832 171.216 216.024 171.24 ;
    END
  END r0a[496]
  PIN r0a[497]
    DIRECTION OUTPUT ;
    USE SIGNAL ;
    PORT
      LAYER M4 ;
        RECT  215.832 171.312 216.024 171.336 ;
    END
  END r0a[497]
  PIN r0a[498]
    DIRECTION OUTPUT ;
    USE SIGNAL ;
    PORT
      LAYER M4 ;
        RECT  215.832 171.408 216.024 171.432 ;
    END
  END r0a[498]
  PIN r0a[499]
    DIRECTION OUTPUT ;
    USE SIGNAL ;
    PORT
      LAYER M4 ;
        RECT  215.832 171.504 216.024 171.528 ;
    END
  END r0a[499]
  PIN r0a[49]
    DIRECTION OUTPUT ;
    USE SIGNAL ;
    PORT
      LAYER M4 ;
        RECT  215.832 128.304 216.024 128.328 ;
    END
  END r0a[49]
  PIN r0a[4]
    DIRECTION OUTPUT ;
    USE SIGNAL ;
    PORT
      LAYER M4 ;
        RECT  215.832 123.984 216.024 124.008 ;
    END
  END r0a[4]
  PIN r0a[500]
    DIRECTION OUTPUT ;
    USE SIGNAL ;
    PORT
      LAYER M4 ;
        RECT  215.832 171.6 216.024 171.624 ;
    END
  END r0a[500]
  PIN r0a[501]
    DIRECTION OUTPUT ;
    USE SIGNAL ;
    PORT
      LAYER M4 ;
        RECT  215.832 171.696 216.024 171.72 ;
    END
  END r0a[501]
  PIN r0a[502]
    DIRECTION OUTPUT ;
    USE SIGNAL ;
    PORT
      LAYER M4 ;
        RECT  215.832 171.792 216.024 171.816 ;
    END
  END r0a[502]
  PIN r0a[503]
    DIRECTION OUTPUT ;
    USE SIGNAL ;
    PORT
      LAYER M4 ;
        RECT  215.832 171.888 216.024 171.912 ;
    END
  END r0a[503]
  PIN r0a[504]
    DIRECTION OUTPUT ;
    USE SIGNAL ;
    PORT
      LAYER M4 ;
        RECT  215.832 171.984 216.024 172.008 ;
    END
  END r0a[504]
  PIN r0a[505]
    DIRECTION OUTPUT ;
    USE SIGNAL ;
    PORT
      LAYER M4 ;
        RECT  215.832 172.08 216.024 172.104 ;
    END
  END r0a[505]
  PIN r0a[506]
    DIRECTION OUTPUT ;
    USE SIGNAL ;
    PORT
      LAYER M4 ;
        RECT  215.832 172.176 216.024 172.2 ;
    END
  END r0a[506]
  PIN r0a[507]
    DIRECTION OUTPUT ;
    USE SIGNAL ;
    PORT
      LAYER M4 ;
        RECT  215.832 172.272 216.024 172.296 ;
    END
  END r0a[507]
  PIN r0a[508]
    DIRECTION OUTPUT ;
    USE SIGNAL ;
    PORT
      LAYER M4 ;
        RECT  215.832 172.368 216.024 172.392 ;
    END
  END r0a[508]
  PIN r0a[509]
    DIRECTION OUTPUT ;
    USE SIGNAL ;
    PORT
      LAYER M4 ;
        RECT  215.832 172.464 216.024 172.488 ;
    END
  END r0a[509]
  PIN r0a[50]
    DIRECTION OUTPUT ;
    USE SIGNAL ;
    PORT
      LAYER M4 ;
        RECT  215.832 128.4 216.024 128.424 ;
    END
  END r0a[50]
  PIN r0a[510]
    DIRECTION OUTPUT ;
    USE SIGNAL ;
    PORT
      LAYER M4 ;
        RECT  215.832 172.56 216.024 172.584 ;
    END
  END r0a[510]
  PIN r0a[511]
    DIRECTION OUTPUT ;
    USE SIGNAL ;
    PORT
      LAYER M4 ;
        RECT  215.832 172.656 216.024 172.68 ;
    END
  END r0a[511]
  PIN r0a[512]
    DIRECTION OUTPUT ;
    USE SIGNAL ;
    PORT
      LAYER M4 ;
        RECT  215.832 172.752 216.024 172.776 ;
    END
  END r0a[512]
  PIN r0a[513]
    DIRECTION OUTPUT ;
    USE SIGNAL ;
    PORT
      LAYER M4 ;
        RECT  215.832 172.848 216.024 172.872 ;
    END
  END r0a[513]
  PIN r0a[514]
    DIRECTION OUTPUT ;
    USE SIGNAL ;
    PORT
      LAYER M4 ;
        RECT  215.832 172.944 216.024 172.968 ;
    END
  END r0a[514]
  PIN r0a[515]
    DIRECTION OUTPUT ;
    USE SIGNAL ;
    PORT
      LAYER M4 ;
        RECT  215.832 173.04 216.024 173.064 ;
    END
  END r0a[515]
  PIN r0a[516]
    DIRECTION OUTPUT ;
    USE SIGNAL ;
    PORT
      LAYER M4 ;
        RECT  215.832 173.136 216.024 173.16 ;
    END
  END r0a[516]
  PIN r0a[517]
    DIRECTION OUTPUT ;
    USE SIGNAL ;
    PORT
      LAYER M4 ;
        RECT  215.832 173.232 216.024 173.256 ;
    END
  END r0a[517]
  PIN r0a[518]
    DIRECTION OUTPUT ;
    USE SIGNAL ;
    PORT
      LAYER M4 ;
        RECT  215.832 173.328 216.024 173.352 ;
    END
  END r0a[518]
  PIN r0a[519]
    DIRECTION OUTPUT ;
    USE SIGNAL ;
    PORT
      LAYER M4 ;
        RECT  215.832 173.424 216.024 173.448 ;
    END
  END r0a[519]
  PIN r0a[51]
    DIRECTION OUTPUT ;
    USE SIGNAL ;
    PORT
      LAYER M4 ;
        RECT  215.832 128.496 216.024 128.52 ;
    END
  END r0a[51]
  PIN r0a[520]
    DIRECTION OUTPUT ;
    USE SIGNAL ;
    PORT
      LAYER M4 ;
        RECT  215.832 173.52 216.024 173.544 ;
    END
  END r0a[520]
  PIN r0a[521]
    DIRECTION OUTPUT ;
    USE SIGNAL ;
    PORT
      LAYER M4 ;
        RECT  215.832 173.616 216.024 173.64 ;
    END
  END r0a[521]
  PIN r0a[522]
    DIRECTION OUTPUT ;
    USE SIGNAL ;
    PORT
      LAYER M4 ;
        RECT  215.832 173.712 216.024 173.736 ;
    END
  END r0a[522]
  PIN r0a[523]
    DIRECTION OUTPUT ;
    USE SIGNAL ;
    PORT
      LAYER M4 ;
        RECT  215.832 173.808 216.024 173.832 ;
    END
  END r0a[523]
  PIN r0a[524]
    DIRECTION OUTPUT ;
    USE SIGNAL ;
    PORT
      LAYER M4 ;
        RECT  215.832 173.904 216.024 173.928 ;
    END
  END r0a[524]
  PIN r0a[525]
    DIRECTION OUTPUT ;
    USE SIGNAL ;
    PORT
      LAYER M4 ;
        RECT  215.832 174 216.024 174.024 ;
    END
  END r0a[525]
  PIN r0a[526]
    DIRECTION OUTPUT ;
    USE SIGNAL ;
    PORT
      LAYER M4 ;
        RECT  215.832 174.096 216.024 174.12 ;
    END
  END r0a[526]
  PIN r0a[527]
    DIRECTION OUTPUT ;
    USE SIGNAL ;
    PORT
      LAYER M4 ;
        RECT  215.832 174.192 216.024 174.216 ;
    END
  END r0a[527]
  PIN r0a[528]
    DIRECTION OUTPUT ;
    USE SIGNAL ;
    PORT
      LAYER M4 ;
        RECT  215.832 174.288 216.024 174.312 ;
    END
  END r0a[528]
  PIN r0a[529]
    DIRECTION OUTPUT ;
    USE SIGNAL ;
    PORT
      LAYER M4 ;
        RECT  215.832 174.384 216.024 174.408 ;
    END
  END r0a[529]
  PIN r0a[52]
    DIRECTION OUTPUT ;
    USE SIGNAL ;
    PORT
      LAYER M4 ;
        RECT  215.832 128.592 216.024 128.616 ;
    END
  END r0a[52]
  PIN r0a[530]
    DIRECTION OUTPUT ;
    USE SIGNAL ;
    PORT
      LAYER M4 ;
        RECT  215.832 174.48 216.024 174.504 ;
    END
  END r0a[530]
  PIN r0a[531]
    DIRECTION OUTPUT ;
    USE SIGNAL ;
    PORT
      LAYER M4 ;
        RECT  215.832 174.576 216.024 174.6 ;
    END
  END r0a[531]
  PIN r0a[532]
    DIRECTION OUTPUT ;
    USE SIGNAL ;
    PORT
      LAYER M4 ;
        RECT  215.832 174.672 216.024 174.696 ;
    END
  END r0a[532]
  PIN r0a[533]
    DIRECTION OUTPUT ;
    USE SIGNAL ;
    PORT
      LAYER M4 ;
        RECT  215.832 174.768 216.024 174.792 ;
    END
  END r0a[533]
  PIN r0a[534]
    DIRECTION OUTPUT ;
    USE SIGNAL ;
    PORT
      LAYER M4 ;
        RECT  215.832 174.864 216.024 174.888 ;
    END
  END r0a[534]
  PIN r0a[535]
    DIRECTION OUTPUT ;
    USE SIGNAL ;
    PORT
      LAYER M4 ;
        RECT  215.832 174.96 216.024 174.984 ;
    END
  END r0a[535]
  PIN r0a[536]
    DIRECTION OUTPUT ;
    USE SIGNAL ;
    PORT
      LAYER M4 ;
        RECT  215.832 175.056 216.024 175.08 ;
    END
  END r0a[536]
  PIN r0a[537]
    DIRECTION OUTPUT ;
    USE SIGNAL ;
    PORT
      LAYER M4 ;
        RECT  215.832 175.152 216.024 175.176 ;
    END
  END r0a[537]
  PIN r0a[538]
    DIRECTION OUTPUT ;
    USE SIGNAL ;
    PORT
      LAYER M4 ;
        RECT  215.832 175.248 216.024 175.272 ;
    END
  END r0a[538]
  PIN r0a[539]
    DIRECTION OUTPUT ;
    USE SIGNAL ;
    PORT
      LAYER M4 ;
        RECT  215.832 175.344 216.024 175.368 ;
    END
  END r0a[539]
  PIN r0a[53]
    DIRECTION OUTPUT ;
    USE SIGNAL ;
    PORT
      LAYER M4 ;
        RECT  215.832 128.688 216.024 128.712 ;
    END
  END r0a[53]
  PIN r0a[540]
    DIRECTION OUTPUT ;
    USE SIGNAL ;
    PORT
      LAYER M4 ;
        RECT  215.832 175.44 216.024 175.464 ;
    END
  END r0a[540]
  PIN r0a[541]
    DIRECTION OUTPUT ;
    USE SIGNAL ;
    PORT
      LAYER M4 ;
        RECT  215.832 175.536 216.024 175.56 ;
    END
  END r0a[541]
  PIN r0a[542]
    DIRECTION OUTPUT ;
    USE SIGNAL ;
    PORT
      LAYER M4 ;
        RECT  215.832 175.632 216.024 175.656 ;
    END
  END r0a[542]
  PIN r0a[543]
    DIRECTION OUTPUT ;
    USE SIGNAL ;
    PORT
      LAYER M4 ;
        RECT  215.832 175.728 216.024 175.752 ;
    END
  END r0a[543]
  PIN r0a[544]
    DIRECTION OUTPUT ;
    USE SIGNAL ;
    PORT
      LAYER M4 ;
        RECT  215.832 175.824 216.024 175.848 ;
    END
  END r0a[544]
  PIN r0a[545]
    DIRECTION OUTPUT ;
    USE SIGNAL ;
    PORT
      LAYER M4 ;
        RECT  215.832 175.92 216.024 175.944 ;
    END
  END r0a[545]
  PIN r0a[546]
    DIRECTION OUTPUT ;
    USE SIGNAL ;
    PORT
      LAYER M4 ;
        RECT  215.832 176.016 216.024 176.04 ;
    END
  END r0a[546]
  PIN r0a[547]
    DIRECTION OUTPUT ;
    USE SIGNAL ;
    PORT
      LAYER M4 ;
        RECT  215.832 176.112 216.024 176.136 ;
    END
  END r0a[547]
  PIN r0a[548]
    DIRECTION OUTPUT ;
    USE SIGNAL ;
    PORT
      LAYER M4 ;
        RECT  215.832 176.208 216.024 176.232 ;
    END
  END r0a[548]
  PIN r0a[549]
    DIRECTION OUTPUT ;
    USE SIGNAL ;
    PORT
      LAYER M4 ;
        RECT  215.832 176.304 216.024 176.328 ;
    END
  END r0a[549]
  PIN r0a[54]
    DIRECTION OUTPUT ;
    USE SIGNAL ;
    PORT
      LAYER M4 ;
        RECT  215.832 128.784 216.024 128.808 ;
    END
  END r0a[54]
  PIN r0a[550]
    DIRECTION OUTPUT ;
    USE SIGNAL ;
    PORT
      LAYER M4 ;
        RECT  215.832 176.4 216.024 176.424 ;
    END
  END r0a[550]
  PIN r0a[551]
    DIRECTION OUTPUT ;
    USE SIGNAL ;
    PORT
      LAYER M4 ;
        RECT  215.832 176.496 216.024 176.52 ;
    END
  END r0a[551]
  PIN r0a[552]
    DIRECTION OUTPUT ;
    USE SIGNAL ;
    PORT
      LAYER M4 ;
        RECT  215.832 176.592 216.024 176.616 ;
    END
  END r0a[552]
  PIN r0a[553]
    DIRECTION OUTPUT ;
    USE SIGNAL ;
    PORT
      LAYER M4 ;
        RECT  215.832 176.688 216.024 176.712 ;
    END
  END r0a[553]
  PIN r0a[554]
    DIRECTION OUTPUT ;
    USE SIGNAL ;
    PORT
      LAYER M4 ;
        RECT  215.832 176.784 216.024 176.808 ;
    END
  END r0a[554]
  PIN r0a[555]
    DIRECTION OUTPUT ;
    USE SIGNAL ;
    PORT
      LAYER M4 ;
        RECT  215.832 176.88 216.024 176.904 ;
    END
  END r0a[555]
  PIN r0a[556]
    DIRECTION OUTPUT ;
    USE SIGNAL ;
    PORT
      LAYER M4 ;
        RECT  215.832 176.976 216.024 177 ;
    END
  END r0a[556]
  PIN r0a[557]
    DIRECTION OUTPUT ;
    USE SIGNAL ;
    PORT
      LAYER M4 ;
        RECT  215.832 177.072 216.024 177.096 ;
    END
  END r0a[557]
  PIN r0a[558]
    DIRECTION OUTPUT ;
    USE SIGNAL ;
    PORT
      LAYER M4 ;
        RECT  215.832 177.168 216.024 177.192 ;
    END
  END r0a[558]
  PIN r0a[559]
    DIRECTION OUTPUT ;
    USE SIGNAL ;
    PORT
      LAYER M4 ;
        RECT  215.832 177.264 216.024 177.288 ;
    END
  END r0a[559]
  PIN r0a[55]
    DIRECTION OUTPUT ;
    USE SIGNAL ;
    PORT
      LAYER M4 ;
        RECT  215.832 128.88 216.024 128.904 ;
    END
  END r0a[55]
  PIN r0a[560]
    DIRECTION OUTPUT ;
    USE SIGNAL ;
    PORT
      LAYER M4 ;
        RECT  215.832 177.36 216.024 177.384 ;
    END
  END r0a[560]
  PIN r0a[561]
    DIRECTION OUTPUT ;
    USE SIGNAL ;
    PORT
      LAYER M4 ;
        RECT  215.832 177.456 216.024 177.48 ;
    END
  END r0a[561]
  PIN r0a[562]
    DIRECTION OUTPUT ;
    USE SIGNAL ;
    PORT
      LAYER M4 ;
        RECT  215.832 177.552 216.024 177.576 ;
    END
  END r0a[562]
  PIN r0a[563]
    DIRECTION OUTPUT ;
    USE SIGNAL ;
    PORT
      LAYER M4 ;
        RECT  215.832 177.648 216.024 177.672 ;
    END
  END r0a[563]
  PIN r0a[564]
    DIRECTION OUTPUT ;
    USE SIGNAL ;
    PORT
      LAYER M4 ;
        RECT  215.832 177.744 216.024 177.768 ;
    END
  END r0a[564]
  PIN r0a[565]
    DIRECTION OUTPUT ;
    USE SIGNAL ;
    PORT
      LAYER M4 ;
        RECT  215.832 177.84 216.024 177.864 ;
    END
  END r0a[565]
  PIN r0a[566]
    DIRECTION OUTPUT ;
    USE SIGNAL ;
    PORT
      LAYER M4 ;
        RECT  215.832 177.936 216.024 177.96 ;
    END
  END r0a[566]
  PIN r0a[567]
    DIRECTION OUTPUT ;
    USE SIGNAL ;
    PORT
      LAYER M4 ;
        RECT  215.832 178.032 216.024 178.056 ;
    END
  END r0a[567]
  PIN r0a[568]
    DIRECTION OUTPUT ;
    USE SIGNAL ;
    PORT
      LAYER M4 ;
        RECT  215.832 178.128 216.024 178.152 ;
    END
  END r0a[568]
  PIN r0a[569]
    DIRECTION OUTPUT ;
    USE SIGNAL ;
    PORT
      LAYER M4 ;
        RECT  215.832 178.224 216.024 178.248 ;
    END
  END r0a[569]
  PIN r0a[56]
    DIRECTION OUTPUT ;
    USE SIGNAL ;
    PORT
      LAYER M4 ;
        RECT  215.832 128.976 216.024 129 ;
    END
  END r0a[56]
  PIN r0a[570]
    DIRECTION OUTPUT ;
    USE SIGNAL ;
    PORT
      LAYER M4 ;
        RECT  215.832 178.32 216.024 178.344 ;
    END
  END r0a[570]
  PIN r0a[571]
    DIRECTION OUTPUT ;
    USE SIGNAL ;
    PORT
      LAYER M4 ;
        RECT  215.832 178.416 216.024 178.44 ;
    END
  END r0a[571]
  PIN r0a[572]
    DIRECTION OUTPUT ;
    USE SIGNAL ;
    PORT
      LAYER M4 ;
        RECT  215.832 178.512 216.024 178.536 ;
    END
  END r0a[572]
  PIN r0a[573]
    DIRECTION OUTPUT ;
    USE SIGNAL ;
    PORT
      LAYER M4 ;
        RECT  215.832 178.608 216.024 178.632 ;
    END
  END r0a[573]
  PIN r0a[574]
    DIRECTION OUTPUT ;
    USE SIGNAL ;
    PORT
      LAYER M4 ;
        RECT  215.832 178.704 216.024 178.728 ;
    END
  END r0a[574]
  PIN r0a[575]
    DIRECTION OUTPUT ;
    USE SIGNAL ;
    PORT
      LAYER M4 ;
        RECT  215.832 178.8 216.024 178.824 ;
    END
  END r0a[575]
  PIN r0a[576]
    DIRECTION OUTPUT ;
    USE SIGNAL ;
    PORT
      LAYER M4 ;
        RECT  215.832 178.896 216.024 178.92 ;
    END
  END r0a[576]
  PIN r0a[577]
    DIRECTION OUTPUT ;
    USE SIGNAL ;
    PORT
      LAYER M4 ;
        RECT  215.832 178.992 216.024 179.016 ;
    END
  END r0a[577]
  PIN r0a[578]
    DIRECTION OUTPUT ;
    USE SIGNAL ;
    PORT
      LAYER M4 ;
        RECT  215.832 179.088 216.024 179.112 ;
    END
  END r0a[578]
  PIN r0a[579]
    DIRECTION OUTPUT ;
    USE SIGNAL ;
    PORT
      LAYER M4 ;
        RECT  215.832 179.184 216.024 179.208 ;
    END
  END r0a[579]
  PIN r0a[57]
    DIRECTION OUTPUT ;
    USE SIGNAL ;
    PORT
      LAYER M4 ;
        RECT  215.832 129.072 216.024 129.096 ;
    END
  END r0a[57]
  PIN r0a[580]
    DIRECTION OUTPUT ;
    USE SIGNAL ;
    PORT
      LAYER M4 ;
        RECT  215.832 179.28 216.024 179.304 ;
    END
  END r0a[580]
  PIN r0a[581]
    DIRECTION OUTPUT ;
    USE SIGNAL ;
    PORT
      LAYER M4 ;
        RECT  215.832 179.376 216.024 179.4 ;
    END
  END r0a[581]
  PIN r0a[582]
    DIRECTION OUTPUT ;
    USE SIGNAL ;
    PORT
      LAYER M4 ;
        RECT  215.832 179.472 216.024 179.496 ;
    END
  END r0a[582]
  PIN r0a[583]
    DIRECTION OUTPUT ;
    USE SIGNAL ;
    PORT
      LAYER M4 ;
        RECT  215.832 179.568 216.024 179.592 ;
    END
  END r0a[583]
  PIN r0a[584]
    DIRECTION OUTPUT ;
    USE SIGNAL ;
    PORT
      LAYER M4 ;
        RECT  215.832 179.664 216.024 179.688 ;
    END
  END r0a[584]
  PIN r0a[585]
    DIRECTION OUTPUT ;
    USE SIGNAL ;
    PORT
      LAYER M4 ;
        RECT  215.832 179.76 216.024 179.784 ;
    END
  END r0a[585]
  PIN r0a[586]
    DIRECTION OUTPUT ;
    USE SIGNAL ;
    PORT
      LAYER M4 ;
        RECT  215.832 179.856 216.024 179.88 ;
    END
  END r0a[586]
  PIN r0a[587]
    DIRECTION OUTPUT ;
    USE SIGNAL ;
    PORT
      LAYER M4 ;
        RECT  215.832 179.952 216.024 179.976 ;
    END
  END r0a[587]
  PIN r0a[588]
    DIRECTION OUTPUT ;
    USE SIGNAL ;
    PORT
      LAYER M4 ;
        RECT  215.832 180.048 216.024 180.072 ;
    END
  END r0a[588]
  PIN r0a[589]
    DIRECTION OUTPUT ;
    USE SIGNAL ;
    PORT
      LAYER M4 ;
        RECT  215.832 180.144 216.024 180.168 ;
    END
  END r0a[589]
  PIN r0a[58]
    DIRECTION OUTPUT ;
    USE SIGNAL ;
    PORT
      LAYER M4 ;
        RECT  215.832 129.168 216.024 129.192 ;
    END
  END r0a[58]
  PIN r0a[590]
    DIRECTION OUTPUT ;
    USE SIGNAL ;
    PORT
      LAYER M4 ;
        RECT  215.832 180.24 216.024 180.264 ;
    END
  END r0a[590]
  PIN r0a[591]
    DIRECTION OUTPUT ;
    USE SIGNAL ;
    PORT
      LAYER M4 ;
        RECT  215.832 180.336 216.024 180.36 ;
    END
  END r0a[591]
  PIN r0a[592]
    DIRECTION OUTPUT ;
    USE SIGNAL ;
    PORT
      LAYER M4 ;
        RECT  215.832 180.432 216.024 180.456 ;
    END
  END r0a[592]
  PIN r0a[593]
    DIRECTION OUTPUT ;
    USE SIGNAL ;
    PORT
      LAYER M4 ;
        RECT  215.832 180.528 216.024 180.552 ;
    END
  END r0a[593]
  PIN r0a[594]
    DIRECTION OUTPUT ;
    USE SIGNAL ;
    PORT
      LAYER M4 ;
        RECT  215.832 180.624 216.024 180.648 ;
    END
  END r0a[594]
  PIN r0a[595]
    DIRECTION OUTPUT ;
    USE SIGNAL ;
    PORT
      LAYER M4 ;
        RECT  215.832 180.72 216.024 180.744 ;
    END
  END r0a[595]
  PIN r0a[596]
    DIRECTION OUTPUT ;
    USE SIGNAL ;
    PORT
      LAYER M4 ;
        RECT  215.832 180.816 216.024 180.84 ;
    END
  END r0a[596]
  PIN r0a[597]
    DIRECTION OUTPUT ;
    USE SIGNAL ;
    PORT
      LAYER M4 ;
        RECT  215.832 180.912 216.024 180.936 ;
    END
  END r0a[597]
  PIN r0a[598]
    DIRECTION OUTPUT ;
    USE SIGNAL ;
    PORT
      LAYER M4 ;
        RECT  215.832 181.008 216.024 181.032 ;
    END
  END r0a[598]
  PIN r0a[599]
    DIRECTION OUTPUT ;
    USE SIGNAL ;
    PORT
      LAYER M4 ;
        RECT  215.832 181.104 216.024 181.128 ;
    END
  END r0a[599]
  PIN r0a[59]
    DIRECTION OUTPUT ;
    USE SIGNAL ;
    PORT
      LAYER M4 ;
        RECT  215.832 129.264 216.024 129.288 ;
    END
  END r0a[59]
  PIN r0a[5]
    DIRECTION OUTPUT ;
    USE SIGNAL ;
    PORT
      LAYER M4 ;
        RECT  215.832 124.08 216.024 124.104 ;
    END
  END r0a[5]
  PIN r0a[600]
    DIRECTION OUTPUT ;
    USE SIGNAL ;
    PORT
      LAYER M4 ;
        RECT  215.832 181.2 216.024 181.224 ;
    END
  END r0a[600]
  PIN r0a[601]
    DIRECTION OUTPUT ;
    USE SIGNAL ;
    PORT
      LAYER M4 ;
        RECT  215.832 181.296 216.024 181.32 ;
    END
  END r0a[601]
  PIN r0a[602]
    DIRECTION OUTPUT ;
    USE SIGNAL ;
    PORT
      LAYER M4 ;
        RECT  215.832 181.392 216.024 181.416 ;
    END
  END r0a[602]
  PIN r0a[603]
    DIRECTION OUTPUT ;
    USE SIGNAL ;
    PORT
      LAYER M4 ;
        RECT  215.832 181.488 216.024 181.512 ;
    END
  END r0a[603]
  PIN r0a[604]
    DIRECTION OUTPUT ;
    USE SIGNAL ;
    PORT
      LAYER M4 ;
        RECT  215.832 181.584 216.024 181.608 ;
    END
  END r0a[604]
  PIN r0a[605]
    DIRECTION OUTPUT ;
    USE SIGNAL ;
    PORT
      LAYER M4 ;
        RECT  215.832 181.68 216.024 181.704 ;
    END
  END r0a[605]
  PIN r0a[606]
    DIRECTION OUTPUT ;
    USE SIGNAL ;
    PORT
      LAYER M4 ;
        RECT  215.832 181.776 216.024 181.8 ;
    END
  END r0a[606]
  PIN r0a[607]
    DIRECTION OUTPUT ;
    USE SIGNAL ;
    PORT
      LAYER M4 ;
        RECT  215.832 181.872 216.024 181.896 ;
    END
  END r0a[607]
  PIN r0a[608]
    DIRECTION OUTPUT ;
    USE SIGNAL ;
    PORT
      LAYER M4 ;
        RECT  215.832 181.968 216.024 181.992 ;
    END
  END r0a[608]
  PIN r0a[609]
    DIRECTION OUTPUT ;
    USE SIGNAL ;
    PORT
      LAYER M4 ;
        RECT  215.832 182.064 216.024 182.088 ;
    END
  END r0a[609]
  PIN r0a[60]
    DIRECTION OUTPUT ;
    USE SIGNAL ;
    PORT
      LAYER M4 ;
        RECT  215.832 129.36 216.024 129.384 ;
    END
  END r0a[60]
  PIN r0a[610]
    DIRECTION OUTPUT ;
    USE SIGNAL ;
    PORT
      LAYER M4 ;
        RECT  215.832 182.16 216.024 182.184 ;
    END
  END r0a[610]
  PIN r0a[611]
    DIRECTION OUTPUT ;
    USE SIGNAL ;
    PORT
      LAYER M4 ;
        RECT  215.832 182.256 216.024 182.28 ;
    END
  END r0a[611]
  PIN r0a[612]
    DIRECTION OUTPUT ;
    USE SIGNAL ;
    PORT
      LAYER M4 ;
        RECT  215.832 182.352 216.024 182.376 ;
    END
  END r0a[612]
  PIN r0a[613]
    DIRECTION OUTPUT ;
    USE SIGNAL ;
    PORT
      LAYER M4 ;
        RECT  215.832 182.448 216.024 182.472 ;
    END
  END r0a[613]
  PIN r0a[614]
    DIRECTION OUTPUT ;
    USE SIGNAL ;
    PORT
      LAYER M4 ;
        RECT  215.832 182.544 216.024 182.568 ;
    END
  END r0a[614]
  PIN r0a[615]
    DIRECTION OUTPUT ;
    USE SIGNAL ;
    PORT
      LAYER M4 ;
        RECT  215.832 182.64 216.024 182.664 ;
    END
  END r0a[615]
  PIN r0a[616]
    DIRECTION OUTPUT ;
    USE SIGNAL ;
    PORT
      LAYER M4 ;
        RECT  215.832 182.736 216.024 182.76 ;
    END
  END r0a[616]
  PIN r0a[617]
    DIRECTION OUTPUT ;
    USE SIGNAL ;
    PORT
      LAYER M4 ;
        RECT  215.832 182.832 216.024 182.856 ;
    END
  END r0a[617]
  PIN r0a[618]
    DIRECTION OUTPUT ;
    USE SIGNAL ;
    PORT
      LAYER M4 ;
        RECT  215.832 182.928 216.024 182.952 ;
    END
  END r0a[618]
  PIN r0a[619]
    DIRECTION OUTPUT ;
    USE SIGNAL ;
    PORT
      LAYER M4 ;
        RECT  215.832 183.024 216.024 183.048 ;
    END
  END r0a[619]
  PIN r0a[61]
    DIRECTION OUTPUT ;
    USE SIGNAL ;
    PORT
      LAYER M4 ;
        RECT  215.832 129.456 216.024 129.48 ;
    END
  END r0a[61]
  PIN r0a[620]
    DIRECTION OUTPUT ;
    USE SIGNAL ;
    PORT
      LAYER M4 ;
        RECT  215.832 183.12 216.024 183.144 ;
    END
  END r0a[620]
  PIN r0a[621]
    DIRECTION OUTPUT ;
    USE SIGNAL ;
    PORT
      LAYER M4 ;
        RECT  215.832 183.216 216.024 183.24 ;
    END
  END r0a[621]
  PIN r0a[622]
    DIRECTION OUTPUT ;
    USE SIGNAL ;
    PORT
      LAYER M4 ;
        RECT  215.832 183.312 216.024 183.336 ;
    END
  END r0a[622]
  PIN r0a[623]
    DIRECTION OUTPUT ;
    USE SIGNAL ;
    PORT
      LAYER M4 ;
        RECT  215.832 183.408 216.024 183.432 ;
    END
  END r0a[623]
  PIN r0a[624]
    DIRECTION OUTPUT ;
    USE SIGNAL ;
    PORT
      LAYER M4 ;
        RECT  215.832 183.504 216.024 183.528 ;
    END
  END r0a[624]
  PIN r0a[625]
    DIRECTION OUTPUT ;
    USE SIGNAL ;
    PORT
      LAYER M4 ;
        RECT  215.832 183.6 216.024 183.624 ;
    END
  END r0a[625]
  PIN r0a[626]
    DIRECTION OUTPUT ;
    USE SIGNAL ;
    PORT
      LAYER M4 ;
        RECT  215.832 183.696 216.024 183.72 ;
    END
  END r0a[626]
  PIN r0a[627]
    DIRECTION OUTPUT ;
    USE SIGNAL ;
    PORT
      LAYER M4 ;
        RECT  215.832 183.792 216.024 183.816 ;
    END
  END r0a[627]
  PIN r0a[628]
    DIRECTION OUTPUT ;
    USE SIGNAL ;
    PORT
      LAYER M4 ;
        RECT  215.832 183.888 216.024 183.912 ;
    END
  END r0a[628]
  PIN r0a[629]
    DIRECTION OUTPUT ;
    USE SIGNAL ;
    PORT
      LAYER M4 ;
        RECT  215.832 183.984 216.024 184.008 ;
    END
  END r0a[629]
  PIN r0a[62]
    DIRECTION OUTPUT ;
    USE SIGNAL ;
    PORT
      LAYER M4 ;
        RECT  215.832 129.552 216.024 129.576 ;
    END
  END r0a[62]
  PIN r0a[630]
    DIRECTION OUTPUT ;
    USE SIGNAL ;
    PORT
      LAYER M4 ;
        RECT  215.832 184.08 216.024 184.104 ;
    END
  END r0a[630]
  PIN r0a[631]
    DIRECTION OUTPUT ;
    USE SIGNAL ;
    PORT
      LAYER M4 ;
        RECT  215.832 184.176 216.024 184.2 ;
    END
  END r0a[631]
  PIN r0a[632]
    DIRECTION OUTPUT ;
    USE SIGNAL ;
    PORT
      LAYER M4 ;
        RECT  215.832 184.272 216.024 184.296 ;
    END
  END r0a[632]
  PIN r0a[633]
    DIRECTION OUTPUT ;
    USE SIGNAL ;
    PORT
      LAYER M4 ;
        RECT  215.832 184.368 216.024 184.392 ;
    END
  END r0a[633]
  PIN r0a[634]
    DIRECTION OUTPUT ;
    USE SIGNAL ;
    PORT
      LAYER M4 ;
        RECT  215.832 184.464 216.024 184.488 ;
    END
  END r0a[634]
  PIN r0a[635]
    DIRECTION OUTPUT ;
    USE SIGNAL ;
    PORT
      LAYER M4 ;
        RECT  215.832 184.56 216.024 184.584 ;
    END
  END r0a[635]
  PIN r0a[636]
    DIRECTION OUTPUT ;
    USE SIGNAL ;
    PORT
      LAYER M4 ;
        RECT  215.832 184.656 216.024 184.68 ;
    END
  END r0a[636]
  PIN r0a[637]
    DIRECTION OUTPUT ;
    USE SIGNAL ;
    PORT
      LAYER M4 ;
        RECT  215.832 184.752 216.024 184.776 ;
    END
  END r0a[637]
  PIN r0a[638]
    DIRECTION OUTPUT ;
    USE SIGNAL ;
    PORT
      LAYER M4 ;
        RECT  215.832 184.848 216.024 184.872 ;
    END
  END r0a[638]
  PIN r0a[639]
    DIRECTION OUTPUT ;
    USE SIGNAL ;
    PORT
      LAYER M4 ;
        RECT  215.832 184.944 216.024 184.968 ;
    END
  END r0a[639]
  PIN r0a[63]
    DIRECTION OUTPUT ;
    USE SIGNAL ;
    PORT
      LAYER M4 ;
        RECT  215.832 129.648 216.024 129.672 ;
    END
  END r0a[63]
  PIN r0a[640]
    DIRECTION OUTPUT ;
    USE SIGNAL ;
    PORT
      LAYER M4 ;
        RECT  215.832 185.04 216.024 185.064 ;
    END
  END r0a[640]
  PIN r0a[641]
    DIRECTION OUTPUT ;
    USE SIGNAL ;
    PORT
      LAYER M4 ;
        RECT  215.832 185.136 216.024 185.16 ;
    END
  END r0a[641]
  PIN r0a[642]
    DIRECTION OUTPUT ;
    USE SIGNAL ;
    PORT
      LAYER M4 ;
        RECT  215.832 185.232 216.024 185.256 ;
    END
  END r0a[642]
  PIN r0a[643]
    DIRECTION OUTPUT ;
    USE SIGNAL ;
    PORT
      LAYER M4 ;
        RECT  215.832 185.328 216.024 185.352 ;
    END
  END r0a[643]
  PIN r0a[644]
    DIRECTION OUTPUT ;
    USE SIGNAL ;
    PORT
      LAYER M4 ;
        RECT  215.832 185.424 216.024 185.448 ;
    END
  END r0a[644]
  PIN r0a[645]
    DIRECTION OUTPUT ;
    USE SIGNAL ;
    PORT
      LAYER M4 ;
        RECT  215.832 185.52 216.024 185.544 ;
    END
  END r0a[645]
  PIN r0a[646]
    DIRECTION OUTPUT ;
    USE SIGNAL ;
    PORT
      LAYER M4 ;
        RECT  215.832 185.616 216.024 185.64 ;
    END
  END r0a[646]
  PIN r0a[647]
    DIRECTION OUTPUT ;
    USE SIGNAL ;
    PORT
      LAYER M4 ;
        RECT  215.832 185.712 216.024 185.736 ;
    END
  END r0a[647]
  PIN r0a[648]
    DIRECTION OUTPUT ;
    USE SIGNAL ;
    PORT
      LAYER M4 ;
        RECT  215.832 185.808 216.024 185.832 ;
    END
  END r0a[648]
  PIN r0a[649]
    DIRECTION OUTPUT ;
    USE SIGNAL ;
    PORT
      LAYER M4 ;
        RECT  215.832 185.904 216.024 185.928 ;
    END
  END r0a[649]
  PIN r0a[64]
    DIRECTION OUTPUT ;
    USE SIGNAL ;
    PORT
      LAYER M4 ;
        RECT  215.832 129.744 216.024 129.768 ;
    END
  END r0a[64]
  PIN r0a[650]
    DIRECTION OUTPUT ;
    USE SIGNAL ;
    PORT
      LAYER M4 ;
        RECT  215.832 186 216.024 186.024 ;
    END
  END r0a[650]
  PIN r0a[651]
    DIRECTION OUTPUT ;
    USE SIGNAL ;
    PORT
      LAYER M4 ;
        RECT  215.832 186.096 216.024 186.12 ;
    END
  END r0a[651]
  PIN r0a[652]
    DIRECTION OUTPUT ;
    USE SIGNAL ;
    PORT
      LAYER M4 ;
        RECT  215.832 186.192 216.024 186.216 ;
    END
  END r0a[652]
  PIN r0a[653]
    DIRECTION OUTPUT ;
    USE SIGNAL ;
    PORT
      LAYER M4 ;
        RECT  215.832 186.288 216.024 186.312 ;
    END
  END r0a[653]
  PIN r0a[654]
    DIRECTION OUTPUT ;
    USE SIGNAL ;
    PORT
      LAYER M4 ;
        RECT  215.832 186.384 216.024 186.408 ;
    END
  END r0a[654]
  PIN r0a[655]
    DIRECTION OUTPUT ;
    USE SIGNAL ;
    PORT
      LAYER M4 ;
        RECT  215.832 186.48 216.024 186.504 ;
    END
  END r0a[655]
  PIN r0a[656]
    DIRECTION OUTPUT ;
    USE SIGNAL ;
    PORT
      LAYER M4 ;
        RECT  215.832 186.576 216.024 186.6 ;
    END
  END r0a[656]
  PIN r0a[657]
    DIRECTION OUTPUT ;
    USE SIGNAL ;
    PORT
      LAYER M4 ;
        RECT  215.832 186.672 216.024 186.696 ;
    END
  END r0a[657]
  PIN r0a[658]
    DIRECTION OUTPUT ;
    USE SIGNAL ;
    PORT
      LAYER M4 ;
        RECT  215.832 186.768 216.024 186.792 ;
    END
  END r0a[658]
  PIN r0a[659]
    DIRECTION OUTPUT ;
    USE SIGNAL ;
    PORT
      LAYER M4 ;
        RECT  215.832 186.864 216.024 186.888 ;
    END
  END r0a[659]
  PIN r0a[65]
    DIRECTION OUTPUT ;
    USE SIGNAL ;
    PORT
      LAYER M4 ;
        RECT  215.832 129.84 216.024 129.864 ;
    END
  END r0a[65]
  PIN r0a[660]
    DIRECTION OUTPUT ;
    USE SIGNAL ;
    PORT
      LAYER M4 ;
        RECT  215.832 186.96 216.024 186.984 ;
    END
  END r0a[660]
  PIN r0a[661]
    DIRECTION OUTPUT ;
    USE SIGNAL ;
    PORT
      LAYER M4 ;
        RECT  215.832 187.056 216.024 187.08 ;
    END
  END r0a[661]
  PIN r0a[662]
    DIRECTION OUTPUT ;
    USE SIGNAL ;
    PORT
      LAYER M4 ;
        RECT  215.832 187.152 216.024 187.176 ;
    END
  END r0a[662]
  PIN r0a[663]
    DIRECTION OUTPUT ;
    USE SIGNAL ;
    PORT
      LAYER M4 ;
        RECT  215.832 187.248 216.024 187.272 ;
    END
  END r0a[663]
  PIN r0a[664]
    DIRECTION OUTPUT ;
    USE SIGNAL ;
    PORT
      LAYER M4 ;
        RECT  215.832 187.344 216.024 187.368 ;
    END
  END r0a[664]
  PIN r0a[665]
    DIRECTION OUTPUT ;
    USE SIGNAL ;
    PORT
      LAYER M4 ;
        RECT  215.832 187.44 216.024 187.464 ;
    END
  END r0a[665]
  PIN r0a[666]
    DIRECTION OUTPUT ;
    USE SIGNAL ;
    PORT
      LAYER M4 ;
        RECT  215.832 187.536 216.024 187.56 ;
    END
  END r0a[666]
  PIN r0a[667]
    DIRECTION OUTPUT ;
    USE SIGNAL ;
    PORT
      LAYER M4 ;
        RECT  215.832 187.632 216.024 187.656 ;
    END
  END r0a[667]
  PIN r0a[668]
    DIRECTION OUTPUT ;
    USE SIGNAL ;
    PORT
      LAYER M4 ;
        RECT  215.832 187.728 216.024 187.752 ;
    END
  END r0a[668]
  PIN r0a[669]
    DIRECTION OUTPUT ;
    USE SIGNAL ;
    PORT
      LAYER M4 ;
        RECT  215.832 187.824 216.024 187.848 ;
    END
  END r0a[669]
  PIN r0a[66]
    DIRECTION OUTPUT ;
    USE SIGNAL ;
    PORT
      LAYER M4 ;
        RECT  215.832 129.936 216.024 129.96 ;
    END
  END r0a[66]
  PIN r0a[670]
    DIRECTION OUTPUT ;
    USE SIGNAL ;
    PORT
      LAYER M4 ;
        RECT  215.832 187.92 216.024 187.944 ;
    END
  END r0a[670]
  PIN r0a[671]
    DIRECTION OUTPUT ;
    USE SIGNAL ;
    PORT
      LAYER M4 ;
        RECT  215.832 188.016 216.024 188.04 ;
    END
  END r0a[671]
  PIN r0a[672]
    DIRECTION OUTPUT ;
    USE SIGNAL ;
    PORT
      LAYER M4 ;
        RECT  215.832 188.112 216.024 188.136 ;
    END
  END r0a[672]
  PIN r0a[673]
    DIRECTION OUTPUT ;
    USE SIGNAL ;
    PORT
      LAYER M4 ;
        RECT  215.832 188.208 216.024 188.232 ;
    END
  END r0a[673]
  PIN r0a[674]
    DIRECTION OUTPUT ;
    USE SIGNAL ;
    PORT
      LAYER M4 ;
        RECT  215.832 188.304 216.024 188.328 ;
    END
  END r0a[674]
  PIN r0a[675]
    DIRECTION OUTPUT ;
    USE SIGNAL ;
    PORT
      LAYER M4 ;
        RECT  215.832 188.4 216.024 188.424 ;
    END
  END r0a[675]
  PIN r0a[676]
    DIRECTION OUTPUT ;
    USE SIGNAL ;
    PORT
      LAYER M4 ;
        RECT  215.832 188.496 216.024 188.52 ;
    END
  END r0a[676]
  PIN r0a[677]
    DIRECTION OUTPUT ;
    USE SIGNAL ;
    PORT
      LAYER M4 ;
        RECT  215.832 188.592 216.024 188.616 ;
    END
  END r0a[677]
  PIN r0a[678]
    DIRECTION OUTPUT ;
    USE SIGNAL ;
    PORT
      LAYER M4 ;
        RECT  215.832 188.688 216.024 188.712 ;
    END
  END r0a[678]
  PIN r0a[679]
    DIRECTION OUTPUT ;
    USE SIGNAL ;
    PORT
      LAYER M4 ;
        RECT  215.832 188.784 216.024 188.808 ;
    END
  END r0a[679]
  PIN r0a[67]
    DIRECTION OUTPUT ;
    USE SIGNAL ;
    PORT
      LAYER M4 ;
        RECT  215.832 130.032 216.024 130.056 ;
    END
  END r0a[67]
  PIN r0a[680]
    DIRECTION OUTPUT ;
    USE SIGNAL ;
    PORT
      LAYER M4 ;
        RECT  215.832 188.88 216.024 188.904 ;
    END
  END r0a[680]
  PIN r0a[681]
    DIRECTION OUTPUT ;
    USE SIGNAL ;
    PORT
      LAYER M4 ;
        RECT  215.832 188.976 216.024 189 ;
    END
  END r0a[681]
  PIN r0a[682]
    DIRECTION OUTPUT ;
    USE SIGNAL ;
    PORT
      LAYER M4 ;
        RECT  215.832 189.072 216.024 189.096 ;
    END
  END r0a[682]
  PIN r0a[683]
    DIRECTION OUTPUT ;
    USE SIGNAL ;
    PORT
      LAYER M4 ;
        RECT  215.832 189.168 216.024 189.192 ;
    END
  END r0a[683]
  PIN r0a[684]
    DIRECTION OUTPUT ;
    USE SIGNAL ;
    PORT
      LAYER M4 ;
        RECT  215.832 189.264 216.024 189.288 ;
    END
  END r0a[684]
  PIN r0a[685]
    DIRECTION OUTPUT ;
    USE SIGNAL ;
    PORT
      LAYER M4 ;
        RECT  215.832 189.36 216.024 189.384 ;
    END
  END r0a[685]
  PIN r0a[686]
    DIRECTION OUTPUT ;
    USE SIGNAL ;
    PORT
      LAYER M4 ;
        RECT  215.832 189.456 216.024 189.48 ;
    END
  END r0a[686]
  PIN r0a[687]
    DIRECTION OUTPUT ;
    USE SIGNAL ;
    PORT
      LAYER M4 ;
        RECT  215.832 189.552 216.024 189.576 ;
    END
  END r0a[687]
  PIN r0a[688]
    DIRECTION OUTPUT ;
    USE SIGNAL ;
    PORT
      LAYER M4 ;
        RECT  215.832 189.648 216.024 189.672 ;
    END
  END r0a[688]
  PIN r0a[689]
    DIRECTION OUTPUT ;
    USE SIGNAL ;
    PORT
      LAYER M4 ;
        RECT  215.832 189.744 216.024 189.768 ;
    END
  END r0a[689]
  PIN r0a[68]
    DIRECTION OUTPUT ;
    USE SIGNAL ;
    PORT
      LAYER M4 ;
        RECT  215.832 130.128 216.024 130.152 ;
    END
  END r0a[68]
  PIN r0a[690]
    DIRECTION OUTPUT ;
    USE SIGNAL ;
    PORT
      LAYER M4 ;
        RECT  215.832 189.84 216.024 189.864 ;
    END
  END r0a[690]
  PIN r0a[691]
    DIRECTION OUTPUT ;
    USE SIGNAL ;
    PORT
      LAYER M4 ;
        RECT  215.832 189.936 216.024 189.96 ;
    END
  END r0a[691]
  PIN r0a[692]
    DIRECTION OUTPUT ;
    USE SIGNAL ;
    PORT
      LAYER M4 ;
        RECT  215.832 190.032 216.024 190.056 ;
    END
  END r0a[692]
  PIN r0a[693]
    DIRECTION OUTPUT ;
    USE SIGNAL ;
    PORT
      LAYER M4 ;
        RECT  215.832 190.128 216.024 190.152 ;
    END
  END r0a[693]
  PIN r0a[694]
    DIRECTION OUTPUT ;
    USE SIGNAL ;
    PORT
      LAYER M4 ;
        RECT  215.832 190.224 216.024 190.248 ;
    END
  END r0a[694]
  PIN r0a[695]
    DIRECTION OUTPUT ;
    USE SIGNAL ;
    PORT
      LAYER M4 ;
        RECT  215.832 190.32 216.024 190.344 ;
    END
  END r0a[695]
  PIN r0a[696]
    DIRECTION OUTPUT ;
    USE SIGNAL ;
    PORT
      LAYER M4 ;
        RECT  215.832 190.416 216.024 190.44 ;
    END
  END r0a[696]
  PIN r0a[697]
    DIRECTION OUTPUT ;
    USE SIGNAL ;
    PORT
      LAYER M4 ;
        RECT  215.832 190.512 216.024 190.536 ;
    END
  END r0a[697]
  PIN r0a[698]
    DIRECTION OUTPUT ;
    USE SIGNAL ;
    PORT
      LAYER M4 ;
        RECT  215.832 190.608 216.024 190.632 ;
    END
  END r0a[698]
  PIN r0a[699]
    DIRECTION OUTPUT ;
    USE SIGNAL ;
    PORT
      LAYER M4 ;
        RECT  215.832 190.704 216.024 190.728 ;
    END
  END r0a[699]
  PIN r0a[69]
    DIRECTION OUTPUT ;
    USE SIGNAL ;
    PORT
      LAYER M4 ;
        RECT  215.832 130.224 216.024 130.248 ;
    END
  END r0a[69]
  PIN r0a[6]
    DIRECTION OUTPUT ;
    USE SIGNAL ;
    PORT
      LAYER M4 ;
        RECT  215.832 124.176 216.024 124.2 ;
    END
  END r0a[6]
  PIN r0a[700]
    DIRECTION OUTPUT ;
    USE SIGNAL ;
    PORT
      LAYER M4 ;
        RECT  215.832 190.8 216.024 190.824 ;
    END
  END r0a[700]
  PIN r0a[701]
    DIRECTION OUTPUT ;
    USE SIGNAL ;
    PORT
      LAYER M4 ;
        RECT  215.832 190.896 216.024 190.92 ;
    END
  END r0a[701]
  PIN r0a[702]
    DIRECTION OUTPUT ;
    USE SIGNAL ;
    PORT
      LAYER M4 ;
        RECT  215.832 190.992 216.024 191.016 ;
    END
  END r0a[702]
  PIN r0a[703]
    DIRECTION OUTPUT ;
    USE SIGNAL ;
    PORT
      LAYER M4 ;
        RECT  215.832 191.088 216.024 191.112 ;
    END
  END r0a[703]
  PIN r0a[704]
    DIRECTION OUTPUT ;
    USE SIGNAL ;
    PORT
      LAYER M4 ;
        RECT  215.832 191.184 216.024 191.208 ;
    END
  END r0a[704]
  PIN r0a[705]
    DIRECTION OUTPUT ;
    USE SIGNAL ;
    PORT
      LAYER M4 ;
        RECT  215.832 191.28 216.024 191.304 ;
    END
  END r0a[705]
  PIN r0a[706]
    DIRECTION OUTPUT ;
    USE SIGNAL ;
    PORT
      LAYER M4 ;
        RECT  215.832 191.376 216.024 191.4 ;
    END
  END r0a[706]
  PIN r0a[707]
    DIRECTION OUTPUT ;
    USE SIGNAL ;
    PORT
      LAYER M4 ;
        RECT  215.832 191.472 216.024 191.496 ;
    END
  END r0a[707]
  PIN r0a[708]
    DIRECTION OUTPUT ;
    USE SIGNAL ;
    PORT
      LAYER M4 ;
        RECT  215.832 191.568 216.024 191.592 ;
    END
  END r0a[708]
  PIN r0a[709]
    DIRECTION OUTPUT ;
    USE SIGNAL ;
    PORT
      LAYER M4 ;
        RECT  215.832 191.664 216.024 191.688 ;
    END
  END r0a[709]
  PIN r0a[70]
    DIRECTION OUTPUT ;
    USE SIGNAL ;
    PORT
      LAYER M4 ;
        RECT  215.832 130.32 216.024 130.344 ;
    END
  END r0a[70]
  PIN r0a[710]
    DIRECTION OUTPUT ;
    USE SIGNAL ;
    PORT
      LAYER M4 ;
        RECT  215.832 191.76 216.024 191.784 ;
    END
  END r0a[710]
  PIN r0a[711]
    DIRECTION OUTPUT ;
    USE SIGNAL ;
    PORT
      LAYER M4 ;
        RECT  215.832 191.856 216.024 191.88 ;
    END
  END r0a[711]
  PIN r0a[712]
    DIRECTION OUTPUT ;
    USE SIGNAL ;
    PORT
      LAYER M4 ;
        RECT  215.832 191.952 216.024 191.976 ;
    END
  END r0a[712]
  PIN r0a[713]
    DIRECTION OUTPUT ;
    USE SIGNAL ;
    PORT
      LAYER M4 ;
        RECT  215.832 192.048 216.024 192.072 ;
    END
  END r0a[713]
  PIN r0a[714]
    DIRECTION OUTPUT ;
    USE SIGNAL ;
    PORT
      LAYER M4 ;
        RECT  215.832 192.144 216.024 192.168 ;
    END
  END r0a[714]
  PIN r0a[715]
    DIRECTION OUTPUT ;
    USE SIGNAL ;
    PORT
      LAYER M4 ;
        RECT  215.832 192.24 216.024 192.264 ;
    END
  END r0a[715]
  PIN r0a[716]
    DIRECTION OUTPUT ;
    USE SIGNAL ;
    PORT
      LAYER M4 ;
        RECT  215.832 192.336 216.024 192.36 ;
    END
  END r0a[716]
  PIN r0a[717]
    DIRECTION OUTPUT ;
    USE SIGNAL ;
    PORT
      LAYER M4 ;
        RECT  215.832 192.432 216.024 192.456 ;
    END
  END r0a[717]
  PIN r0a[718]
    DIRECTION OUTPUT ;
    USE SIGNAL ;
    PORT
      LAYER M4 ;
        RECT  215.832 192.528 216.024 192.552 ;
    END
  END r0a[718]
  PIN r0a[719]
    DIRECTION OUTPUT ;
    USE SIGNAL ;
    PORT
      LAYER M4 ;
        RECT  215.832 192.624 216.024 192.648 ;
    END
  END r0a[719]
  PIN r0a[71]
    DIRECTION OUTPUT ;
    USE SIGNAL ;
    PORT
      LAYER M4 ;
        RECT  215.832 130.416 216.024 130.44 ;
    END
  END r0a[71]
  PIN r0a[720]
    DIRECTION OUTPUT ;
    USE SIGNAL ;
    PORT
      LAYER M4 ;
        RECT  215.832 192.72 216.024 192.744 ;
    END
  END r0a[720]
  PIN r0a[721]
    DIRECTION OUTPUT ;
    USE SIGNAL ;
    PORT
      LAYER M4 ;
        RECT  215.832 192.816 216.024 192.84 ;
    END
  END r0a[721]
  PIN r0a[722]
    DIRECTION OUTPUT ;
    USE SIGNAL ;
    PORT
      LAYER M4 ;
        RECT  215.832 192.912 216.024 192.936 ;
    END
  END r0a[722]
  PIN r0a[723]
    DIRECTION OUTPUT ;
    USE SIGNAL ;
    PORT
      LAYER M4 ;
        RECT  215.832 193.008 216.024 193.032 ;
    END
  END r0a[723]
  PIN r0a[724]
    DIRECTION OUTPUT ;
    USE SIGNAL ;
    PORT
      LAYER M4 ;
        RECT  215.832 193.104 216.024 193.128 ;
    END
  END r0a[724]
  PIN r0a[725]
    DIRECTION OUTPUT ;
    USE SIGNAL ;
    PORT
      LAYER M4 ;
        RECT  215.832 193.2 216.024 193.224 ;
    END
  END r0a[725]
  PIN r0a[726]
    DIRECTION OUTPUT ;
    USE SIGNAL ;
    PORT
      LAYER M4 ;
        RECT  215.832 193.296 216.024 193.32 ;
    END
  END r0a[726]
  PIN r0a[727]
    DIRECTION OUTPUT ;
    USE SIGNAL ;
    PORT
      LAYER M4 ;
        RECT  215.832 193.392 216.024 193.416 ;
    END
  END r0a[727]
  PIN r0a[728]
    DIRECTION OUTPUT ;
    USE SIGNAL ;
    PORT
      LAYER M4 ;
        RECT  215.832 193.488 216.024 193.512 ;
    END
  END r0a[728]
  PIN r0a[729]
    DIRECTION OUTPUT ;
    USE SIGNAL ;
    PORT
      LAYER M4 ;
        RECT  215.832 193.584 216.024 193.608 ;
    END
  END r0a[729]
  PIN r0a[72]
    DIRECTION OUTPUT ;
    USE SIGNAL ;
    PORT
      LAYER M4 ;
        RECT  215.832 130.512 216.024 130.536 ;
    END
  END r0a[72]
  PIN r0a[730]
    DIRECTION OUTPUT ;
    USE SIGNAL ;
    PORT
      LAYER M4 ;
        RECT  215.832 193.68 216.024 193.704 ;
    END
  END r0a[730]
  PIN r0a[731]
    DIRECTION OUTPUT ;
    USE SIGNAL ;
    PORT
      LAYER M4 ;
        RECT  215.832 193.776 216.024 193.8 ;
    END
  END r0a[731]
  PIN r0a[732]
    DIRECTION OUTPUT ;
    USE SIGNAL ;
    PORT
      LAYER M4 ;
        RECT  215.832 193.872 216.024 193.896 ;
    END
  END r0a[732]
  PIN r0a[733]
    DIRECTION OUTPUT ;
    USE SIGNAL ;
    PORT
      LAYER M4 ;
        RECT  215.832 193.968 216.024 193.992 ;
    END
  END r0a[733]
  PIN r0a[734]
    DIRECTION OUTPUT ;
    USE SIGNAL ;
    PORT
      LAYER M4 ;
        RECT  215.832 194.064 216.024 194.088 ;
    END
  END r0a[734]
  PIN r0a[735]
    DIRECTION OUTPUT ;
    USE SIGNAL ;
    PORT
      LAYER M4 ;
        RECT  215.832 194.16 216.024 194.184 ;
    END
  END r0a[735]
  PIN r0a[736]
    DIRECTION OUTPUT ;
    USE SIGNAL ;
    PORT
      LAYER M4 ;
        RECT  215.832 194.256 216.024 194.28 ;
    END
  END r0a[736]
  PIN r0a[737]
    DIRECTION OUTPUT ;
    USE SIGNAL ;
    PORT
      LAYER M4 ;
        RECT  215.832 194.352 216.024 194.376 ;
    END
  END r0a[737]
  PIN r0a[738]
    DIRECTION OUTPUT ;
    USE SIGNAL ;
    PORT
      LAYER M4 ;
        RECT  215.832 194.448 216.024 194.472 ;
    END
  END r0a[738]
  PIN r0a[739]
    DIRECTION OUTPUT ;
    USE SIGNAL ;
    PORT
      LAYER M4 ;
        RECT  215.832 194.544 216.024 194.568 ;
    END
  END r0a[739]
  PIN r0a[73]
    DIRECTION OUTPUT ;
    USE SIGNAL ;
    PORT
      LAYER M4 ;
        RECT  215.832 130.608 216.024 130.632 ;
    END
  END r0a[73]
  PIN r0a[740]
    DIRECTION OUTPUT ;
    USE SIGNAL ;
    PORT
      LAYER M4 ;
        RECT  215.832 194.64 216.024 194.664 ;
    END
  END r0a[740]
  PIN r0a[741]
    DIRECTION OUTPUT ;
    USE SIGNAL ;
    PORT
      LAYER M4 ;
        RECT  215.832 194.736 216.024 194.76 ;
    END
  END r0a[741]
  PIN r0a[742]
    DIRECTION OUTPUT ;
    USE SIGNAL ;
    PORT
      LAYER M4 ;
        RECT  215.832 194.832 216.024 194.856 ;
    END
  END r0a[742]
  PIN r0a[743]
    DIRECTION OUTPUT ;
    USE SIGNAL ;
    PORT
      LAYER M4 ;
        RECT  215.832 194.928 216.024 194.952 ;
    END
  END r0a[743]
  PIN r0a[744]
    DIRECTION OUTPUT ;
    USE SIGNAL ;
    PORT
      LAYER M4 ;
        RECT  215.832 195.024 216.024 195.048 ;
    END
  END r0a[744]
  PIN r0a[745]
    DIRECTION OUTPUT ;
    USE SIGNAL ;
    PORT
      LAYER M4 ;
        RECT  215.832 195.12 216.024 195.144 ;
    END
  END r0a[745]
  PIN r0a[746]
    DIRECTION OUTPUT ;
    USE SIGNAL ;
    PORT
      LAYER M4 ;
        RECT  215.832 195.216 216.024 195.24 ;
    END
  END r0a[746]
  PIN r0a[747]
    DIRECTION OUTPUT ;
    USE SIGNAL ;
    PORT
      LAYER M4 ;
        RECT  215.832 195.312 216.024 195.336 ;
    END
  END r0a[747]
  PIN r0a[748]
    DIRECTION OUTPUT ;
    USE SIGNAL ;
    PORT
      LAYER M4 ;
        RECT  215.832 195.408 216.024 195.432 ;
    END
  END r0a[748]
  PIN r0a[749]
    DIRECTION OUTPUT ;
    USE SIGNAL ;
    PORT
      LAYER M4 ;
        RECT  215.832 195.504 216.024 195.528 ;
    END
  END r0a[749]
  PIN r0a[74]
    DIRECTION OUTPUT ;
    USE SIGNAL ;
    PORT
      LAYER M4 ;
        RECT  215.832 130.704 216.024 130.728 ;
    END
  END r0a[74]
  PIN r0a[750]
    DIRECTION OUTPUT ;
    USE SIGNAL ;
    PORT
      LAYER M4 ;
        RECT  215.832 195.6 216.024 195.624 ;
    END
  END r0a[750]
  PIN r0a[751]
    DIRECTION OUTPUT ;
    USE SIGNAL ;
    PORT
      LAYER M4 ;
        RECT  215.832 195.696 216.024 195.72 ;
    END
  END r0a[751]
  PIN r0a[752]
    DIRECTION OUTPUT ;
    USE SIGNAL ;
    PORT
      LAYER M4 ;
        RECT  215.832 195.792 216.024 195.816 ;
    END
  END r0a[752]
  PIN r0a[753]
    DIRECTION OUTPUT ;
    USE SIGNAL ;
    PORT
      LAYER M4 ;
        RECT  215.832 195.888 216.024 195.912 ;
    END
  END r0a[753]
  PIN r0a[754]
    DIRECTION OUTPUT ;
    USE SIGNAL ;
    PORT
      LAYER M4 ;
        RECT  215.832 195.984 216.024 196.008 ;
    END
  END r0a[754]
  PIN r0a[755]
    DIRECTION OUTPUT ;
    USE SIGNAL ;
    PORT
      LAYER M4 ;
        RECT  215.832 196.08 216.024 196.104 ;
    END
  END r0a[755]
  PIN r0a[756]
    DIRECTION OUTPUT ;
    USE SIGNAL ;
    PORT
      LAYER M4 ;
        RECT  215.832 196.176 216.024 196.2 ;
    END
  END r0a[756]
  PIN r0a[757]
    DIRECTION OUTPUT ;
    USE SIGNAL ;
    PORT
      LAYER M4 ;
        RECT  215.832 196.272 216.024 196.296 ;
    END
  END r0a[757]
  PIN r0a[758]
    DIRECTION OUTPUT ;
    USE SIGNAL ;
    PORT
      LAYER M4 ;
        RECT  215.832 196.368 216.024 196.392 ;
    END
  END r0a[758]
  PIN r0a[759]
    DIRECTION OUTPUT ;
    USE SIGNAL ;
    PORT
      LAYER M4 ;
        RECT  215.832 196.464 216.024 196.488 ;
    END
  END r0a[759]
  PIN r0a[75]
    DIRECTION OUTPUT ;
    USE SIGNAL ;
    PORT
      LAYER M4 ;
        RECT  215.832 130.8 216.024 130.824 ;
    END
  END r0a[75]
  PIN r0a[760]
    DIRECTION OUTPUT ;
    USE SIGNAL ;
    PORT
      LAYER M4 ;
        RECT  215.832 196.56 216.024 196.584 ;
    END
  END r0a[760]
  PIN r0a[761]
    DIRECTION OUTPUT ;
    USE SIGNAL ;
    PORT
      LAYER M4 ;
        RECT  215.832 196.656 216.024 196.68 ;
    END
  END r0a[761]
  PIN r0a[762]
    DIRECTION OUTPUT ;
    USE SIGNAL ;
    PORT
      LAYER M4 ;
        RECT  215.832 196.752 216.024 196.776 ;
    END
  END r0a[762]
  PIN r0a[763]
    DIRECTION OUTPUT ;
    USE SIGNAL ;
    PORT
      LAYER M4 ;
        RECT  215.832 196.848 216.024 196.872 ;
    END
  END r0a[763]
  PIN r0a[764]
    DIRECTION OUTPUT ;
    USE SIGNAL ;
    PORT
      LAYER M4 ;
        RECT  215.832 196.944 216.024 196.968 ;
    END
  END r0a[764]
  PIN r0a[765]
    DIRECTION OUTPUT ;
    USE SIGNAL ;
    PORT
      LAYER M4 ;
        RECT  215.832 197.04 216.024 197.064 ;
    END
  END r0a[765]
  PIN r0a[766]
    DIRECTION OUTPUT ;
    USE SIGNAL ;
    PORT
      LAYER M4 ;
        RECT  215.832 197.136 216.024 197.16 ;
    END
  END r0a[766]
  PIN r0a[767]
    DIRECTION OUTPUT ;
    USE SIGNAL ;
    PORT
      LAYER M4 ;
        RECT  215.832 197.232 216.024 197.256 ;
    END
  END r0a[767]
  PIN r0a[768]
    DIRECTION OUTPUT ;
    USE SIGNAL ;
    PORT
      LAYER M4 ;
        RECT  215.832 197.328 216.024 197.352 ;
    END
  END r0a[768]
  PIN r0a[769]
    DIRECTION OUTPUT ;
    USE SIGNAL ;
    PORT
      LAYER M4 ;
        RECT  215.832 197.424 216.024 197.448 ;
    END
  END r0a[769]
  PIN r0a[76]
    DIRECTION OUTPUT ;
    USE SIGNAL ;
    PORT
      LAYER M4 ;
        RECT  215.832 130.896 216.024 130.92 ;
    END
  END r0a[76]
  PIN r0a[770]
    DIRECTION OUTPUT ;
    USE SIGNAL ;
    PORT
      LAYER M4 ;
        RECT  215.832 197.52 216.024 197.544 ;
    END
  END r0a[770]
  PIN r0a[771]
    DIRECTION OUTPUT ;
    USE SIGNAL ;
    PORT
      LAYER M4 ;
        RECT  215.832 197.616 216.024 197.64 ;
    END
  END r0a[771]
  PIN r0a[772]
    DIRECTION OUTPUT ;
    USE SIGNAL ;
    PORT
      LAYER M4 ;
        RECT  215.832 197.712 216.024 197.736 ;
    END
  END r0a[772]
  PIN r0a[773]
    DIRECTION OUTPUT ;
    USE SIGNAL ;
    PORT
      LAYER M4 ;
        RECT  215.832 197.808 216.024 197.832 ;
    END
  END r0a[773]
  PIN r0a[774]
    DIRECTION OUTPUT ;
    USE SIGNAL ;
    PORT
      LAYER M4 ;
        RECT  215.832 197.904 216.024 197.928 ;
    END
  END r0a[774]
  PIN r0a[775]
    DIRECTION OUTPUT ;
    USE SIGNAL ;
    PORT
      LAYER M4 ;
        RECT  215.832 198 216.024 198.024 ;
    END
  END r0a[775]
  PIN r0a[776]
    DIRECTION OUTPUT ;
    USE SIGNAL ;
    PORT
      LAYER M4 ;
        RECT  215.832 198.096 216.024 198.12 ;
    END
  END r0a[776]
  PIN r0a[777]
    DIRECTION OUTPUT ;
    USE SIGNAL ;
    PORT
      LAYER M4 ;
        RECT  215.832 198.192 216.024 198.216 ;
    END
  END r0a[777]
  PIN r0a[778]
    DIRECTION OUTPUT ;
    USE SIGNAL ;
    PORT
      LAYER M4 ;
        RECT  215.832 198.288 216.024 198.312 ;
    END
  END r0a[778]
  PIN r0a[779]
    DIRECTION OUTPUT ;
    USE SIGNAL ;
    PORT
      LAYER M4 ;
        RECT  215.832 198.384 216.024 198.408 ;
    END
  END r0a[779]
  PIN r0a[77]
    DIRECTION OUTPUT ;
    USE SIGNAL ;
    PORT
      LAYER M4 ;
        RECT  215.832 130.992 216.024 131.016 ;
    END
  END r0a[77]
  PIN r0a[780]
    DIRECTION OUTPUT ;
    USE SIGNAL ;
    PORT
      LAYER M4 ;
        RECT  215.832 198.48 216.024 198.504 ;
    END
  END r0a[780]
  PIN r0a[781]
    DIRECTION OUTPUT ;
    USE SIGNAL ;
    PORT
      LAYER M4 ;
        RECT  215.832 198.576 216.024 198.6 ;
    END
  END r0a[781]
  PIN r0a[782]
    DIRECTION OUTPUT ;
    USE SIGNAL ;
    PORT
      LAYER M4 ;
        RECT  215.832 198.672 216.024 198.696 ;
    END
  END r0a[782]
  PIN r0a[783]
    DIRECTION OUTPUT ;
    USE SIGNAL ;
    PORT
      LAYER M4 ;
        RECT  215.832 198.768 216.024 198.792 ;
    END
  END r0a[783]
  PIN r0a[784]
    DIRECTION OUTPUT ;
    USE SIGNAL ;
    PORT
      LAYER M4 ;
        RECT  215.832 198.864 216.024 198.888 ;
    END
  END r0a[784]
  PIN r0a[785]
    DIRECTION OUTPUT ;
    USE SIGNAL ;
    PORT
      LAYER M4 ;
        RECT  215.832 198.96 216.024 198.984 ;
    END
  END r0a[785]
  PIN r0a[786]
    DIRECTION OUTPUT ;
    USE SIGNAL ;
    PORT
      LAYER M4 ;
        RECT  215.832 199.056 216.024 199.08 ;
    END
  END r0a[786]
  PIN r0a[787]
    DIRECTION OUTPUT ;
    USE SIGNAL ;
    PORT
      LAYER M4 ;
        RECT  215.832 199.152 216.024 199.176 ;
    END
  END r0a[787]
  PIN r0a[788]
    DIRECTION OUTPUT ;
    USE SIGNAL ;
    PORT
      LAYER M4 ;
        RECT  215.832 199.248 216.024 199.272 ;
    END
  END r0a[788]
  PIN r0a[789]
    DIRECTION OUTPUT ;
    USE SIGNAL ;
    PORT
      LAYER M4 ;
        RECT  215.832 199.344 216.024 199.368 ;
    END
  END r0a[789]
  PIN r0a[78]
    DIRECTION OUTPUT ;
    USE SIGNAL ;
    PORT
      LAYER M4 ;
        RECT  215.832 131.088 216.024 131.112 ;
    END
  END r0a[78]
  PIN r0a[790]
    DIRECTION OUTPUT ;
    USE SIGNAL ;
    PORT
      LAYER M4 ;
        RECT  215.832 199.44 216.024 199.464 ;
    END
  END r0a[790]
  PIN r0a[791]
    DIRECTION OUTPUT ;
    USE SIGNAL ;
    PORT
      LAYER M4 ;
        RECT  215.832 199.536 216.024 199.56 ;
    END
  END r0a[791]
  PIN r0a[792]
    DIRECTION OUTPUT ;
    USE SIGNAL ;
    PORT
      LAYER M4 ;
        RECT  215.832 199.632 216.024 199.656 ;
    END
  END r0a[792]
  PIN r0a[793]
    DIRECTION OUTPUT ;
    USE SIGNAL ;
    PORT
      LAYER M4 ;
        RECT  215.832 199.728 216.024 199.752 ;
    END
  END r0a[793]
  PIN r0a[794]
    DIRECTION OUTPUT ;
    USE SIGNAL ;
    PORT
      LAYER M4 ;
        RECT  215.832 199.824 216.024 199.848 ;
    END
  END r0a[794]
  PIN r0a[795]
    DIRECTION OUTPUT ;
    USE SIGNAL ;
    PORT
      LAYER M4 ;
        RECT  215.832 199.92 216.024 199.944 ;
    END
  END r0a[795]
  PIN r0a[796]
    DIRECTION OUTPUT ;
    USE SIGNAL ;
    PORT
      LAYER M4 ;
        RECT  215.832 200.016 216.024 200.04 ;
    END
  END r0a[796]
  PIN r0a[797]
    DIRECTION OUTPUT ;
    USE SIGNAL ;
    PORT
      LAYER M4 ;
        RECT  215.832 200.112 216.024 200.136 ;
    END
  END r0a[797]
  PIN r0a[798]
    DIRECTION OUTPUT ;
    USE SIGNAL ;
    PORT
      LAYER M4 ;
        RECT  215.832 200.208 216.024 200.232 ;
    END
  END r0a[798]
  PIN r0a[799]
    DIRECTION OUTPUT ;
    USE SIGNAL ;
    PORT
      LAYER M4 ;
        RECT  215.832 200.304 216.024 200.328 ;
    END
  END r0a[799]
  PIN r0a[79]
    DIRECTION OUTPUT ;
    USE SIGNAL ;
    PORT
      LAYER M4 ;
        RECT  215.832 131.184 216.024 131.208 ;
    END
  END r0a[79]
  PIN r0a[7]
    DIRECTION OUTPUT ;
    USE SIGNAL ;
    PORT
      LAYER M4 ;
        RECT  215.832 124.272 216.024 124.296 ;
    END
  END r0a[7]
  PIN r0a[800]
    DIRECTION OUTPUT ;
    USE SIGNAL ;
    PORT
      LAYER M4 ;
        RECT  215.832 200.4 216.024 200.424 ;
    END
  END r0a[800]
  PIN r0a[801]
    DIRECTION OUTPUT ;
    USE SIGNAL ;
    PORT
      LAYER M4 ;
        RECT  215.832 200.496 216.024 200.52 ;
    END
  END r0a[801]
  PIN r0a[802]
    DIRECTION OUTPUT ;
    USE SIGNAL ;
    PORT
      LAYER M4 ;
        RECT  215.832 200.592 216.024 200.616 ;
    END
  END r0a[802]
  PIN r0a[803]
    DIRECTION OUTPUT ;
    USE SIGNAL ;
    PORT
      LAYER M4 ;
        RECT  215.832 200.688 216.024 200.712 ;
    END
  END r0a[803]
  PIN r0a[804]
    DIRECTION OUTPUT ;
    USE SIGNAL ;
    PORT
      LAYER M4 ;
        RECT  215.832 200.784 216.024 200.808 ;
    END
  END r0a[804]
  PIN r0a[805]
    DIRECTION OUTPUT ;
    USE SIGNAL ;
    PORT
      LAYER M4 ;
        RECT  215.832 200.88 216.024 200.904 ;
    END
  END r0a[805]
  PIN r0a[806]
    DIRECTION OUTPUT ;
    USE SIGNAL ;
    PORT
      LAYER M4 ;
        RECT  215.832 200.976 216.024 201 ;
    END
  END r0a[806]
  PIN r0a[807]
    DIRECTION OUTPUT ;
    USE SIGNAL ;
    PORT
      LAYER M4 ;
        RECT  215.832 201.072 216.024 201.096 ;
    END
  END r0a[807]
  PIN r0a[808]
    DIRECTION OUTPUT ;
    USE SIGNAL ;
    PORT
      LAYER M4 ;
        RECT  215.832 201.168 216.024 201.192 ;
    END
  END r0a[808]
  PIN r0a[809]
    DIRECTION OUTPUT ;
    USE SIGNAL ;
    PORT
      LAYER M4 ;
        RECT  215.832 201.264 216.024 201.288 ;
    END
  END r0a[809]
  PIN r0a[80]
    DIRECTION OUTPUT ;
    USE SIGNAL ;
    PORT
      LAYER M4 ;
        RECT  215.832 131.28 216.024 131.304 ;
    END
  END r0a[80]
  PIN r0a[810]
    DIRECTION OUTPUT ;
    USE SIGNAL ;
    PORT
      LAYER M4 ;
        RECT  215.832 201.36 216.024 201.384 ;
    END
  END r0a[810]
  PIN r0a[811]
    DIRECTION OUTPUT ;
    USE SIGNAL ;
    PORT
      LAYER M4 ;
        RECT  215.832 201.456 216.024 201.48 ;
    END
  END r0a[811]
  PIN r0a[812]
    DIRECTION OUTPUT ;
    USE SIGNAL ;
    PORT
      LAYER M4 ;
        RECT  215.832 201.552 216.024 201.576 ;
    END
  END r0a[812]
  PIN r0a[813]
    DIRECTION OUTPUT ;
    USE SIGNAL ;
    PORT
      LAYER M4 ;
        RECT  215.832 201.648 216.024 201.672 ;
    END
  END r0a[813]
  PIN r0a[814]
    DIRECTION OUTPUT ;
    USE SIGNAL ;
    PORT
      LAYER M4 ;
        RECT  215.832 201.744 216.024 201.768 ;
    END
  END r0a[814]
  PIN r0a[815]
    DIRECTION OUTPUT ;
    USE SIGNAL ;
    PORT
      LAYER M4 ;
        RECT  215.832 201.84 216.024 201.864 ;
    END
  END r0a[815]
  PIN r0a[816]
    DIRECTION OUTPUT ;
    USE SIGNAL ;
    PORT
      LAYER M4 ;
        RECT  215.832 201.936 216.024 201.96 ;
    END
  END r0a[816]
  PIN r0a[817]
    DIRECTION OUTPUT ;
    USE SIGNAL ;
    PORT
      LAYER M4 ;
        RECT  215.832 202.032 216.024 202.056 ;
    END
  END r0a[817]
  PIN r0a[81]
    DIRECTION OUTPUT ;
    USE SIGNAL ;
    PORT
      LAYER M4 ;
        RECT  215.832 131.376 216.024 131.4 ;
    END
  END r0a[81]
  PIN r0a[82]
    DIRECTION OUTPUT ;
    USE SIGNAL ;
    PORT
      LAYER M4 ;
        RECT  215.832 131.472 216.024 131.496 ;
    END
  END r0a[82]
  PIN r0a[83]
    DIRECTION OUTPUT ;
    USE SIGNAL ;
    PORT
      LAYER M4 ;
        RECT  215.832 131.568 216.024 131.592 ;
    END
  END r0a[83]
  PIN r0a[84]
    DIRECTION OUTPUT ;
    USE SIGNAL ;
    PORT
      LAYER M4 ;
        RECT  215.832 131.664 216.024 131.688 ;
    END
  END r0a[84]
  PIN r0a[85]
    DIRECTION OUTPUT ;
    USE SIGNAL ;
    PORT
      LAYER M4 ;
        RECT  215.832 131.76 216.024 131.784 ;
    END
  END r0a[85]
  PIN r0a[86]
    DIRECTION OUTPUT ;
    USE SIGNAL ;
    PORT
      LAYER M4 ;
        RECT  215.832 131.856 216.024 131.88 ;
    END
  END r0a[86]
  PIN r0a[87]
    DIRECTION OUTPUT ;
    USE SIGNAL ;
    PORT
      LAYER M4 ;
        RECT  215.832 131.952 216.024 131.976 ;
    END
  END r0a[87]
  PIN r0a[88]
    DIRECTION OUTPUT ;
    USE SIGNAL ;
    PORT
      LAYER M4 ;
        RECT  215.832 132.048 216.024 132.072 ;
    END
  END r0a[88]
  PIN r0a[89]
    DIRECTION OUTPUT ;
    USE SIGNAL ;
    PORT
      LAYER M4 ;
        RECT  215.832 132.144 216.024 132.168 ;
    END
  END r0a[89]
  PIN r0a[8]
    DIRECTION OUTPUT ;
    USE SIGNAL ;
    PORT
      LAYER M4 ;
        RECT  215.832 124.368 216.024 124.392 ;
    END
  END r0a[8]
  PIN r0a[90]
    DIRECTION OUTPUT ;
    USE SIGNAL ;
    PORT
      LAYER M4 ;
        RECT  215.832 132.24 216.024 132.264 ;
    END
  END r0a[90]
  PIN r0a[91]
    DIRECTION OUTPUT ;
    USE SIGNAL ;
    PORT
      LAYER M4 ;
        RECT  215.832 132.336 216.024 132.36 ;
    END
  END r0a[91]
  PIN r0a[92]
    DIRECTION OUTPUT ;
    USE SIGNAL ;
    PORT
      LAYER M4 ;
        RECT  215.832 132.432 216.024 132.456 ;
    END
  END r0a[92]
  PIN r0a[93]
    DIRECTION OUTPUT ;
    USE SIGNAL ;
    PORT
      LAYER M4 ;
        RECT  215.832 132.528 216.024 132.552 ;
    END
  END r0a[93]
  PIN r0a[94]
    DIRECTION OUTPUT ;
    USE SIGNAL ;
    PORT
      LAYER M4 ;
        RECT  215.832 132.624 216.024 132.648 ;
    END
  END r0a[94]
  PIN r0a[95]
    DIRECTION OUTPUT ;
    USE SIGNAL ;
    PORT
      LAYER M4 ;
        RECT  215.832 132.72 216.024 132.744 ;
    END
  END r0a[95]
  PIN r0a[96]
    DIRECTION OUTPUT ;
    USE SIGNAL ;
    PORT
      LAYER M4 ;
        RECT  215.832 132.816 216.024 132.84 ;
    END
  END r0a[96]
  PIN r0a[97]
    DIRECTION OUTPUT ;
    USE SIGNAL ;
    PORT
      LAYER M4 ;
        RECT  215.832 132.912 216.024 132.936 ;
    END
  END r0a[97]
  PIN r0a[98]
    DIRECTION OUTPUT ;
    USE SIGNAL ;
    PORT
      LAYER M4 ;
        RECT  215.832 133.008 216.024 133.032 ;
    END
  END r0a[98]
  PIN r0a[99]
    DIRECTION OUTPUT ;
    USE SIGNAL ;
    PORT
      LAYER M4 ;
        RECT  215.832 133.104 216.024 133.128 ;
    END
  END r0a[99]
  PIN r0a[9]
    DIRECTION OUTPUT ;
    USE SIGNAL ;
    PORT
      LAYER M4 ;
        RECT  215.832 124.464 216.024 124.488 ;
    END
  END r0a[9]
  PIN rout[0]
    DIRECTION OUTPUT ;
    USE SIGNAL ;
    PORT
      LAYER M4 ;
        RECT  0 215.952 0.192 215.976 ;
    END
  END rout[0]
  PIN rout[100]
    DIRECTION OUTPUT ;
    USE SIGNAL ;
    PORT
      LAYER M4 ;
        RECT  0 206.352 0.192 206.376 ;
    END
  END rout[100]
  PIN rout[101]
    DIRECTION OUTPUT ;
    USE SIGNAL ;
    PORT
      LAYER M4 ;
        RECT  0 206.256 0.192 206.28 ;
    END
  END rout[101]
  PIN rout[102]
    DIRECTION OUTPUT ;
    USE SIGNAL ;
    PORT
      LAYER M4 ;
        RECT  0 206.16 0.192 206.184 ;
    END
  END rout[102]
  PIN rout[103]
    DIRECTION OUTPUT ;
    USE SIGNAL ;
    PORT
      LAYER M4 ;
        RECT  0 206.064 0.192 206.088 ;
    END
  END rout[103]
  PIN rout[104]
    DIRECTION OUTPUT ;
    USE SIGNAL ;
    PORT
      LAYER M4 ;
        RECT  0 205.968 0.192 205.992 ;
    END
  END rout[104]
  PIN rout[105]
    DIRECTION OUTPUT ;
    USE SIGNAL ;
    PORT
      LAYER M4 ;
        RECT  0 205.872 0.192 205.896 ;
    END
  END rout[105]
  PIN rout[106]
    DIRECTION OUTPUT ;
    USE SIGNAL ;
    PORT
      LAYER M4 ;
        RECT  0 205.776 0.192 205.8 ;
    END
  END rout[106]
  PIN rout[107]
    DIRECTION OUTPUT ;
    USE SIGNAL ;
    PORT
      LAYER M4 ;
        RECT  0 205.68 0.192 205.704 ;
    END
  END rout[107]
  PIN rout[108]
    DIRECTION OUTPUT ;
    USE SIGNAL ;
    PORT
      LAYER M4 ;
        RECT  0 205.584 0.192 205.608 ;
    END
  END rout[108]
  PIN rout[109]
    DIRECTION OUTPUT ;
    USE SIGNAL ;
    PORT
      LAYER M4 ;
        RECT  0 205.488 0.192 205.512 ;
    END
  END rout[109]
  PIN rout[10]
    DIRECTION OUTPUT ;
    USE SIGNAL ;
    PORT
      LAYER M4 ;
        RECT  0 214.992 0.192 215.016 ;
    END
  END rout[10]
  PIN rout[110]
    DIRECTION OUTPUT ;
    USE SIGNAL ;
    PORT
      LAYER M4 ;
        RECT  0 205.392 0.192 205.416 ;
    END
  END rout[110]
  PIN rout[111]
    DIRECTION OUTPUT ;
    USE SIGNAL ;
    PORT
      LAYER M4 ;
        RECT  0 205.296 0.192 205.32 ;
    END
  END rout[111]
  PIN rout[112]
    DIRECTION OUTPUT ;
    USE SIGNAL ;
    PORT
      LAYER M4 ;
        RECT  0 205.2 0.192 205.224 ;
    END
  END rout[112]
  PIN rout[113]
    DIRECTION OUTPUT ;
    USE SIGNAL ;
    PORT
      LAYER M4 ;
        RECT  0 205.104 0.192 205.128 ;
    END
  END rout[113]
  PIN rout[114]
    DIRECTION OUTPUT ;
    USE SIGNAL ;
    PORT
      LAYER M4 ;
        RECT  0 205.008 0.192 205.032 ;
    END
  END rout[114]
  PIN rout[115]
    DIRECTION OUTPUT ;
    USE SIGNAL ;
    PORT
      LAYER M4 ;
        RECT  0 204.912 0.192 204.936 ;
    END
  END rout[115]
  PIN rout[116]
    DIRECTION OUTPUT ;
    USE SIGNAL ;
    PORT
      LAYER M4 ;
        RECT  0 204.816 0.192 204.84 ;
    END
  END rout[116]
  PIN rout[117]
    DIRECTION OUTPUT ;
    USE SIGNAL ;
    PORT
      LAYER M4 ;
        RECT  0 204.72 0.192 204.744 ;
    END
  END rout[117]
  PIN rout[118]
    DIRECTION OUTPUT ;
    USE SIGNAL ;
    PORT
      LAYER M4 ;
        RECT  0 204.624 0.192 204.648 ;
    END
  END rout[118]
  PIN rout[119]
    DIRECTION OUTPUT ;
    USE SIGNAL ;
    PORT
      LAYER M4 ;
        RECT  0 204.528 0.192 204.552 ;
    END
  END rout[119]
  PIN rout[11]
    DIRECTION OUTPUT ;
    USE SIGNAL ;
    PORT
      LAYER M4 ;
        RECT  0 214.896 0.192 214.92 ;
    END
  END rout[11]
  PIN rout[120]
    DIRECTION OUTPUT ;
    USE SIGNAL ;
    PORT
      LAYER M4 ;
        RECT  0 204.432 0.192 204.456 ;
    END
  END rout[120]
  PIN rout[121]
    DIRECTION OUTPUT ;
    USE SIGNAL ;
    PORT
      LAYER M4 ;
        RECT  0 204.336 0.192 204.36 ;
    END
  END rout[121]
  PIN rout[122]
    DIRECTION OUTPUT ;
    USE SIGNAL ;
    PORT
      LAYER M4 ;
        RECT  0 204.24 0.192 204.264 ;
    END
  END rout[122]
  PIN rout[123]
    DIRECTION OUTPUT ;
    USE SIGNAL ;
    PORT
      LAYER M4 ;
        RECT  0 204.144 0.192 204.168 ;
    END
  END rout[123]
  PIN rout[124]
    DIRECTION OUTPUT ;
    USE SIGNAL ;
    PORT
      LAYER M4 ;
        RECT  0 204.048 0.192 204.072 ;
    END
  END rout[124]
  PIN rout[125]
    DIRECTION OUTPUT ;
    USE SIGNAL ;
    PORT
      LAYER M4 ;
        RECT  0 203.952 0.192 203.976 ;
    END
  END rout[125]
  PIN rout[126]
    DIRECTION OUTPUT ;
    USE SIGNAL ;
    PORT
      LAYER M4 ;
        RECT  0 203.856 0.192 203.88 ;
    END
  END rout[126]
  PIN rout[127]
    DIRECTION OUTPUT ;
    USE SIGNAL ;
    PORT
      LAYER M4 ;
        RECT  0 203.76 0.192 203.784 ;
    END
  END rout[127]
  PIN rout[128]
    DIRECTION OUTPUT ;
    USE SIGNAL ;
    PORT
      LAYER M4 ;
        RECT  0 203.664 0.192 203.688 ;
    END
  END rout[128]
  PIN rout[129]
    DIRECTION OUTPUT ;
    USE SIGNAL ;
    PORT
      LAYER M4 ;
        RECT  0 203.568 0.192 203.592 ;
    END
  END rout[129]
  PIN rout[12]
    DIRECTION OUTPUT ;
    USE SIGNAL ;
    PORT
      LAYER M4 ;
        RECT  0 214.8 0.192 214.824 ;
    END
  END rout[12]
  PIN rout[130]
    DIRECTION OUTPUT ;
    USE SIGNAL ;
    PORT
      LAYER M4 ;
        RECT  0 203.472 0.192 203.496 ;
    END
  END rout[130]
  PIN rout[131]
    DIRECTION OUTPUT ;
    USE SIGNAL ;
    PORT
      LAYER M4 ;
        RECT  0 203.376 0.192 203.4 ;
    END
  END rout[131]
  PIN rout[132]
    DIRECTION OUTPUT ;
    USE SIGNAL ;
    PORT
      LAYER M4 ;
        RECT  0 203.28 0.192 203.304 ;
    END
  END rout[132]
  PIN rout[133]
    DIRECTION OUTPUT ;
    USE SIGNAL ;
    PORT
      LAYER M4 ;
        RECT  0 203.184 0.192 203.208 ;
    END
  END rout[133]
  PIN rout[134]
    DIRECTION OUTPUT ;
    USE SIGNAL ;
    PORT
      LAYER M4 ;
        RECT  0 203.088 0.192 203.112 ;
    END
  END rout[134]
  PIN rout[135]
    DIRECTION OUTPUT ;
    USE SIGNAL ;
    PORT
      LAYER M4 ;
        RECT  0 202.992 0.192 203.016 ;
    END
  END rout[135]
  PIN rout[136]
    DIRECTION OUTPUT ;
    USE SIGNAL ;
    PORT
      LAYER M4 ;
        RECT  0 202.896 0.192 202.92 ;
    END
  END rout[136]
  PIN rout[137]
    DIRECTION OUTPUT ;
    USE SIGNAL ;
    PORT
      LAYER M4 ;
        RECT  0 202.8 0.192 202.824 ;
    END
  END rout[137]
  PIN rout[138]
    DIRECTION OUTPUT ;
    USE SIGNAL ;
    PORT
      LAYER M4 ;
        RECT  0 202.704 0.192 202.728 ;
    END
  END rout[138]
  PIN rout[139]
    DIRECTION OUTPUT ;
    USE SIGNAL ;
    PORT
      LAYER M4 ;
        RECT  0 202.608 0.192 202.632 ;
    END
  END rout[139]
  PIN rout[13]
    DIRECTION OUTPUT ;
    USE SIGNAL ;
    PORT
      LAYER M4 ;
        RECT  0 214.704 0.192 214.728 ;
    END
  END rout[13]
  PIN rout[140]
    DIRECTION OUTPUT ;
    USE SIGNAL ;
    PORT
      LAYER M4 ;
        RECT  0 202.512 0.192 202.536 ;
    END
  END rout[140]
  PIN rout[141]
    DIRECTION OUTPUT ;
    USE SIGNAL ;
    PORT
      LAYER M4 ;
        RECT  0 202.416 0.192 202.44 ;
    END
  END rout[141]
  PIN rout[142]
    DIRECTION OUTPUT ;
    USE SIGNAL ;
    PORT
      LAYER M4 ;
        RECT  0 202.32 0.192 202.344 ;
    END
  END rout[142]
  PIN rout[143]
    DIRECTION OUTPUT ;
    USE SIGNAL ;
    PORT
      LAYER M4 ;
        RECT  0 202.224 0.192 202.248 ;
    END
  END rout[143]
  PIN rout[144]
    DIRECTION OUTPUT ;
    USE SIGNAL ;
    PORT
      LAYER M4 ;
        RECT  0 202.128 0.192 202.152 ;
    END
  END rout[144]
  PIN rout[145]
    DIRECTION OUTPUT ;
    USE SIGNAL ;
    PORT
      LAYER M4 ;
        RECT  0 202.032 0.192 202.056 ;
    END
  END rout[145]
  PIN rout[146]
    DIRECTION OUTPUT ;
    USE SIGNAL ;
    PORT
      LAYER M4 ;
        RECT  0 201.936 0.192 201.96 ;
    END
  END rout[146]
  PIN rout[147]
    DIRECTION OUTPUT ;
    USE SIGNAL ;
    PORT
      LAYER M4 ;
        RECT  0 201.84 0.192 201.864 ;
    END
  END rout[147]
  PIN rout[148]
    DIRECTION OUTPUT ;
    USE SIGNAL ;
    PORT
      LAYER M4 ;
        RECT  0 201.744 0.192 201.768 ;
    END
  END rout[148]
  PIN rout[149]
    DIRECTION OUTPUT ;
    USE SIGNAL ;
    PORT
      LAYER M4 ;
        RECT  0 201.648 0.192 201.672 ;
    END
  END rout[149]
  PIN rout[14]
    DIRECTION OUTPUT ;
    USE SIGNAL ;
    PORT
      LAYER M4 ;
        RECT  0 214.608 0.192 214.632 ;
    END
  END rout[14]
  PIN rout[150]
    DIRECTION OUTPUT ;
    USE SIGNAL ;
    PORT
      LAYER M4 ;
        RECT  0 201.552 0.192 201.576 ;
    END
  END rout[150]
  PIN rout[151]
    DIRECTION OUTPUT ;
    USE SIGNAL ;
    PORT
      LAYER M4 ;
        RECT  0 201.456 0.192 201.48 ;
    END
  END rout[151]
  PIN rout[152]
    DIRECTION OUTPUT ;
    USE SIGNAL ;
    PORT
      LAYER M4 ;
        RECT  0 201.36 0.192 201.384 ;
    END
  END rout[152]
  PIN rout[153]
    DIRECTION OUTPUT ;
    USE SIGNAL ;
    PORT
      LAYER M4 ;
        RECT  0 201.264 0.192 201.288 ;
    END
  END rout[153]
  PIN rout[154]
    DIRECTION OUTPUT ;
    USE SIGNAL ;
    PORT
      LAYER M4 ;
        RECT  0 201.168 0.192 201.192 ;
    END
  END rout[154]
  PIN rout[155]
    DIRECTION OUTPUT ;
    USE SIGNAL ;
    PORT
      LAYER M4 ;
        RECT  0 201.072 0.192 201.096 ;
    END
  END rout[155]
  PIN rout[156]
    DIRECTION OUTPUT ;
    USE SIGNAL ;
    PORT
      LAYER M4 ;
        RECT  0 200.976 0.192 201 ;
    END
  END rout[156]
  PIN rout[157]
    DIRECTION OUTPUT ;
    USE SIGNAL ;
    PORT
      LAYER M4 ;
        RECT  0 200.88 0.192 200.904 ;
    END
  END rout[157]
  PIN rout[158]
    DIRECTION OUTPUT ;
    USE SIGNAL ;
    PORT
      LAYER M4 ;
        RECT  0 200.784 0.192 200.808 ;
    END
  END rout[158]
  PIN rout[159]
    DIRECTION OUTPUT ;
    USE SIGNAL ;
    PORT
      LAYER M4 ;
        RECT  0 200.688 0.192 200.712 ;
    END
  END rout[159]
  PIN rout[15]
    DIRECTION OUTPUT ;
    USE SIGNAL ;
    PORT
      LAYER M4 ;
        RECT  0 214.512 0.192 214.536 ;
    END
  END rout[15]
  PIN rout[160]
    DIRECTION OUTPUT ;
    USE SIGNAL ;
    PORT
      LAYER M4 ;
        RECT  0 200.592 0.192 200.616 ;
    END
  END rout[160]
  PIN rout[161]
    DIRECTION OUTPUT ;
    USE SIGNAL ;
    PORT
      LAYER M4 ;
        RECT  0 200.496 0.192 200.52 ;
    END
  END rout[161]
  PIN rout[162]
    DIRECTION OUTPUT ;
    USE SIGNAL ;
    PORT
      LAYER M4 ;
        RECT  0 200.4 0.192 200.424 ;
    END
  END rout[162]
  PIN rout[163]
    DIRECTION OUTPUT ;
    USE SIGNAL ;
    PORT
      LAYER M4 ;
        RECT  0 200.304 0.192 200.328 ;
    END
  END rout[163]
  PIN rout[164]
    DIRECTION OUTPUT ;
    USE SIGNAL ;
    PORT
      LAYER M4 ;
        RECT  0 200.208 0.192 200.232 ;
    END
  END rout[164]
  PIN rout[165]
    DIRECTION OUTPUT ;
    USE SIGNAL ;
    PORT
      LAYER M4 ;
        RECT  0 200.112 0.192 200.136 ;
    END
  END rout[165]
  PIN rout[166]
    DIRECTION OUTPUT ;
    USE SIGNAL ;
    PORT
      LAYER M4 ;
        RECT  0 200.016 0.192 200.04 ;
    END
  END rout[166]
  PIN rout[167]
    DIRECTION OUTPUT ;
    USE SIGNAL ;
    PORT
      LAYER M4 ;
        RECT  0 199.92 0.192 199.944 ;
    END
  END rout[167]
  PIN rout[168]
    DIRECTION OUTPUT ;
    USE SIGNAL ;
    PORT
      LAYER M4 ;
        RECT  0 199.824 0.192 199.848 ;
    END
  END rout[168]
  PIN rout[169]
    DIRECTION OUTPUT ;
    USE SIGNAL ;
    PORT
      LAYER M4 ;
        RECT  0 199.728 0.192 199.752 ;
    END
  END rout[169]
  PIN rout[16]
    DIRECTION OUTPUT ;
    USE SIGNAL ;
    PORT
      LAYER M4 ;
        RECT  0 214.416 0.192 214.44 ;
    END
  END rout[16]
  PIN rout[170]
    DIRECTION OUTPUT ;
    USE SIGNAL ;
    PORT
      LAYER M4 ;
        RECT  0 199.632 0.192 199.656 ;
    END
  END rout[170]
  PIN rout[171]
    DIRECTION OUTPUT ;
    USE SIGNAL ;
    PORT
      LAYER M4 ;
        RECT  0 199.536 0.192 199.56 ;
    END
  END rout[171]
  PIN rout[172]
    DIRECTION OUTPUT ;
    USE SIGNAL ;
    PORT
      LAYER M4 ;
        RECT  0 199.44 0.192 199.464 ;
    END
  END rout[172]
  PIN rout[173]
    DIRECTION OUTPUT ;
    USE SIGNAL ;
    PORT
      LAYER M4 ;
        RECT  0 199.344 0.192 199.368 ;
    END
  END rout[173]
  PIN rout[174]
    DIRECTION OUTPUT ;
    USE SIGNAL ;
    PORT
      LAYER M4 ;
        RECT  0 199.248 0.192 199.272 ;
    END
  END rout[174]
  PIN rout[175]
    DIRECTION OUTPUT ;
    USE SIGNAL ;
    PORT
      LAYER M4 ;
        RECT  0 199.152 0.192 199.176 ;
    END
  END rout[175]
  PIN rout[176]
    DIRECTION OUTPUT ;
    USE SIGNAL ;
    PORT
      LAYER M4 ;
        RECT  0 199.056 0.192 199.08 ;
    END
  END rout[176]
  PIN rout[177]
    DIRECTION OUTPUT ;
    USE SIGNAL ;
    PORT
      LAYER M4 ;
        RECT  0 198.96 0.192 198.984 ;
    END
  END rout[177]
  PIN rout[178]
    DIRECTION OUTPUT ;
    USE SIGNAL ;
    PORT
      LAYER M4 ;
        RECT  0 198.864 0.192 198.888 ;
    END
  END rout[178]
  PIN rout[179]
    DIRECTION OUTPUT ;
    USE SIGNAL ;
    PORT
      LAYER M4 ;
        RECT  0 198.768 0.192 198.792 ;
    END
  END rout[179]
  PIN rout[17]
    DIRECTION OUTPUT ;
    USE SIGNAL ;
    PORT
      LAYER M4 ;
        RECT  0 214.32 0.192 214.344 ;
    END
  END rout[17]
  PIN rout[180]
    DIRECTION OUTPUT ;
    USE SIGNAL ;
    PORT
      LAYER M4 ;
        RECT  0 198.672 0.192 198.696 ;
    END
  END rout[180]
  PIN rout[181]
    DIRECTION OUTPUT ;
    USE SIGNAL ;
    PORT
      LAYER M4 ;
        RECT  0 198.576 0.192 198.6 ;
    END
  END rout[181]
  PIN rout[182]
    DIRECTION OUTPUT ;
    USE SIGNAL ;
    PORT
      LAYER M4 ;
        RECT  0 198.48 0.192 198.504 ;
    END
  END rout[182]
  PIN rout[183]
    DIRECTION OUTPUT ;
    USE SIGNAL ;
    PORT
      LAYER M4 ;
        RECT  0 198.384 0.192 198.408 ;
    END
  END rout[183]
  PIN rout[184]
    DIRECTION OUTPUT ;
    USE SIGNAL ;
    PORT
      LAYER M4 ;
        RECT  0 198.288 0.192 198.312 ;
    END
  END rout[184]
  PIN rout[185]
    DIRECTION OUTPUT ;
    USE SIGNAL ;
    PORT
      LAYER M4 ;
        RECT  0 198.192 0.192 198.216 ;
    END
  END rout[185]
  PIN rout[186]
    DIRECTION OUTPUT ;
    USE SIGNAL ;
    PORT
      LAYER M4 ;
        RECT  0 198.096 0.192 198.12 ;
    END
  END rout[186]
  PIN rout[187]
    DIRECTION OUTPUT ;
    USE SIGNAL ;
    PORT
      LAYER M4 ;
        RECT  0 198 0.192 198.024 ;
    END
  END rout[187]
  PIN rout[188]
    DIRECTION OUTPUT ;
    USE SIGNAL ;
    PORT
      LAYER M4 ;
        RECT  0 197.904 0.192 197.928 ;
    END
  END rout[188]
  PIN rout[189]
    DIRECTION OUTPUT ;
    USE SIGNAL ;
    PORT
      LAYER M4 ;
        RECT  0 197.808 0.192 197.832 ;
    END
  END rout[189]
  PIN rout[18]
    DIRECTION OUTPUT ;
    USE SIGNAL ;
    PORT
      LAYER M4 ;
        RECT  0 214.224 0.192 214.248 ;
    END
  END rout[18]
  PIN rout[190]
    DIRECTION OUTPUT ;
    USE SIGNAL ;
    PORT
      LAYER M4 ;
        RECT  0 197.712 0.192 197.736 ;
    END
  END rout[190]
  PIN rout[191]
    DIRECTION OUTPUT ;
    USE SIGNAL ;
    PORT
      LAYER M4 ;
        RECT  0 197.616 0.192 197.64 ;
    END
  END rout[191]
  PIN rout[192]
    DIRECTION OUTPUT ;
    USE SIGNAL ;
    PORT
      LAYER M4 ;
        RECT  0 197.52 0.192 197.544 ;
    END
  END rout[192]
  PIN rout[193]
    DIRECTION OUTPUT ;
    USE SIGNAL ;
    PORT
      LAYER M4 ;
        RECT  0 197.424 0.192 197.448 ;
    END
  END rout[193]
  PIN rout[194]
    DIRECTION OUTPUT ;
    USE SIGNAL ;
    PORT
      LAYER M4 ;
        RECT  0 197.328 0.192 197.352 ;
    END
  END rout[194]
  PIN rout[195]
    DIRECTION OUTPUT ;
    USE SIGNAL ;
    PORT
      LAYER M4 ;
        RECT  0 197.232 0.192 197.256 ;
    END
  END rout[195]
  PIN rout[196]
    DIRECTION OUTPUT ;
    USE SIGNAL ;
    PORT
      LAYER M4 ;
        RECT  0 197.136 0.192 197.16 ;
    END
  END rout[196]
  PIN rout[197]
    DIRECTION OUTPUT ;
    USE SIGNAL ;
    PORT
      LAYER M4 ;
        RECT  0 197.04 0.192 197.064 ;
    END
  END rout[197]
  PIN rout[198]
    DIRECTION OUTPUT ;
    USE SIGNAL ;
    PORT
      LAYER M4 ;
        RECT  0 196.944 0.192 196.968 ;
    END
  END rout[198]
  PIN rout[199]
    DIRECTION OUTPUT ;
    USE SIGNAL ;
    PORT
      LAYER M4 ;
        RECT  0 196.848 0.192 196.872 ;
    END
  END rout[199]
  PIN rout[19]
    DIRECTION OUTPUT ;
    USE SIGNAL ;
    PORT
      LAYER M4 ;
        RECT  0 214.128 0.192 214.152 ;
    END
  END rout[19]
  PIN rout[1]
    DIRECTION OUTPUT ;
    USE SIGNAL ;
    PORT
      LAYER M4 ;
        RECT  0 215.856 0.192 215.88 ;
    END
  END rout[1]
  PIN rout[200]
    DIRECTION OUTPUT ;
    USE SIGNAL ;
    PORT
      LAYER M4 ;
        RECT  0 196.752 0.192 196.776 ;
    END
  END rout[200]
  PIN rout[201]
    DIRECTION OUTPUT ;
    USE SIGNAL ;
    PORT
      LAYER M4 ;
        RECT  0 196.656 0.192 196.68 ;
    END
  END rout[201]
  PIN rout[202]
    DIRECTION OUTPUT ;
    USE SIGNAL ;
    PORT
      LAYER M4 ;
        RECT  0 196.56 0.192 196.584 ;
    END
  END rout[202]
  PIN rout[203]
    DIRECTION OUTPUT ;
    USE SIGNAL ;
    PORT
      LAYER M4 ;
        RECT  0 196.464 0.192 196.488 ;
    END
  END rout[203]
  PIN rout[204]
    DIRECTION OUTPUT ;
    USE SIGNAL ;
    PORT
      LAYER M4 ;
        RECT  0 196.368 0.192 196.392 ;
    END
  END rout[204]
  PIN rout[205]
    DIRECTION OUTPUT ;
    USE SIGNAL ;
    PORT
      LAYER M4 ;
        RECT  0 196.272 0.192 196.296 ;
    END
  END rout[205]
  PIN rout[206]
    DIRECTION OUTPUT ;
    USE SIGNAL ;
    PORT
      LAYER M4 ;
        RECT  0 196.176 0.192 196.2 ;
    END
  END rout[206]
  PIN rout[207]
    DIRECTION OUTPUT ;
    USE SIGNAL ;
    PORT
      LAYER M4 ;
        RECT  0 196.08 0.192 196.104 ;
    END
  END rout[207]
  PIN rout[208]
    DIRECTION OUTPUT ;
    USE SIGNAL ;
    PORT
      LAYER M4 ;
        RECT  0 195.984 0.192 196.008 ;
    END
  END rout[208]
  PIN rout[209]
    DIRECTION OUTPUT ;
    USE SIGNAL ;
    PORT
      LAYER M4 ;
        RECT  0 195.888 0.192 195.912 ;
    END
  END rout[209]
  PIN rout[20]
    DIRECTION OUTPUT ;
    USE SIGNAL ;
    PORT
      LAYER M4 ;
        RECT  0 214.032 0.192 214.056 ;
    END
  END rout[20]
  PIN rout[210]
    DIRECTION OUTPUT ;
    USE SIGNAL ;
    PORT
      LAYER M4 ;
        RECT  0 195.792 0.192 195.816 ;
    END
  END rout[210]
  PIN rout[211]
    DIRECTION OUTPUT ;
    USE SIGNAL ;
    PORT
      LAYER M4 ;
        RECT  0 195.696 0.192 195.72 ;
    END
  END rout[211]
  PIN rout[212]
    DIRECTION OUTPUT ;
    USE SIGNAL ;
    PORT
      LAYER M4 ;
        RECT  0 195.6 0.192 195.624 ;
    END
  END rout[212]
  PIN rout[213]
    DIRECTION OUTPUT ;
    USE SIGNAL ;
    PORT
      LAYER M4 ;
        RECT  0 195.504 0.192 195.528 ;
    END
  END rout[213]
  PIN rout[214]
    DIRECTION OUTPUT ;
    USE SIGNAL ;
    PORT
      LAYER M4 ;
        RECT  0 195.408 0.192 195.432 ;
    END
  END rout[214]
  PIN rout[215]
    DIRECTION OUTPUT ;
    USE SIGNAL ;
    PORT
      LAYER M4 ;
        RECT  0 195.312 0.192 195.336 ;
    END
  END rout[215]
  PIN rout[216]
    DIRECTION OUTPUT ;
    USE SIGNAL ;
    PORT
      LAYER M4 ;
        RECT  0 195.216 0.192 195.24 ;
    END
  END rout[216]
  PIN rout[217]
    DIRECTION OUTPUT ;
    USE SIGNAL ;
    PORT
      LAYER M4 ;
        RECT  0 195.12 0.192 195.144 ;
    END
  END rout[217]
  PIN rout[218]
    DIRECTION OUTPUT ;
    USE SIGNAL ;
    PORT
      LAYER M4 ;
        RECT  0 195.024 0.192 195.048 ;
    END
  END rout[218]
  PIN rout[219]
    DIRECTION OUTPUT ;
    USE SIGNAL ;
    PORT
      LAYER M4 ;
        RECT  0 194.928 0.192 194.952 ;
    END
  END rout[219]
  PIN rout[21]
    DIRECTION OUTPUT ;
    USE SIGNAL ;
    PORT
      LAYER M4 ;
        RECT  0 213.936 0.192 213.96 ;
    END
  END rout[21]
  PIN rout[220]
    DIRECTION OUTPUT ;
    USE SIGNAL ;
    PORT
      LAYER M4 ;
        RECT  0 194.832 0.192 194.856 ;
    END
  END rout[220]
  PIN rout[221]
    DIRECTION OUTPUT ;
    USE SIGNAL ;
    PORT
      LAYER M4 ;
        RECT  0 194.736 0.192 194.76 ;
    END
  END rout[221]
  PIN rout[222]
    DIRECTION OUTPUT ;
    USE SIGNAL ;
    PORT
      LAYER M4 ;
        RECT  0 194.64 0.192 194.664 ;
    END
  END rout[222]
  PIN rout[223]
    DIRECTION OUTPUT ;
    USE SIGNAL ;
    PORT
      LAYER M4 ;
        RECT  0 194.544 0.192 194.568 ;
    END
  END rout[223]
  PIN rout[224]
    DIRECTION OUTPUT ;
    USE SIGNAL ;
    PORT
      LAYER M4 ;
        RECT  0 194.448 0.192 194.472 ;
    END
  END rout[224]
  PIN rout[225]
    DIRECTION OUTPUT ;
    USE SIGNAL ;
    PORT
      LAYER M4 ;
        RECT  0 194.352 0.192 194.376 ;
    END
  END rout[225]
  PIN rout[226]
    DIRECTION OUTPUT ;
    USE SIGNAL ;
    PORT
      LAYER M4 ;
        RECT  0 194.256 0.192 194.28 ;
    END
  END rout[226]
  PIN rout[227]
    DIRECTION OUTPUT ;
    USE SIGNAL ;
    PORT
      LAYER M4 ;
        RECT  0 194.16 0.192 194.184 ;
    END
  END rout[227]
  PIN rout[228]
    DIRECTION OUTPUT ;
    USE SIGNAL ;
    PORT
      LAYER M4 ;
        RECT  0 194.064 0.192 194.088 ;
    END
  END rout[228]
  PIN rout[229]
    DIRECTION OUTPUT ;
    USE SIGNAL ;
    PORT
      LAYER M4 ;
        RECT  0 193.968 0.192 193.992 ;
    END
  END rout[229]
  PIN rout[22]
    DIRECTION OUTPUT ;
    USE SIGNAL ;
    PORT
      LAYER M4 ;
        RECT  0 213.84 0.192 213.864 ;
    END
  END rout[22]
  PIN rout[230]
    DIRECTION OUTPUT ;
    USE SIGNAL ;
    PORT
      LAYER M4 ;
        RECT  0 193.872 0.192 193.896 ;
    END
  END rout[230]
  PIN rout[231]
    DIRECTION OUTPUT ;
    USE SIGNAL ;
    PORT
      LAYER M4 ;
        RECT  0 193.776 0.192 193.8 ;
    END
  END rout[231]
  PIN rout[232]
    DIRECTION OUTPUT ;
    USE SIGNAL ;
    PORT
      LAYER M4 ;
        RECT  0 193.68 0.192 193.704 ;
    END
  END rout[232]
  PIN rout[233]
    DIRECTION OUTPUT ;
    USE SIGNAL ;
    PORT
      LAYER M4 ;
        RECT  0 193.584 0.192 193.608 ;
    END
  END rout[233]
  PIN rout[234]
    DIRECTION OUTPUT ;
    USE SIGNAL ;
    PORT
      LAYER M4 ;
        RECT  0 193.488 0.192 193.512 ;
    END
  END rout[234]
  PIN rout[235]
    DIRECTION OUTPUT ;
    USE SIGNAL ;
    PORT
      LAYER M4 ;
        RECT  0 193.392 0.192 193.416 ;
    END
  END rout[235]
  PIN rout[236]
    DIRECTION OUTPUT ;
    USE SIGNAL ;
    PORT
      LAYER M4 ;
        RECT  0 193.296 0.192 193.32 ;
    END
  END rout[236]
  PIN rout[237]
    DIRECTION OUTPUT ;
    USE SIGNAL ;
    PORT
      LAYER M4 ;
        RECT  0 193.2 0.192 193.224 ;
    END
  END rout[237]
  PIN rout[238]
    DIRECTION OUTPUT ;
    USE SIGNAL ;
    PORT
      LAYER M4 ;
        RECT  0 193.104 0.192 193.128 ;
    END
  END rout[238]
  PIN rout[239]
    DIRECTION OUTPUT ;
    USE SIGNAL ;
    PORT
      LAYER M4 ;
        RECT  0 193.008 0.192 193.032 ;
    END
  END rout[239]
  PIN rout[23]
    DIRECTION OUTPUT ;
    USE SIGNAL ;
    PORT
      LAYER M4 ;
        RECT  0 213.744 0.192 213.768 ;
    END
  END rout[23]
  PIN rout[240]
    DIRECTION OUTPUT ;
    USE SIGNAL ;
    PORT
      LAYER M4 ;
        RECT  0 192.912 0.192 192.936 ;
    END
  END rout[240]
  PIN rout[241]
    DIRECTION OUTPUT ;
    USE SIGNAL ;
    PORT
      LAYER M4 ;
        RECT  0 192.816 0.192 192.84 ;
    END
  END rout[241]
  PIN rout[242]
    DIRECTION OUTPUT ;
    USE SIGNAL ;
    PORT
      LAYER M4 ;
        RECT  0 192.72 0.192 192.744 ;
    END
  END rout[242]
  PIN rout[243]
    DIRECTION OUTPUT ;
    USE SIGNAL ;
    PORT
      LAYER M4 ;
        RECT  0 192.624 0.192 192.648 ;
    END
  END rout[243]
  PIN rout[244]
    DIRECTION OUTPUT ;
    USE SIGNAL ;
    PORT
      LAYER M4 ;
        RECT  0 192.528 0.192 192.552 ;
    END
  END rout[244]
  PIN rout[245]
    DIRECTION OUTPUT ;
    USE SIGNAL ;
    PORT
      LAYER M4 ;
        RECT  0 192.432 0.192 192.456 ;
    END
  END rout[245]
  PIN rout[246]
    DIRECTION OUTPUT ;
    USE SIGNAL ;
    PORT
      LAYER M4 ;
        RECT  0 192.336 0.192 192.36 ;
    END
  END rout[246]
  PIN rout[247]
    DIRECTION OUTPUT ;
    USE SIGNAL ;
    PORT
      LAYER M4 ;
        RECT  0 192.24 0.192 192.264 ;
    END
  END rout[247]
  PIN rout[248]
    DIRECTION OUTPUT ;
    USE SIGNAL ;
    PORT
      LAYER M4 ;
        RECT  0 192.144 0.192 192.168 ;
    END
  END rout[248]
  PIN rout[249]
    DIRECTION OUTPUT ;
    USE SIGNAL ;
    PORT
      LAYER M4 ;
        RECT  0 192.048 0.192 192.072 ;
    END
  END rout[249]
  PIN rout[24]
    DIRECTION OUTPUT ;
    USE SIGNAL ;
    PORT
      LAYER M4 ;
        RECT  0 213.648 0.192 213.672 ;
    END
  END rout[24]
  PIN rout[250]
    DIRECTION OUTPUT ;
    USE SIGNAL ;
    PORT
      LAYER M4 ;
        RECT  0 191.952 0.192 191.976 ;
    END
  END rout[250]
  PIN rout[251]
    DIRECTION OUTPUT ;
    USE SIGNAL ;
    PORT
      LAYER M4 ;
        RECT  0 191.856 0.192 191.88 ;
    END
  END rout[251]
  PIN rout[252]
    DIRECTION OUTPUT ;
    USE SIGNAL ;
    PORT
      LAYER M4 ;
        RECT  0 191.76 0.192 191.784 ;
    END
  END rout[252]
  PIN rout[253]
    DIRECTION OUTPUT ;
    USE SIGNAL ;
    PORT
      LAYER M4 ;
        RECT  0 191.664 0.192 191.688 ;
    END
  END rout[253]
  PIN rout[254]
    DIRECTION OUTPUT ;
    USE SIGNAL ;
    PORT
      LAYER M4 ;
        RECT  0 191.568 0.192 191.592 ;
    END
  END rout[254]
  PIN rout[255]
    DIRECTION OUTPUT ;
    USE SIGNAL ;
    PORT
      LAYER M4 ;
        RECT  0 191.472 0.192 191.496 ;
    END
  END rout[255]
  PIN rout[256]
    DIRECTION OUTPUT ;
    USE SIGNAL ;
    PORT
      LAYER M4 ;
        RECT  0 191.376 0.192 191.4 ;
    END
  END rout[256]
  PIN rout[257]
    DIRECTION OUTPUT ;
    USE SIGNAL ;
    PORT
      LAYER M4 ;
        RECT  0 191.28 0.192 191.304 ;
    END
  END rout[257]
  PIN rout[258]
    DIRECTION OUTPUT ;
    USE SIGNAL ;
    PORT
      LAYER M4 ;
        RECT  0 191.184 0.192 191.208 ;
    END
  END rout[258]
  PIN rout[259]
    DIRECTION OUTPUT ;
    USE SIGNAL ;
    PORT
      LAYER M4 ;
        RECT  0 191.088 0.192 191.112 ;
    END
  END rout[259]
  PIN rout[25]
    DIRECTION OUTPUT ;
    USE SIGNAL ;
    PORT
      LAYER M4 ;
        RECT  0 213.552 0.192 213.576 ;
    END
  END rout[25]
  PIN rout[260]
    DIRECTION OUTPUT ;
    USE SIGNAL ;
    PORT
      LAYER M4 ;
        RECT  0 190.992 0.192 191.016 ;
    END
  END rout[260]
  PIN rout[261]
    DIRECTION OUTPUT ;
    USE SIGNAL ;
    PORT
      LAYER M4 ;
        RECT  0 190.896 0.192 190.92 ;
    END
  END rout[261]
  PIN rout[262]
    DIRECTION OUTPUT ;
    USE SIGNAL ;
    PORT
      LAYER M4 ;
        RECT  0 190.8 0.192 190.824 ;
    END
  END rout[262]
  PIN rout[263]
    DIRECTION OUTPUT ;
    USE SIGNAL ;
    PORT
      LAYER M4 ;
        RECT  0 190.704 0.192 190.728 ;
    END
  END rout[263]
  PIN rout[264]
    DIRECTION OUTPUT ;
    USE SIGNAL ;
    PORT
      LAYER M4 ;
        RECT  0 190.608 0.192 190.632 ;
    END
  END rout[264]
  PIN rout[265]
    DIRECTION OUTPUT ;
    USE SIGNAL ;
    PORT
      LAYER M4 ;
        RECT  0 190.512 0.192 190.536 ;
    END
  END rout[265]
  PIN rout[266]
    DIRECTION OUTPUT ;
    USE SIGNAL ;
    PORT
      LAYER M4 ;
        RECT  0 190.416 0.192 190.44 ;
    END
  END rout[266]
  PIN rout[267]
    DIRECTION OUTPUT ;
    USE SIGNAL ;
    PORT
      LAYER M4 ;
        RECT  0 190.32 0.192 190.344 ;
    END
  END rout[267]
  PIN rout[268]
    DIRECTION OUTPUT ;
    USE SIGNAL ;
    PORT
      LAYER M4 ;
        RECT  0 190.224 0.192 190.248 ;
    END
  END rout[268]
  PIN rout[269]
    DIRECTION OUTPUT ;
    USE SIGNAL ;
    PORT
      LAYER M4 ;
        RECT  0 190.128 0.192 190.152 ;
    END
  END rout[269]
  PIN rout[26]
    DIRECTION OUTPUT ;
    USE SIGNAL ;
    PORT
      LAYER M4 ;
        RECT  0 213.456 0.192 213.48 ;
    END
  END rout[26]
  PIN rout[270]
    DIRECTION OUTPUT ;
    USE SIGNAL ;
    PORT
      LAYER M4 ;
        RECT  0 190.032 0.192 190.056 ;
    END
  END rout[270]
  PIN rout[271]
    DIRECTION OUTPUT ;
    USE SIGNAL ;
    PORT
      LAYER M4 ;
        RECT  0 189.936 0.192 189.96 ;
    END
  END rout[271]
  PIN rout[272]
    DIRECTION OUTPUT ;
    USE SIGNAL ;
    PORT
      LAYER M4 ;
        RECT  0 189.84 0.192 189.864 ;
    END
  END rout[272]
  PIN rout[273]
    DIRECTION OUTPUT ;
    USE SIGNAL ;
    PORT
      LAYER M4 ;
        RECT  0 189.744 0.192 189.768 ;
    END
  END rout[273]
  PIN rout[274]
    DIRECTION OUTPUT ;
    USE SIGNAL ;
    PORT
      LAYER M4 ;
        RECT  0 189.648 0.192 189.672 ;
    END
  END rout[274]
  PIN rout[275]
    DIRECTION OUTPUT ;
    USE SIGNAL ;
    PORT
      LAYER M4 ;
        RECT  0 189.552 0.192 189.576 ;
    END
  END rout[275]
  PIN rout[276]
    DIRECTION OUTPUT ;
    USE SIGNAL ;
    PORT
      LAYER M4 ;
        RECT  0 189.456 0.192 189.48 ;
    END
  END rout[276]
  PIN rout[277]
    DIRECTION OUTPUT ;
    USE SIGNAL ;
    PORT
      LAYER M4 ;
        RECT  0 189.36 0.192 189.384 ;
    END
  END rout[277]
  PIN rout[278]
    DIRECTION OUTPUT ;
    USE SIGNAL ;
    PORT
      LAYER M4 ;
        RECT  0 189.264 0.192 189.288 ;
    END
  END rout[278]
  PIN rout[279]
    DIRECTION OUTPUT ;
    USE SIGNAL ;
    PORT
      LAYER M4 ;
        RECT  0 189.168 0.192 189.192 ;
    END
  END rout[279]
  PIN rout[27]
    DIRECTION OUTPUT ;
    USE SIGNAL ;
    PORT
      LAYER M4 ;
        RECT  0 213.36 0.192 213.384 ;
    END
  END rout[27]
  PIN rout[280]
    DIRECTION OUTPUT ;
    USE SIGNAL ;
    PORT
      LAYER M4 ;
        RECT  0 189.072 0.192 189.096 ;
    END
  END rout[280]
  PIN rout[281]
    DIRECTION OUTPUT ;
    USE SIGNAL ;
    PORT
      LAYER M4 ;
        RECT  0 188.976 0.192 189 ;
    END
  END rout[281]
  PIN rout[282]
    DIRECTION OUTPUT ;
    USE SIGNAL ;
    PORT
      LAYER M4 ;
        RECT  0 188.88 0.192 188.904 ;
    END
  END rout[282]
  PIN rout[283]
    DIRECTION OUTPUT ;
    USE SIGNAL ;
    PORT
      LAYER M4 ;
        RECT  0 188.784 0.192 188.808 ;
    END
  END rout[283]
  PIN rout[284]
    DIRECTION OUTPUT ;
    USE SIGNAL ;
    PORT
      LAYER M4 ;
        RECT  0 188.688 0.192 188.712 ;
    END
  END rout[284]
  PIN rout[285]
    DIRECTION OUTPUT ;
    USE SIGNAL ;
    PORT
      LAYER M4 ;
        RECT  0 188.592 0.192 188.616 ;
    END
  END rout[285]
  PIN rout[286]
    DIRECTION OUTPUT ;
    USE SIGNAL ;
    PORT
      LAYER M4 ;
        RECT  0 188.496 0.192 188.52 ;
    END
  END rout[286]
  PIN rout[287]
    DIRECTION OUTPUT ;
    USE SIGNAL ;
    PORT
      LAYER M4 ;
        RECT  0 188.4 0.192 188.424 ;
    END
  END rout[287]
  PIN rout[288]
    DIRECTION OUTPUT ;
    USE SIGNAL ;
    PORT
      LAYER M4 ;
        RECT  0 188.304 0.192 188.328 ;
    END
  END rout[288]
  PIN rout[289]
    DIRECTION OUTPUT ;
    USE SIGNAL ;
    PORT
      LAYER M4 ;
        RECT  0 188.208 0.192 188.232 ;
    END
  END rout[289]
  PIN rout[28]
    DIRECTION OUTPUT ;
    USE SIGNAL ;
    PORT
      LAYER M4 ;
        RECT  0 213.264 0.192 213.288 ;
    END
  END rout[28]
  PIN rout[290]
    DIRECTION OUTPUT ;
    USE SIGNAL ;
    PORT
      LAYER M4 ;
        RECT  0 188.112 0.192 188.136 ;
    END
  END rout[290]
  PIN rout[291]
    DIRECTION OUTPUT ;
    USE SIGNAL ;
    PORT
      LAYER M4 ;
        RECT  0 188.016 0.192 188.04 ;
    END
  END rout[291]
  PIN rout[292]
    DIRECTION OUTPUT ;
    USE SIGNAL ;
    PORT
      LAYER M4 ;
        RECT  0 187.92 0.192 187.944 ;
    END
  END rout[292]
  PIN rout[293]
    DIRECTION OUTPUT ;
    USE SIGNAL ;
    PORT
      LAYER M4 ;
        RECT  0 187.824 0.192 187.848 ;
    END
  END rout[293]
  PIN rout[294]
    DIRECTION OUTPUT ;
    USE SIGNAL ;
    PORT
      LAYER M4 ;
        RECT  0 187.728 0.192 187.752 ;
    END
  END rout[294]
  PIN rout[295]
    DIRECTION OUTPUT ;
    USE SIGNAL ;
    PORT
      LAYER M4 ;
        RECT  0 187.632 0.192 187.656 ;
    END
  END rout[295]
  PIN rout[296]
    DIRECTION OUTPUT ;
    USE SIGNAL ;
    PORT
      LAYER M4 ;
        RECT  0 187.536 0.192 187.56 ;
    END
  END rout[296]
  PIN rout[297]
    DIRECTION OUTPUT ;
    USE SIGNAL ;
    PORT
      LAYER M4 ;
        RECT  0 187.44 0.192 187.464 ;
    END
  END rout[297]
  PIN rout[298]
    DIRECTION OUTPUT ;
    USE SIGNAL ;
    PORT
      LAYER M4 ;
        RECT  0 187.344 0.192 187.368 ;
    END
  END rout[298]
  PIN rout[299]
    DIRECTION OUTPUT ;
    USE SIGNAL ;
    PORT
      LAYER M4 ;
        RECT  0 187.248 0.192 187.272 ;
    END
  END rout[299]
  PIN rout[29]
    DIRECTION OUTPUT ;
    USE SIGNAL ;
    PORT
      LAYER M4 ;
        RECT  0 213.168 0.192 213.192 ;
    END
  END rout[29]
  PIN rout[2]
    DIRECTION OUTPUT ;
    USE SIGNAL ;
    PORT
      LAYER M4 ;
        RECT  0 215.76 0.192 215.784 ;
    END
  END rout[2]
  PIN rout[300]
    DIRECTION OUTPUT ;
    USE SIGNAL ;
    PORT
      LAYER M4 ;
        RECT  0 187.152 0.192 187.176 ;
    END
  END rout[300]
  PIN rout[301]
    DIRECTION OUTPUT ;
    USE SIGNAL ;
    PORT
      LAYER M4 ;
        RECT  0 187.056 0.192 187.08 ;
    END
  END rout[301]
  PIN rout[302]
    DIRECTION OUTPUT ;
    USE SIGNAL ;
    PORT
      LAYER M4 ;
        RECT  0 186.96 0.192 186.984 ;
    END
  END rout[302]
  PIN rout[303]
    DIRECTION OUTPUT ;
    USE SIGNAL ;
    PORT
      LAYER M4 ;
        RECT  0 186.864 0.192 186.888 ;
    END
  END rout[303]
  PIN rout[304]
    DIRECTION OUTPUT ;
    USE SIGNAL ;
    PORT
      LAYER M4 ;
        RECT  0 186.768 0.192 186.792 ;
    END
  END rout[304]
  PIN rout[305]
    DIRECTION OUTPUT ;
    USE SIGNAL ;
    PORT
      LAYER M4 ;
        RECT  0 186.672 0.192 186.696 ;
    END
  END rout[305]
  PIN rout[306]
    DIRECTION OUTPUT ;
    USE SIGNAL ;
    PORT
      LAYER M4 ;
        RECT  0 186.576 0.192 186.6 ;
    END
  END rout[306]
  PIN rout[307]
    DIRECTION OUTPUT ;
    USE SIGNAL ;
    PORT
      LAYER M4 ;
        RECT  0 186.48 0.192 186.504 ;
    END
  END rout[307]
  PIN rout[308]
    DIRECTION OUTPUT ;
    USE SIGNAL ;
    PORT
      LAYER M4 ;
        RECT  0 186.384 0.192 186.408 ;
    END
  END rout[308]
  PIN rout[309]
    DIRECTION OUTPUT ;
    USE SIGNAL ;
    PORT
      LAYER M4 ;
        RECT  0 186.288 0.192 186.312 ;
    END
  END rout[309]
  PIN rout[30]
    DIRECTION OUTPUT ;
    USE SIGNAL ;
    PORT
      LAYER M4 ;
        RECT  0 213.072 0.192 213.096 ;
    END
  END rout[30]
  PIN rout[310]
    DIRECTION OUTPUT ;
    USE SIGNAL ;
    PORT
      LAYER M4 ;
        RECT  0 186.192 0.192 186.216 ;
    END
  END rout[310]
  PIN rout[311]
    DIRECTION OUTPUT ;
    USE SIGNAL ;
    PORT
      LAYER M4 ;
        RECT  0 186.096 0.192 186.12 ;
    END
  END rout[311]
  PIN rout[312]
    DIRECTION OUTPUT ;
    USE SIGNAL ;
    PORT
      LAYER M4 ;
        RECT  0 186 0.192 186.024 ;
    END
  END rout[312]
  PIN rout[313]
    DIRECTION OUTPUT ;
    USE SIGNAL ;
    PORT
      LAYER M4 ;
        RECT  0 185.904 0.192 185.928 ;
    END
  END rout[313]
  PIN rout[314]
    DIRECTION OUTPUT ;
    USE SIGNAL ;
    PORT
      LAYER M4 ;
        RECT  0 185.808 0.192 185.832 ;
    END
  END rout[314]
  PIN rout[315]
    DIRECTION OUTPUT ;
    USE SIGNAL ;
    PORT
      LAYER M4 ;
        RECT  0 185.712 0.192 185.736 ;
    END
  END rout[315]
  PIN rout[316]
    DIRECTION OUTPUT ;
    USE SIGNAL ;
    PORT
      LAYER M4 ;
        RECT  0 185.616 0.192 185.64 ;
    END
  END rout[316]
  PIN rout[317]
    DIRECTION OUTPUT ;
    USE SIGNAL ;
    PORT
      LAYER M4 ;
        RECT  0 185.52 0.192 185.544 ;
    END
  END rout[317]
  PIN rout[318]
    DIRECTION OUTPUT ;
    USE SIGNAL ;
    PORT
      LAYER M4 ;
        RECT  0 185.424 0.192 185.448 ;
    END
  END rout[318]
  PIN rout[319]
    DIRECTION OUTPUT ;
    USE SIGNAL ;
    PORT
      LAYER M4 ;
        RECT  0 185.328 0.192 185.352 ;
    END
  END rout[319]
  PIN rout[31]
    DIRECTION OUTPUT ;
    USE SIGNAL ;
    PORT
      LAYER M4 ;
        RECT  0 212.976 0.192 213 ;
    END
  END rout[31]
  PIN rout[320]
    DIRECTION OUTPUT ;
    USE SIGNAL ;
    PORT
      LAYER M4 ;
        RECT  0 185.232 0.192 185.256 ;
    END
  END rout[320]
  PIN rout[321]
    DIRECTION OUTPUT ;
    USE SIGNAL ;
    PORT
      LAYER M4 ;
        RECT  0 185.136 0.192 185.16 ;
    END
  END rout[321]
  PIN rout[322]
    DIRECTION OUTPUT ;
    USE SIGNAL ;
    PORT
      LAYER M4 ;
        RECT  0 185.04 0.192 185.064 ;
    END
  END rout[322]
  PIN rout[323]
    DIRECTION OUTPUT ;
    USE SIGNAL ;
    PORT
      LAYER M4 ;
        RECT  0 184.944 0.192 184.968 ;
    END
  END rout[323]
  PIN rout[324]
    DIRECTION OUTPUT ;
    USE SIGNAL ;
    PORT
      LAYER M4 ;
        RECT  0 184.848 0.192 184.872 ;
    END
  END rout[324]
  PIN rout[325]
    DIRECTION OUTPUT ;
    USE SIGNAL ;
    PORT
      LAYER M4 ;
        RECT  0 184.752 0.192 184.776 ;
    END
  END rout[325]
  PIN rout[326]
    DIRECTION OUTPUT ;
    USE SIGNAL ;
    PORT
      LAYER M4 ;
        RECT  0 184.656 0.192 184.68 ;
    END
  END rout[326]
  PIN rout[327]
    DIRECTION OUTPUT ;
    USE SIGNAL ;
    PORT
      LAYER M4 ;
        RECT  0 184.56 0.192 184.584 ;
    END
  END rout[327]
  PIN rout[328]
    DIRECTION OUTPUT ;
    USE SIGNAL ;
    PORT
      LAYER M4 ;
        RECT  0 184.464 0.192 184.488 ;
    END
  END rout[328]
  PIN rout[329]
    DIRECTION OUTPUT ;
    USE SIGNAL ;
    PORT
      LAYER M4 ;
        RECT  0 184.368 0.192 184.392 ;
    END
  END rout[329]
  PIN rout[32]
    DIRECTION OUTPUT ;
    USE SIGNAL ;
    PORT
      LAYER M4 ;
        RECT  0 212.88 0.192 212.904 ;
    END
  END rout[32]
  PIN rout[330]
    DIRECTION OUTPUT ;
    USE SIGNAL ;
    PORT
      LAYER M4 ;
        RECT  0 184.272 0.192 184.296 ;
    END
  END rout[330]
  PIN rout[331]
    DIRECTION OUTPUT ;
    USE SIGNAL ;
    PORT
      LAYER M4 ;
        RECT  0 184.176 0.192 184.2 ;
    END
  END rout[331]
  PIN rout[332]
    DIRECTION OUTPUT ;
    USE SIGNAL ;
    PORT
      LAYER M4 ;
        RECT  0 184.08 0.192 184.104 ;
    END
  END rout[332]
  PIN rout[333]
    DIRECTION OUTPUT ;
    USE SIGNAL ;
    PORT
      LAYER M4 ;
        RECT  0 183.984 0.192 184.008 ;
    END
  END rout[333]
  PIN rout[334]
    DIRECTION OUTPUT ;
    USE SIGNAL ;
    PORT
      LAYER M4 ;
        RECT  0 183.888 0.192 183.912 ;
    END
  END rout[334]
  PIN rout[335]
    DIRECTION OUTPUT ;
    USE SIGNAL ;
    PORT
      LAYER M4 ;
        RECT  0 183.792 0.192 183.816 ;
    END
  END rout[335]
  PIN rout[336]
    DIRECTION OUTPUT ;
    USE SIGNAL ;
    PORT
      LAYER M4 ;
        RECT  0 183.696 0.192 183.72 ;
    END
  END rout[336]
  PIN rout[337]
    DIRECTION OUTPUT ;
    USE SIGNAL ;
    PORT
      LAYER M4 ;
        RECT  0 183.6 0.192 183.624 ;
    END
  END rout[337]
  PIN rout[338]
    DIRECTION OUTPUT ;
    USE SIGNAL ;
    PORT
      LAYER M4 ;
        RECT  0 183.504 0.192 183.528 ;
    END
  END rout[338]
  PIN rout[339]
    DIRECTION OUTPUT ;
    USE SIGNAL ;
    PORT
      LAYER M4 ;
        RECT  0 183.408 0.192 183.432 ;
    END
  END rout[339]
  PIN rout[33]
    DIRECTION OUTPUT ;
    USE SIGNAL ;
    PORT
      LAYER M4 ;
        RECT  0 212.784 0.192 212.808 ;
    END
  END rout[33]
  PIN rout[340]
    DIRECTION OUTPUT ;
    USE SIGNAL ;
    PORT
      LAYER M4 ;
        RECT  0 183.312 0.192 183.336 ;
    END
  END rout[340]
  PIN rout[341]
    DIRECTION OUTPUT ;
    USE SIGNAL ;
    PORT
      LAYER M4 ;
        RECT  0 183.216 0.192 183.24 ;
    END
  END rout[341]
  PIN rout[342]
    DIRECTION OUTPUT ;
    USE SIGNAL ;
    PORT
      LAYER M4 ;
        RECT  0 183.12 0.192 183.144 ;
    END
  END rout[342]
  PIN rout[343]
    DIRECTION OUTPUT ;
    USE SIGNAL ;
    PORT
      LAYER M4 ;
        RECT  0 183.024 0.192 183.048 ;
    END
  END rout[343]
  PIN rout[344]
    DIRECTION OUTPUT ;
    USE SIGNAL ;
    PORT
      LAYER M4 ;
        RECT  0 182.928 0.192 182.952 ;
    END
  END rout[344]
  PIN rout[345]
    DIRECTION OUTPUT ;
    USE SIGNAL ;
    PORT
      LAYER M4 ;
        RECT  0 182.832 0.192 182.856 ;
    END
  END rout[345]
  PIN rout[346]
    DIRECTION OUTPUT ;
    USE SIGNAL ;
    PORT
      LAYER M4 ;
        RECT  0 182.736 0.192 182.76 ;
    END
  END rout[346]
  PIN rout[347]
    DIRECTION OUTPUT ;
    USE SIGNAL ;
    PORT
      LAYER M4 ;
        RECT  0 182.64 0.192 182.664 ;
    END
  END rout[347]
  PIN rout[348]
    DIRECTION OUTPUT ;
    USE SIGNAL ;
    PORT
      LAYER M4 ;
        RECT  0 182.544 0.192 182.568 ;
    END
  END rout[348]
  PIN rout[349]
    DIRECTION OUTPUT ;
    USE SIGNAL ;
    PORT
      LAYER M4 ;
        RECT  0 182.448 0.192 182.472 ;
    END
  END rout[349]
  PIN rout[34]
    DIRECTION OUTPUT ;
    USE SIGNAL ;
    PORT
      LAYER M4 ;
        RECT  0 212.688 0.192 212.712 ;
    END
  END rout[34]
  PIN rout[350]
    DIRECTION OUTPUT ;
    USE SIGNAL ;
    PORT
      LAYER M4 ;
        RECT  0 182.352 0.192 182.376 ;
    END
  END rout[350]
  PIN rout[351]
    DIRECTION OUTPUT ;
    USE SIGNAL ;
    PORT
      LAYER M4 ;
        RECT  0 182.256 0.192 182.28 ;
    END
  END rout[351]
  PIN rout[352]
    DIRECTION OUTPUT ;
    USE SIGNAL ;
    PORT
      LAYER M4 ;
        RECT  0 182.16 0.192 182.184 ;
    END
  END rout[352]
  PIN rout[353]
    DIRECTION OUTPUT ;
    USE SIGNAL ;
    PORT
      LAYER M4 ;
        RECT  0 182.064 0.192 182.088 ;
    END
  END rout[353]
  PIN rout[354]
    DIRECTION OUTPUT ;
    USE SIGNAL ;
    PORT
      LAYER M4 ;
        RECT  0 181.968 0.192 181.992 ;
    END
  END rout[354]
  PIN rout[355]
    DIRECTION OUTPUT ;
    USE SIGNAL ;
    PORT
      LAYER M4 ;
        RECT  0 181.872 0.192 181.896 ;
    END
  END rout[355]
  PIN rout[356]
    DIRECTION OUTPUT ;
    USE SIGNAL ;
    PORT
      LAYER M4 ;
        RECT  0 181.776 0.192 181.8 ;
    END
  END rout[356]
  PIN rout[357]
    DIRECTION OUTPUT ;
    USE SIGNAL ;
    PORT
      LAYER M4 ;
        RECT  0 181.68 0.192 181.704 ;
    END
  END rout[357]
  PIN rout[358]
    DIRECTION OUTPUT ;
    USE SIGNAL ;
    PORT
      LAYER M4 ;
        RECT  0 181.584 0.192 181.608 ;
    END
  END rout[358]
  PIN rout[359]
    DIRECTION OUTPUT ;
    USE SIGNAL ;
    PORT
      LAYER M4 ;
        RECT  0 181.488 0.192 181.512 ;
    END
  END rout[359]
  PIN rout[35]
    DIRECTION OUTPUT ;
    USE SIGNAL ;
    PORT
      LAYER M4 ;
        RECT  0 212.592 0.192 212.616 ;
    END
  END rout[35]
  PIN rout[360]
    DIRECTION OUTPUT ;
    USE SIGNAL ;
    PORT
      LAYER M4 ;
        RECT  0 181.392 0.192 181.416 ;
    END
  END rout[360]
  PIN rout[361]
    DIRECTION OUTPUT ;
    USE SIGNAL ;
    PORT
      LAYER M4 ;
        RECT  0 181.296 0.192 181.32 ;
    END
  END rout[361]
  PIN rout[362]
    DIRECTION OUTPUT ;
    USE SIGNAL ;
    PORT
      LAYER M4 ;
        RECT  0 181.2 0.192 181.224 ;
    END
  END rout[362]
  PIN rout[363]
    DIRECTION OUTPUT ;
    USE SIGNAL ;
    PORT
      LAYER M4 ;
        RECT  0 181.104 0.192 181.128 ;
    END
  END rout[363]
  PIN rout[364]
    DIRECTION OUTPUT ;
    USE SIGNAL ;
    PORT
      LAYER M4 ;
        RECT  0 181.008 0.192 181.032 ;
    END
  END rout[364]
  PIN rout[365]
    DIRECTION OUTPUT ;
    USE SIGNAL ;
    PORT
      LAYER M4 ;
        RECT  0 180.912 0.192 180.936 ;
    END
  END rout[365]
  PIN rout[366]
    DIRECTION OUTPUT ;
    USE SIGNAL ;
    PORT
      LAYER M4 ;
        RECT  0 180.816 0.192 180.84 ;
    END
  END rout[366]
  PIN rout[367]
    DIRECTION OUTPUT ;
    USE SIGNAL ;
    PORT
      LAYER M4 ;
        RECT  0 180.72 0.192 180.744 ;
    END
  END rout[367]
  PIN rout[368]
    DIRECTION OUTPUT ;
    USE SIGNAL ;
    PORT
      LAYER M4 ;
        RECT  0 180.624 0.192 180.648 ;
    END
  END rout[368]
  PIN rout[369]
    DIRECTION OUTPUT ;
    USE SIGNAL ;
    PORT
      LAYER M4 ;
        RECT  0 180.528 0.192 180.552 ;
    END
  END rout[369]
  PIN rout[36]
    DIRECTION OUTPUT ;
    USE SIGNAL ;
    PORT
      LAYER M4 ;
        RECT  0 212.496 0.192 212.52 ;
    END
  END rout[36]
  PIN rout[370]
    DIRECTION OUTPUT ;
    USE SIGNAL ;
    PORT
      LAYER M4 ;
        RECT  0 180.432 0.192 180.456 ;
    END
  END rout[370]
  PIN rout[371]
    DIRECTION OUTPUT ;
    USE SIGNAL ;
    PORT
      LAYER M4 ;
        RECT  0 180.336 0.192 180.36 ;
    END
  END rout[371]
  PIN rout[372]
    DIRECTION OUTPUT ;
    USE SIGNAL ;
    PORT
      LAYER M4 ;
        RECT  0 180.24 0.192 180.264 ;
    END
  END rout[372]
  PIN rout[373]
    DIRECTION OUTPUT ;
    USE SIGNAL ;
    PORT
      LAYER M4 ;
        RECT  0 180.144 0.192 180.168 ;
    END
  END rout[373]
  PIN rout[374]
    DIRECTION OUTPUT ;
    USE SIGNAL ;
    PORT
      LAYER M4 ;
        RECT  0 180.048 0.192 180.072 ;
    END
  END rout[374]
  PIN rout[375]
    DIRECTION OUTPUT ;
    USE SIGNAL ;
    PORT
      LAYER M4 ;
        RECT  0 179.952 0.192 179.976 ;
    END
  END rout[375]
  PIN rout[376]
    DIRECTION OUTPUT ;
    USE SIGNAL ;
    PORT
      LAYER M4 ;
        RECT  0 179.856 0.192 179.88 ;
    END
  END rout[376]
  PIN rout[377]
    DIRECTION OUTPUT ;
    USE SIGNAL ;
    PORT
      LAYER M4 ;
        RECT  0 179.76 0.192 179.784 ;
    END
  END rout[377]
  PIN rout[378]
    DIRECTION OUTPUT ;
    USE SIGNAL ;
    PORT
      LAYER M4 ;
        RECT  0 179.664 0.192 179.688 ;
    END
  END rout[378]
  PIN rout[379]
    DIRECTION OUTPUT ;
    USE SIGNAL ;
    PORT
      LAYER M4 ;
        RECT  0 179.568 0.192 179.592 ;
    END
  END rout[379]
  PIN rout[37]
    DIRECTION OUTPUT ;
    USE SIGNAL ;
    PORT
      LAYER M4 ;
        RECT  0 212.4 0.192 212.424 ;
    END
  END rout[37]
  PIN rout[380]
    DIRECTION OUTPUT ;
    USE SIGNAL ;
    PORT
      LAYER M4 ;
        RECT  0 179.472 0.192 179.496 ;
    END
  END rout[380]
  PIN rout[381]
    DIRECTION OUTPUT ;
    USE SIGNAL ;
    PORT
      LAYER M4 ;
        RECT  0 179.376 0.192 179.4 ;
    END
  END rout[381]
  PIN rout[382]
    DIRECTION OUTPUT ;
    USE SIGNAL ;
    PORT
      LAYER M4 ;
        RECT  0 179.28 0.192 179.304 ;
    END
  END rout[382]
  PIN rout[383]
    DIRECTION OUTPUT ;
    USE SIGNAL ;
    PORT
      LAYER M4 ;
        RECT  0 179.184 0.192 179.208 ;
    END
  END rout[383]
  PIN rout[384]
    DIRECTION OUTPUT ;
    USE SIGNAL ;
    PORT
      LAYER M4 ;
        RECT  0 179.088 0.192 179.112 ;
    END
  END rout[384]
  PIN rout[385]
    DIRECTION OUTPUT ;
    USE SIGNAL ;
    PORT
      LAYER M4 ;
        RECT  0 178.992 0.192 179.016 ;
    END
  END rout[385]
  PIN rout[386]
    DIRECTION OUTPUT ;
    USE SIGNAL ;
    PORT
      LAYER M4 ;
        RECT  0 178.896 0.192 178.92 ;
    END
  END rout[386]
  PIN rout[387]
    DIRECTION OUTPUT ;
    USE SIGNAL ;
    PORT
      LAYER M4 ;
        RECT  0 178.8 0.192 178.824 ;
    END
  END rout[387]
  PIN rout[388]
    DIRECTION OUTPUT ;
    USE SIGNAL ;
    PORT
      LAYER M4 ;
        RECT  0 178.704 0.192 178.728 ;
    END
  END rout[388]
  PIN rout[389]
    DIRECTION OUTPUT ;
    USE SIGNAL ;
    PORT
      LAYER M4 ;
        RECT  0 178.608 0.192 178.632 ;
    END
  END rout[389]
  PIN rout[38]
    DIRECTION OUTPUT ;
    USE SIGNAL ;
    PORT
      LAYER M4 ;
        RECT  0 212.304 0.192 212.328 ;
    END
  END rout[38]
  PIN rout[390]
    DIRECTION OUTPUT ;
    USE SIGNAL ;
    PORT
      LAYER M4 ;
        RECT  0 178.512 0.192 178.536 ;
    END
  END rout[390]
  PIN rout[391]
    DIRECTION OUTPUT ;
    USE SIGNAL ;
    PORT
      LAYER M4 ;
        RECT  0 178.416 0.192 178.44 ;
    END
  END rout[391]
  PIN rout[392]
    DIRECTION OUTPUT ;
    USE SIGNAL ;
    PORT
      LAYER M4 ;
        RECT  0 178.32 0.192 178.344 ;
    END
  END rout[392]
  PIN rout[393]
    DIRECTION OUTPUT ;
    USE SIGNAL ;
    PORT
      LAYER M4 ;
        RECT  0 178.224 0.192 178.248 ;
    END
  END rout[393]
  PIN rout[394]
    DIRECTION OUTPUT ;
    USE SIGNAL ;
    PORT
      LAYER M4 ;
        RECT  0 178.128 0.192 178.152 ;
    END
  END rout[394]
  PIN rout[395]
    DIRECTION OUTPUT ;
    USE SIGNAL ;
    PORT
      LAYER M4 ;
        RECT  0 178.032 0.192 178.056 ;
    END
  END rout[395]
  PIN rout[396]
    DIRECTION OUTPUT ;
    USE SIGNAL ;
    PORT
      LAYER M4 ;
        RECT  0 177.936 0.192 177.96 ;
    END
  END rout[396]
  PIN rout[397]
    DIRECTION OUTPUT ;
    USE SIGNAL ;
    PORT
      LAYER M4 ;
        RECT  0 177.84 0.192 177.864 ;
    END
  END rout[397]
  PIN rout[398]
    DIRECTION OUTPUT ;
    USE SIGNAL ;
    PORT
      LAYER M4 ;
        RECT  0 177.744 0.192 177.768 ;
    END
  END rout[398]
  PIN rout[399]
    DIRECTION OUTPUT ;
    USE SIGNAL ;
    PORT
      LAYER M4 ;
        RECT  0 177.648 0.192 177.672 ;
    END
  END rout[399]
  PIN rout[39]
    DIRECTION OUTPUT ;
    USE SIGNAL ;
    PORT
      LAYER M4 ;
        RECT  0 212.208 0.192 212.232 ;
    END
  END rout[39]
  PIN rout[3]
    DIRECTION OUTPUT ;
    USE SIGNAL ;
    PORT
      LAYER M4 ;
        RECT  0 215.664 0.192 215.688 ;
    END
  END rout[3]
  PIN rout[400]
    DIRECTION OUTPUT ;
    USE SIGNAL ;
    PORT
      LAYER M4 ;
        RECT  0 177.552 0.192 177.576 ;
    END
  END rout[400]
  PIN rout[401]
    DIRECTION OUTPUT ;
    USE SIGNAL ;
    PORT
      LAYER M4 ;
        RECT  0 177.456 0.192 177.48 ;
    END
  END rout[401]
  PIN rout[402]
    DIRECTION OUTPUT ;
    USE SIGNAL ;
    PORT
      LAYER M4 ;
        RECT  0 177.36 0.192 177.384 ;
    END
  END rout[402]
  PIN rout[403]
    DIRECTION OUTPUT ;
    USE SIGNAL ;
    PORT
      LAYER M4 ;
        RECT  0 177.264 0.192 177.288 ;
    END
  END rout[403]
  PIN rout[404]
    DIRECTION OUTPUT ;
    USE SIGNAL ;
    PORT
      LAYER M4 ;
        RECT  0 177.168 0.192 177.192 ;
    END
  END rout[404]
  PIN rout[405]
    DIRECTION OUTPUT ;
    USE SIGNAL ;
    PORT
      LAYER M4 ;
        RECT  0 177.072 0.192 177.096 ;
    END
  END rout[405]
  PIN rout[406]
    DIRECTION OUTPUT ;
    USE SIGNAL ;
    PORT
      LAYER M4 ;
        RECT  0 176.976 0.192 177 ;
    END
  END rout[406]
  PIN rout[407]
    DIRECTION OUTPUT ;
    USE SIGNAL ;
    PORT
      LAYER M4 ;
        RECT  0 176.88 0.192 176.904 ;
    END
  END rout[407]
  PIN rout[408]
    DIRECTION OUTPUT ;
    USE SIGNAL ;
    PORT
      LAYER M4 ;
        RECT  0 176.784 0.192 176.808 ;
    END
  END rout[408]
  PIN rout[409]
    DIRECTION OUTPUT ;
    USE SIGNAL ;
    PORT
      LAYER M4 ;
        RECT  0 176.688 0.192 176.712 ;
    END
  END rout[409]
  PIN rout[40]
    DIRECTION OUTPUT ;
    USE SIGNAL ;
    PORT
      LAYER M4 ;
        RECT  0 212.112 0.192 212.136 ;
    END
  END rout[40]
  PIN rout[410]
    DIRECTION OUTPUT ;
    USE SIGNAL ;
    PORT
      LAYER M4 ;
        RECT  0 176.592 0.192 176.616 ;
    END
  END rout[410]
  PIN rout[411]
    DIRECTION OUTPUT ;
    USE SIGNAL ;
    PORT
      LAYER M4 ;
        RECT  0 176.496 0.192 176.52 ;
    END
  END rout[411]
  PIN rout[412]
    DIRECTION OUTPUT ;
    USE SIGNAL ;
    PORT
      LAYER M4 ;
        RECT  0 176.4 0.192 176.424 ;
    END
  END rout[412]
  PIN rout[413]
    DIRECTION OUTPUT ;
    USE SIGNAL ;
    PORT
      LAYER M4 ;
        RECT  0 176.304 0.192 176.328 ;
    END
  END rout[413]
  PIN rout[414]
    DIRECTION OUTPUT ;
    USE SIGNAL ;
    PORT
      LAYER M4 ;
        RECT  0 176.208 0.192 176.232 ;
    END
  END rout[414]
  PIN rout[415]
    DIRECTION OUTPUT ;
    USE SIGNAL ;
    PORT
      LAYER M4 ;
        RECT  0 176.112 0.192 176.136 ;
    END
  END rout[415]
  PIN rout[416]
    DIRECTION OUTPUT ;
    USE SIGNAL ;
    PORT
      LAYER M4 ;
        RECT  0 176.016 0.192 176.04 ;
    END
  END rout[416]
  PIN rout[417]
    DIRECTION OUTPUT ;
    USE SIGNAL ;
    PORT
      LAYER M4 ;
        RECT  0 175.92 0.192 175.944 ;
    END
  END rout[417]
  PIN rout[418]
    DIRECTION OUTPUT ;
    USE SIGNAL ;
    PORT
      LAYER M4 ;
        RECT  0 175.824 0.192 175.848 ;
    END
  END rout[418]
  PIN rout[419]
    DIRECTION OUTPUT ;
    USE SIGNAL ;
    PORT
      LAYER M4 ;
        RECT  0 175.728 0.192 175.752 ;
    END
  END rout[419]
  PIN rout[41]
    DIRECTION OUTPUT ;
    USE SIGNAL ;
    PORT
      LAYER M4 ;
        RECT  0 212.016 0.192 212.04 ;
    END
  END rout[41]
  PIN rout[420]
    DIRECTION OUTPUT ;
    USE SIGNAL ;
    PORT
      LAYER M4 ;
        RECT  0 175.632 0.192 175.656 ;
    END
  END rout[420]
  PIN rout[421]
    DIRECTION OUTPUT ;
    USE SIGNAL ;
    PORT
      LAYER M4 ;
        RECT  0 175.536 0.192 175.56 ;
    END
  END rout[421]
  PIN rout[422]
    DIRECTION OUTPUT ;
    USE SIGNAL ;
    PORT
      LAYER M4 ;
        RECT  0 175.44 0.192 175.464 ;
    END
  END rout[422]
  PIN rout[423]
    DIRECTION OUTPUT ;
    USE SIGNAL ;
    PORT
      LAYER M4 ;
        RECT  0 175.344 0.192 175.368 ;
    END
  END rout[423]
  PIN rout[424]
    DIRECTION OUTPUT ;
    USE SIGNAL ;
    PORT
      LAYER M4 ;
        RECT  0 175.248 0.192 175.272 ;
    END
  END rout[424]
  PIN rout[425]
    DIRECTION OUTPUT ;
    USE SIGNAL ;
    PORT
      LAYER M4 ;
        RECT  0 175.152 0.192 175.176 ;
    END
  END rout[425]
  PIN rout[426]
    DIRECTION OUTPUT ;
    USE SIGNAL ;
    PORT
      LAYER M4 ;
        RECT  0 175.056 0.192 175.08 ;
    END
  END rout[426]
  PIN rout[427]
    DIRECTION OUTPUT ;
    USE SIGNAL ;
    PORT
      LAYER M4 ;
        RECT  0 174.96 0.192 174.984 ;
    END
  END rout[427]
  PIN rout[428]
    DIRECTION OUTPUT ;
    USE SIGNAL ;
    PORT
      LAYER M4 ;
        RECT  0 174.864 0.192 174.888 ;
    END
  END rout[428]
  PIN rout[429]
    DIRECTION OUTPUT ;
    USE SIGNAL ;
    PORT
      LAYER M4 ;
        RECT  0 174.768 0.192 174.792 ;
    END
  END rout[429]
  PIN rout[42]
    DIRECTION OUTPUT ;
    USE SIGNAL ;
    PORT
      LAYER M4 ;
        RECT  0 211.92 0.192 211.944 ;
    END
  END rout[42]
  PIN rout[430]
    DIRECTION OUTPUT ;
    USE SIGNAL ;
    PORT
      LAYER M4 ;
        RECT  0 174.672 0.192 174.696 ;
    END
  END rout[430]
  PIN rout[431]
    DIRECTION OUTPUT ;
    USE SIGNAL ;
    PORT
      LAYER M4 ;
        RECT  0 174.576 0.192 174.6 ;
    END
  END rout[431]
  PIN rout[432]
    DIRECTION OUTPUT ;
    USE SIGNAL ;
    PORT
      LAYER M4 ;
        RECT  0 174.48 0.192 174.504 ;
    END
  END rout[432]
  PIN rout[433]
    DIRECTION OUTPUT ;
    USE SIGNAL ;
    PORT
      LAYER M4 ;
        RECT  0 174.384 0.192 174.408 ;
    END
  END rout[433]
  PIN rout[434]
    DIRECTION OUTPUT ;
    USE SIGNAL ;
    PORT
      LAYER M4 ;
        RECT  0 174.288 0.192 174.312 ;
    END
  END rout[434]
  PIN rout[435]
    DIRECTION OUTPUT ;
    USE SIGNAL ;
    PORT
      LAYER M4 ;
        RECT  0 174.192 0.192 174.216 ;
    END
  END rout[435]
  PIN rout[436]
    DIRECTION OUTPUT ;
    USE SIGNAL ;
    PORT
      LAYER M4 ;
        RECT  0 174.096 0.192 174.12 ;
    END
  END rout[436]
  PIN rout[437]
    DIRECTION OUTPUT ;
    USE SIGNAL ;
    PORT
      LAYER M4 ;
        RECT  0 174 0.192 174.024 ;
    END
  END rout[437]
  PIN rout[438]
    DIRECTION OUTPUT ;
    USE SIGNAL ;
    PORT
      LAYER M4 ;
        RECT  0 173.904 0.192 173.928 ;
    END
  END rout[438]
  PIN rout[439]
    DIRECTION OUTPUT ;
    USE SIGNAL ;
    PORT
      LAYER M4 ;
        RECT  0 173.808 0.192 173.832 ;
    END
  END rout[439]
  PIN rout[43]
    DIRECTION OUTPUT ;
    USE SIGNAL ;
    PORT
      LAYER M4 ;
        RECT  0 211.824 0.192 211.848 ;
    END
  END rout[43]
  PIN rout[440]
    DIRECTION OUTPUT ;
    USE SIGNAL ;
    PORT
      LAYER M4 ;
        RECT  0 173.712 0.192 173.736 ;
    END
  END rout[440]
  PIN rout[441]
    DIRECTION OUTPUT ;
    USE SIGNAL ;
    PORT
      LAYER M4 ;
        RECT  0 173.616 0.192 173.64 ;
    END
  END rout[441]
  PIN rout[442]
    DIRECTION OUTPUT ;
    USE SIGNAL ;
    PORT
      LAYER M4 ;
        RECT  0 173.52 0.192 173.544 ;
    END
  END rout[442]
  PIN rout[443]
    DIRECTION OUTPUT ;
    USE SIGNAL ;
    PORT
      LAYER M4 ;
        RECT  0 173.424 0.192 173.448 ;
    END
  END rout[443]
  PIN rout[444]
    DIRECTION OUTPUT ;
    USE SIGNAL ;
    PORT
      LAYER M4 ;
        RECT  0 173.328 0.192 173.352 ;
    END
  END rout[444]
  PIN rout[445]
    DIRECTION OUTPUT ;
    USE SIGNAL ;
    PORT
      LAYER M4 ;
        RECT  0 173.232 0.192 173.256 ;
    END
  END rout[445]
  PIN rout[446]
    DIRECTION OUTPUT ;
    USE SIGNAL ;
    PORT
      LAYER M4 ;
        RECT  0 173.136 0.192 173.16 ;
    END
  END rout[446]
  PIN rout[447]
    DIRECTION OUTPUT ;
    USE SIGNAL ;
    PORT
      LAYER M4 ;
        RECT  0 173.04 0.192 173.064 ;
    END
  END rout[447]
  PIN rout[448]
    DIRECTION OUTPUT ;
    USE SIGNAL ;
    PORT
      LAYER M4 ;
        RECT  0 172.944 0.192 172.968 ;
    END
  END rout[448]
  PIN rout[449]
    DIRECTION OUTPUT ;
    USE SIGNAL ;
    PORT
      LAYER M4 ;
        RECT  0 172.848 0.192 172.872 ;
    END
  END rout[449]
  PIN rout[44]
    DIRECTION OUTPUT ;
    USE SIGNAL ;
    PORT
      LAYER M4 ;
        RECT  0 211.728 0.192 211.752 ;
    END
  END rout[44]
  PIN rout[450]
    DIRECTION OUTPUT ;
    USE SIGNAL ;
    PORT
      LAYER M4 ;
        RECT  0 172.752 0.192 172.776 ;
    END
  END rout[450]
  PIN rout[451]
    DIRECTION OUTPUT ;
    USE SIGNAL ;
    PORT
      LAYER M4 ;
        RECT  0 172.656 0.192 172.68 ;
    END
  END rout[451]
  PIN rout[452]
    DIRECTION OUTPUT ;
    USE SIGNAL ;
    PORT
      LAYER M4 ;
        RECT  0 172.56 0.192 172.584 ;
    END
  END rout[452]
  PIN rout[453]
    DIRECTION OUTPUT ;
    USE SIGNAL ;
    PORT
      LAYER M4 ;
        RECT  0 172.464 0.192 172.488 ;
    END
  END rout[453]
  PIN rout[454]
    DIRECTION OUTPUT ;
    USE SIGNAL ;
    PORT
      LAYER M4 ;
        RECT  0 172.368 0.192 172.392 ;
    END
  END rout[454]
  PIN rout[455]
    DIRECTION OUTPUT ;
    USE SIGNAL ;
    PORT
      LAYER M4 ;
        RECT  0 172.272 0.192 172.296 ;
    END
  END rout[455]
  PIN rout[456]
    DIRECTION OUTPUT ;
    USE SIGNAL ;
    PORT
      LAYER M4 ;
        RECT  0 172.176 0.192 172.2 ;
    END
  END rout[456]
  PIN rout[457]
    DIRECTION OUTPUT ;
    USE SIGNAL ;
    PORT
      LAYER M4 ;
        RECT  0 172.08 0.192 172.104 ;
    END
  END rout[457]
  PIN rout[458]
    DIRECTION OUTPUT ;
    USE SIGNAL ;
    PORT
      LAYER M4 ;
        RECT  0 171.984 0.192 172.008 ;
    END
  END rout[458]
  PIN rout[459]
    DIRECTION OUTPUT ;
    USE SIGNAL ;
    PORT
      LAYER M4 ;
        RECT  0 171.888 0.192 171.912 ;
    END
  END rout[459]
  PIN rout[45]
    DIRECTION OUTPUT ;
    USE SIGNAL ;
    PORT
      LAYER M4 ;
        RECT  0 211.632 0.192 211.656 ;
    END
  END rout[45]
  PIN rout[460]
    DIRECTION OUTPUT ;
    USE SIGNAL ;
    PORT
      LAYER M4 ;
        RECT  0 171.792 0.192 171.816 ;
    END
  END rout[460]
  PIN rout[461]
    DIRECTION OUTPUT ;
    USE SIGNAL ;
    PORT
      LAYER M4 ;
        RECT  0 171.696 0.192 171.72 ;
    END
  END rout[461]
  PIN rout[462]
    DIRECTION OUTPUT ;
    USE SIGNAL ;
    PORT
      LAYER M4 ;
        RECT  0 171.6 0.192 171.624 ;
    END
  END rout[462]
  PIN rout[463]
    DIRECTION OUTPUT ;
    USE SIGNAL ;
    PORT
      LAYER M4 ;
        RECT  0 171.504 0.192 171.528 ;
    END
  END rout[463]
  PIN rout[464]
    DIRECTION OUTPUT ;
    USE SIGNAL ;
    PORT
      LAYER M4 ;
        RECT  0 171.408 0.192 171.432 ;
    END
  END rout[464]
  PIN rout[465]
    DIRECTION OUTPUT ;
    USE SIGNAL ;
    PORT
      LAYER M4 ;
        RECT  0 171.312 0.192 171.336 ;
    END
  END rout[465]
  PIN rout[466]
    DIRECTION OUTPUT ;
    USE SIGNAL ;
    PORT
      LAYER M4 ;
        RECT  0 171.216 0.192 171.24 ;
    END
  END rout[466]
  PIN rout[467]
    DIRECTION OUTPUT ;
    USE SIGNAL ;
    PORT
      LAYER M4 ;
        RECT  0 171.12 0.192 171.144 ;
    END
  END rout[467]
  PIN rout[468]
    DIRECTION OUTPUT ;
    USE SIGNAL ;
    PORT
      LAYER M4 ;
        RECT  0 171.024 0.192 171.048 ;
    END
  END rout[468]
  PIN rout[469]
    DIRECTION OUTPUT ;
    USE SIGNAL ;
    PORT
      LAYER M4 ;
        RECT  0 170.928 0.192 170.952 ;
    END
  END rout[469]
  PIN rout[46]
    DIRECTION OUTPUT ;
    USE SIGNAL ;
    PORT
      LAYER M4 ;
        RECT  0 211.536 0.192 211.56 ;
    END
  END rout[46]
  PIN rout[470]
    DIRECTION OUTPUT ;
    USE SIGNAL ;
    PORT
      LAYER M4 ;
        RECT  0 170.832 0.192 170.856 ;
    END
  END rout[470]
  PIN rout[471]
    DIRECTION OUTPUT ;
    USE SIGNAL ;
    PORT
      LAYER M4 ;
        RECT  0 170.736 0.192 170.76 ;
    END
  END rout[471]
  PIN rout[472]
    DIRECTION OUTPUT ;
    USE SIGNAL ;
    PORT
      LAYER M4 ;
        RECT  0 170.64 0.192 170.664 ;
    END
  END rout[472]
  PIN rout[473]
    DIRECTION OUTPUT ;
    USE SIGNAL ;
    PORT
      LAYER M4 ;
        RECT  0 170.544 0.192 170.568 ;
    END
  END rout[473]
  PIN rout[474]
    DIRECTION OUTPUT ;
    USE SIGNAL ;
    PORT
      LAYER M4 ;
        RECT  0 170.448 0.192 170.472 ;
    END
  END rout[474]
  PIN rout[475]
    DIRECTION OUTPUT ;
    USE SIGNAL ;
    PORT
      LAYER M4 ;
        RECT  0 170.352 0.192 170.376 ;
    END
  END rout[475]
  PIN rout[476]
    DIRECTION OUTPUT ;
    USE SIGNAL ;
    PORT
      LAYER M4 ;
        RECT  0 170.256 0.192 170.28 ;
    END
  END rout[476]
  PIN rout[477]
    DIRECTION OUTPUT ;
    USE SIGNAL ;
    PORT
      LAYER M4 ;
        RECT  0 170.16 0.192 170.184 ;
    END
  END rout[477]
  PIN rout[478]
    DIRECTION OUTPUT ;
    USE SIGNAL ;
    PORT
      LAYER M4 ;
        RECT  0 170.064 0.192 170.088 ;
    END
  END rout[478]
  PIN rout[479]
    DIRECTION OUTPUT ;
    USE SIGNAL ;
    PORT
      LAYER M4 ;
        RECT  0 169.968 0.192 169.992 ;
    END
  END rout[479]
  PIN rout[47]
    DIRECTION OUTPUT ;
    USE SIGNAL ;
    PORT
      LAYER M4 ;
        RECT  0 211.44 0.192 211.464 ;
    END
  END rout[47]
  PIN rout[480]
    DIRECTION OUTPUT ;
    USE SIGNAL ;
    PORT
      LAYER M4 ;
        RECT  0 169.872 0.192 169.896 ;
    END
  END rout[480]
  PIN rout[481]
    DIRECTION OUTPUT ;
    USE SIGNAL ;
    PORT
      LAYER M4 ;
        RECT  0 169.776 0.192 169.8 ;
    END
  END rout[481]
  PIN rout[482]
    DIRECTION OUTPUT ;
    USE SIGNAL ;
    PORT
      LAYER M4 ;
        RECT  0 169.68 0.192 169.704 ;
    END
  END rout[482]
  PIN rout[483]
    DIRECTION OUTPUT ;
    USE SIGNAL ;
    PORT
      LAYER M4 ;
        RECT  0 169.584 0.192 169.608 ;
    END
  END rout[483]
  PIN rout[484]
    DIRECTION OUTPUT ;
    USE SIGNAL ;
    PORT
      LAYER M4 ;
        RECT  0 169.488 0.192 169.512 ;
    END
  END rout[484]
  PIN rout[485]
    DIRECTION OUTPUT ;
    USE SIGNAL ;
    PORT
      LAYER M4 ;
        RECT  0 169.392 0.192 169.416 ;
    END
  END rout[485]
  PIN rout[486]
    DIRECTION OUTPUT ;
    USE SIGNAL ;
    PORT
      LAYER M4 ;
        RECT  0 169.296 0.192 169.32 ;
    END
  END rout[486]
  PIN rout[487]
    DIRECTION OUTPUT ;
    USE SIGNAL ;
    PORT
      LAYER M4 ;
        RECT  0 169.2 0.192 169.224 ;
    END
  END rout[487]
  PIN rout[488]
    DIRECTION OUTPUT ;
    USE SIGNAL ;
    PORT
      LAYER M4 ;
        RECT  0 169.104 0.192 169.128 ;
    END
  END rout[488]
  PIN rout[489]
    DIRECTION OUTPUT ;
    USE SIGNAL ;
    PORT
      LAYER M4 ;
        RECT  0 169.008 0.192 169.032 ;
    END
  END rout[489]
  PIN rout[48]
    DIRECTION OUTPUT ;
    USE SIGNAL ;
    PORT
      LAYER M4 ;
        RECT  0 211.344 0.192 211.368 ;
    END
  END rout[48]
  PIN rout[490]
    DIRECTION OUTPUT ;
    USE SIGNAL ;
    PORT
      LAYER M4 ;
        RECT  0 168.912 0.192 168.936 ;
    END
  END rout[490]
  PIN rout[491]
    DIRECTION OUTPUT ;
    USE SIGNAL ;
    PORT
      LAYER M4 ;
        RECT  0 168.816 0.192 168.84 ;
    END
  END rout[491]
  PIN rout[492]
    DIRECTION OUTPUT ;
    USE SIGNAL ;
    PORT
      LAYER M4 ;
        RECT  0 168.72 0.192 168.744 ;
    END
  END rout[492]
  PIN rout[493]
    DIRECTION OUTPUT ;
    USE SIGNAL ;
    PORT
      LAYER M4 ;
        RECT  0 168.624 0.192 168.648 ;
    END
  END rout[493]
  PIN rout[494]
    DIRECTION OUTPUT ;
    USE SIGNAL ;
    PORT
      LAYER M4 ;
        RECT  0 168.528 0.192 168.552 ;
    END
  END rout[494]
  PIN rout[495]
    DIRECTION OUTPUT ;
    USE SIGNAL ;
    PORT
      LAYER M4 ;
        RECT  0 168.432 0.192 168.456 ;
    END
  END rout[495]
  PIN rout[496]
    DIRECTION OUTPUT ;
    USE SIGNAL ;
    PORT
      LAYER M4 ;
        RECT  0 168.336 0.192 168.36 ;
    END
  END rout[496]
  PIN rout[497]
    DIRECTION OUTPUT ;
    USE SIGNAL ;
    PORT
      LAYER M4 ;
        RECT  0 168.24 0.192 168.264 ;
    END
  END rout[497]
  PIN rout[498]
    DIRECTION OUTPUT ;
    USE SIGNAL ;
    PORT
      LAYER M4 ;
        RECT  0 168.144 0.192 168.168 ;
    END
  END rout[498]
  PIN rout[499]
    DIRECTION OUTPUT ;
    USE SIGNAL ;
    PORT
      LAYER M4 ;
        RECT  0 168.048 0.192 168.072 ;
    END
  END rout[499]
  PIN rout[49]
    DIRECTION OUTPUT ;
    USE SIGNAL ;
    PORT
      LAYER M4 ;
        RECT  0 211.248 0.192 211.272 ;
    END
  END rout[49]
  PIN rout[4]
    DIRECTION OUTPUT ;
    USE SIGNAL ;
    PORT
      LAYER M4 ;
        RECT  0 215.568 0.192 215.592 ;
    END
  END rout[4]
  PIN rout[500]
    DIRECTION OUTPUT ;
    USE SIGNAL ;
    PORT
      LAYER M4 ;
        RECT  0 167.952 0.192 167.976 ;
    END
  END rout[500]
  PIN rout[501]
    DIRECTION OUTPUT ;
    USE SIGNAL ;
    PORT
      LAYER M4 ;
        RECT  0 167.856 0.192 167.88 ;
    END
  END rout[501]
  PIN rout[502]
    DIRECTION OUTPUT ;
    USE SIGNAL ;
    PORT
      LAYER M4 ;
        RECT  0 167.76 0.192 167.784 ;
    END
  END rout[502]
  PIN rout[503]
    DIRECTION OUTPUT ;
    USE SIGNAL ;
    PORT
      LAYER M4 ;
        RECT  0 167.664 0.192 167.688 ;
    END
  END rout[503]
  PIN rout[504]
    DIRECTION OUTPUT ;
    USE SIGNAL ;
    PORT
      LAYER M4 ;
        RECT  0 167.568 0.192 167.592 ;
    END
  END rout[504]
  PIN rout[505]
    DIRECTION OUTPUT ;
    USE SIGNAL ;
    PORT
      LAYER M4 ;
        RECT  0 167.472 0.192 167.496 ;
    END
  END rout[505]
  PIN rout[506]
    DIRECTION OUTPUT ;
    USE SIGNAL ;
    PORT
      LAYER M4 ;
        RECT  0 167.376 0.192 167.4 ;
    END
  END rout[506]
  PIN rout[507]
    DIRECTION OUTPUT ;
    USE SIGNAL ;
    PORT
      LAYER M4 ;
        RECT  0 167.28 0.192 167.304 ;
    END
  END rout[507]
  PIN rout[508]
    DIRECTION OUTPUT ;
    USE SIGNAL ;
    PORT
      LAYER M4 ;
        RECT  0 167.184 0.192 167.208 ;
    END
  END rout[508]
  PIN rout[509]
    DIRECTION OUTPUT ;
    USE SIGNAL ;
    PORT
      LAYER M4 ;
        RECT  0 167.088 0.192 167.112 ;
    END
  END rout[509]
  PIN rout[50]
    DIRECTION OUTPUT ;
    USE SIGNAL ;
    PORT
      LAYER M4 ;
        RECT  0 211.152 0.192 211.176 ;
    END
  END rout[50]
  PIN rout[510]
    DIRECTION OUTPUT ;
    USE SIGNAL ;
    PORT
      LAYER M4 ;
        RECT  0 166.992 0.192 167.016 ;
    END
  END rout[510]
  PIN rout[511]
    DIRECTION OUTPUT ;
    USE SIGNAL ;
    PORT
      LAYER M4 ;
        RECT  0 166.896 0.192 166.92 ;
    END
  END rout[511]
  PIN rout[512]
    DIRECTION OUTPUT ;
    USE SIGNAL ;
    PORT
      LAYER M4 ;
        RECT  0 166.8 0.192 166.824 ;
    END
  END rout[512]
  PIN rout[513]
    DIRECTION OUTPUT ;
    USE SIGNAL ;
    PORT
      LAYER M4 ;
        RECT  0 166.704 0.192 166.728 ;
    END
  END rout[513]
  PIN rout[514]
    DIRECTION OUTPUT ;
    USE SIGNAL ;
    PORT
      LAYER M4 ;
        RECT  0 166.608 0.192 166.632 ;
    END
  END rout[514]
  PIN rout[515]
    DIRECTION OUTPUT ;
    USE SIGNAL ;
    PORT
      LAYER M4 ;
        RECT  0 166.512 0.192 166.536 ;
    END
  END rout[515]
  PIN rout[516]
    DIRECTION OUTPUT ;
    USE SIGNAL ;
    PORT
      LAYER M4 ;
        RECT  0 166.416 0.192 166.44 ;
    END
  END rout[516]
  PIN rout[517]
    DIRECTION OUTPUT ;
    USE SIGNAL ;
    PORT
      LAYER M4 ;
        RECT  0 166.32 0.192 166.344 ;
    END
  END rout[517]
  PIN rout[518]
    DIRECTION OUTPUT ;
    USE SIGNAL ;
    PORT
      LAYER M4 ;
        RECT  0 166.224 0.192 166.248 ;
    END
  END rout[518]
  PIN rout[519]
    DIRECTION OUTPUT ;
    USE SIGNAL ;
    PORT
      LAYER M4 ;
        RECT  0 166.128 0.192 166.152 ;
    END
  END rout[519]
  PIN rout[51]
    DIRECTION OUTPUT ;
    USE SIGNAL ;
    PORT
      LAYER M4 ;
        RECT  0 211.056 0.192 211.08 ;
    END
  END rout[51]
  PIN rout[520]
    DIRECTION OUTPUT ;
    USE SIGNAL ;
    PORT
      LAYER M4 ;
        RECT  0 166.032 0.192 166.056 ;
    END
  END rout[520]
  PIN rout[521]
    DIRECTION OUTPUT ;
    USE SIGNAL ;
    PORT
      LAYER M4 ;
        RECT  0 165.936 0.192 165.96 ;
    END
  END rout[521]
  PIN rout[522]
    DIRECTION OUTPUT ;
    USE SIGNAL ;
    PORT
      LAYER M4 ;
        RECT  0 165.84 0.192 165.864 ;
    END
  END rout[522]
  PIN rout[523]
    DIRECTION OUTPUT ;
    USE SIGNAL ;
    PORT
      LAYER M4 ;
        RECT  0 165.744 0.192 165.768 ;
    END
  END rout[523]
  PIN rout[524]
    DIRECTION OUTPUT ;
    USE SIGNAL ;
    PORT
      LAYER M4 ;
        RECT  0 165.648 0.192 165.672 ;
    END
  END rout[524]
  PIN rout[525]
    DIRECTION OUTPUT ;
    USE SIGNAL ;
    PORT
      LAYER M4 ;
        RECT  0 165.552 0.192 165.576 ;
    END
  END rout[525]
  PIN rout[526]
    DIRECTION OUTPUT ;
    USE SIGNAL ;
    PORT
      LAYER M4 ;
        RECT  0 165.456 0.192 165.48 ;
    END
  END rout[526]
  PIN rout[527]
    DIRECTION OUTPUT ;
    USE SIGNAL ;
    PORT
      LAYER M4 ;
        RECT  0 165.36 0.192 165.384 ;
    END
  END rout[527]
  PIN rout[528]
    DIRECTION OUTPUT ;
    USE SIGNAL ;
    PORT
      LAYER M4 ;
        RECT  0 165.264 0.192 165.288 ;
    END
  END rout[528]
  PIN rout[529]
    DIRECTION OUTPUT ;
    USE SIGNAL ;
    PORT
      LAYER M4 ;
        RECT  0 165.168 0.192 165.192 ;
    END
  END rout[529]
  PIN rout[52]
    DIRECTION OUTPUT ;
    USE SIGNAL ;
    PORT
      LAYER M4 ;
        RECT  0 210.96 0.192 210.984 ;
    END
  END rout[52]
  PIN rout[530]
    DIRECTION OUTPUT ;
    USE SIGNAL ;
    PORT
      LAYER M4 ;
        RECT  0 165.072 0.192 165.096 ;
    END
  END rout[530]
  PIN rout[531]
    DIRECTION OUTPUT ;
    USE SIGNAL ;
    PORT
      LAYER M4 ;
        RECT  0 164.976 0.192 165 ;
    END
  END rout[531]
  PIN rout[532]
    DIRECTION OUTPUT ;
    USE SIGNAL ;
    PORT
      LAYER M4 ;
        RECT  0 164.88 0.192 164.904 ;
    END
  END rout[532]
  PIN rout[533]
    DIRECTION OUTPUT ;
    USE SIGNAL ;
    PORT
      LAYER M4 ;
        RECT  0 164.784 0.192 164.808 ;
    END
  END rout[533]
  PIN rout[534]
    DIRECTION OUTPUT ;
    USE SIGNAL ;
    PORT
      LAYER M4 ;
        RECT  0 164.688 0.192 164.712 ;
    END
  END rout[534]
  PIN rout[535]
    DIRECTION OUTPUT ;
    USE SIGNAL ;
    PORT
      LAYER M4 ;
        RECT  0 164.592 0.192 164.616 ;
    END
  END rout[535]
  PIN rout[536]
    DIRECTION OUTPUT ;
    USE SIGNAL ;
    PORT
      LAYER M4 ;
        RECT  0 164.496 0.192 164.52 ;
    END
  END rout[536]
  PIN rout[537]
    DIRECTION OUTPUT ;
    USE SIGNAL ;
    PORT
      LAYER M4 ;
        RECT  0 164.4 0.192 164.424 ;
    END
  END rout[537]
  PIN rout[538]
    DIRECTION OUTPUT ;
    USE SIGNAL ;
    PORT
      LAYER M4 ;
        RECT  0 164.304 0.192 164.328 ;
    END
  END rout[538]
  PIN rout[539]
    DIRECTION OUTPUT ;
    USE SIGNAL ;
    PORT
      LAYER M4 ;
        RECT  0 164.208 0.192 164.232 ;
    END
  END rout[539]
  PIN rout[53]
    DIRECTION OUTPUT ;
    USE SIGNAL ;
    PORT
      LAYER M4 ;
        RECT  0 210.864 0.192 210.888 ;
    END
  END rout[53]
  PIN rout[540]
    DIRECTION OUTPUT ;
    USE SIGNAL ;
    PORT
      LAYER M4 ;
        RECT  0 164.112 0.192 164.136 ;
    END
  END rout[540]
  PIN rout[541]
    DIRECTION OUTPUT ;
    USE SIGNAL ;
    PORT
      LAYER M4 ;
        RECT  0 164.016 0.192 164.04 ;
    END
  END rout[541]
  PIN rout[542]
    DIRECTION OUTPUT ;
    USE SIGNAL ;
    PORT
      LAYER M4 ;
        RECT  0 163.92 0.192 163.944 ;
    END
  END rout[542]
  PIN rout[543]
    DIRECTION OUTPUT ;
    USE SIGNAL ;
    PORT
      LAYER M4 ;
        RECT  0 163.824 0.192 163.848 ;
    END
  END rout[543]
  PIN rout[544]
    DIRECTION OUTPUT ;
    USE SIGNAL ;
    PORT
      LAYER M4 ;
        RECT  0 163.728 0.192 163.752 ;
    END
  END rout[544]
  PIN rout[545]
    DIRECTION OUTPUT ;
    USE SIGNAL ;
    PORT
      LAYER M4 ;
        RECT  0 163.632 0.192 163.656 ;
    END
  END rout[545]
  PIN rout[546]
    DIRECTION OUTPUT ;
    USE SIGNAL ;
    PORT
      LAYER M4 ;
        RECT  0 163.536 0.192 163.56 ;
    END
  END rout[546]
  PIN rout[547]
    DIRECTION OUTPUT ;
    USE SIGNAL ;
    PORT
      LAYER M4 ;
        RECT  0 163.44 0.192 163.464 ;
    END
  END rout[547]
  PIN rout[548]
    DIRECTION OUTPUT ;
    USE SIGNAL ;
    PORT
      LAYER M4 ;
        RECT  0 163.344 0.192 163.368 ;
    END
  END rout[548]
  PIN rout[549]
    DIRECTION OUTPUT ;
    USE SIGNAL ;
    PORT
      LAYER M4 ;
        RECT  0 163.248 0.192 163.272 ;
    END
  END rout[549]
  PIN rout[54]
    DIRECTION OUTPUT ;
    USE SIGNAL ;
    PORT
      LAYER M4 ;
        RECT  0 210.768 0.192 210.792 ;
    END
  END rout[54]
  PIN rout[550]
    DIRECTION OUTPUT ;
    USE SIGNAL ;
    PORT
      LAYER M4 ;
        RECT  0 163.152 0.192 163.176 ;
    END
  END rout[550]
  PIN rout[551]
    DIRECTION OUTPUT ;
    USE SIGNAL ;
    PORT
      LAYER M4 ;
        RECT  0 163.056 0.192 163.08 ;
    END
  END rout[551]
  PIN rout[552]
    DIRECTION OUTPUT ;
    USE SIGNAL ;
    PORT
      LAYER M4 ;
        RECT  0 162.96 0.192 162.984 ;
    END
  END rout[552]
  PIN rout[553]
    DIRECTION OUTPUT ;
    USE SIGNAL ;
    PORT
      LAYER M4 ;
        RECT  0 162.864 0.192 162.888 ;
    END
  END rout[553]
  PIN rout[554]
    DIRECTION OUTPUT ;
    USE SIGNAL ;
    PORT
      LAYER M4 ;
        RECT  0 162.768 0.192 162.792 ;
    END
  END rout[554]
  PIN rout[555]
    DIRECTION OUTPUT ;
    USE SIGNAL ;
    PORT
      LAYER M4 ;
        RECT  0 162.672 0.192 162.696 ;
    END
  END rout[555]
  PIN rout[556]
    DIRECTION OUTPUT ;
    USE SIGNAL ;
    PORT
      LAYER M4 ;
        RECT  0 162.576 0.192 162.6 ;
    END
  END rout[556]
  PIN rout[557]
    DIRECTION OUTPUT ;
    USE SIGNAL ;
    PORT
      LAYER M4 ;
        RECT  0 162.48 0.192 162.504 ;
    END
  END rout[557]
  PIN rout[558]
    DIRECTION OUTPUT ;
    USE SIGNAL ;
    PORT
      LAYER M4 ;
        RECT  0 162.384 0.192 162.408 ;
    END
  END rout[558]
  PIN rout[559]
    DIRECTION OUTPUT ;
    USE SIGNAL ;
    PORT
      LAYER M4 ;
        RECT  0 162.288 0.192 162.312 ;
    END
  END rout[559]
  PIN rout[55]
    DIRECTION OUTPUT ;
    USE SIGNAL ;
    PORT
      LAYER M4 ;
        RECT  0 210.672 0.192 210.696 ;
    END
  END rout[55]
  PIN rout[560]
    DIRECTION OUTPUT ;
    USE SIGNAL ;
    PORT
      LAYER M4 ;
        RECT  0 162.192 0.192 162.216 ;
    END
  END rout[560]
  PIN rout[561]
    DIRECTION OUTPUT ;
    USE SIGNAL ;
    PORT
      LAYER M4 ;
        RECT  0 162.096 0.192 162.12 ;
    END
  END rout[561]
  PIN rout[562]
    DIRECTION OUTPUT ;
    USE SIGNAL ;
    PORT
      LAYER M4 ;
        RECT  0 162 0.192 162.024 ;
    END
  END rout[562]
  PIN rout[563]
    DIRECTION OUTPUT ;
    USE SIGNAL ;
    PORT
      LAYER M4 ;
        RECT  0 161.904 0.192 161.928 ;
    END
  END rout[563]
  PIN rout[564]
    DIRECTION OUTPUT ;
    USE SIGNAL ;
    PORT
      LAYER M4 ;
        RECT  0 161.808 0.192 161.832 ;
    END
  END rout[564]
  PIN rout[565]
    DIRECTION OUTPUT ;
    USE SIGNAL ;
    PORT
      LAYER M4 ;
        RECT  0 161.712 0.192 161.736 ;
    END
  END rout[565]
  PIN rout[566]
    DIRECTION OUTPUT ;
    USE SIGNAL ;
    PORT
      LAYER M4 ;
        RECT  0 161.616 0.192 161.64 ;
    END
  END rout[566]
  PIN rout[567]
    DIRECTION OUTPUT ;
    USE SIGNAL ;
    PORT
      LAYER M4 ;
        RECT  0 161.52 0.192 161.544 ;
    END
  END rout[567]
  PIN rout[568]
    DIRECTION OUTPUT ;
    USE SIGNAL ;
    PORT
      LAYER M4 ;
        RECT  0 161.424 0.192 161.448 ;
    END
  END rout[568]
  PIN rout[569]
    DIRECTION OUTPUT ;
    USE SIGNAL ;
    PORT
      LAYER M4 ;
        RECT  0 161.328 0.192 161.352 ;
    END
  END rout[569]
  PIN rout[56]
    DIRECTION OUTPUT ;
    USE SIGNAL ;
    PORT
      LAYER M4 ;
        RECT  0 210.576 0.192 210.6 ;
    END
  END rout[56]
  PIN rout[570]
    DIRECTION OUTPUT ;
    USE SIGNAL ;
    PORT
      LAYER M4 ;
        RECT  0 161.232 0.192 161.256 ;
    END
  END rout[570]
  PIN rout[571]
    DIRECTION OUTPUT ;
    USE SIGNAL ;
    PORT
      LAYER M4 ;
        RECT  0 161.136 0.192 161.16 ;
    END
  END rout[571]
  PIN rout[572]
    DIRECTION OUTPUT ;
    USE SIGNAL ;
    PORT
      LAYER M4 ;
        RECT  0 161.04 0.192 161.064 ;
    END
  END rout[572]
  PIN rout[573]
    DIRECTION OUTPUT ;
    USE SIGNAL ;
    PORT
      LAYER M4 ;
        RECT  0 160.944 0.192 160.968 ;
    END
  END rout[573]
  PIN rout[574]
    DIRECTION OUTPUT ;
    USE SIGNAL ;
    PORT
      LAYER M4 ;
        RECT  0 160.848 0.192 160.872 ;
    END
  END rout[574]
  PIN rout[575]
    DIRECTION OUTPUT ;
    USE SIGNAL ;
    PORT
      LAYER M4 ;
        RECT  0 160.752 0.192 160.776 ;
    END
  END rout[575]
  PIN rout[576]
    DIRECTION OUTPUT ;
    USE SIGNAL ;
    PORT
      LAYER M4 ;
        RECT  0 160.656 0.192 160.68 ;
    END
  END rout[576]
  PIN rout[577]
    DIRECTION OUTPUT ;
    USE SIGNAL ;
    PORT
      LAYER M4 ;
        RECT  0 160.56 0.192 160.584 ;
    END
  END rout[577]
  PIN rout[578]
    DIRECTION OUTPUT ;
    USE SIGNAL ;
    PORT
      LAYER M4 ;
        RECT  0 160.464 0.192 160.488 ;
    END
  END rout[578]
  PIN rout[579]
    DIRECTION OUTPUT ;
    USE SIGNAL ;
    PORT
      LAYER M4 ;
        RECT  0 160.368 0.192 160.392 ;
    END
  END rout[579]
  PIN rout[57]
    DIRECTION OUTPUT ;
    USE SIGNAL ;
    PORT
      LAYER M4 ;
        RECT  0 210.48 0.192 210.504 ;
    END
  END rout[57]
  PIN rout[580]
    DIRECTION OUTPUT ;
    USE SIGNAL ;
    PORT
      LAYER M4 ;
        RECT  0 160.272 0.192 160.296 ;
    END
  END rout[580]
  PIN rout[581]
    DIRECTION OUTPUT ;
    USE SIGNAL ;
    PORT
      LAYER M4 ;
        RECT  0 160.176 0.192 160.2 ;
    END
  END rout[581]
  PIN rout[582]
    DIRECTION OUTPUT ;
    USE SIGNAL ;
    PORT
      LAYER M4 ;
        RECT  0 160.08 0.192 160.104 ;
    END
  END rout[582]
  PIN rout[583]
    DIRECTION OUTPUT ;
    USE SIGNAL ;
    PORT
      LAYER M4 ;
        RECT  0 159.984 0.192 160.008 ;
    END
  END rout[583]
  PIN rout[584]
    DIRECTION OUTPUT ;
    USE SIGNAL ;
    PORT
      LAYER M4 ;
        RECT  0 159.888 0.192 159.912 ;
    END
  END rout[584]
  PIN rout[585]
    DIRECTION OUTPUT ;
    USE SIGNAL ;
    PORT
      LAYER M4 ;
        RECT  0 159.792 0.192 159.816 ;
    END
  END rout[585]
  PIN rout[586]
    DIRECTION OUTPUT ;
    USE SIGNAL ;
    PORT
      LAYER M4 ;
        RECT  0 159.696 0.192 159.72 ;
    END
  END rout[586]
  PIN rout[587]
    DIRECTION OUTPUT ;
    USE SIGNAL ;
    PORT
      LAYER M4 ;
        RECT  0 159.6 0.192 159.624 ;
    END
  END rout[587]
  PIN rout[588]
    DIRECTION OUTPUT ;
    USE SIGNAL ;
    PORT
      LAYER M4 ;
        RECT  0 159.504 0.192 159.528 ;
    END
  END rout[588]
  PIN rout[589]
    DIRECTION OUTPUT ;
    USE SIGNAL ;
    PORT
      LAYER M4 ;
        RECT  0 159.408 0.192 159.432 ;
    END
  END rout[589]
  PIN rout[58]
    DIRECTION OUTPUT ;
    USE SIGNAL ;
    PORT
      LAYER M4 ;
        RECT  0 210.384 0.192 210.408 ;
    END
  END rout[58]
  PIN rout[590]
    DIRECTION OUTPUT ;
    USE SIGNAL ;
    PORT
      LAYER M4 ;
        RECT  0 159.312 0.192 159.336 ;
    END
  END rout[590]
  PIN rout[591]
    DIRECTION OUTPUT ;
    USE SIGNAL ;
    PORT
      LAYER M4 ;
        RECT  0 159.216 0.192 159.24 ;
    END
  END rout[591]
  PIN rout[592]
    DIRECTION OUTPUT ;
    USE SIGNAL ;
    PORT
      LAYER M4 ;
        RECT  0 159.12 0.192 159.144 ;
    END
  END rout[592]
  PIN rout[593]
    DIRECTION OUTPUT ;
    USE SIGNAL ;
    PORT
      LAYER M4 ;
        RECT  0 159.024 0.192 159.048 ;
    END
  END rout[593]
  PIN rout[594]
    DIRECTION OUTPUT ;
    USE SIGNAL ;
    PORT
      LAYER M4 ;
        RECT  0 158.928 0.192 158.952 ;
    END
  END rout[594]
  PIN rout[595]
    DIRECTION OUTPUT ;
    USE SIGNAL ;
    PORT
      LAYER M4 ;
        RECT  0 158.832 0.192 158.856 ;
    END
  END rout[595]
  PIN rout[596]
    DIRECTION OUTPUT ;
    USE SIGNAL ;
    PORT
      LAYER M4 ;
        RECT  0 158.736 0.192 158.76 ;
    END
  END rout[596]
  PIN rout[597]
    DIRECTION OUTPUT ;
    USE SIGNAL ;
    PORT
      LAYER M4 ;
        RECT  0 158.64 0.192 158.664 ;
    END
  END rout[597]
  PIN rout[598]
    DIRECTION OUTPUT ;
    USE SIGNAL ;
    PORT
      LAYER M4 ;
        RECT  0 158.544 0.192 158.568 ;
    END
  END rout[598]
  PIN rout[599]
    DIRECTION OUTPUT ;
    USE SIGNAL ;
    PORT
      LAYER M4 ;
        RECT  0 158.448 0.192 158.472 ;
    END
  END rout[599]
  PIN rout[59]
    DIRECTION OUTPUT ;
    USE SIGNAL ;
    PORT
      LAYER M4 ;
        RECT  0 210.288 0.192 210.312 ;
    END
  END rout[59]
  PIN rout[5]
    DIRECTION OUTPUT ;
    USE SIGNAL ;
    PORT
      LAYER M4 ;
        RECT  0 215.472 0.192 215.496 ;
    END
  END rout[5]
  PIN rout[600]
    DIRECTION OUTPUT ;
    USE SIGNAL ;
    PORT
      LAYER M4 ;
        RECT  0 158.352 0.192 158.376 ;
    END
  END rout[600]
  PIN rout[601]
    DIRECTION OUTPUT ;
    USE SIGNAL ;
    PORT
      LAYER M4 ;
        RECT  0 158.256 0.192 158.28 ;
    END
  END rout[601]
  PIN rout[602]
    DIRECTION OUTPUT ;
    USE SIGNAL ;
    PORT
      LAYER M4 ;
        RECT  0 158.16 0.192 158.184 ;
    END
  END rout[602]
  PIN rout[603]
    DIRECTION OUTPUT ;
    USE SIGNAL ;
    PORT
      LAYER M4 ;
        RECT  0 158.064 0.192 158.088 ;
    END
  END rout[603]
  PIN rout[604]
    DIRECTION OUTPUT ;
    USE SIGNAL ;
    PORT
      LAYER M4 ;
        RECT  0 157.968 0.192 157.992 ;
    END
  END rout[604]
  PIN rout[605]
    DIRECTION OUTPUT ;
    USE SIGNAL ;
    PORT
      LAYER M4 ;
        RECT  0 157.872 0.192 157.896 ;
    END
  END rout[605]
  PIN rout[606]
    DIRECTION OUTPUT ;
    USE SIGNAL ;
    PORT
      LAYER M4 ;
        RECT  0 157.776 0.192 157.8 ;
    END
  END rout[606]
  PIN rout[607]
    DIRECTION OUTPUT ;
    USE SIGNAL ;
    PORT
      LAYER M4 ;
        RECT  0 157.68 0.192 157.704 ;
    END
  END rout[607]
  PIN rout[608]
    DIRECTION OUTPUT ;
    USE SIGNAL ;
    PORT
      LAYER M4 ;
        RECT  0 157.584 0.192 157.608 ;
    END
  END rout[608]
  PIN rout[609]
    DIRECTION OUTPUT ;
    USE SIGNAL ;
    PORT
      LAYER M4 ;
        RECT  0 157.488 0.192 157.512 ;
    END
  END rout[609]
  PIN rout[60]
    DIRECTION OUTPUT ;
    USE SIGNAL ;
    PORT
      LAYER M4 ;
        RECT  0 210.192 0.192 210.216 ;
    END
  END rout[60]
  PIN rout[610]
    DIRECTION OUTPUT ;
    USE SIGNAL ;
    PORT
      LAYER M4 ;
        RECT  0 157.392 0.192 157.416 ;
    END
  END rout[610]
  PIN rout[611]
    DIRECTION OUTPUT ;
    USE SIGNAL ;
    PORT
      LAYER M4 ;
        RECT  0 157.296 0.192 157.32 ;
    END
  END rout[611]
  PIN rout[612]
    DIRECTION OUTPUT ;
    USE SIGNAL ;
    PORT
      LAYER M4 ;
        RECT  0 157.2 0.192 157.224 ;
    END
  END rout[612]
  PIN rout[613]
    DIRECTION OUTPUT ;
    USE SIGNAL ;
    PORT
      LAYER M4 ;
        RECT  0 157.104 0.192 157.128 ;
    END
  END rout[613]
  PIN rout[614]
    DIRECTION OUTPUT ;
    USE SIGNAL ;
    PORT
      LAYER M4 ;
        RECT  0 157.008 0.192 157.032 ;
    END
  END rout[614]
  PIN rout[615]
    DIRECTION OUTPUT ;
    USE SIGNAL ;
    PORT
      LAYER M4 ;
        RECT  0 156.912 0.192 156.936 ;
    END
  END rout[615]
  PIN rout[616]
    DIRECTION OUTPUT ;
    USE SIGNAL ;
    PORT
      LAYER M4 ;
        RECT  0 156.816 0.192 156.84 ;
    END
  END rout[616]
  PIN rout[617]
    DIRECTION OUTPUT ;
    USE SIGNAL ;
    PORT
      LAYER M4 ;
        RECT  0 156.72 0.192 156.744 ;
    END
  END rout[617]
  PIN rout[618]
    DIRECTION OUTPUT ;
    USE SIGNAL ;
    PORT
      LAYER M4 ;
        RECT  0 156.624 0.192 156.648 ;
    END
  END rout[618]
  PIN rout[619]
    DIRECTION OUTPUT ;
    USE SIGNAL ;
    PORT
      LAYER M4 ;
        RECT  0 156.528 0.192 156.552 ;
    END
  END rout[619]
  PIN rout[61]
    DIRECTION OUTPUT ;
    USE SIGNAL ;
    PORT
      LAYER M4 ;
        RECT  0 210.096 0.192 210.12 ;
    END
  END rout[61]
  PIN rout[620]
    DIRECTION OUTPUT ;
    USE SIGNAL ;
    PORT
      LAYER M4 ;
        RECT  0 156.432 0.192 156.456 ;
    END
  END rout[620]
  PIN rout[621]
    DIRECTION OUTPUT ;
    USE SIGNAL ;
    PORT
      LAYER M4 ;
        RECT  0 156.336 0.192 156.36 ;
    END
  END rout[621]
  PIN rout[622]
    DIRECTION OUTPUT ;
    USE SIGNAL ;
    PORT
      LAYER M4 ;
        RECT  0 156.24 0.192 156.264 ;
    END
  END rout[622]
  PIN rout[623]
    DIRECTION OUTPUT ;
    USE SIGNAL ;
    PORT
      LAYER M4 ;
        RECT  0 156.144 0.192 156.168 ;
    END
  END rout[623]
  PIN rout[624]
    DIRECTION OUTPUT ;
    USE SIGNAL ;
    PORT
      LAYER M4 ;
        RECT  0 156.048 0.192 156.072 ;
    END
  END rout[624]
  PIN rout[625]
    DIRECTION OUTPUT ;
    USE SIGNAL ;
    PORT
      LAYER M4 ;
        RECT  0 155.952 0.192 155.976 ;
    END
  END rout[625]
  PIN rout[626]
    DIRECTION OUTPUT ;
    USE SIGNAL ;
    PORT
      LAYER M4 ;
        RECT  0 155.856 0.192 155.88 ;
    END
  END rout[626]
  PIN rout[627]
    DIRECTION OUTPUT ;
    USE SIGNAL ;
    PORT
      LAYER M4 ;
        RECT  0 155.76 0.192 155.784 ;
    END
  END rout[627]
  PIN rout[628]
    DIRECTION OUTPUT ;
    USE SIGNAL ;
    PORT
      LAYER M4 ;
        RECT  0 155.664 0.192 155.688 ;
    END
  END rout[628]
  PIN rout[629]
    DIRECTION OUTPUT ;
    USE SIGNAL ;
    PORT
      LAYER M4 ;
        RECT  0 155.568 0.192 155.592 ;
    END
  END rout[629]
  PIN rout[62]
    DIRECTION OUTPUT ;
    USE SIGNAL ;
    PORT
      LAYER M4 ;
        RECT  0 210 0.192 210.024 ;
    END
  END rout[62]
  PIN rout[630]
    DIRECTION OUTPUT ;
    USE SIGNAL ;
    PORT
      LAYER M4 ;
        RECT  0 155.472 0.192 155.496 ;
    END
  END rout[630]
  PIN rout[631]
    DIRECTION OUTPUT ;
    USE SIGNAL ;
    PORT
      LAYER M4 ;
        RECT  0 155.376 0.192 155.4 ;
    END
  END rout[631]
  PIN rout[632]
    DIRECTION OUTPUT ;
    USE SIGNAL ;
    PORT
      LAYER M4 ;
        RECT  0 155.28 0.192 155.304 ;
    END
  END rout[632]
  PIN rout[633]
    DIRECTION OUTPUT ;
    USE SIGNAL ;
    PORT
      LAYER M4 ;
        RECT  0 155.184 0.192 155.208 ;
    END
  END rout[633]
  PIN rout[634]
    DIRECTION OUTPUT ;
    USE SIGNAL ;
    PORT
      LAYER M4 ;
        RECT  0 155.088 0.192 155.112 ;
    END
  END rout[634]
  PIN rout[635]
    DIRECTION OUTPUT ;
    USE SIGNAL ;
    PORT
      LAYER M4 ;
        RECT  0 154.992 0.192 155.016 ;
    END
  END rout[635]
  PIN rout[636]
    DIRECTION OUTPUT ;
    USE SIGNAL ;
    PORT
      LAYER M4 ;
        RECT  0 154.896 0.192 154.92 ;
    END
  END rout[636]
  PIN rout[637]
    DIRECTION OUTPUT ;
    USE SIGNAL ;
    PORT
      LAYER M4 ;
        RECT  0 154.8 0.192 154.824 ;
    END
  END rout[637]
  PIN rout[638]
    DIRECTION OUTPUT ;
    USE SIGNAL ;
    PORT
      LAYER M4 ;
        RECT  0 154.704 0.192 154.728 ;
    END
  END rout[638]
  PIN rout[639]
    DIRECTION OUTPUT ;
    USE SIGNAL ;
    PORT
      LAYER M4 ;
        RECT  0 154.608 0.192 154.632 ;
    END
  END rout[639]
  PIN rout[63]
    DIRECTION OUTPUT ;
    USE SIGNAL ;
    PORT
      LAYER M4 ;
        RECT  0 209.904 0.192 209.928 ;
    END
  END rout[63]
  PIN rout[640]
    DIRECTION OUTPUT ;
    USE SIGNAL ;
    PORT
      LAYER M4 ;
        RECT  0 154.512 0.192 154.536 ;
    END
  END rout[640]
  PIN rout[641]
    DIRECTION OUTPUT ;
    USE SIGNAL ;
    PORT
      LAYER M4 ;
        RECT  0 154.416 0.192 154.44 ;
    END
  END rout[641]
  PIN rout[642]
    DIRECTION OUTPUT ;
    USE SIGNAL ;
    PORT
      LAYER M4 ;
        RECT  0 154.32 0.192 154.344 ;
    END
  END rout[642]
  PIN rout[643]
    DIRECTION OUTPUT ;
    USE SIGNAL ;
    PORT
      LAYER M4 ;
        RECT  0 154.224 0.192 154.248 ;
    END
  END rout[643]
  PIN rout[644]
    DIRECTION OUTPUT ;
    USE SIGNAL ;
    PORT
      LAYER M4 ;
        RECT  0 154.128 0.192 154.152 ;
    END
  END rout[644]
  PIN rout[645]
    DIRECTION OUTPUT ;
    USE SIGNAL ;
    PORT
      LAYER M4 ;
        RECT  0 154.032 0.192 154.056 ;
    END
  END rout[645]
  PIN rout[646]
    DIRECTION OUTPUT ;
    USE SIGNAL ;
    PORT
      LAYER M4 ;
        RECT  0 153.936 0.192 153.96 ;
    END
  END rout[646]
  PIN rout[647]
    DIRECTION OUTPUT ;
    USE SIGNAL ;
    PORT
      LAYER M4 ;
        RECT  0 153.84 0.192 153.864 ;
    END
  END rout[647]
  PIN rout[648]
    DIRECTION OUTPUT ;
    USE SIGNAL ;
    PORT
      LAYER M4 ;
        RECT  0 153.744 0.192 153.768 ;
    END
  END rout[648]
  PIN rout[649]
    DIRECTION OUTPUT ;
    USE SIGNAL ;
    PORT
      LAYER M4 ;
        RECT  0 153.648 0.192 153.672 ;
    END
  END rout[649]
  PIN rout[64]
    DIRECTION OUTPUT ;
    USE SIGNAL ;
    PORT
      LAYER M4 ;
        RECT  0 209.808 0.192 209.832 ;
    END
  END rout[64]
  PIN rout[650]
    DIRECTION OUTPUT ;
    USE SIGNAL ;
    PORT
      LAYER M4 ;
        RECT  0 153.552 0.192 153.576 ;
    END
  END rout[650]
  PIN rout[651]
    DIRECTION OUTPUT ;
    USE SIGNAL ;
    PORT
      LAYER M4 ;
        RECT  0 153.456 0.192 153.48 ;
    END
  END rout[651]
  PIN rout[652]
    DIRECTION OUTPUT ;
    USE SIGNAL ;
    PORT
      LAYER M4 ;
        RECT  0 153.36 0.192 153.384 ;
    END
  END rout[652]
  PIN rout[653]
    DIRECTION OUTPUT ;
    USE SIGNAL ;
    PORT
      LAYER M4 ;
        RECT  0 153.264 0.192 153.288 ;
    END
  END rout[653]
  PIN rout[654]
    DIRECTION OUTPUT ;
    USE SIGNAL ;
    PORT
      LAYER M4 ;
        RECT  0 153.168 0.192 153.192 ;
    END
  END rout[654]
  PIN rout[655]
    DIRECTION OUTPUT ;
    USE SIGNAL ;
    PORT
      LAYER M4 ;
        RECT  0 153.072 0.192 153.096 ;
    END
  END rout[655]
  PIN rout[656]
    DIRECTION OUTPUT ;
    USE SIGNAL ;
    PORT
      LAYER M4 ;
        RECT  0 152.976 0.192 153 ;
    END
  END rout[656]
  PIN rout[657]
    DIRECTION OUTPUT ;
    USE SIGNAL ;
    PORT
      LAYER M4 ;
        RECT  0 152.88 0.192 152.904 ;
    END
  END rout[657]
  PIN rout[658]
    DIRECTION OUTPUT ;
    USE SIGNAL ;
    PORT
      LAYER M4 ;
        RECT  0 152.784 0.192 152.808 ;
    END
  END rout[658]
  PIN rout[659]
    DIRECTION OUTPUT ;
    USE SIGNAL ;
    PORT
      LAYER M4 ;
        RECT  0 152.688 0.192 152.712 ;
    END
  END rout[659]
  PIN rout[65]
    DIRECTION OUTPUT ;
    USE SIGNAL ;
    PORT
      LAYER M4 ;
        RECT  0 209.712 0.192 209.736 ;
    END
  END rout[65]
  PIN rout[660]
    DIRECTION OUTPUT ;
    USE SIGNAL ;
    PORT
      LAYER M4 ;
        RECT  0 152.592 0.192 152.616 ;
    END
  END rout[660]
  PIN rout[661]
    DIRECTION OUTPUT ;
    USE SIGNAL ;
    PORT
      LAYER M4 ;
        RECT  0 152.496 0.192 152.52 ;
    END
  END rout[661]
  PIN rout[662]
    DIRECTION OUTPUT ;
    USE SIGNAL ;
    PORT
      LAYER M4 ;
        RECT  0 152.4 0.192 152.424 ;
    END
  END rout[662]
  PIN rout[663]
    DIRECTION OUTPUT ;
    USE SIGNAL ;
    PORT
      LAYER M4 ;
        RECT  0 152.304 0.192 152.328 ;
    END
  END rout[663]
  PIN rout[664]
    DIRECTION OUTPUT ;
    USE SIGNAL ;
    PORT
      LAYER M4 ;
        RECT  0 152.208 0.192 152.232 ;
    END
  END rout[664]
  PIN rout[665]
    DIRECTION OUTPUT ;
    USE SIGNAL ;
    PORT
      LAYER M4 ;
        RECT  0 152.112 0.192 152.136 ;
    END
  END rout[665]
  PIN rout[666]
    DIRECTION OUTPUT ;
    USE SIGNAL ;
    PORT
      LAYER M4 ;
        RECT  0 152.016 0.192 152.04 ;
    END
  END rout[666]
  PIN rout[667]
    DIRECTION OUTPUT ;
    USE SIGNAL ;
    PORT
      LAYER M4 ;
        RECT  0 151.92 0.192 151.944 ;
    END
  END rout[667]
  PIN rout[668]
    DIRECTION OUTPUT ;
    USE SIGNAL ;
    PORT
      LAYER M4 ;
        RECT  0 151.824 0.192 151.848 ;
    END
  END rout[668]
  PIN rout[669]
    DIRECTION OUTPUT ;
    USE SIGNAL ;
    PORT
      LAYER M4 ;
        RECT  0 151.728 0.192 151.752 ;
    END
  END rout[669]
  PIN rout[66]
    DIRECTION OUTPUT ;
    USE SIGNAL ;
    PORT
      LAYER M4 ;
        RECT  0 209.616 0.192 209.64 ;
    END
  END rout[66]
  PIN rout[670]
    DIRECTION OUTPUT ;
    USE SIGNAL ;
    PORT
      LAYER M4 ;
        RECT  0 151.632 0.192 151.656 ;
    END
  END rout[670]
  PIN rout[671]
    DIRECTION OUTPUT ;
    USE SIGNAL ;
    PORT
      LAYER M4 ;
        RECT  0 151.536 0.192 151.56 ;
    END
  END rout[671]
  PIN rout[672]
    DIRECTION OUTPUT ;
    USE SIGNAL ;
    PORT
      LAYER M4 ;
        RECT  0 151.44 0.192 151.464 ;
    END
  END rout[672]
  PIN rout[673]
    DIRECTION OUTPUT ;
    USE SIGNAL ;
    PORT
      LAYER M4 ;
        RECT  0 151.344 0.192 151.368 ;
    END
  END rout[673]
  PIN rout[674]
    DIRECTION OUTPUT ;
    USE SIGNAL ;
    PORT
      LAYER M4 ;
        RECT  0 151.248 0.192 151.272 ;
    END
  END rout[674]
  PIN rout[675]
    DIRECTION OUTPUT ;
    USE SIGNAL ;
    PORT
      LAYER M4 ;
        RECT  0 151.152 0.192 151.176 ;
    END
  END rout[675]
  PIN rout[676]
    DIRECTION OUTPUT ;
    USE SIGNAL ;
    PORT
      LAYER M4 ;
        RECT  0 151.056 0.192 151.08 ;
    END
  END rout[676]
  PIN rout[677]
    DIRECTION OUTPUT ;
    USE SIGNAL ;
    PORT
      LAYER M4 ;
        RECT  0 150.96 0.192 150.984 ;
    END
  END rout[677]
  PIN rout[678]
    DIRECTION OUTPUT ;
    USE SIGNAL ;
    PORT
      LAYER M4 ;
        RECT  0 150.864 0.192 150.888 ;
    END
  END rout[678]
  PIN rout[679]
    DIRECTION OUTPUT ;
    USE SIGNAL ;
    PORT
      LAYER M4 ;
        RECT  0 150.768 0.192 150.792 ;
    END
  END rout[679]
  PIN rout[67]
    DIRECTION OUTPUT ;
    USE SIGNAL ;
    PORT
      LAYER M4 ;
        RECT  0 209.52 0.192 209.544 ;
    END
  END rout[67]
  PIN rout[680]
    DIRECTION OUTPUT ;
    USE SIGNAL ;
    PORT
      LAYER M4 ;
        RECT  0 150.672 0.192 150.696 ;
    END
  END rout[680]
  PIN rout[681]
    DIRECTION OUTPUT ;
    USE SIGNAL ;
    PORT
      LAYER M4 ;
        RECT  0 150.576 0.192 150.6 ;
    END
  END rout[681]
  PIN rout[682]
    DIRECTION OUTPUT ;
    USE SIGNAL ;
    PORT
      LAYER M4 ;
        RECT  0 150.48 0.192 150.504 ;
    END
  END rout[682]
  PIN rout[683]
    DIRECTION OUTPUT ;
    USE SIGNAL ;
    PORT
      LAYER M4 ;
        RECT  0 150.384 0.192 150.408 ;
    END
  END rout[683]
  PIN rout[684]
    DIRECTION OUTPUT ;
    USE SIGNAL ;
    PORT
      LAYER M4 ;
        RECT  0 150.288 0.192 150.312 ;
    END
  END rout[684]
  PIN rout[685]
    DIRECTION OUTPUT ;
    USE SIGNAL ;
    PORT
      LAYER M4 ;
        RECT  0 150.192 0.192 150.216 ;
    END
  END rout[685]
  PIN rout[686]
    DIRECTION OUTPUT ;
    USE SIGNAL ;
    PORT
      LAYER M4 ;
        RECT  0 150.096 0.192 150.12 ;
    END
  END rout[686]
  PIN rout[687]
    DIRECTION OUTPUT ;
    USE SIGNAL ;
    PORT
      LAYER M4 ;
        RECT  0 150 0.192 150.024 ;
    END
  END rout[687]
  PIN rout[688]
    DIRECTION OUTPUT ;
    USE SIGNAL ;
    PORT
      LAYER M4 ;
        RECT  0 149.904 0.192 149.928 ;
    END
  END rout[688]
  PIN rout[689]
    DIRECTION OUTPUT ;
    USE SIGNAL ;
    PORT
      LAYER M4 ;
        RECT  0 149.808 0.192 149.832 ;
    END
  END rout[689]
  PIN rout[68]
    DIRECTION OUTPUT ;
    USE SIGNAL ;
    PORT
      LAYER M4 ;
        RECT  0 209.424 0.192 209.448 ;
    END
  END rout[68]
  PIN rout[690]
    DIRECTION OUTPUT ;
    USE SIGNAL ;
    PORT
      LAYER M4 ;
        RECT  0 149.712 0.192 149.736 ;
    END
  END rout[690]
  PIN rout[691]
    DIRECTION OUTPUT ;
    USE SIGNAL ;
    PORT
      LAYER M4 ;
        RECT  0 149.616 0.192 149.64 ;
    END
  END rout[691]
  PIN rout[692]
    DIRECTION OUTPUT ;
    USE SIGNAL ;
    PORT
      LAYER M4 ;
        RECT  0 149.52 0.192 149.544 ;
    END
  END rout[692]
  PIN rout[693]
    DIRECTION OUTPUT ;
    USE SIGNAL ;
    PORT
      LAYER M4 ;
        RECT  0 149.424 0.192 149.448 ;
    END
  END rout[693]
  PIN rout[694]
    DIRECTION OUTPUT ;
    USE SIGNAL ;
    PORT
      LAYER M4 ;
        RECT  0 149.328 0.192 149.352 ;
    END
  END rout[694]
  PIN rout[695]
    DIRECTION OUTPUT ;
    USE SIGNAL ;
    PORT
      LAYER M4 ;
        RECT  0 149.232 0.192 149.256 ;
    END
  END rout[695]
  PIN rout[696]
    DIRECTION OUTPUT ;
    USE SIGNAL ;
    PORT
      LAYER M4 ;
        RECT  0 149.136 0.192 149.16 ;
    END
  END rout[696]
  PIN rout[697]
    DIRECTION OUTPUT ;
    USE SIGNAL ;
    PORT
      LAYER M4 ;
        RECT  0 149.04 0.192 149.064 ;
    END
  END rout[697]
  PIN rout[698]
    DIRECTION OUTPUT ;
    USE SIGNAL ;
    PORT
      LAYER M4 ;
        RECT  0 148.944 0.192 148.968 ;
    END
  END rout[698]
  PIN rout[699]
    DIRECTION OUTPUT ;
    USE SIGNAL ;
    PORT
      LAYER M4 ;
        RECT  0 148.848 0.192 148.872 ;
    END
  END rout[699]
  PIN rout[69]
    DIRECTION OUTPUT ;
    USE SIGNAL ;
    PORT
      LAYER M4 ;
        RECT  0 209.328 0.192 209.352 ;
    END
  END rout[69]
  PIN rout[6]
    DIRECTION OUTPUT ;
    USE SIGNAL ;
    PORT
      LAYER M4 ;
        RECT  0 215.376 0.192 215.4 ;
    END
  END rout[6]
  PIN rout[700]
    DIRECTION OUTPUT ;
    USE SIGNAL ;
    PORT
      LAYER M4 ;
        RECT  0 148.752 0.192 148.776 ;
    END
  END rout[700]
  PIN rout[701]
    DIRECTION OUTPUT ;
    USE SIGNAL ;
    PORT
      LAYER M4 ;
        RECT  0 148.656 0.192 148.68 ;
    END
  END rout[701]
  PIN rout[702]
    DIRECTION OUTPUT ;
    USE SIGNAL ;
    PORT
      LAYER M4 ;
        RECT  0 148.56 0.192 148.584 ;
    END
  END rout[702]
  PIN rout[703]
    DIRECTION OUTPUT ;
    USE SIGNAL ;
    PORT
      LAYER M4 ;
        RECT  0 148.464 0.192 148.488 ;
    END
  END rout[703]
  PIN rout[704]
    DIRECTION OUTPUT ;
    USE SIGNAL ;
    PORT
      LAYER M4 ;
        RECT  0 148.368 0.192 148.392 ;
    END
  END rout[704]
  PIN rout[705]
    DIRECTION OUTPUT ;
    USE SIGNAL ;
    PORT
      LAYER M4 ;
        RECT  0 148.272 0.192 148.296 ;
    END
  END rout[705]
  PIN rout[706]
    DIRECTION OUTPUT ;
    USE SIGNAL ;
    PORT
      LAYER M4 ;
        RECT  0 148.176 0.192 148.2 ;
    END
  END rout[706]
  PIN rout[707]
    DIRECTION OUTPUT ;
    USE SIGNAL ;
    PORT
      LAYER M4 ;
        RECT  0 148.08 0.192 148.104 ;
    END
  END rout[707]
  PIN rout[708]
    DIRECTION OUTPUT ;
    USE SIGNAL ;
    PORT
      LAYER M4 ;
        RECT  0 147.984 0.192 148.008 ;
    END
  END rout[708]
  PIN rout[709]
    DIRECTION OUTPUT ;
    USE SIGNAL ;
    PORT
      LAYER M4 ;
        RECT  0 147.888 0.192 147.912 ;
    END
  END rout[709]
  PIN rout[70]
    DIRECTION OUTPUT ;
    USE SIGNAL ;
    PORT
      LAYER M4 ;
        RECT  0 209.232 0.192 209.256 ;
    END
  END rout[70]
  PIN rout[710]
    DIRECTION OUTPUT ;
    USE SIGNAL ;
    PORT
      LAYER M4 ;
        RECT  0 147.792 0.192 147.816 ;
    END
  END rout[710]
  PIN rout[711]
    DIRECTION OUTPUT ;
    USE SIGNAL ;
    PORT
      LAYER M4 ;
        RECT  0 147.696 0.192 147.72 ;
    END
  END rout[711]
  PIN rout[712]
    DIRECTION OUTPUT ;
    USE SIGNAL ;
    PORT
      LAYER M4 ;
        RECT  0 147.6 0.192 147.624 ;
    END
  END rout[712]
  PIN rout[713]
    DIRECTION OUTPUT ;
    USE SIGNAL ;
    PORT
      LAYER M4 ;
        RECT  0 147.504 0.192 147.528 ;
    END
  END rout[713]
  PIN rout[714]
    DIRECTION OUTPUT ;
    USE SIGNAL ;
    PORT
      LAYER M4 ;
        RECT  0 147.408 0.192 147.432 ;
    END
  END rout[714]
  PIN rout[715]
    DIRECTION OUTPUT ;
    USE SIGNAL ;
    PORT
      LAYER M4 ;
        RECT  0 147.312 0.192 147.336 ;
    END
  END rout[715]
  PIN rout[716]
    DIRECTION OUTPUT ;
    USE SIGNAL ;
    PORT
      LAYER M4 ;
        RECT  0 147.216 0.192 147.24 ;
    END
  END rout[716]
  PIN rout[717]
    DIRECTION OUTPUT ;
    USE SIGNAL ;
    PORT
      LAYER M4 ;
        RECT  0 147.12 0.192 147.144 ;
    END
  END rout[717]
  PIN rout[718]
    DIRECTION OUTPUT ;
    USE SIGNAL ;
    PORT
      LAYER M4 ;
        RECT  0 147.024 0.192 147.048 ;
    END
  END rout[718]
  PIN rout[719]
    DIRECTION OUTPUT ;
    USE SIGNAL ;
    PORT
      LAYER M4 ;
        RECT  0 146.928 0.192 146.952 ;
    END
  END rout[719]
  PIN rout[71]
    DIRECTION OUTPUT ;
    USE SIGNAL ;
    PORT
      LAYER M4 ;
        RECT  0 209.136 0.192 209.16 ;
    END
  END rout[71]
  PIN rout[720]
    DIRECTION OUTPUT ;
    USE SIGNAL ;
    PORT
      LAYER M4 ;
        RECT  0 146.832 0.192 146.856 ;
    END
  END rout[720]
  PIN rout[721]
    DIRECTION OUTPUT ;
    USE SIGNAL ;
    PORT
      LAYER M4 ;
        RECT  0 146.736 0.192 146.76 ;
    END
  END rout[721]
  PIN rout[722]
    DIRECTION OUTPUT ;
    USE SIGNAL ;
    PORT
      LAYER M4 ;
        RECT  0 146.64 0.192 146.664 ;
    END
  END rout[722]
  PIN rout[723]
    DIRECTION OUTPUT ;
    USE SIGNAL ;
    PORT
      LAYER M4 ;
        RECT  0 146.544 0.192 146.568 ;
    END
  END rout[723]
  PIN rout[724]
    DIRECTION OUTPUT ;
    USE SIGNAL ;
    PORT
      LAYER M4 ;
        RECT  0 146.448 0.192 146.472 ;
    END
  END rout[724]
  PIN rout[725]
    DIRECTION OUTPUT ;
    USE SIGNAL ;
    PORT
      LAYER M4 ;
        RECT  0 146.352 0.192 146.376 ;
    END
  END rout[725]
  PIN rout[726]
    DIRECTION OUTPUT ;
    USE SIGNAL ;
    PORT
      LAYER M4 ;
        RECT  0 146.256 0.192 146.28 ;
    END
  END rout[726]
  PIN rout[727]
    DIRECTION OUTPUT ;
    USE SIGNAL ;
    PORT
      LAYER M4 ;
        RECT  0 146.16 0.192 146.184 ;
    END
  END rout[727]
  PIN rout[728]
    DIRECTION OUTPUT ;
    USE SIGNAL ;
    PORT
      LAYER M4 ;
        RECT  0 146.064 0.192 146.088 ;
    END
  END rout[728]
  PIN rout[729]
    DIRECTION OUTPUT ;
    USE SIGNAL ;
    PORT
      LAYER M4 ;
        RECT  0 145.968 0.192 145.992 ;
    END
  END rout[729]
  PIN rout[72]
    DIRECTION OUTPUT ;
    USE SIGNAL ;
    PORT
      LAYER M4 ;
        RECT  0 209.04 0.192 209.064 ;
    END
  END rout[72]
  PIN rout[730]
    DIRECTION OUTPUT ;
    USE SIGNAL ;
    PORT
      LAYER M4 ;
        RECT  0 145.872 0.192 145.896 ;
    END
  END rout[730]
  PIN rout[731]
    DIRECTION OUTPUT ;
    USE SIGNAL ;
    PORT
      LAYER M4 ;
        RECT  0 145.776 0.192 145.8 ;
    END
  END rout[731]
  PIN rout[732]
    DIRECTION OUTPUT ;
    USE SIGNAL ;
    PORT
      LAYER M4 ;
        RECT  0 145.68 0.192 145.704 ;
    END
  END rout[732]
  PIN rout[733]
    DIRECTION OUTPUT ;
    USE SIGNAL ;
    PORT
      LAYER M4 ;
        RECT  0 145.584 0.192 145.608 ;
    END
  END rout[733]
  PIN rout[734]
    DIRECTION OUTPUT ;
    USE SIGNAL ;
    PORT
      LAYER M4 ;
        RECT  0 145.488 0.192 145.512 ;
    END
  END rout[734]
  PIN rout[735]
    DIRECTION OUTPUT ;
    USE SIGNAL ;
    PORT
      LAYER M4 ;
        RECT  0 145.392 0.192 145.416 ;
    END
  END rout[735]
  PIN rout[736]
    DIRECTION OUTPUT ;
    USE SIGNAL ;
    PORT
      LAYER M4 ;
        RECT  0 145.296 0.192 145.32 ;
    END
  END rout[736]
  PIN rout[737]
    DIRECTION OUTPUT ;
    USE SIGNAL ;
    PORT
      LAYER M4 ;
        RECT  0 145.2 0.192 145.224 ;
    END
  END rout[737]
  PIN rout[738]
    DIRECTION OUTPUT ;
    USE SIGNAL ;
    PORT
      LAYER M4 ;
        RECT  0 145.104 0.192 145.128 ;
    END
  END rout[738]
  PIN rout[739]
    DIRECTION OUTPUT ;
    USE SIGNAL ;
    PORT
      LAYER M4 ;
        RECT  0 145.008 0.192 145.032 ;
    END
  END rout[739]
  PIN rout[73]
    DIRECTION OUTPUT ;
    USE SIGNAL ;
    PORT
      LAYER M4 ;
        RECT  0 208.944 0.192 208.968 ;
    END
  END rout[73]
  PIN rout[740]
    DIRECTION OUTPUT ;
    USE SIGNAL ;
    PORT
      LAYER M4 ;
        RECT  0 144.912 0.192 144.936 ;
    END
  END rout[740]
  PIN rout[741]
    DIRECTION OUTPUT ;
    USE SIGNAL ;
    PORT
      LAYER M4 ;
        RECT  0 144.816 0.192 144.84 ;
    END
  END rout[741]
  PIN rout[742]
    DIRECTION OUTPUT ;
    USE SIGNAL ;
    PORT
      LAYER M4 ;
        RECT  0 144.72 0.192 144.744 ;
    END
  END rout[742]
  PIN rout[743]
    DIRECTION OUTPUT ;
    USE SIGNAL ;
    PORT
      LAYER M4 ;
        RECT  0 144.624 0.192 144.648 ;
    END
  END rout[743]
  PIN rout[744]
    DIRECTION OUTPUT ;
    USE SIGNAL ;
    PORT
      LAYER M4 ;
        RECT  0 144.528 0.192 144.552 ;
    END
  END rout[744]
  PIN rout[745]
    DIRECTION OUTPUT ;
    USE SIGNAL ;
    PORT
      LAYER M4 ;
        RECT  0 144.432 0.192 144.456 ;
    END
  END rout[745]
  PIN rout[746]
    DIRECTION OUTPUT ;
    USE SIGNAL ;
    PORT
      LAYER M4 ;
        RECT  0 144.336 0.192 144.36 ;
    END
  END rout[746]
  PIN rout[747]
    DIRECTION OUTPUT ;
    USE SIGNAL ;
    PORT
      LAYER M4 ;
        RECT  0 144.24 0.192 144.264 ;
    END
  END rout[747]
  PIN rout[748]
    DIRECTION OUTPUT ;
    USE SIGNAL ;
    PORT
      LAYER M4 ;
        RECT  0 144.144 0.192 144.168 ;
    END
  END rout[748]
  PIN rout[749]
    DIRECTION OUTPUT ;
    USE SIGNAL ;
    PORT
      LAYER M4 ;
        RECT  0 144.048 0.192 144.072 ;
    END
  END rout[749]
  PIN rout[74]
    DIRECTION OUTPUT ;
    USE SIGNAL ;
    PORT
      LAYER M4 ;
        RECT  0 208.848 0.192 208.872 ;
    END
  END rout[74]
  PIN rout[750]
    DIRECTION OUTPUT ;
    USE SIGNAL ;
    PORT
      LAYER M4 ;
        RECT  0 143.952 0.192 143.976 ;
    END
  END rout[750]
  PIN rout[751]
    DIRECTION OUTPUT ;
    USE SIGNAL ;
    PORT
      LAYER M4 ;
        RECT  0 143.856 0.192 143.88 ;
    END
  END rout[751]
  PIN rout[752]
    DIRECTION OUTPUT ;
    USE SIGNAL ;
    PORT
      LAYER M4 ;
        RECT  0 143.76 0.192 143.784 ;
    END
  END rout[752]
  PIN rout[753]
    DIRECTION OUTPUT ;
    USE SIGNAL ;
    PORT
      LAYER M4 ;
        RECT  0 143.664 0.192 143.688 ;
    END
  END rout[753]
  PIN rout[754]
    DIRECTION OUTPUT ;
    USE SIGNAL ;
    PORT
      LAYER M4 ;
        RECT  0 143.568 0.192 143.592 ;
    END
  END rout[754]
  PIN rout[755]
    DIRECTION OUTPUT ;
    USE SIGNAL ;
    PORT
      LAYER M4 ;
        RECT  0 143.472 0.192 143.496 ;
    END
  END rout[755]
  PIN rout[756]
    DIRECTION OUTPUT ;
    USE SIGNAL ;
    PORT
      LAYER M4 ;
        RECT  0 143.376 0.192 143.4 ;
    END
  END rout[756]
  PIN rout[757]
    DIRECTION OUTPUT ;
    USE SIGNAL ;
    PORT
      LAYER M4 ;
        RECT  0 143.28 0.192 143.304 ;
    END
  END rout[757]
  PIN rout[758]
    DIRECTION OUTPUT ;
    USE SIGNAL ;
    PORT
      LAYER M4 ;
        RECT  0 143.184 0.192 143.208 ;
    END
  END rout[758]
  PIN rout[759]
    DIRECTION OUTPUT ;
    USE SIGNAL ;
    PORT
      LAYER M4 ;
        RECT  0 143.088 0.192 143.112 ;
    END
  END rout[759]
  PIN rout[75]
    DIRECTION OUTPUT ;
    USE SIGNAL ;
    PORT
      LAYER M4 ;
        RECT  0 208.752 0.192 208.776 ;
    END
  END rout[75]
  PIN rout[760]
    DIRECTION OUTPUT ;
    USE SIGNAL ;
    PORT
      LAYER M4 ;
        RECT  0 142.992 0.192 143.016 ;
    END
  END rout[760]
  PIN rout[761]
    DIRECTION OUTPUT ;
    USE SIGNAL ;
    PORT
      LAYER M4 ;
        RECT  0 142.896 0.192 142.92 ;
    END
  END rout[761]
  PIN rout[762]
    DIRECTION OUTPUT ;
    USE SIGNAL ;
    PORT
      LAYER M4 ;
        RECT  0 142.8 0.192 142.824 ;
    END
  END rout[762]
  PIN rout[763]
    DIRECTION OUTPUT ;
    USE SIGNAL ;
    PORT
      LAYER M4 ;
        RECT  0 142.704 0.192 142.728 ;
    END
  END rout[763]
  PIN rout[764]
    DIRECTION OUTPUT ;
    USE SIGNAL ;
    PORT
      LAYER M4 ;
        RECT  0 142.608 0.192 142.632 ;
    END
  END rout[764]
  PIN rout[765]
    DIRECTION OUTPUT ;
    USE SIGNAL ;
    PORT
      LAYER M4 ;
        RECT  0 142.512 0.192 142.536 ;
    END
  END rout[765]
  PIN rout[766]
    DIRECTION OUTPUT ;
    USE SIGNAL ;
    PORT
      LAYER M4 ;
        RECT  0 142.416 0.192 142.44 ;
    END
  END rout[766]
  PIN rout[767]
    DIRECTION OUTPUT ;
    USE SIGNAL ;
    PORT
      LAYER M4 ;
        RECT  0 142.32 0.192 142.344 ;
    END
  END rout[767]
  PIN rout[768]
    DIRECTION OUTPUT ;
    USE SIGNAL ;
    PORT
      LAYER M4 ;
        RECT  0 142.224 0.192 142.248 ;
    END
  END rout[768]
  PIN rout[769]
    DIRECTION OUTPUT ;
    USE SIGNAL ;
    PORT
      LAYER M4 ;
        RECT  0 142.128 0.192 142.152 ;
    END
  END rout[769]
  PIN rout[76]
    DIRECTION OUTPUT ;
    USE SIGNAL ;
    PORT
      LAYER M4 ;
        RECT  0 208.656 0.192 208.68 ;
    END
  END rout[76]
  PIN rout[770]
    DIRECTION OUTPUT ;
    USE SIGNAL ;
    PORT
      LAYER M4 ;
        RECT  0 142.032 0.192 142.056 ;
    END
  END rout[770]
  PIN rout[771]
    DIRECTION OUTPUT ;
    USE SIGNAL ;
    PORT
      LAYER M4 ;
        RECT  0 141.936 0.192 141.96 ;
    END
  END rout[771]
  PIN rout[772]
    DIRECTION OUTPUT ;
    USE SIGNAL ;
    PORT
      LAYER M4 ;
        RECT  0 141.84 0.192 141.864 ;
    END
  END rout[772]
  PIN rout[773]
    DIRECTION OUTPUT ;
    USE SIGNAL ;
    PORT
      LAYER M4 ;
        RECT  0 141.744 0.192 141.768 ;
    END
  END rout[773]
  PIN rout[774]
    DIRECTION OUTPUT ;
    USE SIGNAL ;
    PORT
      LAYER M4 ;
        RECT  0 141.648 0.192 141.672 ;
    END
  END rout[774]
  PIN rout[775]
    DIRECTION OUTPUT ;
    USE SIGNAL ;
    PORT
      LAYER M4 ;
        RECT  0 141.552 0.192 141.576 ;
    END
  END rout[775]
  PIN rout[776]
    DIRECTION OUTPUT ;
    USE SIGNAL ;
    PORT
      LAYER M4 ;
        RECT  0 141.456 0.192 141.48 ;
    END
  END rout[776]
  PIN rout[777]
    DIRECTION OUTPUT ;
    USE SIGNAL ;
    PORT
      LAYER M4 ;
        RECT  0 141.36 0.192 141.384 ;
    END
  END rout[777]
  PIN rout[778]
    DIRECTION OUTPUT ;
    USE SIGNAL ;
    PORT
      LAYER M4 ;
        RECT  0 141.264 0.192 141.288 ;
    END
  END rout[778]
  PIN rout[779]
    DIRECTION OUTPUT ;
    USE SIGNAL ;
    PORT
      LAYER M4 ;
        RECT  0 141.168 0.192 141.192 ;
    END
  END rout[779]
  PIN rout[77]
    DIRECTION OUTPUT ;
    USE SIGNAL ;
    PORT
      LAYER M4 ;
        RECT  0 208.56 0.192 208.584 ;
    END
  END rout[77]
  PIN rout[780]
    DIRECTION OUTPUT ;
    USE SIGNAL ;
    PORT
      LAYER M4 ;
        RECT  0 141.072 0.192 141.096 ;
    END
  END rout[780]
  PIN rout[781]
    DIRECTION OUTPUT ;
    USE SIGNAL ;
    PORT
      LAYER M4 ;
        RECT  0 140.976 0.192 141 ;
    END
  END rout[781]
  PIN rout[782]
    DIRECTION OUTPUT ;
    USE SIGNAL ;
    PORT
      LAYER M4 ;
        RECT  0 140.88 0.192 140.904 ;
    END
  END rout[782]
  PIN rout[783]
    DIRECTION OUTPUT ;
    USE SIGNAL ;
    PORT
      LAYER M4 ;
        RECT  0 140.784 0.192 140.808 ;
    END
  END rout[783]
  PIN rout[784]
    DIRECTION OUTPUT ;
    USE SIGNAL ;
    PORT
      LAYER M4 ;
        RECT  0 140.688 0.192 140.712 ;
    END
  END rout[784]
  PIN rout[785]
    DIRECTION OUTPUT ;
    USE SIGNAL ;
    PORT
      LAYER M4 ;
        RECT  0 140.592 0.192 140.616 ;
    END
  END rout[785]
  PIN rout[786]
    DIRECTION OUTPUT ;
    USE SIGNAL ;
    PORT
      LAYER M4 ;
        RECT  0 140.496 0.192 140.52 ;
    END
  END rout[786]
  PIN rout[787]
    DIRECTION OUTPUT ;
    USE SIGNAL ;
    PORT
      LAYER M4 ;
        RECT  0 140.4 0.192 140.424 ;
    END
  END rout[787]
  PIN rout[788]
    DIRECTION OUTPUT ;
    USE SIGNAL ;
    PORT
      LAYER M4 ;
        RECT  0 140.304 0.192 140.328 ;
    END
  END rout[788]
  PIN rout[789]
    DIRECTION OUTPUT ;
    USE SIGNAL ;
    PORT
      LAYER M4 ;
        RECT  0 140.208 0.192 140.232 ;
    END
  END rout[789]
  PIN rout[78]
    DIRECTION OUTPUT ;
    USE SIGNAL ;
    PORT
      LAYER M4 ;
        RECT  0 208.464 0.192 208.488 ;
    END
  END rout[78]
  PIN rout[790]
    DIRECTION OUTPUT ;
    USE SIGNAL ;
    PORT
      LAYER M4 ;
        RECT  0 140.112 0.192 140.136 ;
    END
  END rout[790]
  PIN rout[791]
    DIRECTION OUTPUT ;
    USE SIGNAL ;
    PORT
      LAYER M4 ;
        RECT  0 140.016 0.192 140.04 ;
    END
  END rout[791]
  PIN rout[792]
    DIRECTION OUTPUT ;
    USE SIGNAL ;
    PORT
      LAYER M4 ;
        RECT  0 139.92 0.192 139.944 ;
    END
  END rout[792]
  PIN rout[793]
    DIRECTION OUTPUT ;
    USE SIGNAL ;
    PORT
      LAYER M4 ;
        RECT  0 139.824 0.192 139.848 ;
    END
  END rout[793]
  PIN rout[794]
    DIRECTION OUTPUT ;
    USE SIGNAL ;
    PORT
      LAYER M4 ;
        RECT  0 139.728 0.192 139.752 ;
    END
  END rout[794]
  PIN rout[795]
    DIRECTION OUTPUT ;
    USE SIGNAL ;
    PORT
      LAYER M4 ;
        RECT  0 139.632 0.192 139.656 ;
    END
  END rout[795]
  PIN rout[796]
    DIRECTION OUTPUT ;
    USE SIGNAL ;
    PORT
      LAYER M4 ;
        RECT  0 139.536 0.192 139.56 ;
    END
  END rout[796]
  PIN rout[797]
    DIRECTION OUTPUT ;
    USE SIGNAL ;
    PORT
      LAYER M4 ;
        RECT  0 139.44 0.192 139.464 ;
    END
  END rout[797]
  PIN rout[798]
    DIRECTION OUTPUT ;
    USE SIGNAL ;
    PORT
      LAYER M4 ;
        RECT  0 139.344 0.192 139.368 ;
    END
  END rout[798]
  PIN rout[799]
    DIRECTION OUTPUT ;
    USE SIGNAL ;
    PORT
      LAYER M4 ;
        RECT  0 139.248 0.192 139.272 ;
    END
  END rout[799]
  PIN rout[79]
    DIRECTION OUTPUT ;
    USE SIGNAL ;
    PORT
      LAYER M4 ;
        RECT  0 208.368 0.192 208.392 ;
    END
  END rout[79]
  PIN rout[7]
    DIRECTION OUTPUT ;
    USE SIGNAL ;
    PORT
      LAYER M4 ;
        RECT  0 215.28 0.192 215.304 ;
    END
  END rout[7]
  PIN rout[800]
    DIRECTION OUTPUT ;
    USE SIGNAL ;
    PORT
      LAYER M4 ;
        RECT  0 139.152 0.192 139.176 ;
    END
  END rout[800]
  PIN rout[801]
    DIRECTION OUTPUT ;
    USE SIGNAL ;
    PORT
      LAYER M4 ;
        RECT  0 139.056 0.192 139.08 ;
    END
  END rout[801]
  PIN rout[802]
    DIRECTION OUTPUT ;
    USE SIGNAL ;
    PORT
      LAYER M4 ;
        RECT  0 138.96 0.192 138.984 ;
    END
  END rout[802]
  PIN rout[803]
    DIRECTION OUTPUT ;
    USE SIGNAL ;
    PORT
      LAYER M4 ;
        RECT  0 138.864 0.192 138.888 ;
    END
  END rout[803]
  PIN rout[804]
    DIRECTION OUTPUT ;
    USE SIGNAL ;
    PORT
      LAYER M4 ;
        RECT  0 138.768 0.192 138.792 ;
    END
  END rout[804]
  PIN rout[805]
    DIRECTION OUTPUT ;
    USE SIGNAL ;
    PORT
      LAYER M4 ;
        RECT  0 138.672 0.192 138.696 ;
    END
  END rout[805]
  PIN rout[806]
    DIRECTION OUTPUT ;
    USE SIGNAL ;
    PORT
      LAYER M4 ;
        RECT  0 138.576 0.192 138.6 ;
    END
  END rout[806]
  PIN rout[807]
    DIRECTION OUTPUT ;
    USE SIGNAL ;
    PORT
      LAYER M4 ;
        RECT  0 138.48 0.192 138.504 ;
    END
  END rout[807]
  PIN rout[808]
    DIRECTION OUTPUT ;
    USE SIGNAL ;
    PORT
      LAYER M4 ;
        RECT  0 138.384 0.192 138.408 ;
    END
  END rout[808]
  PIN rout[809]
    DIRECTION OUTPUT ;
    USE SIGNAL ;
    PORT
      LAYER M4 ;
        RECT  0 138.288 0.192 138.312 ;
    END
  END rout[809]
  PIN rout[80]
    DIRECTION OUTPUT ;
    USE SIGNAL ;
    PORT
      LAYER M4 ;
        RECT  0 208.272 0.192 208.296 ;
    END
  END rout[80]
  PIN rout[810]
    DIRECTION OUTPUT ;
    USE SIGNAL ;
    PORT
      LAYER M4 ;
        RECT  0 138.192 0.192 138.216 ;
    END
  END rout[810]
  PIN rout[811]
    DIRECTION OUTPUT ;
    USE SIGNAL ;
    PORT
      LAYER M4 ;
        RECT  0 138.096 0.192 138.12 ;
    END
  END rout[811]
  PIN rout[812]
    DIRECTION OUTPUT ;
    USE SIGNAL ;
    PORT
      LAYER M4 ;
        RECT  0 138 0.192 138.024 ;
    END
  END rout[812]
  PIN rout[813]
    DIRECTION OUTPUT ;
    USE SIGNAL ;
    PORT
      LAYER M4 ;
        RECT  0 137.904 0.192 137.928 ;
    END
  END rout[813]
  PIN rout[814]
    DIRECTION OUTPUT ;
    USE SIGNAL ;
    PORT
      LAYER M4 ;
        RECT  0 137.808 0.192 137.832 ;
    END
  END rout[814]
  PIN rout[815]
    DIRECTION OUTPUT ;
    USE SIGNAL ;
    PORT
      LAYER M4 ;
        RECT  0 137.712 0.192 137.736 ;
    END
  END rout[815]
  PIN rout[816]
    DIRECTION OUTPUT ;
    USE SIGNAL ;
    PORT
      LAYER M4 ;
        RECT  0 137.616 0.192 137.64 ;
    END
  END rout[816]
  PIN rout[817]
    DIRECTION OUTPUT ;
    USE SIGNAL ;
    PORT
      LAYER M4 ;
        RECT  0 137.52 0.192 137.544 ;
    END
  END rout[817]
  PIN rout[81]
    DIRECTION OUTPUT ;
    USE SIGNAL ;
    PORT
      LAYER M4 ;
        RECT  0 208.176 0.192 208.2 ;
    END
  END rout[81]
  PIN rout[82]
    DIRECTION OUTPUT ;
    USE SIGNAL ;
    PORT
      LAYER M4 ;
        RECT  0 208.08 0.192 208.104 ;
    END
  END rout[82]
  PIN rout[83]
    DIRECTION OUTPUT ;
    USE SIGNAL ;
    PORT
      LAYER M4 ;
        RECT  0 207.984 0.192 208.008 ;
    END
  END rout[83]
  PIN rout[84]
    DIRECTION OUTPUT ;
    USE SIGNAL ;
    PORT
      LAYER M4 ;
        RECT  0 207.888 0.192 207.912 ;
    END
  END rout[84]
  PIN rout[85]
    DIRECTION OUTPUT ;
    USE SIGNAL ;
    PORT
      LAYER M4 ;
        RECT  0 207.792 0.192 207.816 ;
    END
  END rout[85]
  PIN rout[86]
    DIRECTION OUTPUT ;
    USE SIGNAL ;
    PORT
      LAYER M4 ;
        RECT  0 207.696 0.192 207.72 ;
    END
  END rout[86]
  PIN rout[87]
    DIRECTION OUTPUT ;
    USE SIGNAL ;
    PORT
      LAYER M4 ;
        RECT  0 207.6 0.192 207.624 ;
    END
  END rout[87]
  PIN rout[88]
    DIRECTION OUTPUT ;
    USE SIGNAL ;
    PORT
      LAYER M4 ;
        RECT  0 207.504 0.192 207.528 ;
    END
  END rout[88]
  PIN rout[89]
    DIRECTION OUTPUT ;
    USE SIGNAL ;
    PORT
      LAYER M4 ;
        RECT  0 207.408 0.192 207.432 ;
    END
  END rout[89]
  PIN rout[8]
    DIRECTION OUTPUT ;
    USE SIGNAL ;
    PORT
      LAYER M4 ;
        RECT  0 215.184 0.192 215.208 ;
    END
  END rout[8]
  PIN rout[90]
    DIRECTION OUTPUT ;
    USE SIGNAL ;
    PORT
      LAYER M4 ;
        RECT  0 207.312 0.192 207.336 ;
    END
  END rout[90]
  PIN rout[91]
    DIRECTION OUTPUT ;
    USE SIGNAL ;
    PORT
      LAYER M4 ;
        RECT  0 207.216 0.192 207.24 ;
    END
  END rout[91]
  PIN rout[92]
    DIRECTION OUTPUT ;
    USE SIGNAL ;
    PORT
      LAYER M4 ;
        RECT  0 207.12 0.192 207.144 ;
    END
  END rout[92]
  PIN rout[93]
    DIRECTION OUTPUT ;
    USE SIGNAL ;
    PORT
      LAYER M4 ;
        RECT  0 207.024 0.192 207.048 ;
    END
  END rout[93]
  PIN rout[94]
    DIRECTION OUTPUT ;
    USE SIGNAL ;
    PORT
      LAYER M4 ;
        RECT  0 206.928 0.192 206.952 ;
    END
  END rout[94]
  PIN rout[95]
    DIRECTION OUTPUT ;
    USE SIGNAL ;
    PORT
      LAYER M4 ;
        RECT  0 206.832 0.192 206.856 ;
    END
  END rout[95]
  PIN rout[96]
    DIRECTION OUTPUT ;
    USE SIGNAL ;
    PORT
      LAYER M4 ;
        RECT  0 206.736 0.192 206.76 ;
    END
  END rout[96]
  PIN rout[97]
    DIRECTION OUTPUT ;
    USE SIGNAL ;
    PORT
      LAYER M4 ;
        RECT  0 206.64 0.192 206.664 ;
    END
  END rout[97]
  PIN rout[98]
    DIRECTION OUTPUT ;
    USE SIGNAL ;
    PORT
      LAYER M4 ;
        RECT  0 206.544 0.192 206.568 ;
    END
  END rout[98]
  PIN rout[99]
    DIRECTION OUTPUT ;
    USE SIGNAL ;
    PORT
      LAYER M4 ;
        RECT  0 206.448 0.192 206.472 ;
    END
  END rout[99]
  PIN rout[9]
    DIRECTION OUTPUT ;
    USE SIGNAL ;
    PORT
      LAYER M4 ;
        RECT  0 215.088 0.192 215.112 ;
    END
  END rout[9]
  PIN rst_a
    DIRECTION INPUT ;
    USE SIGNAL ;
    PORT
      LAYER M5 ;
        RECT  136.608 0 136.632 0.192 ;
    END
  END rst_a
  PIN VDD
    DIRECTION INOUT ;
    USE POWER ;
    PORT
      LAYER M6 ;
        RECT  0.468 208.52 215.532 208.808 ;
        RECT  0.468 197.72 215.532 198.008 ;
        RECT  0.468 186.92 215.532 187.208 ;
        RECT  0.468 176.12 215.532 176.408 ;
        RECT  0.468 165.32 215.532 165.608 ;
        RECT  0.468 154.52 215.532 154.808 ;
        RECT  0.468 143.72 215.532 144.008 ;
        RECT  0.468 132.92 215.532 133.208 ;
        RECT  0.468 122.12 215.532 122.408 ;
        RECT  0.468 111.32 215.532 111.608 ;
        RECT  0.468 100.52 215.532 100.808 ;
        RECT  0.468 89.72 215.532 90.008 ;
        RECT  0.468 78.92 215.532 79.208 ;
        RECT  0.468 68.12 215.532 68.408 ;
        RECT  0.468 57.32 215.532 57.608 ;
        RECT  0.468 46.52 215.532 46.808 ;
        RECT  0.468 35.72 215.532 36.008 ;
        RECT  0.468 24.92 215.532 25.208 ;
        RECT  0.468 14.12 215.532 14.408 ;
        RECT  0.468 3.32 215.532 3.608 ;
        RECT  0.468 215.604 215.532 215.892 ;
        RECT  0.468 0.108 215.532 0.396 ;
    END
  END VDD
  PIN VSS
    DIRECTION INOUT ;
    USE GROUND ;
    PORT
      LAYER M6 ;
        RECT  0.468 208.136 215.532 208.424 ;
        RECT  0.468 197.336 215.532 197.624 ;
        RECT  0.468 186.536 215.532 186.824 ;
        RECT  0.468 175.736 215.532 176.024 ;
        RECT  0.468 164.936 215.532 165.224 ;
        RECT  0.468 154.136 215.532 154.424 ;
        RECT  0.468 143.336 215.532 143.624 ;
        RECT  0.468 132.536 215.532 132.824 ;
        RECT  0.468 121.736 215.532 122.024 ;
        RECT  0.468 110.936 215.532 111.224 ;
        RECT  0.468 100.136 215.532 100.424 ;
        RECT  0.468 89.336 215.532 89.624 ;
        RECT  0.468 78.536 215.532 78.824 ;
        RECT  0.468 67.736 215.532 68.024 ;
        RECT  0.468 56.936 215.532 57.224 ;
        RECT  0.468 46.136 215.532 46.424 ;
        RECT  0.468 35.336 215.532 35.624 ;
        RECT  0.468 24.536 215.532 24.824 ;
        RECT  0.468 13.736 215.532 14.024 ;
        RECT  0.468 2.936 215.532 3.224 ;
        RECT  0.66 215.22 215.34 215.508 ;
        RECT  0.66 0.492 215.34 0.78 ;
    END
  END VSS
  OBS
    LAYER RVTN ;
     RECT  0 0 216.024 215.981 ;
    LAYER RVTP ;
     RECT  0 0 216.024 215.981 ;
    LAYER M1 ;
     RECT  0 0 216.024 215.981 ;
    LAYER M2 ;
     RECT  0 0 216.024 215.981 ;
    LAYER M3 ;
     RECT  0 0 216.024 215.981 ;
    LAYER M4 ;
     RECT  0 0 216.024 215.981 ;
    LAYER M5 ;
     RECT  0 0 216.024 215.981 ;
    LAYER M6 ;
     RECT  0 0 216.024 215.981 ;
  END
END ot_hbm_accel_smh_fc_t
END LIBRARY
